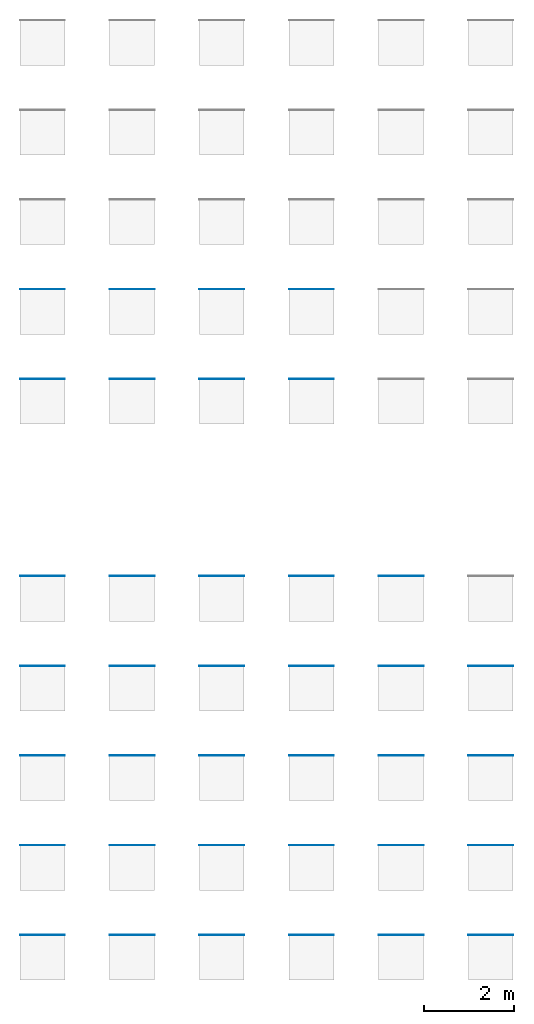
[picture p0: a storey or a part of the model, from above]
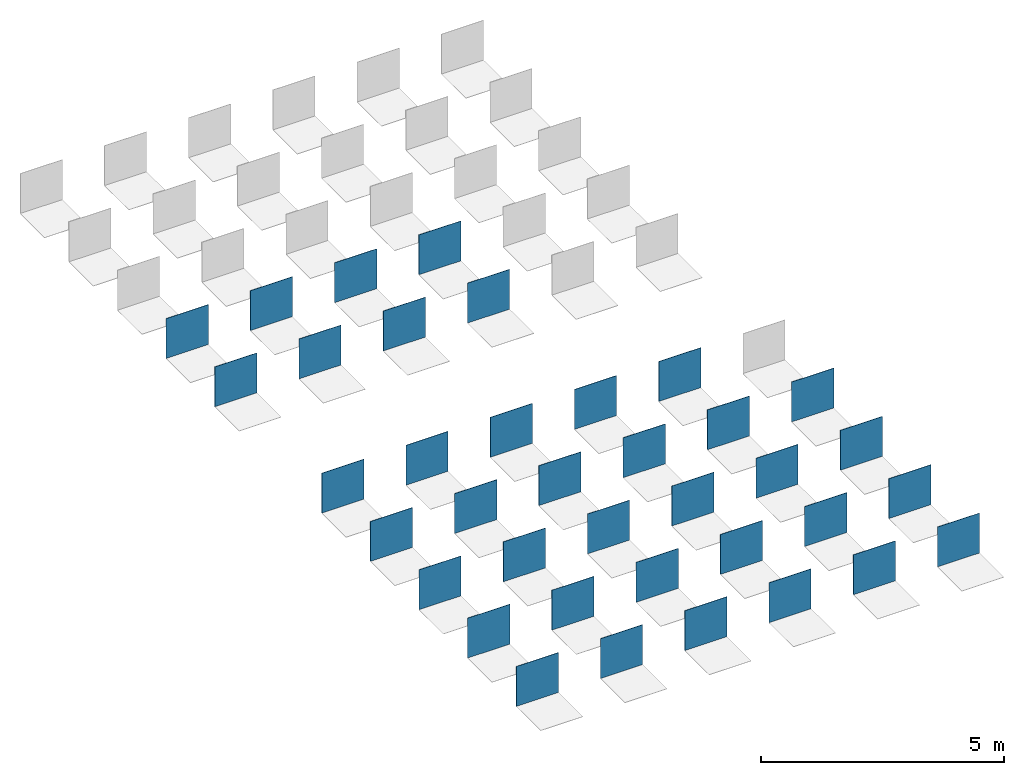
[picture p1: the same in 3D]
Properties of the parts of a building model (IFC2X3), part 1 of 8

# File
Description: ViewDefinition [CoordinationView_V2.0]
Time: 2025-06-20T14:48:53
Written by: The EXPRESS Data Manager Version 5.02.0100.07 : 28 Aug 2013
Made in: 21.1.90.15 - Exporter 21.1.90.15 - Alternate UI 21.1.90.15
Comment: STEP Physical File produced by: The EXPRESS Data Manager Version 5.02.0100.07 : 28 Aug 2013 * Module: EDMstepFileFactory/EDMstandAlone * Creation date: Fri Jun 20 14:48:53 2025 * Host: STB002 * Database: C:\Users\LARISS~1\AppData\Local\Temp\234e31d9-e186-458c-9206-d387dea7a233\94b8d80c-d76f-4e48-b2f8-2cca53b996f9\ifc * Database version: 5507 * Database creation date: Fri Jun 20 14:48:50 2025 * Schema: IFC2X3 * Model: DataRepository.ifc * Model creation date: Fri Jun 20 14:48:50 2025 * Header model: DataRepository.ifc_HeaderModel * Header model creation date: Fri Jun 20 14:48:50 2025 * EDMuser: sdai-user * EDMgroup: sdai-group * License ID and type: 5605 : Permanent license. Expiry date: * EDMstepFileFactory options: 020000

# IfcSite, Default
RefLatitude: 42, 24, 53, 508911; RefLongitude: -71, -15, -29, -58837; RefElevation: 0 mm
Pset_ProductRequirements - Category: Project Information

# IfcBuilding
Pset_BuildingCommon - NumberOfStoreys: 1
Pset_ProductRequirements - Category: Project Information

# IfcBuildingStorey: Level:Level 1, Level 1
LongName: Level 1; Elevation: 0 mm
Pset_AirSideSystemInformation - Name: Level 1
Pset_ProductRequirements - Name: Level 1; Category: Levels

# IfcCovering: Floor:REVIGRÉS-OMNISTONE-BASE-30X60-MATTRECT-BONE, Floor:REVIGRÉS-OMNISTONE-BASE-30X60-MATTRECT-BONE:146222
In: Level 1
Type - PredefinedType: CLADDING; Material: REVIGRÉS-OMNISTONE-BASE-30x60-MATTRECT-BONE 9.8 mm
Type - Pset_CoveringCommon - Reference: 312B2188U1; Material: Grés porcelânico
Type - Pset_ElementShading - Roughness: 304.8 mm
Type - Pset_ManufacturerTypeInformation - Manufacturer: REVIGRÉS
Type - Pset_ProductRequirements - Category: Floors
Type - Pset_QuantityTakeOff - Reference: 312B2188U1
Type - IFC.REVIGRÉS-Dados do fabricante-Floor Covering - FabricanteURL: https://www.revigres.pt/; ReferenciaModelo: Omnistone; NumeroGlobalDeItemComercial: 312B2188U1; Acabamento: MATT RECT; Material: Grés porcelânico; IdentificadorDoOperadorEconomico: 501840856; UrlFabricanteArtigo: https://www.revigres.pt/colecoes/omnistone; PaisOrigem: Portugal
Type - IFC.REVIGRÉS-Dados de desempenho-Floor Covering - Rectilinearidade: ± 0.2% máx.± 0.8 mm; Ortogonalidade: ± 0.2% máx.± 1.5 mm; PlanaridadeDaSuperficie: ± 0.3% máx. ± 1.8 mm; QualidadeDaSuperficie: Cumpre; AbsorcaoDeAgua: < 0.05%; ModuloDeRuptura: > 45 N/mm²; ResistenciaAFlexao: ≥ 3500 N; ResistenciaAAbrasaoProfunda: < 120 mm³; DilatacaoTermicaLinear: ≤ 8,0x10-6 °C-1; ResistenciaAoChoqueTermico: Resiste; DurabilidadeResistenciaAoGeloDegelo: Resiste; ResistenciaAoEscorregamentoDIN51130: R10; ResistenciaAoEscorregamentoDIN51097: B; ResistenciaAoEscorregamentoENV51097: B; ResistenciaAoEscorregamentoENV12633: Class 2; ResistenciaAoEscorregamentoBS7976: >36; ResistenciaAoEscorregamentoANSIA1371: ≥0,42; ResistenciaAoDeslizamentoENV12633: Class 2; ResistenciaAoDeslizamentoBS7976: >36; ResistenciaAsManchas: Class 5; ResistenciaABaixasConcentracoesDeAcidosEAlcalis: Classe LA; ResistenciaAAltasConcentracoesDeAcidosEAlcalis: Classe HA; LibertacaoDeCadmio: 0; LibertacaoDeChumbo: 0
Type - IFC.REVIGRÉS-Dados de especificação-Floor Covering - VariacaoTonalidade: 3; NivelDeTrafego: 5; EPavimento: Sim; ERevestimento: Sim; EExterno: Sim
Type - IFC.REVIGRÉS-Dados geométricos-Floor Covering - AlturaNominal: 9.8 mm; ComprimentoNominal: 29.5 mm; LarguraNominal: 59.2 mm
Type - IFC.REVIGRÉS-Dados de sustentabilidade-Floor Covering - ItemEParcialmenteReciclado: 0; EnergiaTermicaExportada: 0; ItemENovo: Sim; ItemEReciclado: Não; VidaÚtilEsperada: 50; SubstanciasPerigosas: Não; PotencialDeEsgotamentoAbioticoDosRecursosNaoFosseisMineraisEMetais: 0.000701; PotencialDeAquecimentoGlobalBiogenico: -0.48; CombustiveisFosseisComPotencialDeAquecimentoGlobal: 13.9; PotencialDeAquecimentoGlobalUsoDoSoloEMudancaDeUsoDoSolo: 0.0246; PotencialDeEutrofizacaoFraccaoDeNutrientesQueAtingemOCompartimentoFinalDeAguaDoce: 0.000189; PotencialDeEutrofizacaoFraccaoDeNutrientesQueAtingemOCompartimentoFinalMarinho: 0.0122; EnergiaRecuperada: 0.00739; ConsumoDeAguaDoce: 0.113; UtilizacaoLiquidaDeAguaDoce: 0.113; ResiduosPerigososEliminados: 0.00221; ResiduosNaoPerigososEliminados: 1.83; MassaTotalDeResiduosRadioactivosEliminados: 0.000394; EnergiaElectricaExportada: 1.55; MateriaisParaRecuperacaoDeEnergia: 0.00739; MateriaisParaReciclagem: 0.0253; UnidadeEPD: 1 m²
Type - IFC.REVIGRÉS-Dados gerais-Floor Covering - Nome: REVIGRÉS-OMNISTONE-BASE-30X60-MATT RECT-BONE; TipoProduto: Prensado a seco: grupo BIa UGL | Grés porcelânico técnico; NumeroDeRegistoDAP: EPD-REV-20240006-CCC1-EN; ReferenciaDAP: -; UrlDOP: -
Classification: C3020 (Uniformat)
Pset_CoveringCommon - TotalThickness: 9.8 mm
IFC.REVIGRÉS-Dados do fabricante-Floor Covering - Type: Floor: REVIGRÉS-OMNISTONE-BASE-30X60-MATTRECT-BONE
IFC.REVIGRÉS-Dados de desempenho-Floor Covering - Type: Floor: REVIGRÉS-OMNISTONE-BASE-30X60-MATTRECT-BONE
IFC.REVIGRÉS-Dados de especificação-Floor Covering - Type: Floor: REVIGRÉS-OMNISTONE-BASE-30X60-MATTRECT-BONE
IFC.REVIGRÉS-Dados geométricos-Floor Covering - Type: Floor: REVIGRÉS-OMNISTONE-BASE-30X60-MATTRECT-BONE
IFC.REVIGRÉS-Dados de sustentabilidade-Floor Covering - Type: Floor: REVIGRÉS-OMNISTONE-BASE-30X60-MATTRECT-BONE

# IfcCovering: Floor:REVIGRÉS-OMNISTONE-BASE-30X60-MATTRECT-ICE, Floor:REVIGRÉS-OMNISTONE-BASE-30X60-MATTRECT-ICE:148426
In: Level 1
Type - PredefinedType: CLADDING; Material: REVIGRÉS-OMNISTONE-BASE-30x60-MATTRECT-ICE 9.8 mm
Type - Pset_CoveringCommon - Reference: 312B2189U1; Material: Grés porcelânico
Type - Pset_ElementShading - Roughness: 304.8 mm
Type - Pset_ManufacturerTypeInformation - Manufacturer: REVIGRÉS
Type - Pset_ProductRequirements - Category: Floors
Type - Pset_QuantityTakeOff - Reference: 312B2189U1
Type - IFC.REVIGRÉS-Dados do fabricante-Floor Covering - FabricanteURL: https://www.revigres.pt/; ReferenciaModelo: Omnistone; NumeroGlobalDeItemComercial: 312B2189U1; Acabamento: MATT RECT; Material: Grés porcelânico; IdentificadorDoOperadorEconomico: 501840856; UrlFabricanteArtigo: https://www.revigres.pt/colecoes/omnistone; PaisOrigem: Portugal
Type - IFC.REVIGRÉS-Dados de desempenho-Floor Covering - Rectilinearidade: ± 0.2% máx.± 0.8 mm; Ortogonalidade: ± 0.2% máx.± 1.5 mm; PlanaridadeDaSuperficie: ± 0.3% máx. ± 1.8 mm; QualidadeDaSuperficie: Cumpre; AbsorcaoDeAgua: < 0.05%; ModuloDeRuptura: > 45 N/mm²; ResistenciaAFlexao: ≥ 3500 N; ResistenciaAAbrasaoProfunda: < 120 mm³; DilatacaoTermicaLinear: ≤ 8,0x10-6 °C-1; ResistenciaAoChoqueTermico: Resiste; DurabilidadeResistenciaAoGeloDegelo: Resiste; ResistenciaAoEscorregamentoDIN51130: R10; ResistenciaAoEscorregamentoDIN51097: B; ResistenciaAoEscorregamentoENV51097: B; ResistenciaAoEscorregamentoENV12633: Class 2; ResistenciaAoEscorregamentoBS7976: >36; ResistenciaAoEscorregamentoANSIA1371: ≥0,42; ResistenciaAoDeslizamentoENV12633: Class 2; ResistenciaAoDeslizamentoBS7976: >36; ResistenciaAsManchas: Class 5; ResistenciaABaixasConcentracoesDeAcidosEAlcalis: Classe LA; ResistenciaAAltasConcentracoesDeAcidosEAlcalis: Classe HA; LibertacaoDeCadmio: 0; LibertacaoDeChumbo: 0
Type - IFC.REVIGRÉS-Dados de especificação-Floor Covering - VariacaoTonalidade: 3; NivelDeTrafego: 5; EPavimento: Sim; ERevestimento: Sim; EExterno: Sim
Type - IFC.REVIGRÉS-Dados geométricos-Floor Covering - AlturaNominal: 9.8 mm; ComprimentoNominal: 29.5 mm; LarguraNominal: 59.2 mm
Type - IFC.REVIGRÉS-Dados de sustentabilidade-Floor Covering - ItemEParcialmenteReciclado: 0; EnergiaTermicaExportada: 0; ItemENovo: Sim; ItemEReciclado: Não; VidaÚtilEsperada: 50; SubstanciasPerigosas: Não; PotencialDeEsgotamentoAbioticoDosRecursosNaoFosseisMineraisEMetais: 0.000701; PotencialDeAquecimentoGlobalBiogenico: -0.48; CombustiveisFosseisComPotencialDeAquecimentoGlobal: 13.9; PotencialDeAquecimentoGlobalUsoDoSoloEMudancaDeUsoDoSolo: 0.0246; PotencialDeEutrofizacaoFraccaoDeNutrientesQueAtingemOCompartimentoFinalDeAguaDoce: 0.000189; PotencialDeEutrofizacaoFraccaoDeNutrientesQueAtingemOCompartimentoFinalMarinho: 0.0122; EnergiaRecuperada: 0.00739; ConsumoDeAguaDoce: 0.113; UtilizacaoLiquidaDeAguaDoce: 0.113; ResiduosPerigososEliminados: 0.00221; ResiduosNaoPerigososEliminados: 1.83; MassaTotalDeResiduosRadioactivosEliminados: 0.000394; EnergiaElectricaExportada: 1.55; MateriaisParaRecuperacaoDeEnergia: 0.00739; MateriaisParaReciclagem: 0.0253; UnidadeEPD: 1 m²
Type - IFC.REVIGRÉS-Dados gerais-Floor Covering - Nome: REVIGRÉS-OMNISTONE-BASE-30X60-MATT RECT-ICE; TipoProduto: Prensado a seco: grupo BIa UGL | Grés porcelânico técnico; NumeroDeRegistoDAP: EPD-REV-20240006-CCC1-EN; ReferenciaDAP: -; UrlDOP: -
Classification: C3020 (Uniformat)
Pset_CoveringCommon - TotalThickness: 9.8 mm
IFC.REVIGRÉS-Dados do fabricante-Floor Covering - Type: Floor: REVIGRÉS-OMNISTONE-BASE-30X60-MATTRECT-ICE
IFC.REVIGRÉS-Dados de desempenho-Floor Covering - Type: Floor: REVIGRÉS-OMNISTONE-BASE-30X60-MATTRECT-ICE
IFC.REVIGRÉS-Dados de especificação-Floor Covering - Type: Floor: REVIGRÉS-OMNISTONE-BASE-30X60-MATTRECT-ICE
IFC.REVIGRÉS-Dados geométricos-Floor Covering - Type: Floor: REVIGRÉS-OMNISTONE-BASE-30X60-MATTRECT-ICE
IFC.REVIGRÉS-Dados de sustentabilidade-Floor Covering - Type: Floor: REVIGRÉS-OMNISTONE-BASE-30X60-MATTRECT-ICE

# IfcCovering: Floor:REVIGRÉS-OMNISTONE-BASE-30X60-MATTRECT-IRON, Floor:REVIGRÉS-OMNISTONE-BASE-30X60-MATTRECT-IRON:149120
In: Level 1
Type - PredefinedType: CLADDING; Material: REVIGRÉS-OMNISTONE-BASE-30x60-MATTRECT-IRON 9.8 mm
Type - Pset_CoveringCommon - Reference: 312B2190U1; Material: Grés porcelânico
Type - Pset_ElementShading - Roughness: 304.8 mm
Type - Pset_ManufacturerTypeInformation - Manufacturer: REVIGRÉS
Type - Pset_ProductRequirements - Category: Floors
Type - Pset_QuantityTakeOff - Reference: 312B2190U1
Type - IFC.REVIGRÉS-Dados do fabricante-Floor Covering - FabricanteURL: https://www.revigres.pt/; ReferenciaModelo: Omnistone; NumeroGlobalDeItemComercial: 312B2190U1; Acabamento: MATT RECT; Material: Grés porcelânico; IdentificadorDoOperadorEconomico: 501840856; UrlFabricanteArtigo: https://www.revigres.pt/colecoes/omnistone; PaisOrigem: Portugal
Type - IFC.REVIGRÉS-Dados de desempenho-Floor Covering - Rectilinearidade: ± 0.2% máx.± 0.8 mm; Ortogonalidade: ± 0.2% máx.± 1.5 mm; PlanaridadeDaSuperficie: ± 0.3% máx. ± 1.8 mm; QualidadeDaSuperficie: Cumpre; AbsorcaoDeAgua: < 0.05%; ModuloDeRuptura: > 45 N/mm²; ResistenciaAFlexao: ≥ 3500 N; ResistenciaAAbrasaoProfunda: < 120 mm³; DilatacaoTermicaLinear: ≤ 8,0x10-6 °C-1; ResistenciaAoChoqueTermico: Resiste; DurabilidadeResistenciaAoGeloDegelo: Resiste; ResistenciaAoEscorregamentoDIN51130: R10; ResistenciaAoEscorregamentoDIN51097: B; ResistenciaAoEscorregamentoENV51097: B; ResistenciaAoEscorregamentoENV12633: Class 2; ResistenciaAoEscorregamentoBS7976: >36; ResistenciaAoEscorregamentoANSIA1371: ≥0,42; ResistenciaAoDeslizamentoENV12633: Class 2; ResistenciaAoDeslizamentoBS7976: >36; ResistenciaAsManchas: Class 5; ResistenciaABaixasConcentracoesDeAcidosEAlcalis: Classe LA; ResistenciaAAltasConcentracoesDeAcidosEAlcalis: Classe HA; LibertacaoDeCadmio: 0; LibertacaoDeChumbo: 0
Type - IFC.REVIGRÉS-Dados de especificação-Floor Covering - VariacaoTonalidade: 3; NivelDeTrafego: 5; EPavimento: Sim; ERevestimento: Sim; EExterno: Sim
Type - IFC.REVIGRÉS-Dados geométricos-Floor Covering - AlturaNominal: 9.8 mm; ComprimentoNominal: 29.5 mm; LarguraNominal: 59.2 mm
Type - IFC.REVIGRÉS-Dados de sustentabilidade-Floor Covering - EnergiaTermicaExportada: 0; ItemENovo: Sim; ItemEParcialmenteReciclado: 0.14; ItemEReciclado: Sim; VidaÚtilEsperada: 50; SubstanciasPerigosas: Não; PotencialDeEsgotamentoAbioticoDosRecursosNaoFosseisMineraisEMetais: 0.000701; PotencialDeAquecimentoGlobalBiogenico: -0.48; CombustiveisFosseisComPotencialDeAquecimentoGlobal: 13.9; PotencialDeAquecimentoGlobalUsoDoSoloEMudancaDeUsoDoSolo: 0.0246; PotencialDeEutrofizacaoFraccaoDeNutrientesQueAtingemOCompartimentoFinalDeAguaDoce: 0.000189; PotencialDeEutrofizacaoFraccaoDeNutrientesQueAtingemOCompartimentoFinalMarinho: 0.0122; EnergiaRecuperada: 0.00739; ConsumoDeAguaDoce: 0.113; UtilizacaoLiquidaDeAguaDoce: 0.113; ResiduosPerigososEliminados: 0.00221; ResiduosNaoPerigososEliminados: 1.83; MassaTotalDeResiduosRadioactivosEliminados: 0.000394; EnergiaElectricaExportada: 1.55; MateriaisParaRecuperacaoDeEnergia: 0.00739; MateriaisParaReciclagem: 0.0253; UnidadeEPD: 1 m²
Type - IFC.REVIGRÉS-Dados gerais-Floor Covering - Nome: REVIGRÉS-OMNISTONE-BASE-30X60-MATT RECT-IRON; TipoProduto: Prensado a seco: grupo BIa UGL | Grés porcelânico técnico; NumeroDeRegistoDAP: EPD-REV-20240006-CCC1-EN; ReferenciaDAP: -; UrlDOP: -
Classification: C3020 (Uniformat)
Pset_CoveringCommon - TotalThickness: 9.8 mm
IFC.REVIGRÉS-Dados do fabricante-Floor Covering - Type: Floor: REVIGRÉS-OMNISTONE-BASE-30X60-MATTRECT-IRON
IFC.REVIGRÉS-Dados de desempenho-Floor Covering - Type: Floor: REVIGRÉS-OMNISTONE-BASE-30X60-MATTRECT-IRON
IFC.REVIGRÉS-Dados de especificação-Floor Covering - Type: Floor: REVIGRÉS-OMNISTONE-BASE-30X60-MATTRECT-IRON
IFC.REVIGRÉS-Dados geométricos-Floor Covering - Type: Floor: REVIGRÉS-OMNISTONE-BASE-30X60-MATTRECT-IRON
IFC.REVIGRÉS-Dados de sustentabilidade-Floor Covering - Type: Floor: REVIGRÉS-OMNISTONE-BASE-30X60-MATTRECT-IRON

# IfcCovering: Floor:REVIGRÉS-OMNISTONE-BASE-30X60-MATTRECT-JET, Floor:REVIGRÉS-OMNISTONE-BASE-30X60-MATTRECT-JET:149862
In: Level 1
Type - PredefinedType: CLADDING; Material: REVIGRÉS-OMNISTONE-BASE-30x60-MATTRECT-JET 9.8 mm
Type - Pset_CoveringCommon - Reference: 312B2191U1; Material: Grés porcelânico
Type - Pset_ElementShading - Roughness: 304.8 mm
Type - Pset_ManufacturerTypeInformation - Manufacturer: REVIGRÉS
Type - Pset_ProductRequirements - Category: Floors
Type - Pset_QuantityTakeOff - Reference: 312B2191U1
Type - IFC.REVIGRÉS-Dados do fabricante-Floor Covering - FabricanteURL: https://www.revigres.pt/; ReferenciaModelo: Omnistone; NumeroGlobalDeItemComercial: 312B2191U1; Acabamento: MATT RECT; Material: Grés porcelânico; IdentificadorDoOperadorEconomico: 501840856; UrlFabricanteArtigo: https://www.revigres.pt/colecoes/omnistone; PaisOrigem: Portugal
Type - IFC.REVIGRÉS-Dados de desempenho-Floor Covering - Rectilinearidade: ± 0.2% máx.± 0.8 mm; Ortogonalidade: ± 0.2% máx.± 1.5 mm; PlanaridadeDaSuperficie: ± 0.3% máx. ± 1.8 mm; QualidadeDaSuperficie: Cumpre; AbsorcaoDeAgua: < 0.05%; ModuloDeRuptura: > 45 N/mm²; ResistenciaAFlexao: ≥ 3500 N; ResistenciaAAbrasaoProfunda: < 120 mm³; DilatacaoTermicaLinear: ≤ 8,0x10-6 °C-1; ResistenciaAoChoqueTermico: Resiste; DurabilidadeResistenciaAoGeloDegelo: Resiste; ResistenciaAoEscorregamentoDIN51130: R10; ResistenciaAoEscorregamentoDIN51097: B; ResistenciaAoEscorregamentoENV51097: B; ResistenciaAoEscorregamentoENV12633: Class 2; ResistenciaAoEscorregamentoBS7976: >36; ResistenciaAoEscorregamentoANSIA1371: ≥0,42; ResistenciaAoDeslizamentoENV12633: Class 2; ResistenciaAoDeslizamentoBS7976: >36; ResistenciaAsManchas: Class 5; ResistenciaABaixasConcentracoesDeAcidosEAlcalis: Classe LA; ResistenciaAAltasConcentracoesDeAcidosEAlcalis: Classe HA; LibertacaoDeCadmio: 0; LibertacaoDeChumbo: 0
Type - IFC.REVIGRÉS-Dados de especificação-Floor Covering - VariacaoTonalidade: 3; NivelDeTrafego: 5; EPavimento: Sim; ERevestimento: Sim; EExterno: Sim
Type - IFC.REVIGRÉS-Dados geométricos-Floor Covering - AlturaNominal: 9.8 mm; ComprimentoNominal: 29.5 mm; LarguraNominal: 59.2 mm
Type - IFC.REVIGRÉS-Dados de sustentabilidade-Floor Covering - ItemEParcialmenteReciclado: 0; EnergiaTermicaExportada: 0; ItemENovo: Sim; ItemEReciclado: Não; VidaÚtilEsperada: 50; SubstanciasPerigosas: Não; PotencialDeEsgotamentoAbioticoDosRecursosNaoFosseisMineraisEMetais: 0.000701; PotencialDeAquecimentoGlobalBiogenico: -0.48; CombustiveisFosseisComPotencialDeAquecimentoGlobal: 13.9; PotencialDeAquecimentoGlobalUsoDoSoloEMudancaDeUsoDoSolo: 0.0246; PotencialDeEutrofizacaoFraccaoDeNutrientesQueAtingemOCompartimentoFinalDeAguaDoce: 0.000189; PotencialDeEutrofizacaoFraccaoDeNutrientesQueAtingemOCompartimentoFinalMarinho: 0.0122; EnergiaRecuperada: 0.00739; ConsumoDeAguaDoce: 0.113; UtilizacaoLiquidaDeAguaDoce: 0.113; ResiduosPerigososEliminados: 0.00221; ResiduosNaoPerigososEliminados: 1.83; MassaTotalDeResiduosRadioactivosEliminados: 0.000394; EnergiaElectricaExportada: 1.55; MateriaisParaRecuperacaoDeEnergia: 0.00739; MateriaisParaReciclagem: 0.0253; UnidadeEPD: 1 m²
Type - IFC.REVIGRÉS-Dados gerais-Floor Covering - Nome: REVIGRÉS-OMNISTONE-BASE-30X60-MATT RECT-JET; TipoProduto: Prensado a seco: grupo BIa UGL | Grés porcelânico técnico; NumeroDeRegistoDAP: EPD-REV-20240006-CCC1-EN; ReferenciaDAP: -; UrlDOP: -
Classification: C3020 (Uniformat)
Pset_CoveringCommon - TotalThickness: 9.8 mm
IFC.REVIGRÉS-Dados do fabricante-Floor Covering - Type: Floor: REVIGRÉS-OMNISTONE-BASE-30X60-MATTRECT-JET
IFC.REVIGRÉS-Dados de desempenho-Floor Covering - Type: Floor: REVIGRÉS-OMNISTONE-BASE-30X60-MATTRECT-JET
IFC.REVIGRÉS-Dados de especificação-Floor Covering - Type: Floor: REVIGRÉS-OMNISTONE-BASE-30X60-MATTRECT-JET
IFC.REVIGRÉS-Dados geométricos-Floor Covering - Type: Floor: REVIGRÉS-OMNISTONE-BASE-30X60-MATTRECT-JET
IFC.REVIGRÉS-Dados de sustentabilidade-Floor Covering - Type: Floor: REVIGRÉS-OMNISTONE-BASE-30X60-MATTRECT-JET

# IfcCovering: Floor:REVIGRÉS-OMNISTONE-BASE-30X60-MATTRECT-PLATINA, Floor:REVIGRÉS-OMNISTONE-BASE-30X60-MATTRECT-PLATINA:150583
In: Level 1
Type - PredefinedType: CLADDING; Material: REVIGRÉS-OMNISTONE-BASE-30x60-MATTRECT-PLATINA 9.8 mm
Type - Pset_CoveringCommon - Reference: 312B2192U1; Material: Grés porcelânico
Type - Pset_ElementShading - Roughness: 304.8 mm
Type - Pset_ManufacturerTypeInformation - Manufacturer: REVIGRÉS
Type - Pset_ProductRequirements - Category: Floors
Type - Pset_QuantityTakeOff - Reference: 312B2192U1
Type - IFC.REVIGRÉS-Dados do fabricante-Floor Covering - FabricanteURL: https://www.revigres.pt/; ReferenciaModelo: Omnistone; NumeroGlobalDeItemComercial: 312B2192U1; Acabamento: MATT RECT; Material: Grés porcelânico; IdentificadorDoOperadorEconomico: 501840856; UrlFabricanteArtigo: https://www.revigres.pt/colecoes/omnistone; PaisOrigem: Portugal
Type - IFC.REVIGRÉS-Dados de desempenho-Floor Covering - Rectilinearidade: ± 0.2% máx.± 0.8 mm; Ortogonalidade: ± 0.2% máx.± 1.5 mm; PlanaridadeDaSuperficie: ± 0.3% máx. ± 1.8 mm; QualidadeDaSuperficie: Cumpre; AbsorcaoDeAgua: < 0.05%; ModuloDeRuptura: > 45 N/mm²; ResistenciaAFlexao: ≥ 3500 N; ResistenciaAAbrasaoProfunda: < 120 mm³; DilatacaoTermicaLinear: ≤ 8,0x10-6 °C-1; ResistenciaAoChoqueTermico: Resiste; DurabilidadeResistenciaAoGeloDegelo: Resiste; ResistenciaAoEscorregamentoDIN51130: R10; ResistenciaAoEscorregamentoDIN51097: B; ResistenciaAoEscorregamentoENV51097: B; ResistenciaAoEscorregamentoENV12633: Class 2; ResistenciaAoEscorregamentoBS7976: >36; ResistenciaAoEscorregamentoANSIA1371: ≥0,42; ResistenciaAoDeslizamentoENV12633: Class 2; ResistenciaAoDeslizamentoBS7976: >36; ResistenciaAsManchas: Class 5; ResistenciaABaixasConcentracoesDeAcidosEAlcalis: Classe LA; ResistenciaAAltasConcentracoesDeAcidosEAlcalis: Classe HA; LibertacaoDeCadmio: 0; LibertacaoDeChumbo: 0
Type - IFC.REVIGRÉS-Dados de especificação-Floor Covering - VariacaoTonalidade: 3; NivelDeTrafego: 5; EPavimento: Sim; ERevestimento: Sim; EExterno: Sim
Type - IFC.REVIGRÉS-Dados geométricos-Floor Covering - AlturaNominal: 9.8 mm; ComprimentoNominal: 29.5 mm; LarguraNominal: 59.2 mm
Type - IFC.REVIGRÉS-Dados de sustentabilidade-Floor Covering - ItemEParcialmenteReciclado: 0; EnergiaTermicaExportada: 0; ItemENovo: Sim; ItemEReciclado: Não; VidaÚtilEsperada: 50; SubstanciasPerigosas: Não; PotencialDeEsgotamentoAbioticoDosRecursosNaoFosseisMineraisEMetais: 0.000701; PotencialDeAquecimentoGlobalBiogenico: -0.48; CombustiveisFosseisComPotencialDeAquecimentoGlobal: 13.9; PotencialDeAquecimentoGlobalUsoDoSoloEMudancaDeUsoDoSolo: 0.0246; PotencialDeEutrofizacaoFraccaoDeNutrientesQueAtingemOCompartimentoFinalDeAguaDoce: 0.000189; PotencialDeEutrofizacaoFraccaoDeNutrientesQueAtingemOCompartimentoFinalMarinho: 0.0122; EnergiaRecuperada: 0.00739; ConsumoDeAguaDoce: 0.113; UtilizacaoLiquidaDeAguaDoce: 0.113; ResiduosPerigososEliminados: 0.00221; ResiduosNaoPerigososEliminados: 1.83; MassaTotalDeResiduosRadioactivosEliminados: 0.000394; EnergiaElectricaExportada: 1.55; MateriaisParaRecuperacaoDeEnergia: 0.00739; MateriaisParaReciclagem: 0.0253; UnidadeEPD: 1 m²
Type - IFC.REVIGRÉS-Dados gerais-Floor Covering - Nome: REVIGRÉS-OMNISTONE-BASE-30X60-MATT RECT-PLATINA; TipoProduto: Prensado a seco: grupo BIa UGL | Grés porcelânico técnico; NumeroDeRegistoDAP: EPD-REV-20240006-CCC1-EN; ReferenciaDAP: -; UrlDOP: -
Classification: C3020 (Uniformat)
Pset_CoveringCommon - TotalThickness: 9.8 mm
IFC.REVIGRÉS-Dados do fabricante-Floor Covering - Type: Floor: REVIGRÉS-OMNISTONE-BASE-30X60-MATTRECT-PLATINA
IFC.REVIGRÉS-Dados de desempenho-Floor Covering - Type: Floor: REVIGRÉS-OMNISTONE-BASE-30X60-MATTRECT-PLATINA
IFC.REVIGRÉS-Dados de especificação-Floor Covering - Type: Floor: REVIGRÉS-OMNISTONE-BASE-30X60-MATTRECT-PLATINA
IFC.REVIGRÉS-Dados geométricos-Floor Covering - Type: Floor: REVIGRÉS-OMNISTONE-BASE-30X60-MATTRECT-PLATINA
IFC.REVIGRÉS-Dados de sustentabilidade-Floor Covering - Type: Floor: REVIGRÉS-OMNISTONE-BASE-30X60-MATTRECT-PLATINA

# IfcCovering: Floor:REVIGRÉS-OMNISTONE-BASE-30X60-MATTRECT-ROPE, Floor:REVIGRÉS-OMNISTONE-BASE-30X60-MATTRECT-ROPE:151288
In: Level 1
Type - PredefinedType: CLADDING; Material: REVIGRÉS-OMNISTONE-BASE-30x60-MATTRECT-ROPE 9.8 mm
Type - Pset_CoveringCommon - Reference: 312B2193U1; Material: Grés porcelânico
Type - Pset_ElementShading - Roughness: 304.8 mm
Type - Pset_ManufacturerTypeInformation - Manufacturer: REVIGRÉS
Type - Pset_ProductRequirements - Category: Floors
Type - Pset_QuantityTakeOff - Reference: 312B2193U1
Type - IFC.REVIGRÉS-Dados do fabricante-Floor Covering - FabricanteURL: https://www.revigres.pt/; ReferenciaModelo: Omnistone; NumeroGlobalDeItemComercial: 312B2193U1; Acabamento: MATT RECT; Material: Grés porcelânico; IdentificadorDoOperadorEconomico: 501840856; UrlFabricanteArtigo: https://www.revigres.pt/colecoes/omnistone; PaisOrigem: Portugal
Type - IFC.REVIGRÉS-Dados de desempenho-Floor Covering - Rectilinearidade: ± 0.2% máx.± 0.8 mm; Ortogonalidade: ± 0.2% máx.± 1.5 mm; PlanaridadeDaSuperficie: ± 0.3% máx. ± 1.8 mm; QualidadeDaSuperficie: Cumpre; AbsorcaoDeAgua: < 0.05%; ModuloDeRuptura: > 45 N/mm²; ResistenciaAFlexao: ≥ 3500 N; ResistenciaAAbrasaoProfunda: < 120 mm³; DilatacaoTermicaLinear: ≤ 8,0x10-6 °C-1; ResistenciaAoChoqueTermico: Resiste; DurabilidadeResistenciaAoGeloDegelo: Resiste; ResistenciaAoEscorregamentoDIN51130: R10; ResistenciaAoEscorregamentoDIN51097: B; ResistenciaAoEscorregamentoENV51097: B; ResistenciaAoEscorregamentoENV12633: Class 2; ResistenciaAoEscorregamentoBS7976: >36; ResistenciaAoEscorregamentoANSIA1371: ≥0,42; ResistenciaAoDeslizamentoENV12633: Class 2; ResistenciaAoDeslizamentoBS7976: >36; ResistenciaAsManchas: Class 5; ResistenciaABaixasConcentracoesDeAcidosEAlcalis: Classe LA; ResistenciaAAltasConcentracoesDeAcidosEAlcalis: Classe HA; LibertacaoDeCadmio: 0; LibertacaoDeChumbo: 0
Type - IFC.REVIGRÉS-Dados de especificação-Floor Covering - VariacaoTonalidade: 3; NivelDeTrafego: 5; EPavimento: Sim; ERevestimento: Sim; EExterno: Sim
Type - IFC.REVIGRÉS-Dados geométricos-Floor Covering - AlturaNominal: 9.8 mm; ComprimentoNominal: 29.5 mm; LarguraNominal: 59.2 mm
Type - IFC.REVIGRÉS-Dados de sustentabilidade-Floor Covering - ItemEParcialmenteReciclado: 0; EnergiaTermicaExportada: 0; ItemENovo: Sim; ItemEReciclado: Não; VidaÚtilEsperada: 50; SubstanciasPerigosas: Não; PotencialDeEsgotamentoAbioticoDosRecursosNaoFosseisMineraisEMetais: 0.000701; PotencialDeAquecimentoGlobalBiogenico: -0.48; CombustiveisFosseisComPotencialDeAquecimentoGlobal: 13.9; PotencialDeAquecimentoGlobalUsoDoSoloEMudancaDeUsoDoSolo: 0.0246; PotencialDeEutrofizacaoFraccaoDeNutrientesQueAtingemOCompartimentoFinalDeAguaDoce: 0.000189; PotencialDeEutrofizacaoFraccaoDeNutrientesQueAtingemOCompartimentoFinalMarinho: 0.0122; EnergiaRecuperada: 0.00739; ConsumoDeAguaDoce: 0.113; UtilizacaoLiquidaDeAguaDoce: 0.113; ResiduosPerigososEliminados: 0.00221; ResiduosNaoPerigososEliminados: 1.83; MassaTotalDeResiduosRadioactivosEliminados: 0.000394; EnergiaElectricaExportada: 1.55; MateriaisParaRecuperacaoDeEnergia: 0.00739; MateriaisParaReciclagem: 0.0253; UnidadeEPD: 1 m²
Type - IFC.REVIGRÉS-Dados gerais-Floor Covering - Nome: REVIGRÉS-OMNISTONE-BASE-30X60-MATT RECT-ROPE; TipoProduto: Prensado a seco: grupo BIa UGL | Grés porcelânico técnico; NumeroDeRegistoDAP: EPD-REV-20240006-CCC1-EN; ReferenciaDAP: -; UrlDOP: -
Classification: C3020 (Uniformat)
Pset_CoveringCommon - TotalThickness: 9.8 mm
IFC.REVIGRÉS-Dados do fabricante-Floor Covering - Type: Floor: REVIGRÉS-OMNISTONE-BASE-30X60-MATTRECT-ROPE
IFC.REVIGRÉS-Dados de desempenho-Floor Covering - Type: Floor: REVIGRÉS-OMNISTONE-BASE-30X60-MATTRECT-ROPE
IFC.REVIGRÉS-Dados de especificação-Floor Covering - Type: Floor: REVIGRÉS-OMNISTONE-BASE-30X60-MATTRECT-ROPE
IFC.REVIGRÉS-Dados geométricos-Floor Covering - Type: Floor: REVIGRÉS-OMNISTONE-BASE-30X60-MATTRECT-ROPE
IFC.REVIGRÉS-Dados de sustentabilidade-Floor Covering - Type: Floor: REVIGRÉS-OMNISTONE-BASE-30X60-MATTRECT-ROPE

# IfcCovering: Floor:REVIGRÉS-OMNISTONE-BASE-30X60-SOFT-BONE, Floor:REVIGRÉS-OMNISTONE-BASE-30X60-SOFT-BONE:146506
In: Level 1
Type - PredefinedType: CLADDING; Material: REVIGRÉS-OMNISTONE-BASE-30x60-SOFT-BONE 9.8 mm
Type - Pset_CoveringCommon - Reference: 31262188U1; Material: Grés porcelânico
Type - Pset_ElementShading - Roughness: 304.8 mm
Type - Pset_ManufacturerTypeInformation - Manufacturer: REVIGRÉS
Type - Pset_ProductRequirements - Category: Floors
Type - Pset_QuantityTakeOff - Reference: 31262188U1
Type - IFC.REVIGRÉS-Dados do fabricante-Floor Covering - FabricanteURL: https://www.revigres.pt/; ReferenciaModelo: Omnistone; NumeroGlobalDeItemComercial: 31262188U1; Acabamento: SOFT; Material: Grés porcelânico; IdentificadorDoOperadorEconomico: 501840856; UrlFabricanteArtigo: https://www.revigres.pt/colecoes/omnistone; PaisOrigem: Portugal
Type - IFC.REVIGRÉS-Dados de desempenho-Floor Covering - Rectilinearidade: ± 0.2% máx.± 0.8 mm; Ortogonalidade: ± 0.2% máx.± 1.5 mm; PlanaridadeDaSuperficie: ± 0.3% máx. ± 1.8 mm; QualidadeDaSuperficie: Cumpre; AbsorcaoDeAgua: < 0.05%; ModuloDeRuptura: > 45 N/mm²; ResistenciaAFlexao: ≥ 3500 N; ResistenciaAAbrasaoProfunda: < 120 mm³; DilatacaoTermicaLinear: ≤ 8,0x10-6 °C-1; ResistenciaAoChoqueTermico: Resiste; DurabilidadeResistenciaAoGeloDegelo: Resiste; ResistenciaAsManchas: Class 5; ResistenciaABaixasConcentracoesDeAcidosEAlcalis: Classe LA; ResistenciaAAltasConcentracoesDeAcidosEAlcalis: Classe HA; LibertacaoDeCadmio: 0; LibertacaoDeChumbo: 0
Type - IFC.REVIGRÉS-Dados de especificação-Floor Covering - VariacaoTonalidade: 3; NivelDeTrafego: 5; EPavimento: Sim; ERevestimento: Sim; EExterno: Sim
Type - IFC.REVIGRÉS-Dados geométricos-Floor Covering - AlturaNominal: 9.8 mm; ComprimentoNominal: 29.5 mm; LarguraNominal: 59.2 mm
Type - IFC.REVIGRÉS-Dados de sustentabilidade-Floor Covering - ItemEParcialmenteReciclado: 0; EnergiaTermicaExportada: 0; ItemENovo: Sim; ItemEReciclado: Não; VidaÚtilEsperada: 50; SubstanciasPerigosas: Não; PotencialDeEsgotamentoAbioticoDosRecursosNaoFosseisMineraisEMetais: 0.000701; PotencialDeAquecimentoGlobalBiogenico: -0.48; CombustiveisFosseisComPotencialDeAquecimentoGlobal: 13.9; PotencialDeAquecimentoGlobalUsoDoSoloEMudancaDeUsoDoSolo: 0.0246; PotencialDeEutrofizacaoFraccaoDeNutrientesQueAtingemOCompartimentoFinalDeAguaDoce: 0.000189; PotencialDeEutrofizacaoFraccaoDeNutrientesQueAtingemOCompartimentoFinalMarinho: 0.0122; EnergiaRecuperada: 0.00739; ConsumoDeAguaDoce: 0.113; UtilizacaoLiquidaDeAguaDoce: 0.113; ResiduosPerigososEliminados: 0.00221; ResiduosNaoPerigososEliminados: 1.83; MassaTotalDeResiduosRadioactivosEliminados: 0.000394; EnergiaElectricaExportada: 1.55; MateriaisParaRecuperacaoDeEnergia: 0.00739; MateriaisParaReciclagem: 0.0253; UnidadeEPD: 1 m²
Type - IFC.REVIGRÉS-Dados gerais-Floor Covering - Nome: REVIGRÉS-OMNISTONE-BASE-30X60-SOFT-BONE; TipoProduto: Prensado a seco: grupo BIa UGL | Grés porcelânico técnico; NumeroDeRegistoDAP: EPD-REV-20240006-CCC1-EN; ReferenciaDAP: -; UrlDOP: -
Classification: C3020 (Uniformat)
Pset_CoveringCommon - TotalThickness: 9.8 mm
IFC.REVIGRÉS-Dados do fabricante-Floor Covering - Type: Floor: REVIGRÉS-OMNISTONE-BASE-30X60-SOFT-BONE
IFC.REVIGRÉS-Dados de desempenho-Floor Covering - Type: Floor: REVIGRÉS-OMNISTONE-BASE-30X60-SOFT-BONE
IFC.REVIGRÉS-Dados de especificação-Floor Covering - Type: Floor: REVIGRÉS-OMNISTONE-BASE-30X60-SOFT-BONE
IFC.REVIGRÉS-Dados geométricos-Floor Covering - Type: Floor: REVIGRÉS-OMNISTONE-BASE-30X60-SOFT-BONE
IFC.REVIGRÉS-Dados de sustentabilidade-Floor Covering - Type: Floor: REVIGRÉS-OMNISTONE-BASE-30X60-SOFT-BONE

# IfcCovering: Floor:REVIGRÉS-OMNISTONE-BASE-30X60-SOFT-ICE, Floor:REVIGRÉS-OMNISTONE-BASE-30X60-SOFT-ICE:148515
In: Level 1
Type - PredefinedType: CLADDING; Material: REVIGRÉS-OMNISTONE-BASE-30x60-SOFT-ICE 9.8 mm
Type - Pset_CoveringCommon - Reference: 31262189U1; Material: Grés porcelânico
Type - Pset_ElementShading - Roughness: 304.8 mm
Type - Pset_ManufacturerTypeInformation - Manufacturer: REVIGRÉS
Type - Pset_ProductRequirements - Category: Floors
Type - Pset_QuantityTakeOff - Reference: 31262189U1
Type - IFC.REVIGRÉS-Dados do fabricante-Floor Covering - FabricanteURL: https://www.revigres.pt/; ReferenciaModelo: Omnistone; NumeroGlobalDeItemComercial: 31262189U1; Acabamento: SOFT; Material: Grés porcelânico; IdentificadorDoOperadorEconomico: 501840856; UrlFabricanteArtigo: https://www.revigres.pt/colecoes/omnistone; PaisOrigem: Portugal
Type - IFC.REVIGRÉS-Dados de desempenho-Floor Covering - Rectilinearidade: ± 0.2% máx.± 0.8 mm; Ortogonalidade: ± 0.2% máx.± 1.5 mm; PlanaridadeDaSuperficie: ± 0.3% máx. ± 1.8 mm; QualidadeDaSuperficie: Cumpre; AbsorcaoDeAgua: < 0.05%; ModuloDeRuptura: > 45 N/mm²; ResistenciaAFlexao: ≥ 3500 N; ResistenciaAAbrasaoProfunda: < 120 mm³; DilatacaoTermicaLinear: ≤ 8,0x10-6 °C-1; ResistenciaAoChoqueTermico: Resiste; DurabilidadeResistenciaAoGeloDegelo: Resiste; ResistenciaAsManchas: Class 5; ResistenciaABaixasConcentracoesDeAcidosEAlcalis: Classe LA; ResistenciaAAltasConcentracoesDeAcidosEAlcalis: Classe HA; LibertacaoDeCadmio: 0; LibertacaoDeChumbo: 0
Type - IFC.REVIGRÉS-Dados de especificação-Floor Covering - VariacaoTonalidade: 3; NivelDeTrafego: 5; EPavimento: Sim; ERevestimento: Sim; EExterno: Sim
Type - IFC.REVIGRÉS-Dados geométricos-Floor Covering - AlturaNominal: 9.8 mm; ComprimentoNominal: 29.5 mm; LarguraNominal: 59.2 mm
Type - IFC.REVIGRÉS-Dados de sustentabilidade-Floor Covering - ItemEParcialmenteReciclado: 0; EnergiaTermicaExportada: 0; ItemENovo: Sim; ItemEReciclado: Não; VidaÚtilEsperada: 50; SubstanciasPerigosas: Não; PotencialDeEsgotamentoAbioticoDosRecursosNaoFosseisMineraisEMetais: 0.000701; PotencialDeAquecimentoGlobalBiogenico: -0.48; CombustiveisFosseisComPotencialDeAquecimentoGlobal: 13.9; PotencialDeAquecimentoGlobalUsoDoSoloEMudancaDeUsoDoSolo: 0.0246; PotencialDeEutrofizacaoFraccaoDeNutrientesQueAtingemOCompartimentoFinalDeAguaDoce: 0.000189; PotencialDeEutrofizacaoFraccaoDeNutrientesQueAtingemOCompartimentoFinalMarinho: 0.0122; EnergiaRecuperada: 0.00739; ConsumoDeAguaDoce: 0.113; UtilizacaoLiquidaDeAguaDoce: 0.113; ResiduosPerigososEliminados: 0.00221; ResiduosNaoPerigososEliminados: 1.83; MassaTotalDeResiduosRadioactivosEliminados: 0.000394; EnergiaElectricaExportada: 1.55; MateriaisParaRecuperacaoDeEnergia: 0.00739; MateriaisParaReciclagem: 0.0253; UnidadeEPD: 1 m²
Type - IFC.REVIGRÉS-Dados gerais-Floor Covering - Nome: REVIGRÉS-OMNISTONE-BASE-30X60-SOFT-ICE; TipoProduto: Prensado a seco: grupo BIa UGL | Grés porcelânico técnico; NumeroDeRegistoDAP: EPD-REV-20240006-CCC1-EN; ReferenciaDAP: -; UrlDOP: -
Classification: C3020 (Uniformat)
Pset_CoveringCommon - TotalThickness: 9.8 mm
IFC.REVIGRÉS-Dados do fabricante-Floor Covering - Type: Floor: REVIGRÉS-OMNISTONE-BASE-30X60-SOFT-ICE
IFC.REVIGRÉS-Dados de desempenho-Floor Covering - Type: Floor: REVIGRÉS-OMNISTONE-BASE-30X60-SOFT-ICE
IFC.REVIGRÉS-Dados de especificação-Floor Covering - Type: Floor: REVIGRÉS-OMNISTONE-BASE-30X60-SOFT-ICE
IFC.REVIGRÉS-Dados geométricos-Floor Covering - Type: Floor: REVIGRÉS-OMNISTONE-BASE-30X60-SOFT-ICE
IFC.REVIGRÉS-Dados de sustentabilidade-Floor Covering - Type: Floor: REVIGRÉS-OMNISTONE-BASE-30X60-SOFT-ICE

# IfcCovering: Floor:REVIGRÉS-OMNISTONE-BASE-30X60-SOFT-IRON, Floor:REVIGRÉS-OMNISTONE-BASE-30X60-SOFT-IRON:149200
In: Level 1
Type - PredefinedType: CLADDING; Material: REVIGRÉS-OMNISTONE-BASE-30x60-SOFT-IRON 9.8 mm
Type - Pset_CoveringCommon - Reference: 31262190U1; Material: Grés porcelânico
Type - Pset_ElementShading - Roughness: 304.8 mm
Type - Pset_ManufacturerTypeInformation - Manufacturer: REVIGRÉS
Type - Pset_ProductRequirements - Category: Floors
Type - Pset_QuantityTakeOff - Reference: 31262190U1
Type - IFC.REVIGRÉS-Dados do fabricante-Floor Covering - FabricanteURL: https://www.revigres.pt/; ReferenciaModelo: Omnistone; NumeroGlobalDeItemComercial: 31262190U1; Acabamento: SOFT; Material: Grés porcelânico; IdentificadorDoOperadorEconomico: 501840856; UrlFabricanteArtigo: https://www.revigres.pt/colecoes/omnistone; PaisOrigem: Portugal
Type - IFC.REVIGRÉS-Dados de desempenho-Floor Covering - Rectilinearidade: ± 0.2% máx.± 0.8 mm; Ortogonalidade: ± 0.2% máx.± 1.5 mm; PlanaridadeDaSuperficie: ± 0.3% máx. ± 1.8 mm; QualidadeDaSuperficie: Cumpre; AbsorcaoDeAgua: < 0.05%; ModuloDeRuptura: > 45 N/mm²; ResistenciaAFlexao: ≥ 3500 N; ResistenciaAAbrasaoProfunda: < 120 mm³; DilatacaoTermicaLinear: ≤ 8,0x10-6 °C-1; ResistenciaAoChoqueTermico: Resiste; DurabilidadeResistenciaAoGeloDegelo: Resiste; ResistenciaAsManchas: Class 5; ResistenciaABaixasConcentracoesDeAcidosEAlcalis: Classe LA; ResistenciaAAltasConcentracoesDeAcidosEAlcalis: Classe HA; LibertacaoDeCadmio: 0; LibertacaoDeChumbo: 0
Type - IFC.REVIGRÉS-Dados de especificação-Floor Covering - VariacaoTonalidade: 3; NivelDeTrafego: 5; EPavimento: Sim; ERevestimento: Sim; EExterno: Sim
Type - IFC.REVIGRÉS-Dados geométricos-Floor Covering - AlturaNominal: 9.8 mm; ComprimentoNominal: 29.5 mm; LarguraNominal: 59.2 mm
Type - IFC.REVIGRÉS-Dados de sustentabilidade-Floor Covering - EnergiaTermicaExportada: 0; ItemENovo: Sim; ItemEParcialmenteReciclado: 0.14; ItemEReciclado: Sim; VidaÚtilEsperada: 50; SubstanciasPerigosas: Não; PotencialDeEsgotamentoAbioticoDosRecursosNaoFosseisMineraisEMetais: 0.000701; PotencialDeAquecimentoGlobalBiogenico: -0.48; CombustiveisFosseisComPotencialDeAquecimentoGlobal: 13.9; PotencialDeAquecimentoGlobalUsoDoSoloEMudancaDeUsoDoSolo: 0.0246; PotencialDeEutrofizacaoFraccaoDeNutrientesQueAtingemOCompartimentoFinalDeAguaDoce: 0.000189; PotencialDeEutrofizacaoFraccaoDeNutrientesQueAtingemOCompartimentoFinalMarinho: 0.0122; EnergiaRecuperada: 0.00739; ConsumoDeAguaDoce: 0.113; UtilizacaoLiquidaDeAguaDoce: 0.113; ResiduosPerigososEliminados: 0.00221; ResiduosNaoPerigososEliminados: 1.83; MassaTotalDeResiduosRadioactivosEliminados: 0.000394; EnergiaElectricaExportada: 1.55; MateriaisParaRecuperacaoDeEnergia: 0.00739; MateriaisParaReciclagem: 0.0253; UnidadeEPD: 1 m²
Type - IFC.REVIGRÉS-Dados gerais-Floor Covering - Nome: REVIGRÉS-OMNISTONE-BASE-30X60-SOFT-IRON; TipoProduto: Prensado a seco: grupo BIa UGL | Grés porcelânico técnico; NumeroDeRegistoDAP: EPD-REV-20240006-CCC1-EN; ReferenciaDAP: -; UrlDOP: -
Classification: C3020 (Uniformat)
Pset_CoveringCommon - TotalThickness: 9.8 mm
IFC.REVIGRÉS-Dados do fabricante-Floor Covering - Type: Floor: REVIGRÉS-OMNISTONE-BASE-30X60-SOFT-IRON
IFC.REVIGRÉS-Dados de desempenho-Floor Covering - Type: Floor: REVIGRÉS-OMNISTONE-BASE-30X60-SOFT-IRON
IFC.REVIGRÉS-Dados de especificação-Floor Covering - Type: Floor: REVIGRÉS-OMNISTONE-BASE-30X60-SOFT-IRON
IFC.REVIGRÉS-Dados geométricos-Floor Covering - Type: Floor: REVIGRÉS-OMNISTONE-BASE-30X60-SOFT-IRON
IFC.REVIGRÉS-Dados de sustentabilidade-Floor Covering - Type: Floor: REVIGRÉS-OMNISTONE-BASE-30X60-SOFT-IRON

# IfcCovering: Floor:REVIGRÉS-OMNISTONE-BASE-30X60-SOFT-JET, Floor:REVIGRÉS-OMNISTONE-BASE-30X60-SOFT-JET:149942
In: Level 1
Type - PredefinedType: CLADDING; Material: REVIGRÉS-OMNISTONE-BASE-30x60-SOFT-JET 9.8 mm
Type - Pset_CoveringCommon - Reference: 31262191U1; Material: Grés porcelânico
Type - Pset_ElementShading - Roughness: 304.8 mm
Type - Pset_ManufacturerTypeInformation - Manufacturer: REVIGRÉS
Type - Pset_ProductRequirements - Category: Floors
Type - Pset_QuantityTakeOff - Reference: 31262191U1
Type - IFC.REVIGRÉS-Dados do fabricante-Floor Covering - FabricanteURL: https://www.revigres.pt/; ReferenciaModelo: Omnistone; NumeroGlobalDeItemComercial: 31262191U1; Acabamento: SOFT; Material: Grés porcelânico; IdentificadorDoOperadorEconomico: 501840856; UrlFabricanteArtigo: https://www.revigres.pt/colecoes/omnistone; PaisOrigem: Portugal
Type - IFC.REVIGRÉS-Dados de desempenho-Floor Covering - Rectilinearidade: ± 0.2% máx.± 0.8 mm; Ortogonalidade: ± 0.2% máx.± 1.5 mm; PlanaridadeDaSuperficie: ± 0.3% máx. ± 1.8 mm; QualidadeDaSuperficie: Cumpre; AbsorcaoDeAgua: < 0.05%; ModuloDeRuptura: > 45 N/mm²; ResistenciaAFlexao: ≥ 3500 N; ResistenciaAAbrasaoProfunda: < 120 mm³; DilatacaoTermicaLinear: ≤ 8,0x10-6 °C-1; ResistenciaAoChoqueTermico: Resiste; DurabilidadeResistenciaAoGeloDegelo: Resiste; ResistenciaAsManchas: Class 5; ResistenciaABaixasConcentracoesDeAcidosEAlcalis: Classe LA; ResistenciaAAltasConcentracoesDeAcidosEAlcalis: Classe HA; LibertacaoDeCadmio: 0; LibertacaoDeChumbo: 0
Type - IFC.REVIGRÉS-Dados de especificação-Floor Covering - VariacaoTonalidade: 3; NivelDeTrafego: 5; EPavimento: Sim; ERevestimento: Sim; EExterno: Sim
Type - IFC.REVIGRÉS-Dados geométricos-Floor Covering - AlturaNominal: 9.8 mm; ComprimentoNominal: 29.5 mm; LarguraNominal: 59.2 mm
Type - IFC.REVIGRÉS-Dados de sustentabilidade-Floor Covering - ItemEParcialmenteReciclado: 0; EnergiaTermicaExportada: 0; ItemENovo: Sim; ItemEReciclado: Não; VidaÚtilEsperada: 50; SubstanciasPerigosas: Não; PotencialDeEsgotamentoAbioticoDosRecursosNaoFosseisMineraisEMetais: 0.000701; PotencialDeAquecimentoGlobalBiogenico: -0.48; CombustiveisFosseisComPotencialDeAquecimentoGlobal: 13.9; PotencialDeAquecimentoGlobalUsoDoSoloEMudancaDeUsoDoSolo: 0.0246; PotencialDeEutrofizacaoFraccaoDeNutrientesQueAtingemOCompartimentoFinalDeAguaDoce: 0.000189; PotencialDeEutrofizacaoFraccaoDeNutrientesQueAtingemOCompartimentoFinalMarinho: 0.0122; EnergiaRecuperada: 0.00739; ConsumoDeAguaDoce: 0.113; UtilizacaoLiquidaDeAguaDoce: 0.113; ResiduosPerigososEliminados: 0.00221; ResiduosNaoPerigososEliminados: 1.83; MassaTotalDeResiduosRadioactivosEliminados: 0.000394; EnergiaElectricaExportada: 1.55; MateriaisParaRecuperacaoDeEnergia: 0.00739; MateriaisParaReciclagem: 0.0253; UnidadeEPD: 1 m²
Type - IFC.REVIGRÉS-Dados gerais-Floor Covering - Nome: REVIGRÉS-OMNISTONE-BASE-30X60-SOFT-JET; TipoProduto: Prensado a seco: grupo BIa UGL | Grés porcelânico técnico; NumeroDeRegistoDAP: EPD-REV-20240006-CCC1-EN; ReferenciaDAP: -; UrlDOP: -
Classification: C3020 (Uniformat)
Pset_CoveringCommon - TotalThickness: 9.8 mm
IFC.REVIGRÉS-Dados do fabricante-Floor Covering - Type: Floor: REVIGRÉS-OMNISTONE-BASE-30X60-SOFT-JET
IFC.REVIGRÉS-Dados de desempenho-Floor Covering - Type: Floor: REVIGRÉS-OMNISTONE-BASE-30X60-SOFT-JET
IFC.REVIGRÉS-Dados de especificação-Floor Covering - Type: Floor: REVIGRÉS-OMNISTONE-BASE-30X60-SOFT-JET
IFC.REVIGRÉS-Dados geométricos-Floor Covering - Type: Floor: REVIGRÉS-OMNISTONE-BASE-30X60-SOFT-JET
IFC.REVIGRÉS-Dados de sustentabilidade-Floor Covering - Type: Floor: REVIGRÉS-OMNISTONE-BASE-30X60-SOFT-JET

# IfcCovering: Floor:REVIGRÉS-OMNISTONE-BASE-30X60-SOFT-PLATINA, Floor:REVIGRÉS-OMNISTONE-BASE-30X60-SOFT-PLATINA:150663
In: Level 1
Type - PredefinedType: CLADDING; Material: REVIGRÉS-OMNISTONE-BASE-30x60-SOFT-PLATINA 9.8 mm
Type - Pset_CoveringCommon - Reference: 31262192U1; Material: Grés porcelânico
Type - Pset_ElementShading - Roughness: 304.8 mm
Type - Pset_ManufacturerTypeInformation - Manufacturer: REVIGRÉS
Type - Pset_ProductRequirements - Category: Floors
Type - Pset_QuantityTakeOff - Reference: 31262192U1
Type - IFC.REVIGRÉS-Dados do fabricante-Floor Covering - FabricanteURL: https://www.revigres.pt/; ReferenciaModelo: Omnistone; NumeroGlobalDeItemComercial: 31262192U1; Acabamento: SOFT; Material: Grés porcelânico; IdentificadorDoOperadorEconomico: 501840856; UrlFabricanteArtigo: https://www.revigres.pt/colecoes/omnistone; PaisOrigem: Portugal
Type - IFC.REVIGRÉS-Dados de desempenho-Floor Covering - Rectilinearidade: ± 0.2% máx.± 0.8 mm; Ortogonalidade: ± 0.2% máx.± 1.5 mm; PlanaridadeDaSuperficie: ± 0.3% máx. ± 1.8 mm; QualidadeDaSuperficie: Cumpre; AbsorcaoDeAgua: < 0.05%; ModuloDeRuptura: > 45 N/mm²; ResistenciaAFlexao: ≥ 3500 N; ResistenciaAAbrasaoProfunda: < 120 mm³; DilatacaoTermicaLinear: ≤ 8,0x10-6 °C-1; ResistenciaAoChoqueTermico: Resiste; DurabilidadeResistenciaAoGeloDegelo: Resiste; ResistenciaAsManchas: Class 5; ResistenciaABaixasConcentracoesDeAcidosEAlcalis: Classe LA; ResistenciaAAltasConcentracoesDeAcidosEAlcalis: Classe HA; LibertacaoDeCadmio: 0; LibertacaoDeChumbo: 0
Type - IFC.REVIGRÉS-Dados de especificação-Floor Covering - VariacaoTonalidade: 3; NivelDeTrafego: 5; EPavimento: Sim; ERevestimento: Sim; EExterno: Sim
Type - IFC.REVIGRÉS-Dados geométricos-Floor Covering - AlturaNominal: 9.8 mm; ComprimentoNominal: 29.5 mm; LarguraNominal: 59.2 mm
Type - IFC.REVIGRÉS-Dados de sustentabilidade-Floor Covering - ItemEParcialmenteReciclado: 0; EnergiaTermicaExportada: 0; ItemENovo: Sim; ItemEReciclado: Não; VidaÚtilEsperada: 50; SubstanciasPerigosas: Não; PotencialDeEsgotamentoAbioticoDosRecursosNaoFosseisMineraisEMetais: 0.000701; PotencialDeAquecimentoGlobalBiogenico: -0.48; CombustiveisFosseisComPotencialDeAquecimentoGlobal: 13.9; PotencialDeAquecimentoGlobalUsoDoSoloEMudancaDeUsoDoSolo: 0.0246; PotencialDeEutrofizacaoFraccaoDeNutrientesQueAtingemOCompartimentoFinalDeAguaDoce: 0.000189; PotencialDeEutrofizacaoFraccaoDeNutrientesQueAtingemOCompartimentoFinalMarinho: 0.0122; EnergiaRecuperada: 0.00739; ConsumoDeAguaDoce: 0.113; UtilizacaoLiquidaDeAguaDoce: 0.113; ResiduosPerigososEliminados: 0.00221; ResiduosNaoPerigososEliminados: 1.83; MassaTotalDeResiduosRadioactivosEliminados: 0.000394; EnergiaElectricaExportada: 1.55; MateriaisParaRecuperacaoDeEnergia: 0.00739; MateriaisParaReciclagem: 0.0253; UnidadeEPD: 1 m²
Type - IFC.REVIGRÉS-Dados gerais-Floor Covering - Nome: REVIGRÉS-OMNISTONE-BASE-30X60-SOFT-PLATINA; TipoProduto: Prensado a seco: grupo BIa UGL | Grés porcelânico técnico; NumeroDeRegistoDAP: EPD-REV-20240006-CCC1-EN; ReferenciaDAP: -; UrlDOP: -
Classification: C3020 (Uniformat)
Pset_CoveringCommon - TotalThickness: 9.8 mm
IFC.REVIGRÉS-Dados do fabricante-Floor Covering - Type: Floor: REVIGRÉS-OMNISTONE-BASE-30X60-SOFT-PLATINA
IFC.REVIGRÉS-Dados de desempenho-Floor Covering - Type: Floor: REVIGRÉS-OMNISTONE-BASE-30X60-SOFT-PLATINA
IFC.REVIGRÉS-Dados de especificação-Floor Covering - Type: Floor: REVIGRÉS-OMNISTONE-BASE-30X60-SOFT-PLATINA
IFC.REVIGRÉS-Dados geométricos-Floor Covering - Type: Floor: REVIGRÉS-OMNISTONE-BASE-30X60-SOFT-PLATINA
IFC.REVIGRÉS-Dados de sustentabilidade-Floor Covering - Type: Floor: REVIGRÉS-OMNISTONE-BASE-30X60-SOFT-PLATINA

# IfcCovering: Floor:REVIGRÉS-OMNISTONE-BASE-30X60-SOFT-ROPE, Floor:REVIGRÉS-OMNISTONE-BASE-30X60-SOFT-ROPE:151368
In: Level 1
Type - PredefinedType: CLADDING; Material: REVIGRÉS-OMNISTONE-BASE-30x60-SOFT-ROPE 9.8 mm
Type - Pset_CoveringCommon - Reference: 31262193U1; Material: Grés porcelânico
Type - Pset_ElementShading - Roughness: 304.8 mm
Type - Pset_ManufacturerTypeInformation - Manufacturer: REVIGRÉS
Type - Pset_ProductRequirements - Category: Floors
Type - Pset_QuantityTakeOff - Reference: 31262193U1
Type - IFC.REVIGRÉS-Dados do fabricante-Floor Covering - FabricanteURL: https://www.revigres.pt/; ReferenciaModelo: Omnistone; NumeroGlobalDeItemComercial: 31262193U1; Acabamento: SOFT; Material: Grés porcelânico; IdentificadorDoOperadorEconomico: 501840856; UrlFabricanteArtigo: https://www.revigres.pt/colecoes/omnistone; PaisOrigem: Portugal
Type - IFC.REVIGRÉS-Dados de desempenho-Floor Covering - Rectilinearidade: ± 0.2% máx.± 0.8 mm; Ortogonalidade: ± 0.2% máx.± 1.5 mm; PlanaridadeDaSuperficie: ± 0.3% máx. ± 1.8 mm; QualidadeDaSuperficie: Cumpre; AbsorcaoDeAgua: < 0.05%; ModuloDeRuptura: > 45 N/mm²; ResistenciaAFlexao: ≥ 3500 N; ResistenciaAAbrasaoProfunda: < 120 mm³; DilatacaoTermicaLinear: ≤ 8,0x10-6 °C-1; ResistenciaAoChoqueTermico: Resiste; DurabilidadeResistenciaAoGeloDegelo: Resiste; ResistenciaAsManchas: Class 5; ResistenciaABaixasConcentracoesDeAcidosEAlcalis: Classe LA; ResistenciaAAltasConcentracoesDeAcidosEAlcalis: Classe HA; LibertacaoDeCadmio: 0; LibertacaoDeChumbo: 0
Type - IFC.REVIGRÉS-Dados de especificação-Floor Covering - VariacaoTonalidade: 3; NivelDeTrafego: 5; EPavimento: Sim; ERevestimento: Sim; EExterno: Sim
Type - IFC.REVIGRÉS-Dados geométricos-Floor Covering - AlturaNominal: 9.8 mm; ComprimentoNominal: 29.5 mm; LarguraNominal: 59.2 mm
Type - IFC.REVIGRÉS-Dados de sustentabilidade-Floor Covering - ItemEParcialmenteReciclado: 0; EnergiaTermicaExportada: 0; ItemENovo: Sim; ItemEReciclado: Não; VidaÚtilEsperada: 50; SubstanciasPerigosas: Não; PotencialDeEsgotamentoAbioticoDosRecursosNaoFosseisMineraisEMetais: 0.000701; PotencialDeAquecimentoGlobalBiogenico: -0.48; CombustiveisFosseisComPotencialDeAquecimentoGlobal: 13.9; PotencialDeAquecimentoGlobalUsoDoSoloEMudancaDeUsoDoSolo: 0.0246; PotencialDeEutrofizacaoFraccaoDeNutrientesQueAtingemOCompartimentoFinalDeAguaDoce: 0.000189; PotencialDeEutrofizacaoFraccaoDeNutrientesQueAtingemOCompartimentoFinalMarinho: 0.0122; EnergiaRecuperada: 0.00739; ConsumoDeAguaDoce: 0.113; UtilizacaoLiquidaDeAguaDoce: 0.113; ResiduosPerigososEliminados: 0.00221; ResiduosNaoPerigososEliminados: 1.83; MassaTotalDeResiduosRadioactivosEliminados: 0.000394; EnergiaElectricaExportada: 1.55; MateriaisParaRecuperacaoDeEnergia: 0.00739; MateriaisParaReciclagem: 0.0253; UnidadeEPD: 1 m²
Type - IFC.REVIGRÉS-Dados gerais-Floor Covering - Nome: REVIGRÉS-OMNISTONE-BASE-30X60-SOFT-ROPE; TipoProduto: Prensado a seco: grupo BIa UGL | Grés porcelânico técnico; NumeroDeRegistoDAP: EPD-REV-20240006-CCC1-EN; ReferenciaDAP: -; UrlDOP: -
Classification: C3020 (Uniformat)
Pset_CoveringCommon - TotalThickness: 9.8 mm
IFC.REVIGRÉS-Dados do fabricante-Floor Covering - Type: Floor: REVIGRÉS-OMNISTONE-BASE-30X60-SOFT-ROPE
IFC.REVIGRÉS-Dados de desempenho-Floor Covering - Type: Floor: REVIGRÉS-OMNISTONE-BASE-30X60-SOFT-ROPE
IFC.REVIGRÉS-Dados de especificação-Floor Covering - Type: Floor: REVIGRÉS-OMNISTONE-BASE-30X60-SOFT-ROPE
IFC.REVIGRÉS-Dados geométricos-Floor Covering - Type: Floor: REVIGRÉS-OMNISTONE-BASE-30X60-SOFT-ROPE
IFC.REVIGRÉS-Dados de sustentabilidade-Floor Covering - Type: Floor: REVIGRÉS-OMNISTONE-BASE-30X60-SOFT-ROPE

# IfcCovering: Floor:REVIGRÉS-OMNISTONE-BASE-45X90-MATTRECT-BONE, Floor:REVIGRÉS-OMNISTONE-BASE-45X90-MATTRECT-BONE:146381
In: Level 1
Type - PredefinedType: CLADDING; Material: REVIGRÉS-OMNISTONE-BASE-45x90-MATTRECT-BONE 10.5 mm
Type - Pset_CoveringCommon - Reference: 312BH888U1; Material: Grés porcelânico
Type - Pset_ElementShading - Roughness: 304.8 mm
Type - Pset_ManufacturerTypeInformation - Manufacturer: REVIGRÉS
Type - Pset_ProductRequirements - Category: Floors
Type - Pset_QuantityTakeOff - Reference: 312BH888U1
Type - IFC.REVIGRÉS-Dados do fabricante-Floor Covering - FabricanteURL: https://www.revigres.pt/; ReferenciaModelo: Omnistone; NumeroGlobalDeItemComercial: 312BH888U1; Acabamento: MATT RECT; Material: Grés porcelânico; IdentificadorDoOperadorEconomico: 501840856; UrlFabricanteArtigo: https://www.revigres.pt/colecoes/omnistone; PaisOrigem: Portugal
Type - IFC.REVIGRÉS-Dados de desempenho-Floor Covering - Rectilinearidade: ± 0.2% máx.± 0.8 mm; Ortogonalidade: ± 0.2% máx.± 1.5 mm; PlanaridadeDaSuperficie: ± 0.3% máx. ± 1.8 mm; QualidadeDaSuperficie: Cumpre; AbsorcaoDeAgua: < 0.05%; ModuloDeRuptura: > 45 N/mm130; ResistenciaAFlexao: ≥ 3500 N; ResistenciaAAbrasaoProfunda: < 120 mm131; DilatacaoTermicaLinear: ≤ 8,0x10-6 °C-1; ResistenciaAoChoqueTermico: Resiste; DurabilidadeResistenciaAoGeloDegelo: Resiste; ResistenciaAoEscorregamentoDIN51130: R10; ResistenciaAoEscorregamentoDIN51097: B; ResistenciaAoEscorregamentoENV51097: B; ResistenciaAoEscorregamentoENV12633: Class 2; ResistenciaAoEscorregamentoBS7976: >36; ResistenciaAoEscorregamentoANSIA1371: ≥0,42; ResistenciaAoDeslizamentoENV12633: Class 2; ResistenciaAoDeslizamentoBS7976: >36; ResistenciaAsManchas: Class 5; ResistenciaABaixasConcentracoesDeAcidosEAlcalis: Classe LA; ResistenciaAAltasConcentracoesDeAcidosEAlcalis: Classe HA; LibertacaoDeCadmio: 0; LibertacaoDeChumbo: 0
Type - IFC.REVIGRÉS-Dados de especificação-Floor Covering - VariacaoTonalidade: 3; NivelDeTrafego: 5; EPavimento: Sim; ERevestimento: Sim; EExterno: Sim
Type - IFC.REVIGRÉS-Dados geométricos-Floor Covering - AlturaNominal: 10.5 mm; ComprimentoNominal: 44.35 mm; LarguraNominal: 88.9 mm
Type - IFC.REVIGRÉS-Dados de sustentabilidade-Floor Covering - ItemEParcialmenteReciclado: 0; EnergiaTermicaExportada: 0; ItemENovo: Sim; ItemEReciclado: Não; VidaÚtilEsperada: 50; SubstanciasPerigosas: Não; PotencialDeEsgotamentoAbioticoDosRecursosNaoFosseisMineraisEMetais: 0.000701; PotencialDeAquecimentoGlobalBiogenico: -0.48; CombustiveisFosseisComPotencialDeAquecimentoGlobal: 13.9; PotencialDeAquecimentoGlobalUsoDoSoloEMudancaDeUsoDoSolo: 0.0246; PotencialDeEutrofizacaoFraccaoDeNutrientesQueAtingemOCompartimentoFinalDeAguaDoce: 0.000189; PotencialDeEutrofizacaoFraccaoDeNutrientesQueAtingemOCompartimentoFinalMarinho: 0.0122; EnergiaRecuperada: 0.00739; ConsumoDeAguaDoce: 0.113; UtilizacaoLiquidaDeAguaDoce: 0.113; ResiduosPerigososEliminados: 0.00221; ResiduosNaoPerigososEliminados: 1.83; MassaTotalDeResiduosRadioactivosEliminados: 0.000394; EnergiaElectricaExportada: 1.55; MateriaisParaRecuperacaoDeEnergia: 0.00739; MateriaisParaReciclagem: 0.0253; UnidadeEPD: 1 m²
Type - IFC.REVIGRÉS-Dados gerais-Floor Covering - Nome: REVIGRÉS-OMNISTONE-BASE-45X90-MATT RECT-BONE; TipoProduto: Prensado a seco: grupo BIa UGL | Grés porcelânico técnico; NumeroDeRegistoDAP: EPD-REV-20240006-CCC1-EN; ReferenciaDAP: -; UrlDOP: -
Classification: C3020 (Uniformat)
Pset_CoveringCommon - TotalThickness: 10.5 mm
IFC.REVIGRÉS-Dados do fabricante-Floor Covering - Type: Floor: REVIGRÉS-OMNISTONE-BASE-45X90-MATTRECT-BONE
IFC.REVIGRÉS-Dados de desempenho-Floor Covering - Type: Floor: REVIGRÉS-OMNISTONE-BASE-45X90-MATTRECT-BONE
IFC.REVIGRÉS-Dados de especificação-Floor Covering - Type: Floor: REVIGRÉS-OMNISTONE-BASE-45X90-MATTRECT-BONE
IFC.REVIGRÉS-Dados geométricos-Floor Covering - Type: Floor: REVIGRÉS-OMNISTONE-BASE-45X90-MATTRECT-BONE
IFC.REVIGRÉS-Dados de sustentabilidade-Floor Covering - Type: Floor: REVIGRÉS-OMNISTONE-BASE-45X90-MATTRECT-BONE

# IfcCovering: Floor:REVIGRÉS-OMNISTONE-BASE-45X90-MATTRECT-ICE, Floor:REVIGRÉS-OMNISTONE-BASE-45X90-MATTRECT-ICE:148452
In: Level 1
Type - PredefinedType: CLADDING; Material: REVIGRÉS-OMNISTONE-BASE-45x90-MATTRECT-ICE 10.5 mm
Type - Pset_CoveringCommon - Reference: 312BH889U1; Material: Grés porcelânico
Type - Pset_ElementShading - Roughness: 304.8 mm
Type - Pset_ManufacturerTypeInformation - Manufacturer: REVIGRÉS
Type - Pset_ProductRequirements - Category: Floors
Type - Pset_QuantityTakeOff - Reference: 312BH889U1
Type - IFC.REVIGRÉS-Dados do fabricante-Floor Covering - FabricanteURL: https://www.revigres.pt/; ReferenciaModelo: Omnistone; NumeroGlobalDeItemComercial: 312BH889U1; Acabamento: MATT RECT; Material: Grés porcelânico; IdentificadorDoOperadorEconomico: 501840856; UrlFabricanteArtigo: https://www.revigres.pt/colecoes/omnistone; PaisOrigem: Portugal
Type - IFC.REVIGRÉS-Dados de desempenho-Floor Covering - Rectilinearidade: ± 0.2% máx.± 0.8 mm; Ortogonalidade: ± 0.2% máx.± 1.5 mm; PlanaridadeDaSuperficie: ± 0.3% máx. ± 1.8 mm; QualidadeDaSuperficie: Cumpre; AbsorcaoDeAgua: < 0.05%; ModuloDeRuptura: > 45 N/mm130; ResistenciaAFlexao: ≥ 3500 N; ResistenciaAAbrasaoProfunda: < 120 mm131; DilatacaoTermicaLinear: ≤ 8,0x10-6 °C-1; ResistenciaAoChoqueTermico: Resiste; DurabilidadeResistenciaAoGeloDegelo: Resiste; ResistenciaAoEscorregamentoDIN51130: R10; ResistenciaAoEscorregamentoDIN51097: B; ResistenciaAoEscorregamentoENV51097: B; ResistenciaAoEscorregamentoENV12633: Class 2; ResistenciaAoEscorregamentoBS7976: >36; ResistenciaAoEscorregamentoANSIA1371: ≥0,42; ResistenciaAoDeslizamentoENV12633: Class 2; ResistenciaAoDeslizamentoBS7976: >36; ResistenciaAsManchas: Class 5; ResistenciaABaixasConcentracoesDeAcidosEAlcalis: Classe LA; ResistenciaAAltasConcentracoesDeAcidosEAlcalis: Classe HA; LibertacaoDeCadmio: 0; LibertacaoDeChumbo: 0
Type - IFC.REVIGRÉS-Dados de especificação-Floor Covering - VariacaoTonalidade: 3; NivelDeTrafego: 5; EPavimento: Sim; ERevestimento: Sim; EExterno: Sim
Type - IFC.REVIGRÉS-Dados geométricos-Floor Covering - AlturaNominal: 10.5 mm; ComprimentoNominal: 44.35 mm; LarguraNominal: 88.9 mm
Type - IFC.REVIGRÉS-Dados de sustentabilidade-Floor Covering - ItemEParcialmenteReciclado: 0; EnergiaTermicaExportada: 0; ItemENovo: Sim; ItemEReciclado: Não; VidaÚtilEsperada: 50; SubstanciasPerigosas: Não; PotencialDeEsgotamentoAbioticoDosRecursosNaoFosseisMineraisEMetais: 0.000701; PotencialDeAquecimentoGlobalBiogenico: -0.48; CombustiveisFosseisComPotencialDeAquecimentoGlobal: 13.9; PotencialDeAquecimentoGlobalUsoDoSoloEMudancaDeUsoDoSolo: 0.0246; PotencialDeEutrofizacaoFraccaoDeNutrientesQueAtingemOCompartimentoFinalDeAguaDoce: 0.000189; PotencialDeEutrofizacaoFraccaoDeNutrientesQueAtingemOCompartimentoFinalMarinho: 0.0122; EnergiaRecuperada: 0.00739; ConsumoDeAguaDoce: 0.113; UtilizacaoLiquidaDeAguaDoce: 0.113; ResiduosPerigososEliminados: 0.00221; ResiduosNaoPerigososEliminados: 1.83; MassaTotalDeResiduosRadioactivosEliminados: 0.000394; EnergiaElectricaExportada: 1.55; MateriaisParaRecuperacaoDeEnergia: 0.00739; MateriaisParaReciclagem: 0.0253; UnidadeEPD: 1 m²
Type - IFC.REVIGRÉS-Dados gerais-Floor Covering - Nome: REVIGRÉS-OMNISTONE-BASE-45X90-MATT RECT-ICE; TipoProduto: Prensado a seco: grupo BIa UGL | Grés porcelânico técnico; NumeroDeRegistoDAP: EPD-REV-20240006-CCC1-EN; ReferenciaDAP: -; UrlDOP: -
Classification: C3020 (Uniformat)
Pset_CoveringCommon - TotalThickness: 10.5 mm
IFC.REVIGRÉS-Dados do fabricante-Floor Covering - Type: Floor: REVIGRÉS-OMNISTONE-BASE-45X90-MATTRECT-ICE
IFC.REVIGRÉS-Dados de desempenho-Floor Covering - Type: Floor: REVIGRÉS-OMNISTONE-BASE-45X90-MATTRECT-ICE
IFC.REVIGRÉS-Dados de especificação-Floor Covering - Type: Floor: REVIGRÉS-OMNISTONE-BASE-45X90-MATTRECT-ICE
IFC.REVIGRÉS-Dados geométricos-Floor Covering - Type: Floor: REVIGRÉS-OMNISTONE-BASE-45X90-MATTRECT-ICE
IFC.REVIGRÉS-Dados de sustentabilidade-Floor Covering - Type: Floor: REVIGRÉS-OMNISTONE-BASE-45X90-MATTRECT-ICE

# IfcCovering: Floor:REVIGRÉS-OMNISTONE-BASE-45X90-MATTRECT-IRON, Floor:REVIGRÉS-OMNISTONE-BASE-45X90-MATTRECT-IRON:149144
In: Level 1
Type - PredefinedType: CLADDING; Material: REVIGRÉS-OMNISTONE-BASE-45x90-MATTRECT-IRON 10.5 mm
Type - Pset_CoveringCommon - Reference: 312BH890U1; Material: Grés porcelânico
Type - Pset_ElementShading - Roughness: 304.8 mm
Type - Pset_ManufacturerTypeInformation - Manufacturer: REVIGRÉS
Type - Pset_ProductRequirements - Category: Floors
Type - Pset_QuantityTakeOff - Reference: 312BH890U1
Type - IFC.REVIGRÉS-Dados do fabricante-Floor Covering - FabricanteURL: https://www.revigres.pt/; ReferenciaModelo: Omnistone; NumeroGlobalDeItemComercial: 312BH890U1; Acabamento: MATT RECT; Material: Grés porcelânico; IdentificadorDoOperadorEconomico: 501840856; UrlFabricanteArtigo: https://www.revigres.pt/colecoes/omnistone; PaisOrigem: Portugal
Type - IFC.REVIGRÉS-Dados de desempenho-Floor Covering - Rectilinearidade: ± 0.2% máx.± 0.8 mm; Ortogonalidade: ± 0.2% máx.± 1.5 mm; PlanaridadeDaSuperficie: ± 0.3% máx. ± 1.8 mm; QualidadeDaSuperficie: Cumpre; AbsorcaoDeAgua: < 0.05%; ModuloDeRuptura: > 45 N/mm130; ResistenciaAFlexao: ≥ 3500 N; ResistenciaAAbrasaoProfunda: < 120 mm131; DilatacaoTermicaLinear: ≤ 8,0x10-6 °C-1; ResistenciaAoChoqueTermico: Resiste; DurabilidadeResistenciaAoGeloDegelo: Resiste; ResistenciaAoEscorregamentoDIN51130: R10; ResistenciaAoEscorregamentoDIN51097: B; ResistenciaAoEscorregamentoENV51097: B; ResistenciaAoEscorregamentoENV12633: Class 2; ResistenciaAoEscorregamentoBS7976: >36; ResistenciaAoEscorregamentoANSIA1371: ≥0,42; ResistenciaAoDeslizamentoENV12633: Class 2; ResistenciaAoDeslizamentoBS7976: >36; ResistenciaAsManchas: Class 5; ResistenciaABaixasConcentracoesDeAcidosEAlcalis: Classe LA; ResistenciaAAltasConcentracoesDeAcidosEAlcalis: Classe HA; LibertacaoDeCadmio: 0; LibertacaoDeChumbo: 0
Type - IFC.REVIGRÉS-Dados de especificação-Floor Covering - VariacaoTonalidade: 3; NivelDeTrafego: 5; EPavimento: Sim; ERevestimento: Sim; EExterno: Sim
Type - IFC.REVIGRÉS-Dados geométricos-Floor Covering - AlturaNominal: 10.5 mm; ComprimentoNominal: 44.35 mm; LarguraNominal: 88.9 mm
Type - IFC.REVIGRÉS-Dados de sustentabilidade-Floor Covering - EnergiaTermicaExportada: 0; ItemENovo: Sim; ItemEParcialmenteReciclado: 0.14; ItemEReciclado: Sim; VidaÚtilEsperada: 50; SubstanciasPerigosas: Não; PotencialDeEsgotamentoAbioticoDosRecursosNaoFosseisMineraisEMetais: 0.000701; PotencialDeAquecimentoGlobalBiogenico: -0.48; CombustiveisFosseisComPotencialDeAquecimentoGlobal: 13.9; PotencialDeAquecimentoGlobalUsoDoSoloEMudancaDeUsoDoSolo: 0.0246; PotencialDeEutrofizacaoFraccaoDeNutrientesQueAtingemOCompartimentoFinalDeAguaDoce: 0.000189; PotencialDeEutrofizacaoFraccaoDeNutrientesQueAtingemOCompartimentoFinalMarinho: 0.0122; EnergiaRecuperada: 0.00739; ConsumoDeAguaDoce: 0.113; UtilizacaoLiquidaDeAguaDoce: 0.113; ResiduosPerigososEliminados: 0.00221; ResiduosNaoPerigososEliminados: 1.83; MassaTotalDeResiduosRadioactivosEliminados: 0.000394; EnergiaElectricaExportada: 1.55; MateriaisParaRecuperacaoDeEnergia: 0.00739; MateriaisParaReciclagem: 0.0253; UnidadeEPD: 1 m²
Type - IFC.REVIGRÉS-Dados gerais-Floor Covering - Nome: REVIGRÉS-OMNISTONE-BASE-45X90-MATT RECT-IRON; TipoProduto: Prensado a seco: grupo BIa UGL | Grés porcelânico técnico; NumeroDeRegistoDAP: EPD-REV-20240006-CCC1-EN; ReferenciaDAP: -; UrlDOP: -
Classification: C3020 (Uniformat)
Pset_CoveringCommon - TotalThickness: 10.5 mm
IFC.REVIGRÉS-Dados do fabricante-Floor Covering - Type: Floor: REVIGRÉS-OMNISTONE-BASE-45X90-MATTRECT-IRON
IFC.REVIGRÉS-Dados de desempenho-Floor Covering - Type: Floor: REVIGRÉS-OMNISTONE-BASE-45X90-MATTRECT-IRON
IFC.REVIGRÉS-Dados de especificação-Floor Covering - Type: Floor: REVIGRÉS-OMNISTONE-BASE-45X90-MATTRECT-IRON
IFC.REVIGRÉS-Dados geométricos-Floor Covering - Type: Floor: REVIGRÉS-OMNISTONE-BASE-45X90-MATTRECT-IRON
IFC.REVIGRÉS-Dados de sustentabilidade-Floor Covering - Type: Floor: REVIGRÉS-OMNISTONE-BASE-45X90-MATTRECT-IRON

# IfcCovering: Floor:REVIGRÉS-OMNISTONE-BASE-45X90-MATTRECT-JET, Floor:REVIGRÉS-OMNISTONE-BASE-45X90-MATTRECT-JET:149886
In: Level 1
Type - PredefinedType: CLADDING; Material: REVIGRÉS-OMNISTONE-BASE-45x90-MATTRECT-JET 10.5 mm
Type - Pset_CoveringCommon - Reference: 312BH891U1; Material: Grés porcelânico
Type - Pset_ElementShading - Roughness: 304.8 mm
Type - Pset_ManufacturerTypeInformation - Manufacturer: REVIGRÉS
Type - Pset_ProductRequirements - Category: Floors
Type - Pset_QuantityTakeOff - Reference: 312BH891U1
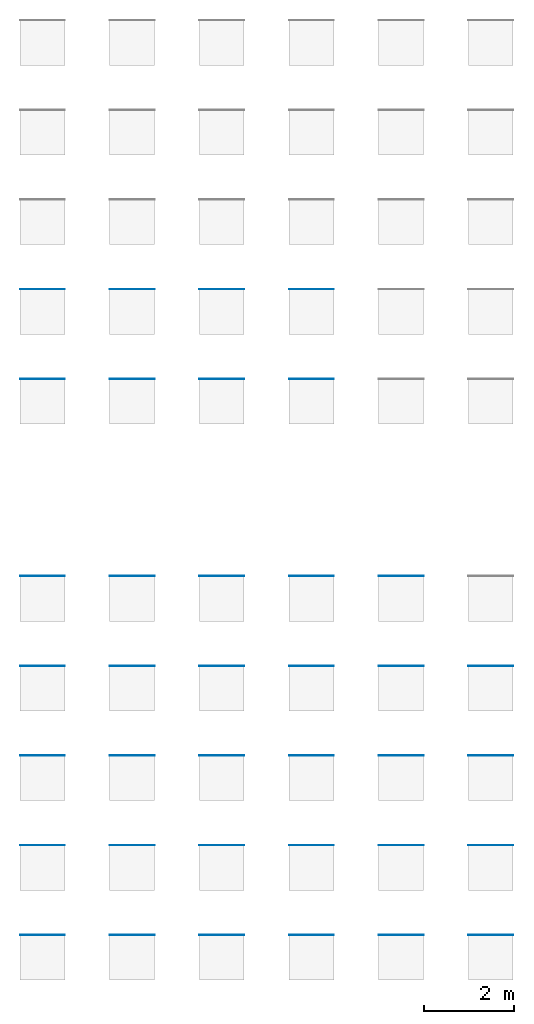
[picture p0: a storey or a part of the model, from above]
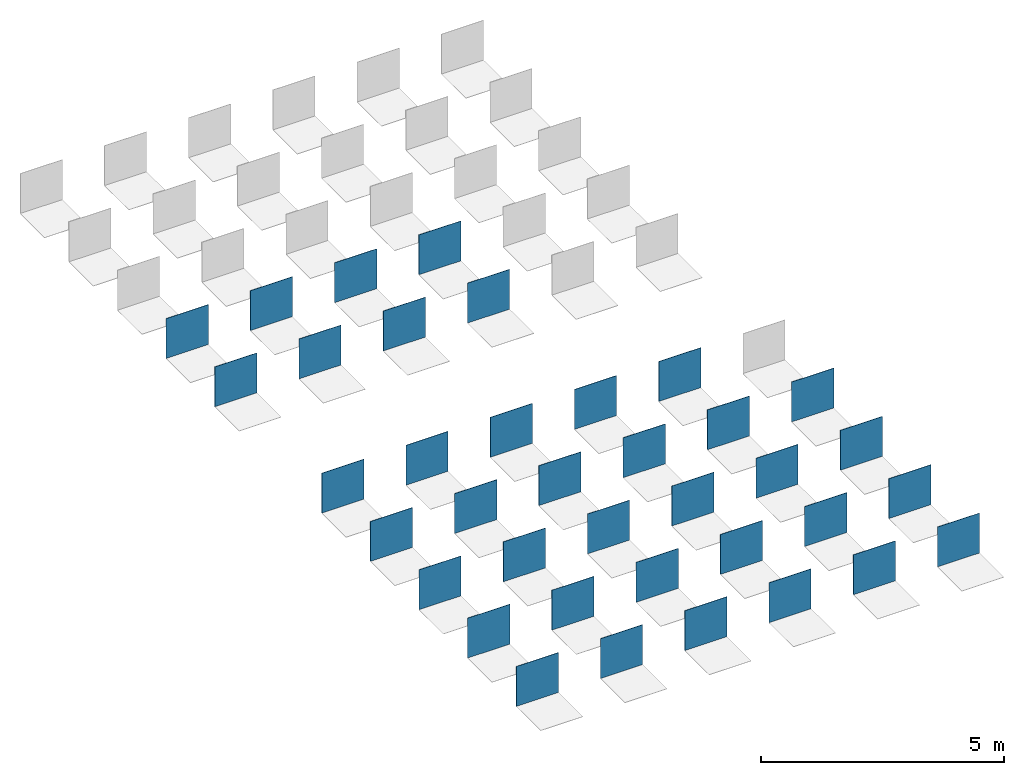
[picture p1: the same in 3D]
Properties of the parts of a building model (IFC2X3), part 2 of 8

# IfcCovering: Floor:REVIGRÉS-OMNISTONE-BASE-45X90-MATTRECT-JET, Floor:REVIGRÉS-OMNISTONE-BASE-45X90-MATTRECT-JET:149886
Type - IFC.REVIGRÉS-Dados do fabricante-Floor Covering - FabricanteURL: https://www.revigres.pt/; ReferenciaModelo: Omnistone; NumeroGlobalDeItemComercial: 312BH891U1; Acabamento: MATT RECT; Material: Grés porcelânico; IdentificadorDoOperadorEconomico: 501840856; UrlFabricanteArtigo: https://www.revigres.pt/colecoes/omnistone; PaisOrigem: Portugal
Type - IFC.REVIGRÉS-Dados de desempenho-Floor Covering - Rectilinearidade: ± 0.2% máx.± 0.8 mm; Ortogonalidade: ± 0.2% máx.± 1.5 mm; PlanaridadeDaSuperficie: ± 0.3% máx. ± 1.8 mm; QualidadeDaSuperficie: Cumpre; AbsorcaoDeAgua: < 0.05%; ModuloDeRuptura: > 45 N/mm130; ResistenciaAFlexao: ≥ 3500 N; ResistenciaAAbrasaoProfunda: < 120 mm131; DilatacaoTermicaLinear: ≤ 8,0x10-6 °C-1; ResistenciaAoChoqueTermico: Resiste; DurabilidadeResistenciaAoGeloDegelo: Resiste; ResistenciaAoEscorregamentoDIN51130: R10; ResistenciaAoEscorregamentoDIN51097: B; ResistenciaAoEscorregamentoENV51097: B; ResistenciaAoEscorregamentoENV12633: Class 2; ResistenciaAoEscorregamentoBS7976: >36; ResistenciaAoEscorregamentoANSIA1371: ≥0,42; ResistenciaAoDeslizamentoENV12633: Class 2; ResistenciaAoDeslizamentoBS7976: >36; ResistenciaAsManchas: Class 5; ResistenciaABaixasConcentracoesDeAcidosEAlcalis: Classe LA; ResistenciaAAltasConcentracoesDeAcidosEAlcalis: Classe HA; LibertacaoDeCadmio: 0; LibertacaoDeChumbo: 0
Type - IFC.REVIGRÉS-Dados de especificação-Floor Covering - VariacaoTonalidade: 3; NivelDeTrafego: 5; EPavimento: Sim; ERevestimento: Sim; EExterno: Sim
Type - IFC.REVIGRÉS-Dados geométricos-Floor Covering - AlturaNominal: 10.5 mm; ComprimentoNominal: 44.35 mm; LarguraNominal: 88.9 mm
Type - IFC.REVIGRÉS-Dados de sustentabilidade-Floor Covering - ItemEParcialmenteReciclado: 0; EnergiaTermicaExportada: 0; ItemENovo: Sim; ItemEReciclado: Não; VidaÚtilEsperada: 50; SubstanciasPerigosas: Não; PotencialDeEsgotamentoAbioticoDosRecursosNaoFosseisMineraisEMetais: 0.000701; PotencialDeAquecimentoGlobalBiogenico: -0.48; CombustiveisFosseisComPotencialDeAquecimentoGlobal: 13.9; PotencialDeAquecimentoGlobalUsoDoSoloEMudancaDeUsoDoSolo: 0.0246; PotencialDeEutrofizacaoFraccaoDeNutrientesQueAtingemOCompartimentoFinalDeAguaDoce: 0.000189; PotencialDeEutrofizacaoFraccaoDeNutrientesQueAtingemOCompartimentoFinalMarinho: 0.0122; EnergiaRecuperada: 0.00739; ConsumoDeAguaDoce: 0.113; UtilizacaoLiquidaDeAguaDoce: 0.113; ResiduosPerigososEliminados: 0.00221; ResiduosNaoPerigososEliminados: 1.83; MassaTotalDeResiduosRadioactivosEliminados: 0.000394; EnergiaElectricaExportada: 1.55; MateriaisParaRecuperacaoDeEnergia: 0.00739; MateriaisParaReciclagem: 0.0253; UnidadeEPD: 1 m²
Type - IFC.REVIGRÉS-Dados gerais-Floor Covering - Nome: REVIGRÉS-OMNISTONE-BASE-45X90-MATT RECT-JET; TipoProduto: Prensado a seco: grupo BIa UGL | Grés porcelânico técnico; NumeroDeRegistoDAP: EPD-REV-20240006-CCC1-EN; ReferenciaDAP: -; UrlDOP: -
Classification: C3020 (Uniformat)
Pset_CoveringCommon - TotalThickness: 10.5 mm
IFC.REVIGRÉS-Dados do fabricante-Floor Covering - Type: Floor: REVIGRÉS-OMNISTONE-BASE-45X90-MATTRECT-JET
IFC.REVIGRÉS-Dados de desempenho-Floor Covering - Type: Floor: REVIGRÉS-OMNISTONE-BASE-45X90-MATTRECT-JET
IFC.REVIGRÉS-Dados de especificação-Floor Covering - Type: Floor: REVIGRÉS-OMNISTONE-BASE-45X90-MATTRECT-JET
IFC.REVIGRÉS-Dados geométricos-Floor Covering - Type: Floor: REVIGRÉS-OMNISTONE-BASE-45X90-MATTRECT-JET
IFC.REVIGRÉS-Dados de sustentabilidade-Floor Covering - Type: Floor: REVIGRÉS-OMNISTONE-BASE-45X90-MATTRECT-JET

# IfcCovering: Floor:REVIGRÉS-OMNISTONE-BASE-45X90-MATTRECT-PLATINA, Floor:REVIGRÉS-OMNISTONE-BASE-45X90-MATTRECT-PLATINA:150607
In: Level 1
Type - PredefinedType: CLADDING; Material: REVIGRÉS-OMNISTONE-BASE-45x90-MATTRECT-PLATINA 10.5 mm
Type - Pset_CoveringCommon - Reference: 312BH892U1; Material: Grés porcelânico
Type - Pset_ElementShading - Roughness: 304.8 mm
Type - Pset_ManufacturerTypeInformation - Manufacturer: REVIGRÉS
Type - Pset_ProductRequirements - Category: Floors
Type - Pset_QuantityTakeOff - Reference: 312BH892U1
Type - IFC.REVIGRÉS-Dados do fabricante-Floor Covering - FabricanteURL: https://www.revigres.pt/; ReferenciaModelo: Omnistone; NumeroGlobalDeItemComercial: 312BH892U1; Acabamento: MATT RECT; Material: Grés porcelânico; IdentificadorDoOperadorEconomico: 501840856; UrlFabricanteArtigo: https://www.revigres.pt/colecoes/omnistone; PaisOrigem: Portugal
Type - IFC.REVIGRÉS-Dados de desempenho-Floor Covering - Rectilinearidade: ± 0.2% máx.± 0.8 mm; Ortogonalidade: ± 0.2% máx.± 1.5 mm; PlanaridadeDaSuperficie: ± 0.3% máx. ± 1.8 mm; QualidadeDaSuperficie: Cumpre; AbsorcaoDeAgua: < 0.05%; ModuloDeRuptura: > 45 N/mm130; ResistenciaAFlexao: ≥ 3500 N; ResistenciaAAbrasaoProfunda: < 120 mm131; DilatacaoTermicaLinear: ≤ 8,0x10-6 °C-1; ResistenciaAoChoqueTermico: Resiste; DurabilidadeResistenciaAoGeloDegelo: Resiste; ResistenciaAoEscorregamentoDIN51130: R10; ResistenciaAoEscorregamentoDIN51097: B; ResistenciaAoEscorregamentoENV51097: B; ResistenciaAoEscorregamentoENV12633: Class 2; ResistenciaAoEscorregamentoBS7976: >36; ResistenciaAoEscorregamentoANSIA1371: ≥0,42; ResistenciaAoDeslizamentoENV12633: Class 2; ResistenciaAoDeslizamentoBS7976: >36; ResistenciaAsManchas: Class 5; ResistenciaABaixasConcentracoesDeAcidosEAlcalis: Classe LA; ResistenciaAAltasConcentracoesDeAcidosEAlcalis: Classe HA; LibertacaoDeCadmio: 0; LibertacaoDeChumbo: 0
Type - IFC.REVIGRÉS-Dados de especificação-Floor Covering - VariacaoTonalidade: 3; NivelDeTrafego: 5; EPavimento: Sim; ERevestimento: Sim; EExterno: Sim
Type - IFC.REVIGRÉS-Dados geométricos-Floor Covering - AlturaNominal: 10.5 mm; ComprimentoNominal: 44.35 mm; LarguraNominal: 88.9 mm
Type - IFC.REVIGRÉS-Dados de sustentabilidade-Floor Covering - ItemEParcialmenteReciclado: 0; EnergiaTermicaExportada: 0; ItemENovo: Sim; ItemEReciclado: Não; VidaÚtilEsperada: 50; SubstanciasPerigosas: Não; PotencialDeEsgotamentoAbioticoDosRecursosNaoFosseisMineraisEMetais: 0.000701; PotencialDeAquecimentoGlobalBiogenico: -0.48; CombustiveisFosseisComPotencialDeAquecimentoGlobal: 13.9; PotencialDeAquecimentoGlobalUsoDoSoloEMudancaDeUsoDoSolo: 0.0246; PotencialDeEutrofizacaoFraccaoDeNutrientesQueAtingemOCompartimentoFinalDeAguaDoce: 0.000189; PotencialDeEutrofizacaoFraccaoDeNutrientesQueAtingemOCompartimentoFinalMarinho: 0.0122; EnergiaRecuperada: 0.00739; ConsumoDeAguaDoce: 0.113; UtilizacaoLiquidaDeAguaDoce: 0.113; ResiduosPerigososEliminados: 0.00221; ResiduosNaoPerigososEliminados: 1.83; MassaTotalDeResiduosRadioactivosEliminados: 0.000394; EnergiaElectricaExportada: 1.55; MateriaisParaRecuperacaoDeEnergia: 0.00739; MateriaisParaReciclagem: 0.0253; UnidadeEPD: 1 m²
Type - IFC.REVIGRÉS-Dados gerais-Floor Covering - Nome: REVIGRÉS-OMNISTONE-BASE-45X90-MATT RECT-PLATINA; TipoProduto: Prensado a seco: grupo BIa UGL | Grés porcelânico técnico; NumeroDeRegistoDAP: EPD-REV-20240006-CCC1-EN; ReferenciaDAP: -; UrlDOP: -
Classification: C3020 (Uniformat)
Pset_CoveringCommon - TotalThickness: 10.5 mm
IFC.REVIGRÉS-Dados do fabricante-Floor Covering - Type: Floor: REVIGRÉS-OMNISTONE-BASE-45X90-MATTRECT-PLATINA
IFC.REVIGRÉS-Dados de desempenho-Floor Covering - Type: Floor: REVIGRÉS-OMNISTONE-BASE-45X90-MATTRECT-PLATINA
IFC.REVIGRÉS-Dados de especificação-Floor Covering - Type: Floor: REVIGRÉS-OMNISTONE-BASE-45X90-MATTRECT-PLATINA
IFC.REVIGRÉS-Dados geométricos-Floor Covering - Type: Floor: REVIGRÉS-OMNISTONE-BASE-45X90-MATTRECT-PLATINA
IFC.REVIGRÉS-Dados de sustentabilidade-Floor Covering - Type: Floor: REVIGRÉS-OMNISTONE-BASE-45X90-MATTRECT-PLATINA

# IfcCovering: Floor:REVIGRÉS-OMNISTONE-BASE-45X90-MATTRECT-ROPE, Floor:REVIGRÉS-OMNISTONE-BASE-45X90-MATTRECT-ROPE:151312
In: Level 1
Type - PredefinedType: CLADDING; Material: REVIGRÉS-OMNISTONE-BASE-45x90-MATTRECT-ROPE 10.5 mm
Type - Pset_CoveringCommon - Reference: 312BH893U1; Material: Grés porcelânico
Type - Pset_ElementShading - Roughness: 304.8 mm
Type - Pset_ManufacturerTypeInformation - Manufacturer: REVIGRÉS
Type - Pset_ProductRequirements - Category: Floors
Type - Pset_QuantityTakeOff - Reference: 312BH893U1
Type - IFC.REVIGRÉS-Dados do fabricante-Floor Covering - FabricanteURL: https://www.revigres.pt/; ReferenciaModelo: Omnistone; NumeroGlobalDeItemComercial: 312BH893U1; Acabamento: MATT RECT; Material: Grés porcelânico; IdentificadorDoOperadorEconomico: 501840856; UrlFabricanteArtigo: https://www.revigres.pt/colecoes/omnistone; PaisOrigem: Portugal
Type - IFC.REVIGRÉS-Dados de desempenho-Floor Covering - Rectilinearidade: ± 0.2% máx.± 0.8 mm; Ortogonalidade: ± 0.2% máx.± 1.5 mm; PlanaridadeDaSuperficie: ± 0.3% máx. ± 1.8 mm; QualidadeDaSuperficie: Cumpre; AbsorcaoDeAgua: < 0.05%; ModuloDeRuptura: > 45 N/mm130; ResistenciaAFlexao: ≥ 3500 N; ResistenciaAAbrasaoProfunda: < 120 mm131; DilatacaoTermicaLinear: ≤ 8,0x10-6 °C-1; ResistenciaAoChoqueTermico: Resiste; DurabilidadeResistenciaAoGeloDegelo: Resiste; ResistenciaAoEscorregamentoDIN51130: R10; ResistenciaAoEscorregamentoDIN51097: B; ResistenciaAoEscorregamentoENV51097: B; ResistenciaAoEscorregamentoENV12633: Class 2; ResistenciaAoEscorregamentoBS7976: >36; ResistenciaAoEscorregamentoANSIA1371: ≥0,42; ResistenciaAoDeslizamentoENV12633: Class 2; ResistenciaAoDeslizamentoBS7976: >36; ResistenciaAsManchas: Class 5; ResistenciaABaixasConcentracoesDeAcidosEAlcalis: Classe LA; ResistenciaAAltasConcentracoesDeAcidosEAlcalis: Classe HA; LibertacaoDeCadmio: 0; LibertacaoDeChumbo: 0
Type - IFC.REVIGRÉS-Dados de especificação-Floor Covering - VariacaoTonalidade: 3; NivelDeTrafego: 5; EPavimento: Sim; ERevestimento: Sim; EExterno: Sim
Type - IFC.REVIGRÉS-Dados geométricos-Floor Covering - AlturaNominal: 10.5 mm; ComprimentoNominal: 44.35 mm; LarguraNominal: 88.9 mm
Type - IFC.REVIGRÉS-Dados de sustentabilidade-Floor Covering - ItemEParcialmenteReciclado: 0; EnergiaTermicaExportada: 0; ItemENovo: Sim; ItemEReciclado: Não; VidaÚtilEsperada: 50; SubstanciasPerigosas: Não; PotencialDeEsgotamentoAbioticoDosRecursosNaoFosseisMineraisEMetais: 0.000701; PotencialDeAquecimentoGlobalBiogenico: -0.48; CombustiveisFosseisComPotencialDeAquecimentoGlobal: 13.9; PotencialDeAquecimentoGlobalUsoDoSoloEMudancaDeUsoDoSolo: 0.0246; PotencialDeEutrofizacaoFraccaoDeNutrientesQueAtingemOCompartimentoFinalDeAguaDoce: 0.000189; PotencialDeEutrofizacaoFraccaoDeNutrientesQueAtingemOCompartimentoFinalMarinho: 0.0122; EnergiaRecuperada: 0.00739; ConsumoDeAguaDoce: 0.113; UtilizacaoLiquidaDeAguaDoce: 0.113; ResiduosPerigososEliminados: 0.00221; ResiduosNaoPerigososEliminados: 1.83; MassaTotalDeResiduosRadioactivosEliminados: 0.000394; EnergiaElectricaExportada: 1.55; MateriaisParaRecuperacaoDeEnergia: 0.00739; MateriaisParaReciclagem: 0.0253; UnidadeEPD: 1 m²
Type - IFC.REVIGRÉS-Dados gerais-Floor Covering - Nome: REVIGRÉS-OMNISTONE-BASE-45X90-MATT RECT-ROPE; TipoProduto: Prensado a seco: grupo BIa UGL | Grés porcelânico técnico; NumeroDeRegistoDAP: EPD-REV-20240006-CCC1-EN; ReferenciaDAP: -; UrlDOP: -
Classification: C3020 (Uniformat)
Pset_CoveringCommon - TotalThickness: 10.5 mm
IFC.REVIGRÉS-Dados do fabricante-Floor Covering - Type: Floor: REVIGRÉS-OMNISTONE-BASE-45X90-MATTRECT-ROPE
IFC.REVIGRÉS-Dados de desempenho-Floor Covering - Type: Floor: REVIGRÉS-OMNISTONE-BASE-45X90-MATTRECT-ROPE
IFC.REVIGRÉS-Dados de especificação-Floor Covering - Type: Floor: REVIGRÉS-OMNISTONE-BASE-45X90-MATTRECT-ROPE
IFC.REVIGRÉS-Dados geométricos-Floor Covering - Type: Floor: REVIGRÉS-OMNISTONE-BASE-45X90-MATTRECT-ROPE
IFC.REVIGRÉS-Dados de sustentabilidade-Floor Covering - Type: Floor: REVIGRÉS-OMNISTONE-BASE-45X90-MATTRECT-ROPE

# IfcCovering: Floor:REVIGRÉS-OMNISTONE-BASE-45X90-SOFT-BONE, Floor:REVIGRÉS-OMNISTONE-BASE-45X90-SOFT-BONE:146530
In: Level 1
Type - PredefinedType: CLADDING; Material: REVIGRÉS-OMNISTONE-BASE-45x90-SOFT-BONE 10.5 mm
Type - Pset_CoveringCommon - Reference: 3126H888U1; Material: Grés porcelânico
Type - Pset_ElementShading - Roughness: 304.8 mm
Type - Pset_ManufacturerTypeInformation - Manufacturer: REVIGRÉS
Type - Pset_ProductRequirements - Category: Floors
Type - Pset_QuantityTakeOff - Reference: 3126H888U1
Type - IFC.REVIGRÉS-Dados do fabricante-Floor Covering - FabricanteURL: https://www.revigres.pt/; ReferenciaModelo: Omnistone; NumeroGlobalDeItemComercial: 3126H888U1; Acabamento: SOFT; Material: Grés porcelânico; IdentificadorDoOperadorEconomico: 501840856; UrlFabricanteArtigo: https://www.revigres.pt/colecoes/omnistone; PaisOrigem: Portugal
Type - IFC.REVIGRÉS-Dados de desempenho-Floor Covering - Rectilinearidade: ± 0.2% máx.± 0.8 mm; Ortogonalidade: ± 0.2% máx.± 1.5 mm; PlanaridadeDaSuperficie: ± 0.3% máx. ± 1.8 mm; QualidadeDaSuperficie: Cumpre; AbsorcaoDeAgua: < 0.05%; ModuloDeRuptura: > 45 N/mm130; ResistenciaAFlexao: ≥ 3500 N; ResistenciaAAbrasaoProfunda: < 120 mm131; DilatacaoTermicaLinear: ≤ 8,0x10-6 °C-1; ResistenciaAoChoqueTermico: Resiste; DurabilidadeResistenciaAoGeloDegelo: Resiste; ResistenciaAsManchas: Class 5; ResistenciaABaixasConcentracoesDeAcidosEAlcalis: Classe LA; ResistenciaAAltasConcentracoesDeAcidosEAlcalis: Classe HA; LibertacaoDeCadmio: 0; LibertacaoDeChumbo: 0
Type - IFC.REVIGRÉS-Dados de especificação-Floor Covering - VariacaoTonalidade: 3; NivelDeTrafego: 5; EPavimento: Sim; ERevestimento: Sim; EExterno: Sim
Type - IFC.REVIGRÉS-Dados geométricos-Floor Covering - AlturaNominal: 10.5 mm; ComprimentoNominal: 44.35 mm; LarguraNominal: 88.9 mm
Type - IFC.REVIGRÉS-Dados de sustentabilidade-Floor Covering - ItemEParcialmenteReciclado: 0; EnergiaTermicaExportada: 0; ItemENovo: Sim; ItemEReciclado: Não; VidaÚtilEsperada: 50; SubstanciasPerigosas: Não; PotencialDeEsgotamentoAbioticoDosRecursosNaoFosseisMineraisEMetais: 0.000701; PotencialDeAquecimentoGlobalBiogenico: -0.48; CombustiveisFosseisComPotencialDeAquecimentoGlobal: 13.9; PotencialDeAquecimentoGlobalUsoDoSoloEMudancaDeUsoDoSolo: 0.0246; PotencialDeEutrofizacaoFraccaoDeNutrientesQueAtingemOCompartimentoFinalDeAguaDoce: 0.000189; PotencialDeEutrofizacaoFraccaoDeNutrientesQueAtingemOCompartimentoFinalMarinho: 0.0122; EnergiaRecuperada: 0.00739; ConsumoDeAguaDoce: 0.113; UtilizacaoLiquidaDeAguaDoce: 0.113; ResiduosPerigososEliminados: 0.00221; ResiduosNaoPerigososEliminados: 1.83; MassaTotalDeResiduosRadioactivosEliminados: 0.000394; EnergiaElectricaExportada: 1.55; MateriaisParaRecuperacaoDeEnergia: 0.00739; MateriaisParaReciclagem: 0.0253; UnidadeEPD: 1 m²
Type - IFC.REVIGRÉS-Dados gerais-Floor Covering - Nome: REVIGRÉS-OMNISTONE-BASE-45X90-SOFT-BONE; TipoProduto: Prensado a seco: grupo BIa UGL | Grés porcelânico técnico; NumeroDeRegistoDAP: EPD-REV-20240006-CCC1-EN; ReferenciaDAP: -; UrlDOP: -
Classification: C3020 (Uniformat)
Pset_CoveringCommon - TotalThickness: 10.5 mm
IFC.REVIGRÉS-Dados do fabricante-Floor Covering - Type: Floor: REVIGRÉS-OMNISTONE-BASE-45X90-SOFT-BONE
IFC.REVIGRÉS-Dados de desempenho-Floor Covering - Type: Floor: REVIGRÉS-OMNISTONE-BASE-45X90-SOFT-BONE
IFC.REVIGRÉS-Dados de especificação-Floor Covering - Type: Floor: REVIGRÉS-OMNISTONE-BASE-45X90-SOFT-BONE
IFC.REVIGRÉS-Dados geométricos-Floor Covering - Type: Floor: REVIGRÉS-OMNISTONE-BASE-45X90-SOFT-BONE
IFC.REVIGRÉS-Dados de sustentabilidade-Floor Covering - Type: Floor: REVIGRÉS-OMNISTONE-BASE-45X90-SOFT-BONE

# IfcCovering: Floor:REVIGRÉS-OMNISTONE-BASE-45X90-SOFT-ICE, Floor:REVIGRÉS-OMNISTONE-BASE-45X90-SOFT-ICE:148539
In: Level 1
Type - PredefinedType: CLADDING; Material: REVIGRÉS-OMNISTONE-BASE-45x90-SOFT-ICE 10.5 mm
Type - Pset_CoveringCommon - Reference: 3126H889U1; Material: Grés porcelânico
Type - Pset_ElementShading - Roughness: 304.8 mm
Type - Pset_ManufacturerTypeInformation - Manufacturer: REVIGRÉS
Type - Pset_ProductRequirements - Category: Floors
Type - Pset_QuantityTakeOff - Reference: 3126H889U1
Type - IFC.REVIGRÉS-Dados do fabricante-Floor Covering - FabricanteURL: https://www.revigres.pt/; ReferenciaModelo: Omnistone; NumeroGlobalDeItemComercial: 3126H889U1; Acabamento: SOFT; Material: Grés porcelânico; IdentificadorDoOperadorEconomico: 501840856; UrlFabricanteArtigo: https://www.revigres.pt/colecoes/omnistone; PaisOrigem: Portugal
Type - IFC.REVIGRÉS-Dados de desempenho-Floor Covering - Rectilinearidade: ± 0.2% máx.± 0.8 mm; Ortogonalidade: ± 0.2% máx.± 1.5 mm; PlanaridadeDaSuperficie: ± 0.3% máx. ± 1.8 mm; QualidadeDaSuperficie: Cumpre; AbsorcaoDeAgua: < 0.05%; ModuloDeRuptura: > 45 N/mm130; ResistenciaAFlexao: ≥ 3500 N; ResistenciaAAbrasaoProfunda: < 120 mm131; DilatacaoTermicaLinear: ≤ 8,0x10-6 °C-1; ResistenciaAoChoqueTermico: Resiste; DurabilidadeResistenciaAoGeloDegelo: Resiste; ResistenciaAsManchas: Class 5; ResistenciaABaixasConcentracoesDeAcidosEAlcalis: Classe LA; ResistenciaAAltasConcentracoesDeAcidosEAlcalis: Classe HA; LibertacaoDeCadmio: 0; LibertacaoDeChumbo: 0
Type - IFC.REVIGRÉS-Dados de especificação-Floor Covering - VariacaoTonalidade: 3; NivelDeTrafego: 5; EPavimento: Sim; ERevestimento: Sim; EExterno: Sim
Type - IFC.REVIGRÉS-Dados geométricos-Floor Covering - AlturaNominal: 10.5 mm; ComprimentoNominal: 44.35 mm; LarguraNominal: 88.9 mm
Type - IFC.REVIGRÉS-Dados de sustentabilidade-Floor Covering - ItemEParcialmenteReciclado: 0; EnergiaTermicaExportada: 0; ItemENovo: Sim; ItemEReciclado: Não; VidaÚtilEsperada: 50; SubstanciasPerigosas: Não; PotencialDeEsgotamentoAbioticoDosRecursosNaoFosseisMineraisEMetais: 0.000701; PotencialDeAquecimentoGlobalBiogenico: -0.48; CombustiveisFosseisComPotencialDeAquecimentoGlobal: 13.9; PotencialDeAquecimentoGlobalUsoDoSoloEMudancaDeUsoDoSolo: 0.0246; PotencialDeEutrofizacaoFraccaoDeNutrientesQueAtingemOCompartimentoFinalDeAguaDoce: 0.000189; PotencialDeEutrofizacaoFraccaoDeNutrientesQueAtingemOCompartimentoFinalMarinho: 0.0122; EnergiaRecuperada: 0.00739; ConsumoDeAguaDoce: 0.113; UtilizacaoLiquidaDeAguaDoce: 0.113; ResiduosPerigososEliminados: 0.00221; ResiduosNaoPerigososEliminados: 1.83; MassaTotalDeResiduosRadioactivosEliminados: 0.000394; EnergiaElectricaExportada: 1.55; MateriaisParaRecuperacaoDeEnergia: 0.00739; MateriaisParaReciclagem: 0.0253; UnidadeEPD: 1 m²
Type - IFC.REVIGRÉS-Dados gerais-Floor Covering - Nome: REVIGRÉS-OMNISTONE-BASE-45X90-SOFT-ICE; TipoProduto: Prensado a seco: grupo BIa UGL | Grés porcelânico técnico; NumeroDeRegistoDAP: EPD-REV-20240006-CCC1-EN; ReferenciaDAP: -; UrlDOP: -
Classification: C3020 (Uniformat)
Pset_CoveringCommon - TotalThickness: 10.5 mm
IFC.REVIGRÉS-Dados do fabricante-Floor Covering - Type: Floor: REVIGRÉS-OMNISTONE-BASE-45X90-SOFT-ICE
IFC.REVIGRÉS-Dados de desempenho-Floor Covering - Type: Floor: REVIGRÉS-OMNISTONE-BASE-45X90-SOFT-ICE
IFC.REVIGRÉS-Dados de especificação-Floor Covering - Type: Floor: REVIGRÉS-OMNISTONE-BASE-45X90-SOFT-ICE
IFC.REVIGRÉS-Dados geométricos-Floor Covering - Type: Floor: REVIGRÉS-OMNISTONE-BASE-45X90-SOFT-ICE
IFC.REVIGRÉS-Dados de sustentabilidade-Floor Covering - Type: Floor: REVIGRÉS-OMNISTONE-BASE-45X90-SOFT-ICE

# IfcCovering: Floor:REVIGRÉS-OMNISTONE-BASE-45X90-SOFT-IRON, Floor:REVIGRÉS-OMNISTONE-BASE-45X90-SOFT-IRON:149224
In: Level 1
Type - PredefinedType: CLADDING; Material: REVIGRÉS-OMNISTONE-BASE-45x90-SOFT-IRON 10.5 mm
Type - Pset_CoveringCommon - Reference: 3126H890U1; Material: Grés porcelânico
Type - Pset_ElementShading - Roughness: 304.8 mm
Type - Pset_ManufacturerTypeInformation - Manufacturer: REVIGRÉS
Type - Pset_ProductRequirements - Category: Floors
Type - Pset_QuantityTakeOff - Reference: 3126H890U1
Type - IFC.REVIGRÉS-Dados do fabricante-Floor Covering - FabricanteURL: https://www.revigres.pt/; ReferenciaModelo: Omnistone; NumeroGlobalDeItemComercial: 3126H890U1; Acabamento: SOFT; Material: Grés porcelânico; IdentificadorDoOperadorEconomico: 501840856; UrlFabricanteArtigo: https://www.revigres.pt/colecoes/omnistone; PaisOrigem: Portugal
Type - IFC.REVIGRÉS-Dados de desempenho-Floor Covering - Rectilinearidade: ± 0.2% máx.± 0.8 mm; Ortogonalidade: ± 0.2% máx.± 1.5 mm; PlanaridadeDaSuperficie: ± 0.3% máx. ± 1.8 mm; QualidadeDaSuperficie: Cumpre; AbsorcaoDeAgua: < 0.05%; ModuloDeRuptura: > 45 N/mm130; ResistenciaAFlexao: ≥ 3500 N; ResistenciaAAbrasaoProfunda: < 120 mm131; DilatacaoTermicaLinear: ≤ 8,0x10-6 °C-1; ResistenciaAoChoqueTermico: Resiste; DurabilidadeResistenciaAoGeloDegelo: Resiste; ResistenciaAsManchas: Class 5; ResistenciaABaixasConcentracoesDeAcidosEAlcalis: Classe LA; ResistenciaAAltasConcentracoesDeAcidosEAlcalis: Classe HA; LibertacaoDeCadmio: 0; LibertacaoDeChumbo: 0
Type - IFC.REVIGRÉS-Dados de especificação-Floor Covering - VariacaoTonalidade: 3; NivelDeTrafego: 5; EPavimento: Sim; ERevestimento: Sim; EExterno: Sim
Type - IFC.REVIGRÉS-Dados geométricos-Floor Covering - AlturaNominal: 10.5 mm; ComprimentoNominal: 44.35 mm; LarguraNominal: 88.9 mm
Type - IFC.REVIGRÉS-Dados de sustentabilidade-Floor Covering - EnergiaTermicaExportada: 0; ItemENovo: Sim; ItemEParcialmenteReciclado: 0.14; ItemEReciclado: Sim; VidaÚtilEsperada: 50; SubstanciasPerigosas: Não; PotencialDeEsgotamentoAbioticoDosRecursosNaoFosseisMineraisEMetais: 0.000701; PotencialDeAquecimentoGlobalBiogenico: -0.48; CombustiveisFosseisComPotencialDeAquecimentoGlobal: 13.9; PotencialDeAquecimentoGlobalUsoDoSoloEMudancaDeUsoDoSolo: 0.0246; PotencialDeEutrofizacaoFraccaoDeNutrientesQueAtingemOCompartimentoFinalDeAguaDoce: 0.000189; PotencialDeEutrofizacaoFraccaoDeNutrientesQueAtingemOCompartimentoFinalMarinho: 0.0122; EnergiaRecuperada: 0.00739; ConsumoDeAguaDoce: 0.113; UtilizacaoLiquidaDeAguaDoce: 0.113; ResiduosPerigososEliminados: 0.00221; ResiduosNaoPerigososEliminados: 1.83; MassaTotalDeResiduosRadioactivosEliminados: 0.000394; EnergiaElectricaExportada: 1.55; MateriaisParaRecuperacaoDeEnergia: 0.00739; MateriaisParaReciclagem: 0.0253; UnidadeEPD: 1 m²
Type - IFC.REVIGRÉS-Dados gerais-Floor Covering - Nome: REVIGRÉS-OMNISTONE-BASE-45X90-SOFT-IRON; TipoProduto: Prensado a seco: grupo BIa UGL | Grés porcelânico técnico; NumeroDeRegistoDAP: EPD-REV-20240006-CCC1-EN; ReferenciaDAP: -; UrlDOP: -
Classification: C3020 (Uniformat)
Pset_CoveringCommon - TotalThickness: 10.5 mm
IFC.REVIGRÉS-Dados do fabricante-Floor Covering - Type: Floor: REVIGRÉS-OMNISTONE-BASE-45X90-SOFT-IRON
IFC.REVIGRÉS-Dados de desempenho-Floor Covering - Type: Floor: REVIGRÉS-OMNISTONE-BASE-45X90-SOFT-IRON
IFC.REVIGRÉS-Dados de especificação-Floor Covering - Type: Floor: REVIGRÉS-OMNISTONE-BASE-45X90-SOFT-IRON
IFC.REVIGRÉS-Dados geométricos-Floor Covering - Type: Floor: REVIGRÉS-OMNISTONE-BASE-45X90-SOFT-IRON
IFC.REVIGRÉS-Dados de sustentabilidade-Floor Covering - Type: Floor: REVIGRÉS-OMNISTONE-BASE-45X90-SOFT-IRON

# IfcCovering: Floor:REVIGRÉS-OMNISTONE-BASE-45X90-SOFT-JET, Floor:REVIGRÉS-OMNISTONE-BASE-45X90-SOFT-JET:149966
In: Level 1
Type - PredefinedType: CLADDING; Material: REVIGRÉS-OMNISTONE-BASE-45x90-SOFT-JET 10.5 mm
Type - Pset_CoveringCommon - Reference: 3126H891U1; Material: Grés porcelânico
Type - Pset_ElementShading - Roughness: 304.8 mm
Type - Pset_ManufacturerTypeInformation - Manufacturer: REVIGRÉS
Type - Pset_ProductRequirements - Category: Floors
Type - Pset_QuantityTakeOff - Reference: 3126H891U1
Type - IFC.REVIGRÉS-Dados do fabricante-Floor Covering - FabricanteURL: https://www.revigres.pt/; ReferenciaModelo: Omnistone; NumeroGlobalDeItemComercial: 3126H891U1; Acabamento: SOFT; Material: Grés porcelânico; IdentificadorDoOperadorEconomico: 501840856; UrlFabricanteArtigo: https://www.revigres.pt/colecoes/omnistone; PaisOrigem: Portugal
Type - IFC.REVIGRÉS-Dados de desempenho-Floor Covering - Rectilinearidade: ± 0.2% máx.± 0.8 mm; Ortogonalidade: ± 0.2% máx.± 1.5 mm; PlanaridadeDaSuperficie: ± 0.3% máx. ± 1.8 mm; QualidadeDaSuperficie: Cumpre; AbsorcaoDeAgua: < 0.05%; ModuloDeRuptura: > 45 N/mm130; ResistenciaAFlexao: ≥ 3500 N; ResistenciaAAbrasaoProfunda: < 120 mm131; DilatacaoTermicaLinear: ≤ 8,0x10-6 °C-1; ResistenciaAoChoqueTermico: Resiste; DurabilidadeResistenciaAoGeloDegelo: Resiste; ResistenciaAsManchas: Class 5; ResistenciaABaixasConcentracoesDeAcidosEAlcalis: Classe LA; ResistenciaAAltasConcentracoesDeAcidosEAlcalis: Classe HA; LibertacaoDeCadmio: 0; LibertacaoDeChumbo: 0
Type - IFC.REVIGRÉS-Dados de especificação-Floor Covering - VariacaoTonalidade: 3; NivelDeTrafego: 5; EPavimento: Sim; ERevestimento: Sim; EExterno: Sim
Type - IFC.REVIGRÉS-Dados geométricos-Floor Covering - AlturaNominal: 10.5 mm; ComprimentoNominal: 44.35 mm; LarguraNominal: 88.9 mm
Type - IFC.REVIGRÉS-Dados de sustentabilidade-Floor Covering - ItemEParcialmenteReciclado: 0; EnergiaTermicaExportada: 0; ItemENovo: Sim; ItemEReciclado: Não; VidaÚtilEsperada: 50; SubstanciasPerigosas: Não; PotencialDeEsgotamentoAbioticoDosRecursosNaoFosseisMineraisEMetais: 0.000701; PotencialDeAquecimentoGlobalBiogenico: -0.48; CombustiveisFosseisComPotencialDeAquecimentoGlobal: 13.9; PotencialDeAquecimentoGlobalUsoDoSoloEMudancaDeUsoDoSolo: 0.0246; PotencialDeEutrofizacaoFraccaoDeNutrientesQueAtingemOCompartimentoFinalDeAguaDoce: 0.000189; PotencialDeEutrofizacaoFraccaoDeNutrientesQueAtingemOCompartimentoFinalMarinho: 0.0122; EnergiaRecuperada: 0.00739; ConsumoDeAguaDoce: 0.113; UtilizacaoLiquidaDeAguaDoce: 0.113; ResiduosPerigososEliminados: 0.00221; ResiduosNaoPerigososEliminados: 1.83; MassaTotalDeResiduosRadioactivosEliminados: 0.000394; EnergiaElectricaExportada: 1.55; MateriaisParaRecuperacaoDeEnergia: 0.00739; MateriaisParaReciclagem: 0.0253; UnidadeEPD: 1 m²
Type - IFC.REVIGRÉS-Dados gerais-Floor Covering - Nome: REVIGRÉS-OMNISTONE-BASE-45X90-SOFT-JET; TipoProduto: Prensado a seco: grupo BIa UGL | Grés porcelânico técnico; NumeroDeRegistoDAP: EPD-REV-20240006-CCC1-EN; ReferenciaDAP: -; UrlDOP: -
Classification: C3020 (Uniformat)
Pset_CoveringCommon - TotalThickness: 10.5 mm
IFC.REVIGRÉS-Dados do fabricante-Floor Covering - Type: Floor: REVIGRÉS-OMNISTONE-BASE-45X90-SOFT-JET
IFC.REVIGRÉS-Dados de desempenho-Floor Covering - Type: Floor: REVIGRÉS-OMNISTONE-BASE-45X90-SOFT-JET
IFC.REVIGRÉS-Dados de especificação-Floor Covering - Type: Floor: REVIGRÉS-OMNISTONE-BASE-45X90-SOFT-JET
IFC.REVIGRÉS-Dados geométricos-Floor Covering - Type: Floor: REVIGRÉS-OMNISTONE-BASE-45X90-SOFT-JET
IFC.REVIGRÉS-Dados de sustentabilidade-Floor Covering - Type: Floor: REVIGRÉS-OMNISTONE-BASE-45X90-SOFT-JET

# IfcCovering: Floor:REVIGRÉS-OMNISTONE-BASE-45X90-SOFT-PLATINA, Floor:REVIGRÉS-OMNISTONE-BASE-45X90-SOFT-PLATINA:150687
In: Level 1
Type - PredefinedType: CLADDING; Material: REVIGRÉS-OMNISTONE-BASE-45x90-SOFT-PLATINA 10.5 mm
Type - Pset_CoveringCommon - Reference: 3126H892U1; Material: Grés porcelânico
Type - Pset_ElementShading - Roughness: 304.8 mm
Type - Pset_ManufacturerTypeInformation - Manufacturer: REVIGRÉS
Type - Pset_ProductRequirements - Category: Floors
Type - Pset_QuantityTakeOff - Reference: 3126H892U1
Type - IFC.REVIGRÉS-Dados do fabricante-Floor Covering - FabricanteURL: https://www.revigres.pt/; ReferenciaModelo: Omnistone; NumeroGlobalDeItemComercial: 3126H892U1; Acabamento: SOFT; Material: Grés porcelânico; IdentificadorDoOperadorEconomico: 501840856; UrlFabricanteArtigo: https://www.revigres.pt/colecoes/omnistone; PaisOrigem: Portugal
Type - IFC.REVIGRÉS-Dados de desempenho-Floor Covering - Rectilinearidade: ± 0.2% máx.± 0.8 mm; Ortogonalidade: ± 0.2% máx.± 1.5 mm; PlanaridadeDaSuperficie: ± 0.3% máx. ± 1.8 mm; QualidadeDaSuperficie: Cumpre; AbsorcaoDeAgua: < 0.05%; ModuloDeRuptura: > 45 N/mm130; ResistenciaAFlexao: ≥ 3500 N; ResistenciaAAbrasaoProfunda: < 120 mm131; DilatacaoTermicaLinear: ≤ 8,0x10-6 °C-1; ResistenciaAoChoqueTermico: Resiste; DurabilidadeResistenciaAoGeloDegelo: Resiste; ResistenciaAsManchas: Class 5; ResistenciaABaixasConcentracoesDeAcidosEAlcalis: Classe LA; ResistenciaAAltasConcentracoesDeAcidosEAlcalis: Classe HA; LibertacaoDeCadmio: 0; LibertacaoDeChumbo: 0
Type - IFC.REVIGRÉS-Dados de especificação-Floor Covering - VariacaoTonalidade: 3; NivelDeTrafego: 5; EPavimento: Sim; ERevestimento: Sim; EExterno: Sim
Type - IFC.REVIGRÉS-Dados geométricos-Floor Covering - AlturaNominal: 10.5 mm; ComprimentoNominal: 44.35 mm; LarguraNominal: 88.9 mm
Type - IFC.REVIGRÉS-Dados de sustentabilidade-Floor Covering - ItemEParcialmenteReciclado: 0; EnergiaTermicaExportada: 0; ItemENovo: Sim; ItemEReciclado: Não; VidaÚtilEsperada: 50; SubstanciasPerigosas: Não; PotencialDeEsgotamentoAbioticoDosRecursosNaoFosseisMineraisEMetais: 0.000701; PotencialDeAquecimentoGlobalBiogenico: -0.48; CombustiveisFosseisComPotencialDeAquecimentoGlobal: 13.9; PotencialDeAquecimentoGlobalUsoDoSoloEMudancaDeUsoDoSolo: 0.0246; PotencialDeEutrofizacaoFraccaoDeNutrientesQueAtingemOCompartimentoFinalDeAguaDoce: 0.000189; PotencialDeEutrofizacaoFraccaoDeNutrientesQueAtingemOCompartimentoFinalMarinho: 0.0122; EnergiaRecuperada: 0.00739; ConsumoDeAguaDoce: 0.113; UtilizacaoLiquidaDeAguaDoce: 0.113; ResiduosPerigososEliminados: 0.00221; ResiduosNaoPerigososEliminados: 1.83; MassaTotalDeResiduosRadioactivosEliminados: 0.000394; EnergiaElectricaExportada: 1.55; MateriaisParaRecuperacaoDeEnergia: 0.00739; MateriaisParaReciclagem: 0.0253; UnidadeEPD: 1 m²
Type - IFC.REVIGRÉS-Dados gerais-Floor Covering - Nome: REVIGRÉS-OMNISTONE-BASE-45X90-SOFT-PLATINA; TipoProduto: Prensado a seco: grupo BIa UGL | Grés porcelânico técnico; NumeroDeRegistoDAP: EPD-REV-20240006-CCC1-EN; ReferenciaDAP: -; UrlDOP: -
Classification: C3020 (Uniformat)
Pset_CoveringCommon - TotalThickness: 10.5 mm
IFC.REVIGRÉS-Dados do fabricante-Floor Covering - Type: Floor: REVIGRÉS-OMNISTONE-BASE-45X90-SOFT-PLATINA
IFC.REVIGRÉS-Dados de desempenho-Floor Covering - Type: Floor: REVIGRÉS-OMNISTONE-BASE-45X90-SOFT-PLATINA
IFC.REVIGRÉS-Dados de especificação-Floor Covering - Type: Floor: REVIGRÉS-OMNISTONE-BASE-45X90-SOFT-PLATINA
IFC.REVIGRÉS-Dados geométricos-Floor Covering - Type: Floor: REVIGRÉS-OMNISTONE-BASE-45X90-SOFT-PLATINA
IFC.REVIGRÉS-Dados de sustentabilidade-Floor Covering - Type: Floor: REVIGRÉS-OMNISTONE-BASE-45X90-SOFT-PLATINA

# IfcCovering: Floor:REVIGRÉS-OMNISTONE-BASE-45X90-SOFT-ROPE, Floor:REVIGRÉS-OMNISTONE-BASE-45X90-SOFT-ROPE:151392
In: Level 1
Type - PredefinedType: CLADDING; Material: REVIGRÉS-OMNISTONE-BASE-45x90-SOFT-ROPE 10.5 mm
Type - Pset_CoveringCommon - Reference: 3126H893U1; Material: Grés porcelânico
Type - Pset_ElementShading - Roughness: 304.8 mm
Type - Pset_ManufacturerTypeInformation - Manufacturer: REVIGRÉS
Type - Pset_ProductRequirements - Category: Floors
Type - Pset_QuantityTakeOff - Reference: 3126H893U1
Type - IFC.REVIGRÉS-Dados do fabricante-Floor Covering - FabricanteURL: https://www.revigres.pt/; ReferenciaModelo: Omnistone; NumeroGlobalDeItemComercial: 3126H893U1; Acabamento: SOFT; Material: Grés porcelânico; IdentificadorDoOperadorEconomico: 501840856; UrlFabricanteArtigo: https://www.revigres.pt/colecoes/omnistone; PaisOrigem: Portugal
Type - IFC.REVIGRÉS-Dados de desempenho-Floor Covering - Rectilinearidade: ± 0.2% máx.± 0.8 mm; Ortogonalidade: ± 0.2% máx.± 1.5 mm; PlanaridadeDaSuperficie: ± 0.3% máx. ± 1.8 mm; QualidadeDaSuperficie: Cumpre; AbsorcaoDeAgua: < 0.05%; ModuloDeRuptura: > 45 N/mm130; ResistenciaAFlexao: ≥ 3500 N; ResistenciaAAbrasaoProfunda: < 120 mm131; DilatacaoTermicaLinear: ≤ 8,0x10-6 °C-1; ResistenciaAoChoqueTermico: Resiste; DurabilidadeResistenciaAoGeloDegelo: Resiste; ResistenciaAsManchas: Class 5; ResistenciaABaixasConcentracoesDeAcidosEAlcalis: Classe LA; ResistenciaAAltasConcentracoesDeAcidosEAlcalis: Classe HA; LibertacaoDeCadmio: 0; LibertacaoDeChumbo: 0
Type - IFC.REVIGRÉS-Dados de especificação-Floor Covering - VariacaoTonalidade: 3; NivelDeTrafego: 5; EPavimento: Sim; ERevestimento: Sim; EExterno: Sim
Type - IFC.REVIGRÉS-Dados geométricos-Floor Covering - AlturaNominal: 10.5 mm; ComprimentoNominal: 44.35 mm; LarguraNominal: 88.9 mm
Type - IFC.REVIGRÉS-Dados de sustentabilidade-Floor Covering - ItemEParcialmenteReciclado: 0; EnergiaTermicaExportada: 0; ItemENovo: Sim; ItemEReciclado: Não; VidaÚtilEsperada: 50; SubstanciasPerigosas: Não; PotencialDeEsgotamentoAbioticoDosRecursosNaoFosseisMineraisEMetais: 0.000701; PotencialDeAquecimentoGlobalBiogenico: -0.48; CombustiveisFosseisComPotencialDeAquecimentoGlobal: 13.9; PotencialDeAquecimentoGlobalUsoDoSoloEMudancaDeUsoDoSolo: 0.0246; PotencialDeEutrofizacaoFraccaoDeNutrientesQueAtingemOCompartimentoFinalDeAguaDoce: 0.000189; PotencialDeEutrofizacaoFraccaoDeNutrientesQueAtingemOCompartimentoFinalMarinho: 0.0122; EnergiaRecuperada: 0.00739; ConsumoDeAguaDoce: 0.113; UtilizacaoLiquidaDeAguaDoce: 0.113; ResiduosPerigososEliminados: 0.00221; ResiduosNaoPerigososEliminados: 1.83; MassaTotalDeResiduosRadioactivosEliminados: 0.000394; EnergiaElectricaExportada: 1.55; MateriaisParaRecuperacaoDeEnergia: 0.00739; MateriaisParaReciclagem: 0.0253; UnidadeEPD: 1 m²
Type - IFC.REVIGRÉS-Dados gerais-Floor Covering - Nome: REVIGRÉS-OMNISTONE-BASE-45X90-SOFT-ROPE; TipoProduto: Prensado a seco: grupo BIa UGL | Grés porcelânico técnico; NumeroDeRegistoDAP: EPD-REV-20240006-CCC1-EN; ReferenciaDAP: -; UrlDOP: -
Classification: C3020 (Uniformat)
Pset_CoveringCommon - TotalThickness: 10.5 mm
IFC.REVIGRÉS-Dados do fabricante-Floor Covering - Type: Floor: REVIGRÉS-OMNISTONE-BASE-45X90-SOFT-ROPE
IFC.REVIGRÉS-Dados de desempenho-Floor Covering - Type: Floor: REVIGRÉS-OMNISTONE-BASE-45X90-SOFT-ROPE
IFC.REVIGRÉS-Dados de especificação-Floor Covering - Type: Floor: REVIGRÉS-OMNISTONE-BASE-45X90-SOFT-ROPE
IFC.REVIGRÉS-Dados geométricos-Floor Covering - Type: Floor: REVIGRÉS-OMNISTONE-BASE-45X90-SOFT-ROPE
IFC.REVIGRÉS-Dados de sustentabilidade-Floor Covering - Type: Floor: REVIGRÉS-OMNISTONE-BASE-45X90-SOFT-ROPE

# IfcCovering: Floor:REVIGRÉS-OMNISTONE-BASE-60X120-MATTRECT-BONE, Floor:REVIGRÉS-OMNISTONE-BASE-60X120-MATTRECT-BONE:146364
In: Level 1
Type - PredefinedType: CLADDING; Material: REVIGRÉS-OMNISTONE-BASE-60x120-MATTRECT-BONE 9.8 mm
Type - Pset_CoveringCommon - Reference: 312B1388U1; Material: Grés porcelânico
Type - Pset_ElementShading - Roughness: 304.8 mm
Type - Pset_ManufacturerTypeInformation - Manufacturer: REVIGRÉS
Type - Pset_ProductRequirements - Category: Floors
Type - Pset_QuantityTakeOff - Reference: 312B1388U1
Type - IFC.REVIGRÉS-Dados do fabricante-Floor Covering - FabricanteURL: https://www.revigres.pt/; ReferenciaModelo: Omnistone; NumeroGlobalDeItemComercial: 312BD388U1; Acabamento: MATT RECT; Material: Grés porcelânico; IdentificadorDoOperadorEconomico: 501840856; UrlFabricanteArtigo: https://www.revigres.pt/colecoes/omnistone; PaisOrigem: Portugal
Type - IFC.REVIGRÉS-Dados de desempenho-Floor Covering - Rectilinearidade: ± 0.2% máx.± 0.8 mm; Ortogonalidade: ± 0.2% máx.± 1.5 mm; PlanaridadeDaSuperficie: ± 0.3% máx. ± 1.8 mm; QualidadeDaSuperficie: Cumpre; AbsorcaoDeAgua: < 0.05%; ModuloDeRuptura: > 45 N/mm130; ResistenciaAFlexao: ≥ 3500 N; ResistenciaAAbrasaoProfunda: < 120 mm131; DilatacaoTermicaLinear: ≤ 8,0x10-6 °C-1; ResistenciaAoChoqueTermico: Resiste; DurabilidadeResistenciaAoGeloDegelo: Resiste; ResistenciaAoEscorregamentoDIN51130: R10; ResistenciaAoEscorregamentoDIN51097: B; ResistenciaAoEscorregamentoENV51097: B; ResistenciaAoEscorregamentoENV12633: Class 2; ResistenciaAoEscorregamentoBS7976: >36; ResistenciaAoEscorregamentoANSIA1371: ≥0,42; ResistenciaAoDeslizamentoENV12633: Class 2; ResistenciaAoDeslizamentoBS7976: >36; ResistenciaAsManchas: Class 5; ResistenciaABaixasConcentracoesDeAcidosEAlcalis: Classe LA; ResistenciaAAltasConcentracoesDeAcidosEAlcalis: Classe HA; LibertacaoDeCadmio: 0; LibertacaoDeChumbo: 0
Type - IFC.REVIGRÉS-Dados de especificação-Floor Covering - VariacaoTonalidade: 3; NivelDeTrafego: 5; EPavimento: Sim; ERevestimento: Sim; EExterno: Sim
Type - IFC.REVIGRÉS-Dados geométricos-Floor Covering - AlturaNominal: 9.8 mm; ComprimentoNominal: 59.2 mm; LarguraNominal: 118.6 mm
Type - IFC.REVIGRÉS-Dados de sustentabilidade-Floor Covering - ItemEParcialmenteReciclado: 0; EnergiaTermicaExportada: 0; ItemENovo: Sim; ItemEReciclado: Não; VidaÚtilEsperada: 50; SubstanciasPerigosas: Não; PotencialDeEsgotamentoAbioticoDosRecursosNaoFosseisMineraisEMetais: 0.000701; PotencialDeAquecimentoGlobalBiogenico: -0.48; CombustiveisFosseisComPotencialDeAquecimentoGlobal: 13.9; PotencialDeAquecimentoGlobalUsoDoSoloEMudancaDeUsoDoSolo: 0.0246; PotencialDeEutrofizacaoFraccaoDeNutrientesQueAtingemOCompartimentoFinalDeAguaDoce: 0.000189; PotencialDeEutrofizacaoFraccaoDeNutrientesQueAtingemOCompartimentoFinalMarinho: 0.0122; EnergiaRecuperada: 0.00739; ConsumoDeAguaDoce: 0.113; UtilizacaoLiquidaDeAguaDoce: 0.113; ResiduosPerigososEliminados: 0.00221; ResiduosNaoPerigososEliminados: 1.83; MassaTotalDeResiduosRadioactivosEliminados: 0.000394; EnergiaElectricaExportada: 1.55; MateriaisParaRecuperacaoDeEnergia: 0.00739; MateriaisParaReciclagem: 0.0253; UnidadeEPD: 1 m²
Type - IFC.REVIGRÉS-Dados gerais-Floor Covering - Nome: REVIGRÉS-OMNISTONE-BASE-60X120-MATT RECT-BONE; TipoProduto: Prensado a seco: grupo BIa UGL | Grés porcelânico técnico; NumeroDeRegistoDAP: EPD-REV-20240006-CCC1-EN; ReferenciaDAP: -; UrlDOP: -
Classification: C3020 (Uniformat)
Pset_CoveringCommon - TotalThickness: 9.8 mm
IFC.REVIGRÉS-Dados do fabricante-Floor Covering - Type: Floor: REVIGRÉS-OMNISTONE-BASE-60X120-MATTRECT-BONE
IFC.REVIGRÉS-Dados de desempenho-Floor Covering - Type: Floor: REVIGRÉS-OMNISTONE-BASE-60X120-MATTRECT-BONE
IFC.REVIGRÉS-Dados de especificação-Floor Covering - Type: Floor: REVIGRÉS-OMNISTONE-BASE-60X120-MATTRECT-BONE
IFC.REVIGRÉS-Dados geométricos-Floor Covering - Type: Floor: REVIGRÉS-OMNISTONE-BASE-60X120-MATTRECT-BONE
IFC.REVIGRÉS-Dados de sustentabilidade-Floor Covering - Type: Floor: REVIGRÉS-OMNISTONE-BASE-60X120-MATTRECT-BONE

# IfcCovering: Floor:REVIGRÉS-OMNISTONE-BASE-60X120-MATTRECT-ICE, Floor:REVIGRÉS-OMNISTONE-BASE-60X120-MATTRECT-ICE:148443
In: Level 1
Type - PredefinedType: CLADDING; Material: REVIGRÉS-OMNISTONE-BASE-60x120-MATTRECT-ICE 9.8 mm
Type - Pset_CoveringCommon - Reference: 312B1389U1; Material: Grés porcelânico
Type - Pset_ElementShading - Roughness: 304.8 mm
Type - Pset_ManufacturerTypeInformation - Manufacturer: REVIGRÉS
Type - Pset_ProductRequirements - Category: Floors
Type - Pset_QuantityTakeOff - Reference: 312B1389U1
Type - IFC.REVIGRÉS-Dados do fabricante-Floor Covering - FabricanteURL: https://www.revigres.pt/; ReferenciaModelo: Omnistone; NumeroGlobalDeItemComercial: 312BD389U1; Acabamento: MATT RECT; Material: Grés porcelânico; IdentificadorDoOperadorEconomico: 501840856; UrlFabricanteArtigo: https://www.revigres.pt/colecoes/omnistone; PaisOrigem: Portugal
Type - IFC.REVIGRÉS-Dados de desempenho-Floor Covering - Rectilinearidade: ± 0.2% máx.± 0.8 mm; Ortogonalidade: ± 0.2% máx.± 1.5 mm; PlanaridadeDaSuperficie: ± 0.3% máx. ± 1.8 mm; QualidadeDaSuperficie: Cumpre; AbsorcaoDeAgua: < 0.05%; ModuloDeRuptura: > 45 N/mm130; ResistenciaAFlexao: ≥ 3500 N; ResistenciaAAbrasaoProfunda: < 120 mm131; DilatacaoTermicaLinear: ≤ 8,0x10-6 °C-1; ResistenciaAoChoqueTermico: Resiste; DurabilidadeResistenciaAoGeloDegelo: Resiste; ResistenciaAoEscorregamentoDIN51130: R10; ResistenciaAoEscorregamentoDIN51097: B; ResistenciaAoEscorregamentoENV51097: B; ResistenciaAoEscorregamentoENV12633: Class 2; ResistenciaAoEscorregamentoBS7976: >36; ResistenciaAoEscorregamentoANSIA1371: ≥0,42; ResistenciaAoDeslizamentoENV12633: Class 2; ResistenciaAoDeslizamentoBS7976: >36; ResistenciaAsManchas: Class 5; ResistenciaABaixasConcentracoesDeAcidosEAlcalis: Classe LA; ResistenciaAAltasConcentracoesDeAcidosEAlcalis: Classe HA; LibertacaoDeCadmio: 0; LibertacaoDeChumbo: 0
Type - IFC.REVIGRÉS-Dados de especificação-Floor Covering - VariacaoTonalidade: 3; NivelDeTrafego: 5; EPavimento: Sim; ERevestimento: Sim; EExterno: Sim
Type - IFC.REVIGRÉS-Dados geométricos-Floor Covering - AlturaNominal: 9.8 mm; ComprimentoNominal: 59.2 mm; LarguraNominal: 118.6 mm
Type - IFC.REVIGRÉS-Dados de sustentabilidade-Floor Covering - ItemEParcialmenteReciclado: 0; EnergiaTermicaExportada: 0; ItemENovo: Sim; ItemEReciclado: Não; VidaÚtilEsperada: 50; SubstanciasPerigosas: Não; PotencialDeEsgotamentoAbioticoDosRecursosNaoFosseisMineraisEMetais: 0.000701; PotencialDeAquecimentoGlobalBiogenico: -0.48; CombustiveisFosseisComPotencialDeAquecimentoGlobal: 13.9; PotencialDeAquecimentoGlobalUsoDoSoloEMudancaDeUsoDoSolo: 0.0246; PotencialDeEutrofizacaoFraccaoDeNutrientesQueAtingemOCompartimentoFinalDeAguaDoce: 0.000189; PotencialDeEutrofizacaoFraccaoDeNutrientesQueAtingemOCompartimentoFinalMarinho: 0.0122; EnergiaRecuperada: 0.00739; ConsumoDeAguaDoce: 0.113; UtilizacaoLiquidaDeAguaDoce: 0.113; ResiduosPerigososEliminados: 0.00221; ResiduosNaoPerigososEliminados: 1.83; MassaTotalDeResiduosRadioactivosEliminados: 0.000394; EnergiaElectricaExportada: 1.55; MateriaisParaRecuperacaoDeEnergia: 0.00739; MateriaisParaReciclagem: 0.0253; UnidadeEPD: 1 m²
Type - IFC.REVIGRÉS-Dados gerais-Floor Covering - Nome: REVIGRÉS-OMNISTONE-BASE-60X120-MATT RECT-ICE; TipoProduto: Prensado a seco: grupo BIa UGL | Grés porcelânico técnico; NumeroDeRegistoDAP: EPD-REV-20240006-CCC1-EN; ReferenciaDAP: -; UrlDOP: -
Classification: C3020 (Uniformat)
Pset_CoveringCommon - TotalThickness: 9.8 mm
IFC.REVIGRÉS-Dados do fabricante-Floor Covering - Type: Floor: REVIGRÉS-OMNISTONE-BASE-60X120-MATTRECT-ICE
IFC.REVIGRÉS-Dados de desempenho-Floor Covering - Type: Floor: REVIGRÉS-OMNISTONE-BASE-60X120-MATTRECT-ICE
IFC.REVIGRÉS-Dados de especificação-Floor Covering - Type: Floor: REVIGRÉS-OMNISTONE-BASE-60X120-MATTRECT-ICE
IFC.REVIGRÉS-Dados geométricos-Floor Covering - Type: Floor: REVIGRÉS-OMNISTONE-BASE-60X120-MATTRECT-ICE
IFC.REVIGRÉS-Dados de sustentabilidade-Floor Covering - Type: Floor: REVIGRÉS-OMNISTONE-BASE-60X120-MATTRECT-ICE

# IfcCovering: Floor:REVIGRÉS-OMNISTONE-BASE-60X120-MATTRECT-IRON, Floor:REVIGRÉS-OMNISTONE-BASE-60X120-MATTRECT-IRON:149136
In: Level 1
Type - PredefinedType: CLADDING; Material: REVIGRÉS-OMNISTONE-BASE-60x120-MATTRECT-IRON 9.8 mm
Type - Pset_CoveringCommon - Reference: 312B1390U1; Material: Grés porcelânico
Type - Pset_ElementShading - Roughness: 304.8 mm
Type - Pset_ManufacturerTypeInformation - Manufacturer: REVIGRÉS
Type - Pset_ProductRequirements - Category: Floors
Type - Pset_QuantityTakeOff - Reference: 312B1390U1
Type - IFC.REVIGRÉS-Dados do fabricante-Floor Covering - FabricanteURL: https://www.revigres.pt/; ReferenciaModelo: Omnistone; NumeroGlobalDeItemComercial: 312BD390U1; Acabamento: MATT RECT; Material: Grés porcelânico; IdentificadorDoOperadorEconomico: 501840856; UrlFabricanteArtigo: https://www.revigres.pt/colecoes/omnistone; PaisOrigem: Portugal
Type - IFC.REVIGRÉS-Dados de desempenho-Floor Covering - Rectilinearidade: ± 0.2% máx.± 0.8 mm; Ortogonalidade: ± 0.2% máx.± 1.5 mm; PlanaridadeDaSuperficie: ± 0.3% máx. ± 1.8 mm; QualidadeDaSuperficie: Cumpre; AbsorcaoDeAgua: < 0.05%; ModuloDeRuptura: > 45 N/mm130; ResistenciaAFlexao: ≥ 3500 N; ResistenciaAAbrasaoProfunda: < 120 mm131; DilatacaoTermicaLinear: ≤ 8,0x10-6 °C-1; ResistenciaAoChoqueTermico: Resiste; DurabilidadeResistenciaAoGeloDegelo: Resiste; ResistenciaAoEscorregamentoDIN51130: R10; ResistenciaAoEscorregamentoDIN51097: B; ResistenciaAoEscorregamentoENV51097: B; ResistenciaAoEscorregamentoENV12633: Class 2; ResistenciaAoEscorregamentoBS7976: >36; ResistenciaAoEscorregamentoANSIA1371: ≥0,42; ResistenciaAoDeslizamentoENV12633: Class 2; ResistenciaAoDeslizamentoBS7976: >36; ResistenciaAsManchas: Class 5; ResistenciaABaixasConcentracoesDeAcidosEAlcalis: Classe LA; ResistenciaAAltasConcentracoesDeAcidosEAlcalis: Classe HA; LibertacaoDeCadmio: 0; LibertacaoDeChumbo: 0
Type - IFC.REVIGRÉS-Dados de especificação-Floor Covering - VariacaoTonalidade: 3; NivelDeTrafego: 5; EPavimento: Sim; ERevestimento: Sim; EExterno: Sim
Type - IFC.REVIGRÉS-Dados geométricos-Floor Covering - AlturaNominal: 9.8 mm; ComprimentoNominal: 59.2 mm; LarguraNominal: 118.6 mm
Type - IFC.REVIGRÉS-Dados de sustentabilidade-Floor Covering - EnergiaTermicaExportada: 0; ItemENovo: Sim; ItemEParcialmenteReciclado: 0.14; ItemEReciclado: Sim; VidaÚtilEsperada: 50; SubstanciasPerigosas: Não; PotencialDeEsgotamentoAbioticoDosRecursosNaoFosseisMineraisEMetais: 0.000701; PotencialDeAquecimentoGlobalBiogenico: -0.48; CombustiveisFosseisComPotencialDeAquecimentoGlobal: 13.9; PotencialDeAquecimentoGlobalUsoDoSoloEMudancaDeUsoDoSolo: 0.0246; PotencialDeEutrofizacaoFraccaoDeNutrientesQueAtingemOCompartimentoFinalDeAguaDoce: 0.000189; PotencialDeEutrofizacaoFraccaoDeNutrientesQueAtingemOCompartimentoFinalMarinho: 0.0122; EnergiaRecuperada: 0.00739; ConsumoDeAguaDoce: 0.113; UtilizacaoLiquidaDeAguaDoce: 0.113; ResiduosPerigososEliminados: 0.00221; ResiduosNaoPerigososEliminados: 1.83; MassaTotalDeResiduosRadioactivosEliminados: 0.000394; EnergiaElectricaExportada: 1.55; MateriaisParaRecuperacaoDeEnergia: 0.00739; MateriaisParaReciclagem: 0.0253; UnidadeEPD: 1 m²
Type - IFC.REVIGRÉS-Dados gerais-Floor Covering - Nome: REVIGRÉS-OMNISTONE-BASE-60X120-MATT RECT-IRON; TipoProduto: Prensado a seco: grupo BIa UGL | Grés porcelânico técnico; NumeroDeRegistoDAP: EPD-REV-20240006-CCC1-EN; ReferenciaDAP: -; UrlDOP: -
Classification: C3020 (Uniformat)
Pset_CoveringCommon - TotalThickness: 9.8 mm
IFC.REVIGRÉS-Dados do fabricante-Floor Covering - Type: Floor: REVIGRÉS-OMNISTONE-BASE-60X120-MATTRECT-IRON
IFC.REVIGRÉS-Dados de desempenho-Floor Covering - Type: Floor: REVIGRÉS-OMNISTONE-BASE-60X120-MATTRECT-IRON
IFC.REVIGRÉS-Dados de especificação-Floor Covering - Type: Floor: REVIGRÉS-OMNISTONE-BASE-60X120-MATTRECT-IRON
IFC.REVIGRÉS-Dados geométricos-Floor Covering - Type: Floor: REVIGRÉS-OMNISTONE-BASE-60X120-MATTRECT-IRON
IFC.REVIGRÉS-Dados de sustentabilidade-Floor Covering - Type: Floor: REVIGRÉS-OMNISTONE-BASE-60X120-MATTRECT-IRON

# IfcCovering: Floor:REVIGRÉS-OMNISTONE-BASE-60X120-MATTRECT-JET, Floor:REVIGRÉS-OMNISTONE-BASE-60X120-MATTRECT-JET:149878
In: Level 1
Type - PredefinedType: CLADDING; Material: REVIGRÉS-OMNISTONE-BASE-60x120-MATTRECT-JET 9.8 mm
Type - Pset_CoveringCommon - Reference: 312B1391U1; Material: Grés porcelânico
Type - Pset_ElementShading - Roughness: 304.8 mm
Type - Pset_ManufacturerTypeInformation - Manufacturer: REVIGRÉS
Type - Pset_ProductRequirements - Category: Floors
Type - Pset_QuantityTakeOff - Reference: 312B1391U1
Type - IFC.REVIGRÉS-Dados do fabricante-Floor Covering - FabricanteURL: https://www.revigres.pt/; ReferenciaModelo: Omnistone; NumeroGlobalDeItemComercial: 312BD391U1; Acabamento: MATT RECT; Material: Grés porcelânico; IdentificadorDoOperadorEconomico: 501840856; UrlFabricanteArtigo: https://www.revigres.pt/colecoes/omnistone; PaisOrigem: Portugal
Type - IFC.REVIGRÉS-Dados de desempenho-Floor Covering - Rectilinearidade: ± 0.2% máx.± 0.8 mm; Ortogonalidade: ± 0.2% máx.± 1.5 mm; PlanaridadeDaSuperficie: ± 0.3% máx. ± 1.8 mm; QualidadeDaSuperficie: Cumpre; AbsorcaoDeAgua: < 0.05%; ModuloDeRuptura: > 45 N/mm130; ResistenciaAFlexao: ≥ 3500 N; ResistenciaAAbrasaoProfunda: < 120 mm131; DilatacaoTermicaLinear: ≤ 8,0x10-6 °C-1; ResistenciaAoChoqueTermico: Resiste; DurabilidadeResistenciaAoGeloDegelo: Resiste; ResistenciaAoEscorregamentoDIN51130: R10; ResistenciaAoEscorregamentoDIN51097: B; ResistenciaAoEscorregamentoENV51097: B; ResistenciaAoEscorregamentoENV12633: Class 2; ResistenciaAoEscorregamentoBS7976: >36; ResistenciaAoEscorregamentoANSIA1371: ≥0,42; ResistenciaAoDeslizamentoENV12633: Class 2; ResistenciaAoDeslizamentoBS7976: >36; ResistenciaAsManchas: Class 5; ResistenciaABaixasConcentracoesDeAcidosEAlcalis: Classe LA; ResistenciaAAltasConcentracoesDeAcidosEAlcalis: Classe HA; LibertacaoDeCadmio: 0; LibertacaoDeChumbo: 0
Type - IFC.REVIGRÉS-Dados de especificação-Floor Covering - VariacaoTonalidade: 3; NivelDeTrafego: 5; EPavimento: Sim; ERevestimento: Sim; EExterno: Sim
Type - IFC.REVIGRÉS-Dados geométricos-Floor Covering - AlturaNominal: 9.8 mm; ComprimentoNominal: 59.2 mm; LarguraNominal: 118.6 mm
Type - IFC.REVIGRÉS-Dados de sustentabilidade-Floor Covering - ItemEParcialmenteReciclado: 0; EnergiaTermicaExportada: 0; ItemENovo: Sim; ItemEReciclado: Não; VidaÚtilEsperada: 50; SubstanciasPerigosas: Não; PotencialDeEsgotamentoAbioticoDosRecursosNaoFosseisMineraisEMetais: 0.000701; PotencialDeAquecimentoGlobalBiogenico: -0.48; CombustiveisFosseisComPotencialDeAquecimentoGlobal: 13.9; PotencialDeAquecimentoGlobalUsoDoSoloEMudancaDeUsoDoSolo: 0.0246; PotencialDeEutrofizacaoFraccaoDeNutrientesQueAtingemOCompartimentoFinalDeAguaDoce: 0.000189; PotencialDeEutrofizacaoFraccaoDeNutrientesQueAtingemOCompartimentoFinalMarinho: 0.0122; EnergiaRecuperada: 0.00739; ConsumoDeAguaDoce: 0.113; UtilizacaoLiquidaDeAguaDoce: 0.113; ResiduosPerigososEliminados: 0.00221; ResiduosNaoPerigososEliminados: 1.83; MassaTotalDeResiduosRadioactivosEliminados: 0.000394; EnergiaElectricaExportada: 1.55; MateriaisParaRecuperacaoDeEnergia: 0.00739; MateriaisParaReciclagem: 0.0253; UnidadeEPD: 1 m²
Type - IFC.REVIGRÉS-Dados gerais-Floor Covering - Nome: REVIGRÉS-OMNISTONE-BASE-60X120-MATT RECT-JET; TipoProduto: Prensado a seco: grupo BIa UGL | Grés porcelânico técnico; NumeroDeRegistoDAP: EPD-REV-20240006-CCC1-EN; ReferenciaDAP: -; UrlDOP: -
Classification: C3020 (Uniformat)
Pset_CoveringCommon - TotalThickness: 9.8 mm
IFC.REVIGRÉS-Dados do fabricante-Floor Covering - Type: Floor: REVIGRÉS-OMNISTONE-BASE-60X120-MATTRECT-JET
IFC.REVIGRÉS-Dados de desempenho-Floor Covering - Type: Floor: REVIGRÉS-OMNISTONE-BASE-60X120-MATTRECT-JET
IFC.REVIGRÉS-Dados de especificação-Floor Covering - Type: Floor: REVIGRÉS-OMNISTONE-BASE-60X120-MATTRECT-JET
IFC.REVIGRÉS-Dados geométricos-Floor Covering - Type: Floor: REVIGRÉS-OMNISTONE-BASE-60X120-MATTRECT-JET
IFC.REVIGRÉS-Dados de sustentabilidade-Floor Covering - Type: Floor: REVIGRÉS-OMNISTONE-BASE-60X120-MATTRECT-JET

# IfcCovering: Floor:REVIGRÉS-OMNISTONE-BASE-60X120-MATTRECT-PLATINA, Floor:REVIGRÉS-OMNISTONE-BASE-60X120-MATTRECT-PLATINA:150599
In: Level 1
Type - PredefinedType: CLADDING; Material: REVIGRÉS-OMNISTONE-BASE-60x120-MATTRECT-PLATINA 9.8 mm
Type - Pset_CoveringCommon - Reference: 312B1392U1; Material: Grés porcelânico
Type - Pset_ElementShading - Roughness: 304.8 mm
Type - Pset_ManufacturerTypeInformation - Manufacturer: REVIGRÉS
Type - Pset_ProductRequirements - Category: Floors
Type - Pset_QuantityTakeOff - Reference: 312B1392U1
Type - IFC.REVIGRÉS-Dados do fabricante-Floor Covering - FabricanteURL: https://www.revigres.pt/; ReferenciaModelo: Omnistone; NumeroGlobalDeItemComercial: 312BD392U1; Acabamento: MATT RECT; Material: Grés porcelânico; IdentificadorDoOperadorEconomico: 501840856; UrlFabricanteArtigo: https://www.revigres.pt/colecoes/omnistone; PaisOrigem: Portugal
Type - IFC.REVIGRÉS-Dados de desempenho-Floor Covering - Rectilinearidade: ± 0.2% máx.± 0.8 mm; Ortogonalidade: ± 0.2% máx.± 1.5 mm; PlanaridadeDaSuperficie: ± 0.3% máx. ± 1.8 mm; QualidadeDaSuperficie: Cumpre; AbsorcaoDeAgua: < 0.05%; ModuloDeRuptura: > 45 N/mm130; ResistenciaAFlexao: ≥ 3500 N; ResistenciaAAbrasaoProfunda: < 120 mm131; DilatacaoTermicaLinear: ≤ 8,0x10-6 °C-1; ResistenciaAoChoqueTermico: Resiste; DurabilidadeResistenciaAoGeloDegelo: Resiste; ResistenciaAoEscorregamentoDIN51130: R10; ResistenciaAoEscorregamentoDIN51097: B; ResistenciaAoEscorregamentoENV51097: B; ResistenciaAoEscorregamentoENV12633: Class 2; ResistenciaAoEscorregamentoBS7976: >36; ResistenciaAoEscorregamentoANSIA1371: ≥0,42; ResistenciaAoDeslizamentoENV12633: Class 2; ResistenciaAoDeslizamentoBS7976: >36; ResistenciaAsManchas: Class 5; ResistenciaABaixasConcentracoesDeAcidosEAlcalis: Classe LA; ResistenciaAAltasConcentracoesDeAcidosEAlcalis: Classe HA; LibertacaoDeCadmio: 0; LibertacaoDeChumbo: 0
Type - IFC.REVIGRÉS-Dados de especificação-Floor Covering - VariacaoTonalidade: 3; NivelDeTrafego: 5; EPavimento: Sim; ERevestimento: Sim; EExterno: Sim
Type - IFC.REVIGRÉS-Dados geométricos-Floor Covering - AlturaNominal: 9.8 mm; ComprimentoNominal: 59.2 mm; LarguraNominal: 118.6 mm
Type - IFC.REVIGRÉS-Dados de sustentabilidade-Floor Covering - ItemEParcialmenteReciclado: 0; EnergiaTermicaExportada: 0; ItemENovo: Sim; ItemEReciclado: Não; VidaÚtilEsperada: 50; SubstanciasPerigosas: Não; PotencialDeEsgotamentoAbioticoDosRecursosNaoFosseisMineraisEMetais: 0.000701; PotencialDeAquecimentoGlobalBiogenico: -0.48; CombustiveisFosseisComPotencialDeAquecimentoGlobal: 13.9; PotencialDeAquecimentoGlobalUsoDoSoloEMudancaDeUsoDoSolo: 0.0246; PotencialDeEutrofizacaoFraccaoDeNutrientesQueAtingemOCompartimentoFinalDeAguaDoce: 0.000189; PotencialDeEutrofizacaoFraccaoDeNutrientesQueAtingemOCompartimentoFinalMarinho: 0.0122; EnergiaRecuperada: 0.00739; ConsumoDeAguaDoce: 0.113; UtilizacaoLiquidaDeAguaDoce: 0.113; ResiduosPerigososEliminados: 0.00221; ResiduosNaoPerigososEliminados: 1.83; MassaTotalDeResiduosRadioactivosEliminados: 0.000394; EnergiaElectricaExportada: 1.55; MateriaisParaRecuperacaoDeEnergia: 0.00739; MateriaisParaReciclagem: 0.0253; UnidadeEPD: 1 m²
Type - IFC.REVIGRÉS-Dados gerais-Floor Covering - Nome: REVIGRÉS-OMNISTONE-BASE-60X120-MATT RECT-PLATINA; TipoProduto: Prensado a seco: grupo BIa UGL | Grés porcelânico técnico; NumeroDeRegistoDAP: EPD-REV-20240006-CCC1-EN; ReferenciaDAP: -; UrlDOP: -
Classification: C3020 (Uniformat)
Pset_CoveringCommon - TotalThickness: 9.8 mm
IFC.REVIGRÉS-Dados do fabricante-Floor Covering - Type: Floor: REVIGRÉS-OMNISTONE-BASE-60X120-MATTRECT-PLATINA
IFC.REVIGRÉS-Dados de desempenho-Floor Covering - Type: Floor: REVIGRÉS-OMNISTONE-BASE-60X120-MATTRECT-PLATINA
IFC.REVIGRÉS-Dados de especificação-Floor Covering - Type: Floor: REVIGRÉS-OMNISTONE-BASE-60X120-MATTRECT-PLATINA
IFC.REVIGRÉS-Dados geométricos-Floor Covering - Type: Floor: REVIGRÉS-OMNISTONE-BASE-60X120-MATTRECT-PLATINA
IFC.REVIGRÉS-Dados de sustentabilidade-Floor Covering - Type: Floor: REVIGRÉS-OMNISTONE-BASE-60X120-MATTRECT-PLATINA

# IfcCovering: Floor:REVIGRÉS-OMNISTONE-BASE-60X120-MATTRECT-ROPE, Floor:REVIGRÉS-OMNISTONE-BASE-60X120-MATTRECT-ROPE:151304
In: Level 1
Type - PredefinedType: CLADDING; Material: REVIGRÉS-OMNISTONE-BASE-60x120-MATTRECT-ROPE 9.8 mm
Type - Pset_CoveringCommon - Reference: 312B1393U1; Material: Grés porcelânico
Type - Pset_ElementShading - Roughness: 304.8 mm
Type - Pset_ManufacturerTypeInformation - Manufacturer: REVIGRÉS
Type - Pset_ProductRequirements - Category: Floors
Type - Pset_QuantityTakeOff - Reference: 312B1393U1
Type - IFC.REVIGRÉS-Dados do fabricante-Floor Covering - FabricanteURL: https://www.revigres.pt/; ReferenciaModelo: Omnistone; NumeroGlobalDeItemComercial: 312BD393U1; Acabamento: MATT RECT; Material: Grés porcelânico; IdentificadorDoOperadorEconomico: 501840856; UrlFabricanteArtigo: https://www.revigres.pt/colecoes/omnistone; PaisOrigem: Portugal
Type - IFC.REVIGRÉS-Dados de desempenho-Floor Covering - Rectilinearidade: ± 0.2% máx.± 0.8 mm; Ortogonalidade: ± 0.2% máx.± 1.5 mm; PlanaridadeDaSuperficie: ± 0.3% máx. ± 1.8 mm; QualidadeDaSuperficie: Cumpre; AbsorcaoDeAgua: < 0.05%; ModuloDeRuptura: > 45 N/mm130; ResistenciaAFlexao: ≥ 3500 N; ResistenciaAAbrasaoProfunda: < 120 mm131; DilatacaoTermicaLinear: ≤ 8,0x10-6 °C-1; ResistenciaAoChoqueTermico: Resiste; DurabilidadeResistenciaAoGeloDegelo: Resiste; ResistenciaAoEscorregamentoDIN51130: R10; ResistenciaAoEscorregamentoDIN51097: B; ResistenciaAoEscorregamentoENV51097: B; ResistenciaAoEscorregamentoENV12633: Class 2; ResistenciaAoEscorregamentoBS7976: >36; ResistenciaAoEscorregamentoANSIA1371: ≥0,42; ResistenciaAoDeslizamentoENV12633: Class 2; ResistenciaAoDeslizamentoBS7976: >36; ResistenciaAsManchas: Class 5; ResistenciaABaixasConcentracoesDeAcidosEAlcalis: Classe LA; ResistenciaAAltasConcentracoesDeAcidosEAlcalis: Classe HA; LibertacaoDeCadmio: 0; LibertacaoDeChumbo: 0
Type - IFC.REVIGRÉS-Dados de especificação-Floor Covering - VariacaoTonalidade: 3; NivelDeTrafego: 5; EPavimento: Sim; ERevestimento: Sim; EExterno: Sim
Type - IFC.REVIGRÉS-Dados geométricos-Floor Covering - AlturaNominal: 9.8 mm; ComprimentoNominal: 59.2 mm; LarguraNominal: 118.6 mm
Type - IFC.REVIGRÉS-Dados de sustentabilidade-Floor Covering - ItemEParcialmenteReciclado: 0; EnergiaTermicaExportada: 0; ItemENovo: Sim; ItemEReciclado: Não; VidaÚtilEsperada: 50; SubstanciasPerigosas: Não; PotencialDeEsgotamentoAbioticoDosRecursosNaoFosseisMineraisEMetais: 0.000701; PotencialDeAquecimentoGlobalBiogenico: -0.48; CombustiveisFosseisComPotencialDeAquecimentoGlobal: 13.9; PotencialDeAquecimentoGlobalUsoDoSoloEMudancaDeUsoDoSolo: 0.0246; PotencialDeEutrofizacaoFraccaoDeNutrientesQueAtingemOCompartimentoFinalDeAguaDoce: 0.000189; PotencialDeEutrofizacaoFraccaoDeNutrientesQueAtingemOCompartimentoFinalMarinho: 0.0122; EnergiaRecuperada: 0.00739; ConsumoDeAguaDoce: 0.113; UtilizacaoLiquidaDeAguaDoce: 0.113; ResiduosPerigososEliminados: 0.00221; ResiduosNaoPerigososEliminados: 1.83; MassaTotalDeResiduosRadioactivosEliminados: 0.000394; EnergiaElectricaExportada: 1.55; MateriaisParaRecuperacaoDeEnergia: 0.00739; MateriaisParaReciclagem: 0.0253; UnidadeEPD: 1 m²
Type - IFC.REVIGRÉS-Dados gerais-Floor Covering - Nome: REVIGRÉS-OMNISTONE-BASE-60X120-MATT RECT-ROPE; TipoProduto: Prensado a seco: grupo BIa UGL | Grés porcelânico técnico; NumeroDeRegistoDAP: EPD-REV-20240006-CCC1-EN; ReferenciaDAP: -; UrlDOP: -
Classification: C3020 (Uniformat)
Pset_CoveringCommon - TotalThickness: 9.8 mm
IFC.REVIGRÉS-Dados do fabricante-Floor Covering - Type: Floor: REVIGRÉS-OMNISTONE-BASE-60X120-MATTRECT-ROPE
IFC.REVIGRÉS-Dados de desempenho-Floor Covering - Type: Floor: REVIGRÉS-OMNISTONE-BASE-60X120-MATTRECT-ROPE
IFC.REVIGRÉS-Dados de especificação-Floor Covering - Type: Floor: REVIGRÉS-OMNISTONE-BASE-60X120-MATTRECT-ROPE
IFC.REVIGRÉS-Dados geométricos-Floor Covering - Type: Floor: REVIGRÉS-OMNISTONE-BASE-60X120-MATTRECT-ROPE
IFC.REVIGRÉS-Dados de sustentabilidade-Floor Covering - Type: Floor: REVIGRÉS-OMNISTONE-BASE-60X120-MATTRECT-ROPE

# IfcCovering: Floor:REVIGRÉS-OMNISTONE-BASE-60X120-SOFT-BONE, Floor:REVIGRÉS-OMNISTONE-BASE-60X120-SOFT-BONE:146522
In: Level 1
Type - PredefinedType: CLADDING; Material: REVIGRÉS-OMNISTONE-BASE-60x120-SOFT-BONE 9.8 mm
Type - Pset_CoveringCommon - Reference: 31261388U1; Material: Grés porcelânico
Type - Pset_ElementShading - Roughness: 304.8 mm
Type - Pset_ManufacturerTypeInformation - Manufacturer: REVIGRÉS
Type - Pset_ProductRequirements - Category: Floors
Type - Pset_QuantityTakeOff - Reference: 31261388U1
Type - IFC.REVIGRÉS-Dados do fabricante-Floor Covering - FabricanteURL: https://www.revigres.pt/; ReferenciaModelo: Omnistone; NumeroGlobalDeItemComercial: 3126D388U1; Acabamento: SOFT; Material: Grés porcelânico; IdentificadorDoOperadorEconomico: 501840856; UrlFabricanteArtigo: https://www.revigres.pt/colecoes/omnistone; PaisOrigem: Portugal
Type - IFC.REVIGRÉS-Dados de desempenho-Floor Covering - Rectilinearidade: ± 0.2% máx.± 0.8 mm; Ortogonalidade: ± 0.2% máx.± 1.5 mm; PlanaridadeDaSuperficie: ± 0.3% máx. ± 1.8 mm; QualidadeDaSuperficie: Cumpre; AbsorcaoDeAgua: < 0.05%; ModuloDeRuptura: > 45 N/mm130; ResistenciaAFlexao: ≥ 3500 N; ResistenciaAAbrasaoProfunda: < 120 mm131; DilatacaoTermicaLinear: ≤ 8,0x10-6 °C-1; ResistenciaAoChoqueTermico: Resiste; DurabilidadeResistenciaAoGeloDegelo: Resiste; ResistenciaAsManchas: Class 5; ResistenciaABaixasConcentracoesDeAcidosEAlcalis: Classe LA; ResistenciaAAltasConcentracoesDeAcidosEAlcalis: Classe HA; LibertacaoDeCadmio: 0; LibertacaoDeChumbo: 0
Type - IFC.REVIGRÉS-Dados de especificação-Floor Covering - VariacaoTonalidade: 3; NivelDeTrafego: 5; EPavimento: Sim; ERevestimento: Sim; EExterno: Sim
Type - IFC.REVIGRÉS-Dados geométricos-Floor Covering - AlturaNominal: 9.8 mm; ComprimentoNominal: 59.2 mm; LarguraNominal: 118.6 mm
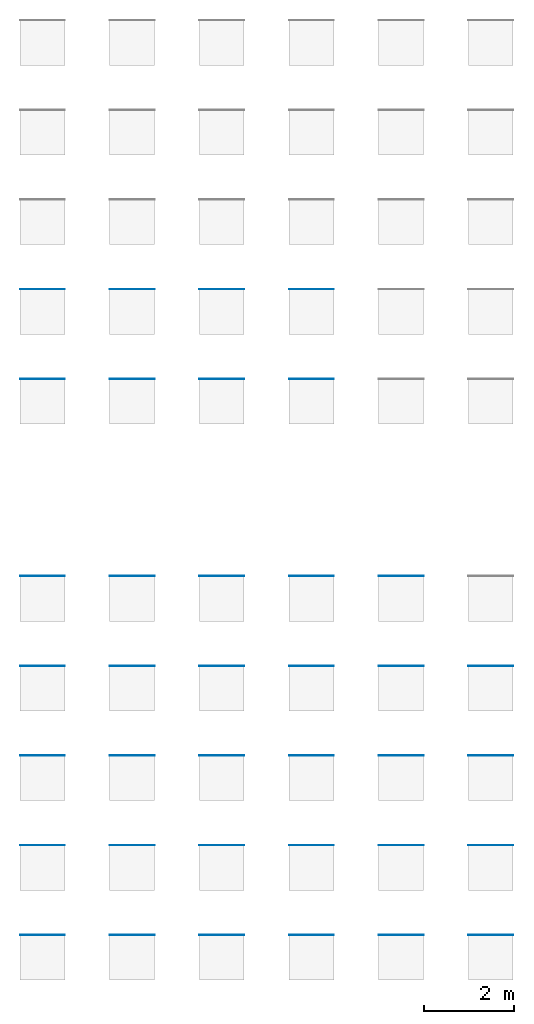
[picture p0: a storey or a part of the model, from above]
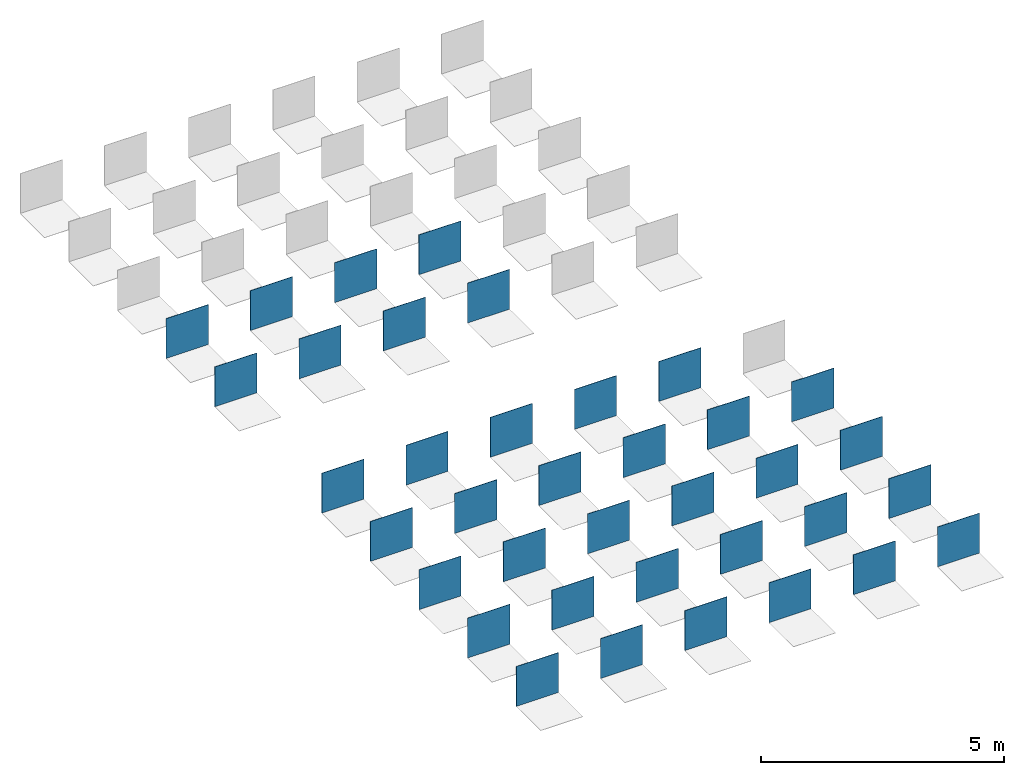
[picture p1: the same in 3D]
Properties of the parts of a building model (IFC2X3), part 3 of 8

# IfcCovering: Floor:REVIGRÉS-OMNISTONE-BASE-60X120-SOFT-BONE, Floor:REVIGRÉS-OMNISTONE-BASE-60X120-SOFT-BONE:146522
Type - IFC.REVIGRÉS-Dados de sustentabilidade-Floor Covering - ItemEParcialmenteReciclado: 0; EnergiaTermicaExportada: 0; ItemENovo: Sim; ItemEReciclado: Não; VidaÚtilEsperada: 50; SubstanciasPerigosas: Não; PotencialDeEsgotamentoAbioticoDosRecursosNaoFosseisMineraisEMetais: 0.000701; PotencialDeAquecimentoGlobalBiogenico: -0.48; CombustiveisFosseisComPotencialDeAquecimentoGlobal: 13.9; PotencialDeAquecimentoGlobalUsoDoSoloEMudancaDeUsoDoSolo: 0.0246; PotencialDeEutrofizacaoFraccaoDeNutrientesQueAtingemOCompartimentoFinalDeAguaDoce: 0.000189; PotencialDeEutrofizacaoFraccaoDeNutrientesQueAtingemOCompartimentoFinalMarinho: 0.0122; EnergiaRecuperada: 0.00739; ConsumoDeAguaDoce: 0.113; UtilizacaoLiquidaDeAguaDoce: 0.113; ResiduosPerigososEliminados: 0.00221; ResiduosNaoPerigososEliminados: 1.83; MassaTotalDeResiduosRadioactivosEliminados: 0.000394; EnergiaElectricaExportada: 1.55; MateriaisParaRecuperacaoDeEnergia: 0.00739; MateriaisParaReciclagem: 0.0253; UnidadeEPD: 1 m²
Type - IFC.REVIGRÉS-Dados gerais-Floor Covering - Nome: REVIGRÉS-OMNISTONE-BASE-60X120-SOFT-BONE; TipoProduto: Prensado a seco: grupo BIa UGL | Grés porcelânico técnico; NumeroDeRegistoDAP: EPD-REV-20240006-CCC1-EN; ReferenciaDAP: -; UrlDOP: -
Classification: C3020 (Uniformat)
Pset_CoveringCommon - TotalThickness: 9.8 mm
IFC.REVIGRÉS-Dados do fabricante-Floor Covering - Type: Floor: REVIGRÉS-OMNISTONE-BASE-60X120-SOFT-BONE
IFC.REVIGRÉS-Dados de desempenho-Floor Covering - Type: Floor: REVIGRÉS-OMNISTONE-BASE-60X120-SOFT-BONE
IFC.REVIGRÉS-Dados de especificação-Floor Covering - Type: Floor: REVIGRÉS-OMNISTONE-BASE-60X120-SOFT-BONE
IFC.REVIGRÉS-Dados geométricos-Floor Covering - Type: Floor: REVIGRÉS-OMNISTONE-BASE-60X120-SOFT-BONE
IFC.REVIGRÉS-Dados de sustentabilidade-Floor Covering - Type: Floor: REVIGRÉS-OMNISTONE-BASE-60X120-SOFT-BONE

# IfcCovering: Floor:REVIGRÉS-OMNISTONE-BASE-60X120-SOFT-ICE, Floor:REVIGRÉS-OMNISTONE-BASE-60X120-SOFT-ICE:148531
In: Level 1
Type - PredefinedType: CLADDING; Material: REVIGRÉS-OMNISTONE-BASE-60x120-SOFT-ICE 9.8 mm
Type - Pset_CoveringCommon - Reference: 31261389U1; Material: Grés porcelânico
Type - Pset_ElementShading - Roughness: 304.8 mm
Type - Pset_ManufacturerTypeInformation - Manufacturer: REVIGRÉS
Type - Pset_ProductRequirements - Category: Floors
Type - Pset_QuantityTakeOff - Reference: 31261389U1
Type - IFC.REVIGRÉS-Dados do fabricante-Floor Covering - FabricanteURL: https://www.revigres.pt/; ReferenciaModelo: Omnistone; NumeroGlobalDeItemComercial: 3126D389U1; Acabamento: SOFT; Material: Grés porcelânico; IdentificadorDoOperadorEconomico: 501840856; UrlFabricanteArtigo: https://www.revigres.pt/colecoes/omnistone; PaisOrigem: Portugal
Type - IFC.REVIGRÉS-Dados de desempenho-Floor Covering - Rectilinearidade: ± 0.2% máx.± 0.8 mm; Ortogonalidade: ± 0.2% máx.± 1.5 mm; PlanaridadeDaSuperficie: ± 0.3% máx. ± 1.8 mm; QualidadeDaSuperficie: Cumpre; AbsorcaoDeAgua: < 0.05%; ModuloDeRuptura: > 45 N/mm130; ResistenciaAFlexao: ≥ 3500 N; ResistenciaAAbrasaoProfunda: < 120 mm131; DilatacaoTermicaLinear: ≤ 8,0x10-6 °C-1; ResistenciaAoChoqueTermico: Resiste; DurabilidadeResistenciaAoGeloDegelo: Resiste; ResistenciaAsManchas: Class 5; ResistenciaABaixasConcentracoesDeAcidosEAlcalis: Classe LA; ResistenciaAAltasConcentracoesDeAcidosEAlcalis: Classe HA; LibertacaoDeCadmio: 0; LibertacaoDeChumbo: 0
Type - IFC.REVIGRÉS-Dados de especificação-Floor Covering - VariacaoTonalidade: 3; NivelDeTrafego: 5; EPavimento: Sim; ERevestimento: Sim; EExterno: Sim
Type - IFC.REVIGRÉS-Dados geométricos-Floor Covering - AlturaNominal: 9.8 mm; ComprimentoNominal: 59.2 mm; LarguraNominal: 118.6 mm
Type - IFC.REVIGRÉS-Dados de sustentabilidade-Floor Covering - ItemEParcialmenteReciclado: 0; EnergiaTermicaExportada: 0; ItemENovo: Sim; ItemEReciclado: Não; VidaÚtilEsperada: 50; SubstanciasPerigosas: Não; PotencialDeEsgotamentoAbioticoDosRecursosNaoFosseisMineraisEMetais: 0.000701; PotencialDeAquecimentoGlobalBiogenico: -0.48; CombustiveisFosseisComPotencialDeAquecimentoGlobal: 13.9; PotencialDeAquecimentoGlobalUsoDoSoloEMudancaDeUsoDoSolo: 0.0246; PotencialDeEutrofizacaoFraccaoDeNutrientesQueAtingemOCompartimentoFinalDeAguaDoce: 0.000189; PotencialDeEutrofizacaoFraccaoDeNutrientesQueAtingemOCompartimentoFinalMarinho: 0.0122; EnergiaRecuperada: 0.00739; ConsumoDeAguaDoce: 0.113; UtilizacaoLiquidaDeAguaDoce: 0.113; ResiduosPerigososEliminados: 0.00221; ResiduosNaoPerigososEliminados: 1.83; MassaTotalDeResiduosRadioactivosEliminados: 0.000394; EnergiaElectricaExportada: 1.55; MateriaisParaRecuperacaoDeEnergia: 0.00739; MateriaisParaReciclagem: 0.0253; UnidadeEPD: 1 m²
Type - IFC.REVIGRÉS-Dados gerais-Floor Covering - Nome: REVIGRÉS-OMNISTONE-BASE-60X120-SOFT-ICE; TipoProduto: Prensado a seco: grupo BIa UGL | Grés porcelânico técnico; NumeroDeRegistoDAP: EPD-REV-20240006-CCC1-EN; ReferenciaDAP: -; UrlDOP: -
Classification: C3020 (Uniformat)
Pset_CoveringCommon - TotalThickness: 9.8 mm
IFC.REVIGRÉS-Dados do fabricante-Floor Covering - Type: Floor: REVIGRÉS-OMNISTONE-BASE-60X120-SOFT-ICE
IFC.REVIGRÉS-Dados de desempenho-Floor Covering - Type: Floor: REVIGRÉS-OMNISTONE-BASE-60X120-SOFT-ICE
IFC.REVIGRÉS-Dados de especificação-Floor Covering - Type: Floor: REVIGRÉS-OMNISTONE-BASE-60X120-SOFT-ICE
IFC.REVIGRÉS-Dados geométricos-Floor Covering - Type: Floor: REVIGRÉS-OMNISTONE-BASE-60X120-SOFT-ICE
IFC.REVIGRÉS-Dados de sustentabilidade-Floor Covering - Type: Floor: REVIGRÉS-OMNISTONE-BASE-60X120-SOFT-ICE

# IfcCovering: Floor:REVIGRÉS-OMNISTONE-BASE-60X120-SOFT-IRON, Floor:REVIGRÉS-OMNISTONE-BASE-60X120-SOFT-IRON:149216
In: Level 1
Type - PredefinedType: CLADDING; Material: REVIGRÉS-OMNISTONE-BASE-60x120-SOFT-IRON 9.8 mm
Type - Pset_CoveringCommon - Reference: 31261390U1; Material: Grés porcelânico
Type - Pset_ElementShading - Roughness: 304.8 mm
Type - Pset_ManufacturerTypeInformation - Manufacturer: REVIGRÉS
Type - Pset_ProductRequirements - Category: Floors
Type - Pset_QuantityTakeOff - Reference: 31261390U1
Type - IFC.REVIGRÉS-Dados do fabricante-Floor Covering - FabricanteURL: https://www.revigres.pt/; ReferenciaModelo: Omnistone; NumeroGlobalDeItemComercial: 3126D390U1; Acabamento: SOFT; Material: Grés porcelânico; IdentificadorDoOperadorEconomico: 501840856; UrlFabricanteArtigo: https://www.revigres.pt/colecoes/omnistone; PaisOrigem: Portugal
Type - IFC.REVIGRÉS-Dados de desempenho-Floor Covering - Rectilinearidade: ± 0.2% máx.± 0.8 mm; Ortogonalidade: ± 0.2% máx.± 1.5 mm; PlanaridadeDaSuperficie: ± 0.3% máx. ± 1.8 mm; QualidadeDaSuperficie: Cumpre; AbsorcaoDeAgua: < 0.05%; ModuloDeRuptura: > 45 N/mm130; ResistenciaAFlexao: ≥ 3500 N; ResistenciaAAbrasaoProfunda: < 120 mm131; DilatacaoTermicaLinear: ≤ 8,0x10-6 °C-1; ResistenciaAoChoqueTermico: Resiste; DurabilidadeResistenciaAoGeloDegelo: Resiste; ResistenciaAsManchas: Class 5; ResistenciaABaixasConcentracoesDeAcidosEAlcalis: Classe LA; ResistenciaAAltasConcentracoesDeAcidosEAlcalis: Classe HA; LibertacaoDeCadmio: 0; LibertacaoDeChumbo: 0
Type - IFC.REVIGRÉS-Dados de especificação-Floor Covering - VariacaoTonalidade: 3; NivelDeTrafego: 5; EPavimento: Sim; ERevestimento: Sim; EExterno: Sim
Type - IFC.REVIGRÉS-Dados geométricos-Floor Covering - AlturaNominal: 9.8 mm; ComprimentoNominal: 59.2 mm; LarguraNominal: 118.6 mm
Type - IFC.REVIGRÉS-Dados de sustentabilidade-Floor Covering - EnergiaTermicaExportada: 0; ItemENovo: Sim; ItemEParcialmenteReciclado: 0.14; ItemEReciclado: Sim; VidaÚtilEsperada: 50; SubstanciasPerigosas: Não; PotencialDeEsgotamentoAbioticoDosRecursosNaoFosseisMineraisEMetais: 0.000701; PotencialDeAquecimentoGlobalBiogenico: -0.48; CombustiveisFosseisComPotencialDeAquecimentoGlobal: 13.9; PotencialDeAquecimentoGlobalUsoDoSoloEMudancaDeUsoDoSolo: 0.0246; PotencialDeEutrofizacaoFraccaoDeNutrientesQueAtingemOCompartimentoFinalDeAguaDoce: 0.000189; PotencialDeEutrofizacaoFraccaoDeNutrientesQueAtingemOCompartimentoFinalMarinho: 0.0122; EnergiaRecuperada: 0.00739; ConsumoDeAguaDoce: 0.113; UtilizacaoLiquidaDeAguaDoce: 0.113; ResiduosPerigososEliminados: 0.00221; ResiduosNaoPerigososEliminados: 1.83; MassaTotalDeResiduosRadioactivosEliminados: 0.000394; EnergiaElectricaExportada: 1.55; MateriaisParaRecuperacaoDeEnergia: 0.00739; MateriaisParaReciclagem: 0.0253; UnidadeEPD: 1 m²
Type - IFC.REVIGRÉS-Dados gerais-Floor Covering - Nome: REVIGRÉS-OMNISTONE-BASE-60X120-SOFT-IRON; TipoProduto: Prensado a seco: grupo BIa UGL | Grés porcelânico técnico; NumeroDeRegistoDAP: EPD-REV-20240006-CCC1-EN; ReferenciaDAP: -; UrlDOP: -
Classification: C3020 (Uniformat)
Pset_CoveringCommon - TotalThickness: 9.8 mm
IFC.REVIGRÉS-Dados do fabricante-Floor Covering - Type: Floor: REVIGRÉS-OMNISTONE-BASE-60X120-SOFT-IRON
IFC.REVIGRÉS-Dados de desempenho-Floor Covering - Type: Floor: REVIGRÉS-OMNISTONE-BASE-60X120-SOFT-IRON
IFC.REVIGRÉS-Dados de especificação-Floor Covering - Type: Floor: REVIGRÉS-OMNISTONE-BASE-60X120-SOFT-IRON
IFC.REVIGRÉS-Dados geométricos-Floor Covering - Type: Floor: REVIGRÉS-OMNISTONE-BASE-60X120-SOFT-IRON
IFC.REVIGRÉS-Dados de sustentabilidade-Floor Covering - Type: Floor: REVIGRÉS-OMNISTONE-BASE-60X120-SOFT-IRON

# IfcCovering: Floor:REVIGRÉS-OMNISTONE-BASE-60X120-SOFT-JET, Floor:REVIGRÉS-OMNISTONE-BASE-60X120-SOFT-JET:149958
In: Level 1
Type - PredefinedType: CLADDING; Material: REVIGRÉS-OMNISTONE-BASE-60x120-SOFT-JET 9.8 mm
Type - Pset_CoveringCommon - Reference: 31261391U1; Material: Grés porcelânico
Type - Pset_ElementShading - Roughness: 304.8 mm
Type - Pset_ManufacturerTypeInformation - Manufacturer: REVIGRÉS
Type - Pset_ProductRequirements - Category: Floors
Type - Pset_QuantityTakeOff - Reference: 31261391U1
Type - IFC.REVIGRÉS-Dados do fabricante-Floor Covering - FabricanteURL: https://www.revigres.pt/; ReferenciaModelo: Omnistone; NumeroGlobalDeItemComercial: 3126D391U1; Acabamento: SOFT; Material: Grés porcelânico; IdentificadorDoOperadorEconomico: 501840856; UrlFabricanteArtigo: https://www.revigres.pt/colecoes/omnistone; PaisOrigem: Portugal
Type - IFC.REVIGRÉS-Dados de desempenho-Floor Covering - Rectilinearidade: ± 0.2% máx.± 0.8 mm; Ortogonalidade: ± 0.2% máx.± 1.5 mm; PlanaridadeDaSuperficie: ± 0.3% máx. ± 1.8 mm; QualidadeDaSuperficie: Cumpre; AbsorcaoDeAgua: < 0.05%; ModuloDeRuptura: > 45 N/mm130; ResistenciaAFlexao: ≥ 3500 N; ResistenciaAAbrasaoProfunda: < 120 mm131; DilatacaoTermicaLinear: ≤ 8,0x10-6 °C-1; ResistenciaAoChoqueTermico: Resiste; DurabilidadeResistenciaAoGeloDegelo: Resiste; ResistenciaAsManchas: Class 5; ResistenciaABaixasConcentracoesDeAcidosEAlcalis: Classe LA; ResistenciaAAltasConcentracoesDeAcidosEAlcalis: Classe HA; LibertacaoDeCadmio: 0; LibertacaoDeChumbo: 0
Type - IFC.REVIGRÉS-Dados de especificação-Floor Covering - VariacaoTonalidade: 3; NivelDeTrafego: 5; EPavimento: Sim; ERevestimento: Sim; EExterno: Sim
Type - IFC.REVIGRÉS-Dados geométricos-Floor Covering - AlturaNominal: 9.8 mm; ComprimentoNominal: 59.2 mm; LarguraNominal: 118.6 mm
Type - IFC.REVIGRÉS-Dados de sustentabilidade-Floor Covering - ItemEParcialmenteReciclado: 0; EnergiaTermicaExportada: 0; ItemENovo: Sim; ItemEReciclado: Não; VidaÚtilEsperada: 50; SubstanciasPerigosas: Não; PotencialDeEsgotamentoAbioticoDosRecursosNaoFosseisMineraisEMetais: 0.000701; PotencialDeAquecimentoGlobalBiogenico: -0.48; CombustiveisFosseisComPotencialDeAquecimentoGlobal: 13.9; PotencialDeAquecimentoGlobalUsoDoSoloEMudancaDeUsoDoSolo: 0.0246; PotencialDeEutrofizacaoFraccaoDeNutrientesQueAtingemOCompartimentoFinalDeAguaDoce: 0.000189; PotencialDeEutrofizacaoFraccaoDeNutrientesQueAtingemOCompartimentoFinalMarinho: 0.0122; EnergiaRecuperada: 0.00739; ConsumoDeAguaDoce: 0.113; UtilizacaoLiquidaDeAguaDoce: 0.113; ResiduosPerigososEliminados: 0.00221; ResiduosNaoPerigososEliminados: 1.83; MassaTotalDeResiduosRadioactivosEliminados: 0.000394; EnergiaElectricaExportada: 1.55; MateriaisParaRecuperacaoDeEnergia: 0.00739; MateriaisParaReciclagem: 0.0253; UnidadeEPD: 1 m²
Type - IFC.REVIGRÉS-Dados gerais-Floor Covering - Nome: REVIGRÉS-OMNISTONE-BASE-60X120-SOFT-JET; TipoProduto: Prensado a seco: grupo BIa UGL | Grés porcelânico técnico; NumeroDeRegistoDAP: EPD-REV-20240006-CCC1-EN; ReferenciaDAP: -; UrlDOP: -
Classification: C3020 (Uniformat)
Pset_CoveringCommon - TotalThickness: 9.8 mm
IFC.REVIGRÉS-Dados do fabricante-Floor Covering - Type: Floor: REVIGRÉS-OMNISTONE-BASE-60X120-SOFT-JET
IFC.REVIGRÉS-Dados de desempenho-Floor Covering - Type: Floor: REVIGRÉS-OMNISTONE-BASE-60X120-SOFT-JET
IFC.REVIGRÉS-Dados de especificação-Floor Covering - Type: Floor: REVIGRÉS-OMNISTONE-BASE-60X120-SOFT-JET
IFC.REVIGRÉS-Dados geométricos-Floor Covering - Type: Floor: REVIGRÉS-OMNISTONE-BASE-60X120-SOFT-JET
IFC.REVIGRÉS-Dados de sustentabilidade-Floor Covering - Type: Floor: REVIGRÉS-OMNISTONE-BASE-60X120-SOFT-JET

# IfcCovering: Floor:REVIGRÉS-OMNISTONE-BASE-60X120-SOFT-PLATINA, Floor:REVIGRÉS-OMNISTONE-BASE-60X120-SOFT-PLATINA:150679
In: Level 1
Type - PredefinedType: CLADDING; Material: REVIGRÉS-OMNISTONE-BASE-60x120-SOFT-PLATINA 9.8 mm
Type - Pset_CoveringCommon - Reference: 31261392U1; Material: Grés porcelânico
Type - Pset_ElementShading - Roughness: 304.8 mm
Type - Pset_ManufacturerTypeInformation - Manufacturer: REVIGRÉS
Type - Pset_ProductRequirements - Category: Floors
Type - Pset_QuantityTakeOff - Reference: 31261392U1
Type - IFC.REVIGRÉS-Dados do fabricante-Floor Covering - FabricanteURL: https://www.revigres.pt/; ReferenciaModelo: Omnistone; NumeroGlobalDeItemComercial: 3126D392U1; Acabamento: SOFT; Material: Grés porcelânico; IdentificadorDoOperadorEconomico: 501840856; UrlFabricanteArtigo: https://www.revigres.pt/colecoes/omnistone; PaisOrigem: Portugal
Type - IFC.REVIGRÉS-Dados de desempenho-Floor Covering - Rectilinearidade: ± 0.2% máx.± 0.8 mm; Ortogonalidade: ± 0.2% máx.± 1.5 mm; PlanaridadeDaSuperficie: ± 0.3% máx. ± 1.8 mm; QualidadeDaSuperficie: Cumpre; AbsorcaoDeAgua: < 0.05%; ModuloDeRuptura: > 45 N/mm130; ResistenciaAFlexao: ≥ 3500 N; ResistenciaAAbrasaoProfunda: < 120 mm131; DilatacaoTermicaLinear: ≤ 8,0x10-6 °C-1; ResistenciaAoChoqueTermico: Resiste; DurabilidadeResistenciaAoGeloDegelo: Resiste; ResistenciaAsManchas: Class 5; ResistenciaABaixasConcentracoesDeAcidosEAlcalis: Classe LA; ResistenciaAAltasConcentracoesDeAcidosEAlcalis: Classe HA; LibertacaoDeCadmio: 0; LibertacaoDeChumbo: 0
Type - IFC.REVIGRÉS-Dados de especificação-Floor Covering - VariacaoTonalidade: 3; NivelDeTrafego: 5; EPavimento: Sim; ERevestimento: Sim; EExterno: Sim
Type - IFC.REVIGRÉS-Dados geométricos-Floor Covering - AlturaNominal: 9.8 mm; ComprimentoNominal: 59.2 mm; LarguraNominal: 118.6 mm
Type - IFC.REVIGRÉS-Dados de sustentabilidade-Floor Covering - ItemEParcialmenteReciclado: 0; EnergiaTermicaExportada: 0; ItemENovo: Sim; ItemEReciclado: Não; VidaÚtilEsperada: 50; SubstanciasPerigosas: Não; PotencialDeEsgotamentoAbioticoDosRecursosNaoFosseisMineraisEMetais: 0.000701; PotencialDeAquecimentoGlobalBiogenico: -0.48; CombustiveisFosseisComPotencialDeAquecimentoGlobal: 13.9; PotencialDeAquecimentoGlobalUsoDoSoloEMudancaDeUsoDoSolo: 0.0246; PotencialDeEutrofizacaoFraccaoDeNutrientesQueAtingemOCompartimentoFinalDeAguaDoce: 0.000189; PotencialDeEutrofizacaoFraccaoDeNutrientesQueAtingemOCompartimentoFinalMarinho: 0.0122; EnergiaRecuperada: 0.00739; ConsumoDeAguaDoce: 0.113; UtilizacaoLiquidaDeAguaDoce: 0.113; ResiduosPerigososEliminados: 0.00221; ResiduosNaoPerigososEliminados: 1.83; MassaTotalDeResiduosRadioactivosEliminados: 0.000394; EnergiaElectricaExportada: 1.55; MateriaisParaRecuperacaoDeEnergia: 0.00739; MateriaisParaReciclagem: 0.0253; UnidadeEPD: 1 m²
Type - IFC.REVIGRÉS-Dados gerais-Floor Covering - Nome: REVIGRÉS-OMNISTONE-BASE-60X120-SOFT-PLATINA; TipoProduto: Prensado a seco: grupo BIa UGL | Grés porcelânico técnico; NumeroDeRegistoDAP: EPD-REV-20240006-CCC1-EN; ReferenciaDAP: -; UrlDOP: -
Classification: C3020 (Uniformat)
Pset_CoveringCommon - TotalThickness: 9.8 mm
IFC.REVIGRÉS-Dados do fabricante-Floor Covering - Type: Floor: REVIGRÉS-OMNISTONE-BASE-60X120-SOFT-PLATINA
IFC.REVIGRÉS-Dados de desempenho-Floor Covering - Type: Floor: REVIGRÉS-OMNISTONE-BASE-60X120-SOFT-PLATINA
IFC.REVIGRÉS-Dados de especificação-Floor Covering - Type: Floor: REVIGRÉS-OMNISTONE-BASE-60X120-SOFT-PLATINA
IFC.REVIGRÉS-Dados geométricos-Floor Covering - Type: Floor: REVIGRÉS-OMNISTONE-BASE-60X120-SOFT-PLATINA
IFC.REVIGRÉS-Dados de sustentabilidade-Floor Covering - Type: Floor: REVIGRÉS-OMNISTONE-BASE-60X120-SOFT-PLATINA

# IfcCovering: Floor:REVIGRÉS-OMNISTONE-BASE-60X120-SOFT-ROPE, Floor:REVIGRÉS-OMNISTONE-BASE-60X120-SOFT-ROPE:151384
In: Level 1
Type - PredefinedType: CLADDING; Material: REVIGRÉS-OMNISTONE-BASE-60x120-SOFT-ROPE 9.8 mm
Type - Pset_CoveringCommon - Reference: 31261393U1; Material: Grés porcelânico
Type - Pset_ElementShading - Roughness: 304.8 mm
Type - Pset_ManufacturerTypeInformation - Manufacturer: REVIGRÉS
Type - Pset_ProductRequirements - Category: Floors
Type - Pset_QuantityTakeOff - Reference: 31261393U1
Type - IFC.REVIGRÉS-Dados do fabricante-Floor Covering - FabricanteURL: https://www.revigres.pt/; ReferenciaModelo: Omnistone; NumeroGlobalDeItemComercial: 3126D393U1; Acabamento: SOFT; Material: Grés porcelânico; IdentificadorDoOperadorEconomico: 501840856; UrlFabricanteArtigo: https://www.revigres.pt/colecoes/omnistone; PaisOrigem: Portugal
Type - IFC.REVIGRÉS-Dados de desempenho-Floor Covering - Rectilinearidade: ± 0.2% máx.± 0.8 mm; Ortogonalidade: ± 0.2% máx.± 1.5 mm; PlanaridadeDaSuperficie: ± 0.3% máx. ± 1.8 mm; QualidadeDaSuperficie: Cumpre; AbsorcaoDeAgua: < 0.05%; ModuloDeRuptura: > 45 N/mm130; ResistenciaAFlexao: ≥ 3500 N; ResistenciaAAbrasaoProfunda: < 120 mm131; DilatacaoTermicaLinear: ≤ 8,0x10-6 °C-1; ResistenciaAoChoqueTermico: Resiste; DurabilidadeResistenciaAoGeloDegelo: Resiste; ResistenciaAsManchas: Class 5; ResistenciaABaixasConcentracoesDeAcidosEAlcalis: Classe LA; ResistenciaAAltasConcentracoesDeAcidosEAlcalis: Classe HA; LibertacaoDeCadmio: 0; LibertacaoDeChumbo: 0
Type - IFC.REVIGRÉS-Dados de especificação-Floor Covering - VariacaoTonalidade: 3; NivelDeTrafego: 5; EPavimento: Sim; ERevestimento: Sim; EExterno: Sim
Type - IFC.REVIGRÉS-Dados geométricos-Floor Covering - AlturaNominal: 9.8 mm; ComprimentoNominal: 59.2 mm; LarguraNominal: 118.6 mm
Type - IFC.REVIGRÉS-Dados de sustentabilidade-Floor Covering - ItemEParcialmenteReciclado: 0; EnergiaTermicaExportada: 0; ItemENovo: Sim; ItemEReciclado: Não; VidaÚtilEsperada: 50; SubstanciasPerigosas: Não; PotencialDeEsgotamentoAbioticoDosRecursosNaoFosseisMineraisEMetais: 0.000701; PotencialDeAquecimentoGlobalBiogenico: -0.48; CombustiveisFosseisComPotencialDeAquecimentoGlobal: 13.9; PotencialDeAquecimentoGlobalUsoDoSoloEMudancaDeUsoDoSolo: 0.0246; PotencialDeEutrofizacaoFraccaoDeNutrientesQueAtingemOCompartimentoFinalDeAguaDoce: 0.000189; PotencialDeEutrofizacaoFraccaoDeNutrientesQueAtingemOCompartimentoFinalMarinho: 0.0122; EnergiaRecuperada: 0.00739; ConsumoDeAguaDoce: 0.113; UtilizacaoLiquidaDeAguaDoce: 0.113; ResiduosPerigososEliminados: 0.00221; ResiduosNaoPerigososEliminados: 1.83; MassaTotalDeResiduosRadioactivosEliminados: 0.000394; EnergiaElectricaExportada: 1.55; MateriaisParaRecuperacaoDeEnergia: 0.00739; MateriaisParaReciclagem: 0.0253; UnidadeEPD: 1 m²
Type - IFC.REVIGRÉS-Dados gerais-Floor Covering - Nome: REVIGRÉS-OMNISTONE-BASE-60X120-SOFT-ROPE; TipoProduto: Prensado a seco: grupo BIa UGL | Grés porcelânico técnico; NumeroDeRegistoDAP: EPD-REV-20240006-CCC1-EN; ReferenciaDAP: -; UrlDOP: -
Classification: C3020 (Uniformat)
Pset_CoveringCommon - TotalThickness: 9.8 mm
IFC.REVIGRÉS-Dados do fabricante-Floor Covering - Type: Floor: REVIGRÉS-OMNISTONE-BASE-60X120-SOFT-ROPE
IFC.REVIGRÉS-Dados de desempenho-Floor Covering - Type: Floor: REVIGRÉS-OMNISTONE-BASE-60X120-SOFT-ROPE
IFC.REVIGRÉS-Dados de especificação-Floor Covering - Type: Floor: REVIGRÉS-OMNISTONE-BASE-60X120-SOFT-ROPE
IFC.REVIGRÉS-Dados geométricos-Floor Covering - Type: Floor: REVIGRÉS-OMNISTONE-BASE-60X120-SOFT-ROPE
IFC.REVIGRÉS-Dados de sustentabilidade-Floor Covering - Type: Floor: REVIGRÉS-OMNISTONE-BASE-60X120-SOFT-ROPE

# IfcCovering: Floor:REVIGRÉS-OMNISTONE-BASE-60X60-MATTRECT-BONE, Floor:REVIGRÉS-OMNISTONE-BASE-60X60-MATTRECT-BONE:146348
In: Level 1
Type - PredefinedType: CLADDING; Material: REVIGRÉS-OMNISTONE-BASE-60x60-MATTRECT-BONE 9.8 mm
Type - Pset_CoveringCommon - Reference: 312BD388U1; Material: Grés porcelânico
Type - Pset_ElementShading - Roughness: 304.8 mm
Type - Pset_ManufacturerTypeInformation - Manufacturer: REVIGRÉS
Type - Pset_ProductRequirements - Category: Floors
Type - Pset_QuantityTakeOff - Reference: 312BD388U1
Type - IFC.REVIGRÉS-Dados do fabricante-Floor Covering - FabricanteURL: https://www.revigres.pt/; ReferenciaModelo: Omnistone; NumeroGlobalDeItemComercial: 312B1388U1; Acabamento: MATT RECT; Material: Grés porcelânico; IdentificadorDoOperadorEconomico: 501840856; UrlFabricanteArtigo: https://www.revigres.pt/colecoes/omnistone; PaisOrigem: Portugal
Type - IFC.REVIGRÉS-Dados de desempenho-Floor Covering - Rectilinearidade: ± 0.2% máx.± 0.8 mm; Ortogonalidade: ± 0.2% máx.± 1.5 mm; PlanaridadeDaSuperficie: ± 0.3% máx. ± 1.8 mm; QualidadeDaSuperficie: Cumpre; AbsorcaoDeAgua: < 0.05%; ModuloDeRuptura: > 45 N/mm130; ResistenciaAFlexao: ≥ 3500 N; ResistenciaAAbrasaoProfunda: < 120 mm131; DilatacaoTermicaLinear: ≤ 8,0x10-6 °C-1; ResistenciaAoChoqueTermico: Resiste; DurabilidadeResistenciaAoGeloDegelo: Resiste; ResistenciaAoEscorregamentoDIN51130: R10; ResistenciaAoEscorregamentoDIN51097: B; ResistenciaAoEscorregamentoENV51097: B; ResistenciaAoEscorregamentoENV12633: Class 2; ResistenciaAoEscorregamentoBS7976: >36; ResistenciaAoEscorregamentoANSIA1371: ≥0,42; ResistenciaAoDeslizamentoENV12633: Class 2; ResistenciaAoDeslizamentoBS7976: >36; ResistenciaAsManchas: Class 5; ResistenciaABaixasConcentracoesDeAcidosEAlcalis: Classe LA; ResistenciaAAltasConcentracoesDeAcidosEAlcalis: Classe HA; LibertacaoDeCadmio: 0; LibertacaoDeChumbo: 0
Type - IFC.REVIGRÉS-Dados de especificação-Floor Covering - VariacaoTonalidade: 3; NivelDeTrafego: 5; EPavimento: Sim; ERevestimento: Sim; EExterno: Sim
Type - IFC.REVIGRÉS-Dados geométricos-Floor Covering - AlturaNominal: 9.8 mm; ComprimentoNominal: 59.2 mm; LarguraNominal: 59.2 mm
Type - IFC.REVIGRÉS-Dados de sustentabilidade-Floor Covering - ItemEParcialmenteReciclado: 0; EnergiaTermicaExportada: 0; ItemENovo: Sim; ItemEReciclado: Não; VidaÚtilEsperada: 50; SubstanciasPerigosas: Não; PotencialDeEsgotamentoAbioticoDosRecursosNaoFosseisMineraisEMetais: 0.000701; PotencialDeAquecimentoGlobalBiogenico: -0.48; CombustiveisFosseisComPotencialDeAquecimentoGlobal: 13.9; PotencialDeAquecimentoGlobalUsoDoSoloEMudancaDeUsoDoSolo: 0.0246; PotencialDeEutrofizacaoFraccaoDeNutrientesQueAtingemOCompartimentoFinalDeAguaDoce: 0.000189; PotencialDeEutrofizacaoFraccaoDeNutrientesQueAtingemOCompartimentoFinalMarinho: 0.0122; EnergiaRecuperada: 0.00739; ConsumoDeAguaDoce: 0.113; UtilizacaoLiquidaDeAguaDoce: 0.113; ResiduosPerigososEliminados: 0.00221; ResiduosNaoPerigososEliminados: 1.83; MassaTotalDeResiduosRadioactivosEliminados: 0.000394; EnergiaElectricaExportada: 1.55; MateriaisParaRecuperacaoDeEnergia: 0.00739; MateriaisParaReciclagem: 0.0253; UnidadeEPD: 1 m²
Type - IFC.REVIGRÉS-Dados gerais-Floor Covering - Nome: REVIGRÉS-OMNISTONE-BASE-60X60-MATT RECT-BONE; TipoProduto: Prensado a seco: grupo BIa UGL | Grés porcelânico técnico; NumeroDeRegistoDAP: EPD-REV-20240006-CCC1-EN; ReferenciaDAP: -; UrlDOP: -
Classification: C3020 (Uniformat)
Pset_CoveringCommon - TotalThickness: 9.8 mm
IFC.REVIGRÉS-Dados do fabricante-Floor Covering - Type: Floor: REVIGRÉS-OMNISTONE-BASE-60X60-MATTRECT-BONE
IFC.REVIGRÉS-Dados de desempenho-Floor Covering - Type: Floor: REVIGRÉS-OMNISTONE-BASE-60X60-MATTRECT-BONE
IFC.REVIGRÉS-Dados de especificação-Floor Covering - Type: Floor: REVIGRÉS-OMNISTONE-BASE-60X60-MATTRECT-BONE
IFC.REVIGRÉS-Dados geométricos-Floor Covering - Type: Floor: REVIGRÉS-OMNISTONE-BASE-60X60-MATTRECT-BONE
IFC.REVIGRÉS-Dados de sustentabilidade-Floor Covering - Type: Floor: REVIGRÉS-OMNISTONE-BASE-60X60-MATTRECT-BONE

# IfcCovering: Floor:REVIGRÉS-OMNISTONE-BASE-60X60-MATTRECT-ICE, Floor:REVIGRÉS-OMNISTONE-BASE-60X60-MATTRECT-ICE:148434
In: Level 1
Type - PredefinedType: CLADDING; Material: REVIGRÉS-OMNISTONE-BASE-60x60-MATTRECT-ICE 9.8 mm
Type - Pset_CoveringCommon - Reference: 312BD389U1; Material: Grés porcelânico
Type - Pset_ElementShading - Roughness: 304.8 mm
Type - Pset_ManufacturerTypeInformation - Manufacturer: REVIGRÉS
Type - Pset_ProductRequirements - Category: Floors
Type - Pset_QuantityTakeOff - Reference: 312BD389U1
Type - IFC.REVIGRÉS-Dados do fabricante-Floor Covering - FabricanteURL: https://www.revigres.pt/; ReferenciaModelo: Omnistone; NumeroGlobalDeItemComercial: 312B1389U1; Acabamento: MATT RECT; Material: Grés porcelânico; IdentificadorDoOperadorEconomico: 501840856; UrlFabricanteArtigo: https://www.revigres.pt/colecoes/omnistone; PaisOrigem: Portugal
Type - IFC.REVIGRÉS-Dados de desempenho-Floor Covering - Rectilinearidade: ± 0.2% máx.± 0.8 mm; Ortogonalidade: ± 0.2% máx.± 1.5 mm; PlanaridadeDaSuperficie: ± 0.3% máx. ± 1.8 mm; QualidadeDaSuperficie: Cumpre; AbsorcaoDeAgua: < 0.05%; ModuloDeRuptura: > 45 N/mm130; ResistenciaAFlexao: ≥ 3500 N; ResistenciaAAbrasaoProfunda: < 120 mm131; DilatacaoTermicaLinear: ≤ 8,0x10-6 °C-1; ResistenciaAoChoqueTermico: Resiste; DurabilidadeResistenciaAoGeloDegelo: Resiste; ResistenciaAoEscorregamentoDIN51130: R10; ResistenciaAoEscorregamentoDIN51097: B; ResistenciaAoEscorregamentoENV51097: B; ResistenciaAoEscorregamentoENV12633: Class 2; ResistenciaAoEscorregamentoBS7976: >36; ResistenciaAoEscorregamentoANSIA1371: ≥0,42; ResistenciaAoDeslizamentoENV12633: Class 2; ResistenciaAoDeslizamentoBS7976: >36; ResistenciaAsManchas: Class 5; ResistenciaABaixasConcentracoesDeAcidosEAlcalis: Classe LA; ResistenciaAAltasConcentracoesDeAcidosEAlcalis: Classe HA; LibertacaoDeCadmio: 0; LibertacaoDeChumbo: 0
Type - IFC.REVIGRÉS-Dados de especificação-Floor Covering - VariacaoTonalidade: 3; NivelDeTrafego: 5; EPavimento: Sim; ERevestimento: Sim; EExterno: Sim
Type - IFC.REVIGRÉS-Dados geométricos-Floor Covering - AlturaNominal: 9.8 mm; ComprimentoNominal: 59.2 mm; LarguraNominal: 59.2 mm
Type - IFC.REVIGRÉS-Dados de sustentabilidade-Floor Covering - ItemEParcialmenteReciclado: 0; EnergiaTermicaExportada: 0; ItemENovo: Sim; ItemEReciclado: Não; VidaÚtilEsperada: 50; SubstanciasPerigosas: Não; PotencialDeEsgotamentoAbioticoDosRecursosNaoFosseisMineraisEMetais: 0.000701; PotencialDeAquecimentoGlobalBiogenico: -0.48; CombustiveisFosseisComPotencialDeAquecimentoGlobal: 13.9; PotencialDeAquecimentoGlobalUsoDoSoloEMudancaDeUsoDoSolo: 0.0246; PotencialDeEutrofizacaoFraccaoDeNutrientesQueAtingemOCompartimentoFinalDeAguaDoce: 0.000189; PotencialDeEutrofizacaoFraccaoDeNutrientesQueAtingemOCompartimentoFinalMarinho: 0.0122; EnergiaRecuperada: 0.00739; ConsumoDeAguaDoce: 0.113; UtilizacaoLiquidaDeAguaDoce: 0.113; ResiduosPerigososEliminados: 0.00221; ResiduosNaoPerigososEliminados: 1.83; MassaTotalDeResiduosRadioactivosEliminados: 0.000394; EnergiaElectricaExportada: 1.55; MateriaisParaRecuperacaoDeEnergia: 0.00739; MateriaisParaReciclagem: 0.0253; UnidadeEPD: 1 m²
Type - IFC.REVIGRÉS-Dados gerais-Floor Covering - Nome: REVIGRÉS-OMNISTONE-BASE-60X60-MATT RECT-ICE; TipoProduto: Prensado a seco: grupo BIa UGL | Grés porcelânico técnico; NumeroDeRegistoDAP: EPD-REV-20240006-CCC1-EN; ReferenciaDAP: -; UrlDOP: -
Classification: C3020 (Uniformat)
Pset_CoveringCommon - TotalThickness: 9.8 mm
IFC.REVIGRÉS-Dados do fabricante-Floor Covering - Type: Floor: REVIGRÉS-OMNISTONE-BASE-60X60-MATTRECT-ICE
IFC.REVIGRÉS-Dados de desempenho-Floor Covering - Type: Floor: REVIGRÉS-OMNISTONE-BASE-60X60-MATTRECT-ICE
IFC.REVIGRÉS-Dados de especificação-Floor Covering - Type: Floor: REVIGRÉS-OMNISTONE-BASE-60X60-MATTRECT-ICE
IFC.REVIGRÉS-Dados geométricos-Floor Covering - Type: Floor: REVIGRÉS-OMNISTONE-BASE-60X60-MATTRECT-ICE
IFC.REVIGRÉS-Dados de sustentabilidade-Floor Covering - Type: Floor: REVIGRÉS-OMNISTONE-BASE-60X60-MATTRECT-ICE

# IfcCovering: Floor:REVIGRÉS-OMNISTONE-BASE-60X60-MATTRECT-IRON, Floor:REVIGRÉS-OMNISTONE-BASE-60X60-MATTRECT-IRON:149128
In: Level 1
Type - PredefinedType: CLADDING; Material: REVIGRÉS-OMNISTONE-BASE-60x60-MATTRECT-IRON 9.8 mm
Type - Pset_CoveringCommon - Reference: 312BD390U1; Material: Grés porcelânico
Type - Pset_ElementShading - Roughness: 304.8 mm
Type - Pset_ManufacturerTypeInformation - Manufacturer: REVIGRÉS
Type - Pset_ProductRequirements - Category: Floors
Type - Pset_QuantityTakeOff - Reference: 312BD390U1
Type - IFC.REVIGRÉS-Dados do fabricante-Floor Covering - FabricanteURL: https://www.revigres.pt/; ReferenciaModelo: Omnistone; NumeroGlobalDeItemComercial: 312B1390U1; Acabamento: MATT RECT; Material: Grés porcelânico; IdentificadorDoOperadorEconomico: 501840856; UrlFabricanteArtigo: https://www.revigres.pt/colecoes/omnistone; PaisOrigem: Portugal
Type - IFC.REVIGRÉS-Dados de desempenho-Floor Covering - Rectilinearidade: ± 0.2% máx.± 0.8 mm; Ortogonalidade: ± 0.2% máx.± 1.5 mm; PlanaridadeDaSuperficie: ± 0.3% máx. ± 1.8 mm; QualidadeDaSuperficie: Cumpre; AbsorcaoDeAgua: < 0.05%; ModuloDeRuptura: > 45 N/mm130; ResistenciaAFlexao: ≥ 3500 N; ResistenciaAAbrasaoProfunda: < 120 mm131; DilatacaoTermicaLinear: ≤ 8,0x10-6 °C-1; ResistenciaAoChoqueTermico: Resiste; DurabilidadeResistenciaAoGeloDegelo: Resiste; ResistenciaAoEscorregamentoDIN51130: R10; ResistenciaAoEscorregamentoDIN51097: B; ResistenciaAoEscorregamentoENV51097: B; ResistenciaAoEscorregamentoENV12633: Class 2; ResistenciaAoEscorregamentoBS7976: >36; ResistenciaAoEscorregamentoANSIA1371: ≥0,42; ResistenciaAoDeslizamentoENV12633: Class 2; ResistenciaAoDeslizamentoBS7976: >36; ResistenciaAsManchas: Class 5; ResistenciaABaixasConcentracoesDeAcidosEAlcalis: Classe LA; ResistenciaAAltasConcentracoesDeAcidosEAlcalis: Classe HA; LibertacaoDeCadmio: 0; LibertacaoDeChumbo: 0
Type - IFC.REVIGRÉS-Dados de especificação-Floor Covering - VariacaoTonalidade: 3; NivelDeTrafego: 5; EPavimento: Sim; ERevestimento: Sim; EExterno: Sim
Type - IFC.REVIGRÉS-Dados geométricos-Floor Covering - AlturaNominal: 9.8 mm; ComprimentoNominal: 59.2 mm; LarguraNominal: 59.2 mm
Type - IFC.REVIGRÉS-Dados de sustentabilidade-Floor Covering - EnergiaTermicaExportada: 0; ItemENovo: Sim; ItemEParcialmenteReciclado: 0.14; ItemEReciclado: Sim; VidaÚtilEsperada: 50; SubstanciasPerigosas: Não; PotencialDeEsgotamentoAbioticoDosRecursosNaoFosseisMineraisEMetais: 0.000701; PotencialDeAquecimentoGlobalBiogenico: -0.48; CombustiveisFosseisComPotencialDeAquecimentoGlobal: 13.9; PotencialDeAquecimentoGlobalUsoDoSoloEMudancaDeUsoDoSolo: 0.0246; PotencialDeEutrofizacaoFraccaoDeNutrientesQueAtingemOCompartimentoFinalDeAguaDoce: 0.000189; PotencialDeEutrofizacaoFraccaoDeNutrientesQueAtingemOCompartimentoFinalMarinho: 0.0122; EnergiaRecuperada: 0.00739; ConsumoDeAguaDoce: 0.113; UtilizacaoLiquidaDeAguaDoce: 0.113; ResiduosPerigososEliminados: 0.00221; ResiduosNaoPerigososEliminados: 1.83; MassaTotalDeResiduosRadioactivosEliminados: 0.000394; EnergiaElectricaExportada: 1.55; MateriaisParaRecuperacaoDeEnergia: 0.00739; MateriaisParaReciclagem: 0.0253; UnidadeEPD: 1 m²
Type - IFC.REVIGRÉS-Dados gerais-Floor Covering - Nome: REVIGRÉS-OMNISTONE-BASE-60X60-MATT RECT-IRON; TipoProduto: Prensado a seco: grupo BIa UGL | Grés porcelânico técnico; NumeroDeRegistoDAP: EPD-REV-20240006-CCC1-EN; ReferenciaDAP: -; UrlDOP: -
Classification: C3020 (Uniformat)
Pset_CoveringCommon - TotalThickness: 9.8 mm
IFC.REVIGRÉS-Dados do fabricante-Floor Covering - Type: Floor: REVIGRÉS-OMNISTONE-BASE-60X60-MATTRECT-IRON
IFC.REVIGRÉS-Dados de desempenho-Floor Covering - Type: Floor: REVIGRÉS-OMNISTONE-BASE-60X60-MATTRECT-IRON
IFC.REVIGRÉS-Dados de especificação-Floor Covering - Type: Floor: REVIGRÉS-OMNISTONE-BASE-60X60-MATTRECT-IRON
IFC.REVIGRÉS-Dados geométricos-Floor Covering - Type: Floor: REVIGRÉS-OMNISTONE-BASE-60X60-MATTRECT-IRON
IFC.REVIGRÉS-Dados de sustentabilidade-Floor Covering - Type: Floor: REVIGRÉS-OMNISTONE-BASE-60X60-MATTRECT-IRON

# IfcCovering: Floor:REVIGRÉS-OMNISTONE-BASE-60X60-MATTRECT-JET, Floor:REVIGRÉS-OMNISTONE-BASE-60X60-MATTRECT-JET:149870
In: Level 1
Type - PredefinedType: CLADDING; Material: REVIGRÉS-OMNISTONE-BASE-60x60-MATTRECT-JET 9.8 mm
Type - Pset_CoveringCommon - Reference: 312BD391U1; Material: Grés porcelânico
Type - Pset_ElementShading - Roughness: 304.8 mm
Type - Pset_ManufacturerTypeInformation - Manufacturer: REVIGRÉS
Type - Pset_ProductRequirements - Category: Floors
Type - Pset_QuantityTakeOff - Reference: 312BD391U1
Type - IFC.REVIGRÉS-Dados do fabricante-Floor Covering - FabricanteURL: https://www.revigres.pt/; ReferenciaModelo: Omnistone; NumeroGlobalDeItemComercial: 312B1391U1; Acabamento: MATT RECT; Material: Grés porcelânico; IdentificadorDoOperadorEconomico: 501840856; UrlFabricanteArtigo: https://www.revigres.pt/colecoes/omnistone; PaisOrigem: Portugal
Type - IFC.REVIGRÉS-Dados de desempenho-Floor Covering - Rectilinearidade: ± 0.2% máx.± 0.8 mm; Ortogonalidade: ± 0.2% máx.± 1.5 mm; PlanaridadeDaSuperficie: ± 0.3% máx. ± 1.8 mm; QualidadeDaSuperficie: Cumpre; AbsorcaoDeAgua: < 0.05%; ModuloDeRuptura: > 45 N/mm130; ResistenciaAFlexao: ≥ 3500 N; ResistenciaAAbrasaoProfunda: < 120 mm131; DilatacaoTermicaLinear: ≤ 8,0x10-6 °C-1; ResistenciaAoChoqueTermico: Resiste; DurabilidadeResistenciaAoGeloDegelo: Resiste; ResistenciaAoEscorregamentoDIN51130: R10; ResistenciaAoEscorregamentoDIN51097: B; ResistenciaAoEscorregamentoENV51097: B; ResistenciaAoEscorregamentoENV12633: Class 2; ResistenciaAoEscorregamentoBS7976: >36; ResistenciaAoEscorregamentoANSIA1371: ≥0,42; ResistenciaAoDeslizamentoENV12633: Class 2; ResistenciaAoDeslizamentoBS7976: >36; ResistenciaAsManchas: Class 5; ResistenciaABaixasConcentracoesDeAcidosEAlcalis: Classe LA; ResistenciaAAltasConcentracoesDeAcidosEAlcalis: Classe HA; LibertacaoDeCadmio: 0; LibertacaoDeChumbo: 0
Type - IFC.REVIGRÉS-Dados de especificação-Floor Covering - VariacaoTonalidade: 3; NivelDeTrafego: 5; EPavimento: Sim; ERevestimento: Sim; EExterno: Sim
Type - IFC.REVIGRÉS-Dados geométricos-Floor Covering - AlturaNominal: 9.8 mm; ComprimentoNominal: 59.2 mm; LarguraNominal: 59.2 mm
Type - IFC.REVIGRÉS-Dados de sustentabilidade-Floor Covering - ItemEParcialmenteReciclado: 0; EnergiaTermicaExportada: 0; ItemENovo: Sim; ItemEReciclado: Não; VidaÚtilEsperada: 50; SubstanciasPerigosas: Não; PotencialDeEsgotamentoAbioticoDosRecursosNaoFosseisMineraisEMetais: 0.000701; PotencialDeAquecimentoGlobalBiogenico: -0.48; CombustiveisFosseisComPotencialDeAquecimentoGlobal: 13.9; PotencialDeAquecimentoGlobalUsoDoSoloEMudancaDeUsoDoSolo: 0.0246; PotencialDeEutrofizacaoFraccaoDeNutrientesQueAtingemOCompartimentoFinalDeAguaDoce: 0.000189; PotencialDeEutrofizacaoFraccaoDeNutrientesQueAtingemOCompartimentoFinalMarinho: 0.0122; EnergiaRecuperada: 0.00739; ConsumoDeAguaDoce: 0.113; UtilizacaoLiquidaDeAguaDoce: 0.113; ResiduosPerigososEliminados: 0.00221; ResiduosNaoPerigososEliminados: 1.83; MassaTotalDeResiduosRadioactivosEliminados: 0.000394; EnergiaElectricaExportada: 1.55; MateriaisParaRecuperacaoDeEnergia: 0.00739; MateriaisParaReciclagem: 0.0253; UnidadeEPD: 1 m²
Type - IFC.REVIGRÉS-Dados gerais-Floor Covering - Nome: REVIGRÉS-OMNISTONE-BASE-60X60-MATT RECT-JET; TipoProduto: Prensado a seco: grupo BIa UGL | Grés porcelânico técnico; NumeroDeRegistoDAP: EPD-REV-20240006-CCC1-EN; ReferenciaDAP: -; UrlDOP: -
Classification: C3020 (Uniformat)
Pset_CoveringCommon - TotalThickness: 9.8 mm
IFC.REVIGRÉS-Dados do fabricante-Floor Covering - Type: Floor: REVIGRÉS-OMNISTONE-BASE-60X60-MATTRECT-JET
IFC.REVIGRÉS-Dados de desempenho-Floor Covering - Type: Floor: REVIGRÉS-OMNISTONE-BASE-60X60-MATTRECT-JET
IFC.REVIGRÉS-Dados de especificação-Floor Covering - Type: Floor: REVIGRÉS-OMNISTONE-BASE-60X60-MATTRECT-JET
IFC.REVIGRÉS-Dados geométricos-Floor Covering - Type: Floor: REVIGRÉS-OMNISTONE-BASE-60X60-MATTRECT-JET
IFC.REVIGRÉS-Dados de sustentabilidade-Floor Covering - Type: Floor: REVIGRÉS-OMNISTONE-BASE-60X60-MATTRECT-JET

# IfcCovering: Floor:REVIGRÉS-OMNISTONE-BASE-60X60-MATTRECT-PLATINA, Floor:REVIGRÉS-OMNISTONE-BASE-60X60-MATTRECT-PLATINA:150591
In: Level 1
Type - PredefinedType: CLADDING; Material: REVIGRÉS-OMNISTONE-BASE-60x60-MATTRECT-PLATINA 9.8 mm
Type - Pset_CoveringCommon - Reference: 312BD392U1; Material: Grés porcelânico
Type - Pset_ElementShading - Roughness: 304.8 mm
Type - Pset_ManufacturerTypeInformation - Manufacturer: REVIGRÉS
Type - Pset_ProductRequirements - Category: Floors
Type - Pset_QuantityTakeOff - Reference: 312BD392U1
Type - IFC.REVIGRÉS-Dados do fabricante-Floor Covering - FabricanteURL: https://www.revigres.pt/; ReferenciaModelo: Omnistone; NumeroGlobalDeItemComercial: 312B1392U1; Acabamento: MATT RECT; Material: Grés porcelânico; IdentificadorDoOperadorEconomico: 501840856; UrlFabricanteArtigo: https://www.revigres.pt/colecoes/omnistone; PaisOrigem: Portugal
Type - IFC.REVIGRÉS-Dados de desempenho-Floor Covering - Rectilinearidade: ± 0.2% máx.± 0.8 mm; Ortogonalidade: ± 0.2% máx.± 1.5 mm; PlanaridadeDaSuperficie: ± 0.3% máx. ± 1.8 mm; QualidadeDaSuperficie: Cumpre; AbsorcaoDeAgua: < 0.05%; ModuloDeRuptura: > 45 N/mm130; ResistenciaAFlexao: ≥ 3500 N; ResistenciaAAbrasaoProfunda: < 120 mm131; DilatacaoTermicaLinear: ≤ 8,0x10-6 °C-1; ResistenciaAoChoqueTermico: Resiste; DurabilidadeResistenciaAoGeloDegelo: Resiste; ResistenciaAoEscorregamentoDIN51130: R10; ResistenciaAoEscorregamentoDIN51097: B; ResistenciaAoEscorregamentoENV51097: B; ResistenciaAoEscorregamentoENV12633: Class 2; ResistenciaAoEscorregamentoBS7976: >36; ResistenciaAoEscorregamentoANSIA1371: ≥0,42; ResistenciaAoDeslizamentoENV12633: Class 2; ResistenciaAoDeslizamentoBS7976: >36; ResistenciaAsManchas: Class 5; ResistenciaABaixasConcentracoesDeAcidosEAlcalis: Classe LA; ResistenciaAAltasConcentracoesDeAcidosEAlcalis: Classe HA; LibertacaoDeCadmio: 0; LibertacaoDeChumbo: 0
Type - IFC.REVIGRÉS-Dados de especificação-Floor Covering - VariacaoTonalidade: 3; NivelDeTrafego: 5; EPavimento: Sim; ERevestimento: Sim; EExterno: Sim
Type - IFC.REVIGRÉS-Dados geométricos-Floor Covering - AlturaNominal: 9.8 mm; ComprimentoNominal: 59.2 mm; LarguraNominal: 59.2 mm
Type - IFC.REVIGRÉS-Dados de sustentabilidade-Floor Covering - ItemEParcialmenteReciclado: 0; EnergiaTermicaExportada: 0; ItemENovo: Sim; ItemEReciclado: Não; VidaÚtilEsperada: 50; SubstanciasPerigosas: Não; PotencialDeEsgotamentoAbioticoDosRecursosNaoFosseisMineraisEMetais: 0.000701; PotencialDeAquecimentoGlobalBiogenico: -0.48; CombustiveisFosseisComPotencialDeAquecimentoGlobal: 13.9; PotencialDeAquecimentoGlobalUsoDoSoloEMudancaDeUsoDoSolo: 0.0246; PotencialDeEutrofizacaoFraccaoDeNutrientesQueAtingemOCompartimentoFinalDeAguaDoce: 0.000189; PotencialDeEutrofizacaoFraccaoDeNutrientesQueAtingemOCompartimentoFinalMarinho: 0.0122; EnergiaRecuperada: 0.00739; ConsumoDeAguaDoce: 0.113; UtilizacaoLiquidaDeAguaDoce: 0.113; ResiduosPerigososEliminados: 0.00221; ResiduosNaoPerigososEliminados: 1.83; MassaTotalDeResiduosRadioactivosEliminados: 0.000394; EnergiaElectricaExportada: 1.55; MateriaisParaRecuperacaoDeEnergia: 0.00739; MateriaisParaReciclagem: 0.0253; UnidadeEPD: 1 m²
Type - IFC.REVIGRÉS-Dados gerais-Floor Covering - Nome: REVIGRÉS-OMNISTONE-BASE-60X60-MATT RECT-PLATINA; TipoProduto: Prensado a seco: grupo BIa UGL | Grés porcelânico técnico; NumeroDeRegistoDAP: EPD-REV-20240006-CCC1-EN; ReferenciaDAP: -; UrlDOP: -
Classification: C3020 (Uniformat)
Pset_CoveringCommon - TotalThickness: 9.8 mm
IFC.REVIGRÉS-Dados do fabricante-Floor Covering - Type: Floor: REVIGRÉS-OMNISTONE-BASE-60X60-MATTRECT-PLATINA
IFC.REVIGRÉS-Dados de desempenho-Floor Covering - Type: Floor: REVIGRÉS-OMNISTONE-BASE-60X60-MATTRECT-PLATINA
IFC.REVIGRÉS-Dados de especificação-Floor Covering - Type: Floor: REVIGRÉS-OMNISTONE-BASE-60X60-MATTRECT-PLATINA
IFC.REVIGRÉS-Dados geométricos-Floor Covering - Type: Floor: REVIGRÉS-OMNISTONE-BASE-60X60-MATTRECT-PLATINA
IFC.REVIGRÉS-Dados de sustentabilidade-Floor Covering - Type: Floor: REVIGRÉS-OMNISTONE-BASE-60X60-MATTRECT-PLATINA

# IfcCovering: Floor:REVIGRÉS-OMNISTONE-BASE-60X60-MATTRECT-ROPE, Floor:REVIGRÉS-OMNISTONE-BASE-60X60-MATTRECT-ROPE:151296
In: Level 1
Type - PredefinedType: CLADDING; Material: REVIGRÉS-OMNISTONE-BASE-60x60-MATTRECT-ROPE 9.8 mm
Type - Pset_CoveringCommon - Reference: 312BD393U1; Material: Grés porcelânico
Type - Pset_ElementShading - Roughness: 304.8 mm
Type - Pset_ManufacturerTypeInformation - Manufacturer: REVIGRÉS
Type - Pset_ProductRequirements - Category: Floors
Type - Pset_QuantityTakeOff - Reference: 312BD393U1
Type - IFC.REVIGRÉS-Dados do fabricante-Floor Covering - FabricanteURL: https://www.revigres.pt/; ReferenciaModelo: Omnistone; NumeroGlobalDeItemComercial: 312B1393U1; Acabamento: MATT RECT; Material: Grés porcelânico; IdentificadorDoOperadorEconomico: 501840856; UrlFabricanteArtigo: https://www.revigres.pt/colecoes/omnistone; PaisOrigem: Portugal
Type - IFC.REVIGRÉS-Dados de desempenho-Floor Covering - Rectilinearidade: ± 0.2% máx.± 0.8 mm; Ortogonalidade: ± 0.2% máx.± 1.5 mm; PlanaridadeDaSuperficie: ± 0.3% máx. ± 1.8 mm; QualidadeDaSuperficie: Cumpre; AbsorcaoDeAgua: < 0.05%; ModuloDeRuptura: > 45 N/mm130; ResistenciaAFlexao: ≥ 3500 N; ResistenciaAAbrasaoProfunda: < 120 mm131; DilatacaoTermicaLinear: ≤ 8,0x10-6 °C-1; ResistenciaAoChoqueTermico: Resiste; DurabilidadeResistenciaAoGeloDegelo: Resiste; ResistenciaAoEscorregamentoDIN51130: R10; ResistenciaAoEscorregamentoDIN51097: B; ResistenciaAoEscorregamentoENV51097: B; ResistenciaAoEscorregamentoENV12633: Class 2; ResistenciaAoEscorregamentoBS7976: >36; ResistenciaAoEscorregamentoANSIA1371: ≥0,42; ResistenciaAoDeslizamentoENV12633: Class 2; ResistenciaAoDeslizamentoBS7976: >36; ResistenciaAsManchas: Class 5; ResistenciaABaixasConcentracoesDeAcidosEAlcalis: Classe LA; ResistenciaAAltasConcentracoesDeAcidosEAlcalis: Classe HA; LibertacaoDeCadmio: 0; LibertacaoDeChumbo: 0
Type - IFC.REVIGRÉS-Dados de especificação-Floor Covering - VariacaoTonalidade: 3; NivelDeTrafego: 5; EPavimento: Sim; ERevestimento: Sim; EExterno: Sim
Type - IFC.REVIGRÉS-Dados geométricos-Floor Covering - AlturaNominal: 9.8 mm; ComprimentoNominal: 59.2 mm; LarguraNominal: 59.2 mm
Type - IFC.REVIGRÉS-Dados de sustentabilidade-Floor Covering - ItemEParcialmenteReciclado: 0; EnergiaTermicaExportada: 0; ItemENovo: Sim; ItemEReciclado: Não; VidaÚtilEsperada: 50; SubstanciasPerigosas: Não; PotencialDeEsgotamentoAbioticoDosRecursosNaoFosseisMineraisEMetais: 0.000701; PotencialDeAquecimentoGlobalBiogenico: -0.48; CombustiveisFosseisComPotencialDeAquecimentoGlobal: 13.9; PotencialDeAquecimentoGlobalUsoDoSoloEMudancaDeUsoDoSolo: 0.0246; PotencialDeEutrofizacaoFraccaoDeNutrientesQueAtingemOCompartimentoFinalDeAguaDoce: 0.000189; PotencialDeEutrofizacaoFraccaoDeNutrientesQueAtingemOCompartimentoFinalMarinho: 0.0122; EnergiaRecuperada: 0.00739; ConsumoDeAguaDoce: 0.113; UtilizacaoLiquidaDeAguaDoce: 0.113; ResiduosPerigososEliminados: 0.00221; ResiduosNaoPerigososEliminados: 1.83; MassaTotalDeResiduosRadioactivosEliminados: 0.000394; EnergiaElectricaExportada: 1.55; MateriaisParaRecuperacaoDeEnergia: 0.00739; MateriaisParaReciclagem: 0.0253; UnidadeEPD: 1 m²
Type - IFC.REVIGRÉS-Dados gerais-Floor Covering - Nome: REVIGRÉS-OMNISTONE-BASE-60X60-MATT RECT-ROPE; TipoProduto: Prensado a seco: grupo BIa UGL | Grés porcelânico técnico; NumeroDeRegistoDAP: EPD-REV-20240006-CCC1-EN; ReferenciaDAP: -; UrlDOP: -
Classification: C3020 (Uniformat)
Pset_CoveringCommon - TotalThickness: 9.8 mm
IFC.REVIGRÉS-Dados do fabricante-Floor Covering - Type: Floor: REVIGRÉS-OMNISTONE-BASE-60X60-MATTRECT-ROPE
IFC.REVIGRÉS-Dados de desempenho-Floor Covering - Type: Floor: REVIGRÉS-OMNISTONE-BASE-60X60-MATTRECT-ROPE
IFC.REVIGRÉS-Dados de especificação-Floor Covering - Type: Floor: REVIGRÉS-OMNISTONE-BASE-60X60-MATTRECT-ROPE
IFC.REVIGRÉS-Dados geométricos-Floor Covering - Type: Floor: REVIGRÉS-OMNISTONE-BASE-60X60-MATTRECT-ROPE
IFC.REVIGRÉS-Dados de sustentabilidade-Floor Covering - Type: Floor: REVIGRÉS-OMNISTONE-BASE-60X60-MATTRECT-ROPE

# IfcCovering: Floor:REVIGRÉS-OMNISTONE-BASE-60X60-SOFT-BONE, Floor:REVIGRÉS-OMNISTONE-BASE-60X60-SOFT-BONE:146514
In: Level 1
Type - PredefinedType: CLADDING; Material: REVIGRÉS-OMNISTONE-BASE-60x60-SOFT-BONE 9.8 mm
Type - Pset_CoveringCommon - Reference: 3126D388U1; Material: Grés porcelânico
Type - Pset_ElementShading - Roughness: 304.8 mm
Type - Pset_ManufacturerTypeInformation - Manufacturer: REVIGRÉS
Type - Pset_ProductRequirements - Category: Floors
Type - Pset_QuantityTakeOff - Reference: 3126D388U1
Type - IFC.REVIGRÉS-Dados do fabricante-Floor Covering - FabricanteURL: https://www.revigres.pt/; ReferenciaModelo: Omnistone; NumeroGlobalDeItemComercial: 31261388U1; Acabamento: SOFT; Material: Grés porcelânico; IdentificadorDoOperadorEconomico: 501840856; UrlFabricanteArtigo: https://www.revigres.pt/colecoes/omnistone; PaisOrigem: Portugal
Type - IFC.REVIGRÉS-Dados de desempenho-Floor Covering - Rectilinearidade: ± 0.2% máx.± 0.8 mm; Ortogonalidade: ± 0.2% máx.± 1.5 mm; PlanaridadeDaSuperficie: ± 0.3% máx. ± 1.8 mm; QualidadeDaSuperficie: Cumpre; AbsorcaoDeAgua: < 0.05%; ModuloDeRuptura: > 45 N/mm130; ResistenciaAFlexao: ≥ 3500 N; ResistenciaAAbrasaoProfunda: < 120 mm131; DilatacaoTermicaLinear: ≤ 8,0x10-6 °C-1; ResistenciaAoChoqueTermico: Resiste; DurabilidadeResistenciaAoGeloDegelo: Resiste; ResistenciaAsManchas: Class 5; ResistenciaABaixasConcentracoesDeAcidosEAlcalis: Classe LA; ResistenciaAAltasConcentracoesDeAcidosEAlcalis: Classe HA; LibertacaoDeCadmio: 0; LibertacaoDeChumbo: 0
Type - IFC.REVIGRÉS-Dados de especificação-Floor Covering - VariacaoTonalidade: 3; NivelDeTrafego: 5; EPavimento: Sim; ERevestimento: Sim; EExterno: Sim
Type - IFC.REVIGRÉS-Dados geométricos-Floor Covering - AlturaNominal: 9.8 mm; ComprimentoNominal: 59.2 mm; LarguraNominal: 59.2 mm
Type - IFC.REVIGRÉS-Dados de sustentabilidade-Floor Covering - ItemEParcialmenteReciclado: 0; EnergiaTermicaExportada: 0; ItemENovo: Sim; ItemEReciclado: Não; VidaÚtilEsperada: 50; SubstanciasPerigosas: Não; PotencialDeEsgotamentoAbioticoDosRecursosNaoFosseisMineraisEMetais: 0.000701; PotencialDeAquecimentoGlobalBiogenico: -0.48; CombustiveisFosseisComPotencialDeAquecimentoGlobal: 13.9; PotencialDeAquecimentoGlobalUsoDoSoloEMudancaDeUsoDoSolo: 0.0246; PotencialDeEutrofizacaoFraccaoDeNutrientesQueAtingemOCompartimentoFinalDeAguaDoce: 0.000189; PotencialDeEutrofizacaoFraccaoDeNutrientesQueAtingemOCompartimentoFinalMarinho: 0.0122; EnergiaRecuperada: 0.00739; ConsumoDeAguaDoce: 0.113; UtilizacaoLiquidaDeAguaDoce: 0.113; ResiduosPerigososEliminados: 0.00221; ResiduosNaoPerigososEliminados: 1.83; MassaTotalDeResiduosRadioactivosEliminados: 0.000394; EnergiaElectricaExportada: 1.55; MateriaisParaRecuperacaoDeEnergia: 0.00739; MateriaisParaReciclagem: 0.0253; UnidadeEPD: 1 m²
Type - IFC.REVIGRÉS-Dados gerais-Floor Covering - Nome: REVIGRÉS-OMNISTONE-BASE-60X60-SOFT-BONE; TipoProduto: Prensado a seco: grupo BIa UGL | Grés porcelânico técnico; NumeroDeRegistoDAP: EPD-REV-20240006-CCC1-EN; ReferenciaDAP: -; UrlDOP: -
Classification: C3020 (Uniformat)
Pset_CoveringCommon - TotalThickness: 9.8 mm
IFC.REVIGRÉS-Dados do fabricante-Floor Covering - Type: Floor: REVIGRÉS-OMNISTONE-BASE-60X60-SOFT-BONE
IFC.REVIGRÉS-Dados de desempenho-Floor Covering - Type: Floor: REVIGRÉS-OMNISTONE-BASE-60X60-SOFT-BONE
IFC.REVIGRÉS-Dados de especificação-Floor Covering - Type: Floor: REVIGRÉS-OMNISTONE-BASE-60X60-SOFT-BONE
IFC.REVIGRÉS-Dados geométricos-Floor Covering - Type: Floor: REVIGRÉS-OMNISTONE-BASE-60X60-SOFT-BONE
IFC.REVIGRÉS-Dados de sustentabilidade-Floor Covering - Type: Floor: REVIGRÉS-OMNISTONE-BASE-60X60-SOFT-BONE

# IfcCovering: Floor:REVIGRÉS-OMNISTONE-BASE-60X60-SOFT-ICE, Floor:REVIGRÉS-OMNISTONE-BASE-60X60-SOFT-ICE:148523
In: Level 1
Type - PredefinedType: CLADDING; Material: REVIGRÉS-OMNISTONE-BASE-60x60-SOFT-ICE 9.8 mm
Type - Pset_CoveringCommon - Reference: 3126D389U1; Material: Grés porcelânico
Type - Pset_ElementShading - Roughness: 304.8 mm
Type - Pset_ManufacturerTypeInformation - Manufacturer: REVIGRÉS
Type - Pset_ProductRequirements - Category: Floors
Type - Pset_QuantityTakeOff - Reference: 3126D389U1
Type - IFC.REVIGRÉS-Dados do fabricante-Floor Covering - FabricanteURL: https://www.revigres.pt/; ReferenciaModelo: Omnistone; NumeroGlobalDeItemComercial: 31261389U1; Acabamento: SOFT; Material: Grés porcelânico; IdentificadorDoOperadorEconomico: 501840856; UrlFabricanteArtigo: https://www.revigres.pt/colecoes/omnistone; PaisOrigem: Portugal
Type - IFC.REVIGRÉS-Dados de desempenho-Floor Covering - Rectilinearidade: ± 0.2% máx.± 0.8 mm; Ortogonalidade: ± 0.2% máx.± 1.5 mm; PlanaridadeDaSuperficie: ± 0.3% máx. ± 1.8 mm; QualidadeDaSuperficie: Cumpre; AbsorcaoDeAgua: < 0.05%; ModuloDeRuptura: > 45 N/mm130; ResistenciaAFlexao: ≥ 3500 N; ResistenciaAAbrasaoProfunda: < 120 mm131; DilatacaoTermicaLinear: ≤ 8,0x10-6 °C-1; ResistenciaAoChoqueTermico: Resiste; DurabilidadeResistenciaAoGeloDegelo: Resiste; ResistenciaAsManchas: Class 5; ResistenciaABaixasConcentracoesDeAcidosEAlcalis: Classe LA; ResistenciaAAltasConcentracoesDeAcidosEAlcalis: Classe HA; LibertacaoDeCadmio: 0; LibertacaoDeChumbo: 0
Type - IFC.REVIGRÉS-Dados de especificação-Floor Covering - VariacaoTonalidade: 3; NivelDeTrafego: 5; EPavimento: Sim; ERevestimento: Sim; EExterno: Sim
Type - IFC.REVIGRÉS-Dados geométricos-Floor Covering - AlturaNominal: 9.8 mm; ComprimentoNominal: 59.2 mm; LarguraNominal: 59.2 mm
Type - IFC.REVIGRÉS-Dados de sustentabilidade-Floor Covering - ItemEParcialmenteReciclado: 0; EnergiaTermicaExportada: 0; ItemENovo: Sim; ItemEReciclado: Não; VidaÚtilEsperada: 50; SubstanciasPerigosas: Não; PotencialDeEsgotamentoAbioticoDosRecursosNaoFosseisMineraisEMetais: 0.000701; PotencialDeAquecimentoGlobalBiogenico: -0.48; CombustiveisFosseisComPotencialDeAquecimentoGlobal: 13.9; PotencialDeAquecimentoGlobalUsoDoSoloEMudancaDeUsoDoSolo: 0.0246; PotencialDeEutrofizacaoFraccaoDeNutrientesQueAtingemOCompartimentoFinalDeAguaDoce: 0.000189; PotencialDeEutrofizacaoFraccaoDeNutrientesQueAtingemOCompartimentoFinalMarinho: 0.0122; EnergiaRecuperada: 0.00739; ConsumoDeAguaDoce: 0.113; UtilizacaoLiquidaDeAguaDoce: 0.113; ResiduosPerigososEliminados: 0.00221; ResiduosNaoPerigososEliminados: 1.83; MassaTotalDeResiduosRadioactivosEliminados: 0.000394; EnergiaElectricaExportada: 1.55; MateriaisParaRecuperacaoDeEnergia: 0.00739; MateriaisParaReciclagem: 0.0253; UnidadeEPD: 1 m²
Type - IFC.REVIGRÉS-Dados gerais-Floor Covering - Nome: REVIGRÉS-OMNISTONE-BASE-60X60-SOFT-ICE; TipoProduto: Prensado a seco: grupo BIa UGL | Grés porcelânico técnico; NumeroDeRegistoDAP: EPD-REV-20240006-CCC1-EN; ReferenciaDAP: -; UrlDOP: -
Classification: C3020 (Uniformat)
Pset_CoveringCommon - TotalThickness: 9.8 mm
IFC.REVIGRÉS-Dados do fabricante-Floor Covering - Type: Floor: REVIGRÉS-OMNISTONE-BASE-60X60-SOFT-ICE
IFC.REVIGRÉS-Dados de desempenho-Floor Covering - Type: Floor: REVIGRÉS-OMNISTONE-BASE-60X60-SOFT-ICE
IFC.REVIGRÉS-Dados de especificação-Floor Covering - Type: Floor: REVIGRÉS-OMNISTONE-BASE-60X60-SOFT-ICE
IFC.REVIGRÉS-Dados geométricos-Floor Covering - Type: Floor: REVIGRÉS-OMNISTONE-BASE-60X60-SOFT-ICE
IFC.REVIGRÉS-Dados de sustentabilidade-Floor Covering - Type: Floor: REVIGRÉS-OMNISTONE-BASE-60X60-SOFT-ICE

# IfcCovering: Floor:REVIGRÉS-OMNISTONE-BASE-60X60-SOFT-IRON, Floor:REVIGRÉS-OMNISTONE-BASE-60X60-SOFT-IRON:149208
In: Level 1
Type - PredefinedType: CLADDING; Material: REVIGRÉS-OMNISTONE-BASE-60x60-SOFT-IRON 9.8 mm
Type - Pset_CoveringCommon - Reference: 3126D390U1; Material: Grés porcelânico
Type - Pset_ElementShading - Roughness: 304.8 mm
Type - Pset_ManufacturerTypeInformation - Manufacturer: REVIGRÉS
Type - Pset_ProductRequirements - Category: Floors
Type - Pset_QuantityTakeOff - Reference: 3126D390U1
Type - IFC.REVIGRÉS-Dados do fabricante-Floor Covering - FabricanteURL: https://www.revigres.pt/; ReferenciaModelo: Omnistone; NumeroGlobalDeItemComercial: 31261390U1; Acabamento: SOFT; Material: Grés porcelânico; IdentificadorDoOperadorEconomico: 501840856; UrlFabricanteArtigo: https://www.revigres.pt/colecoes/omnistone; PaisOrigem: Portugal
Type - IFC.REVIGRÉS-Dados de desempenho-Floor Covering - Rectilinearidade: ± 0.2% máx.± 0.8 mm; Ortogonalidade: ± 0.2% máx.± 1.5 mm; PlanaridadeDaSuperficie: ± 0.3% máx. ± 1.8 mm; QualidadeDaSuperficie: Cumpre; AbsorcaoDeAgua: < 0.05%; ModuloDeRuptura: > 45 N/mm130; ResistenciaAFlexao: ≥ 3500 N; ResistenciaAAbrasaoProfunda: < 120 mm131; DilatacaoTermicaLinear: ≤ 8,0x10-6 °C-1; ResistenciaAoChoqueTermico: Resiste; DurabilidadeResistenciaAoGeloDegelo: Resiste; ResistenciaAsManchas: Class 5; ResistenciaABaixasConcentracoesDeAcidosEAlcalis: Classe LA; ResistenciaAAltasConcentracoesDeAcidosEAlcalis: Classe HA; LibertacaoDeCadmio: 0; LibertacaoDeChumbo: 0
Type - IFC.REVIGRÉS-Dados de especificação-Floor Covering - VariacaoTonalidade: 3; NivelDeTrafego: 5; EPavimento: Sim; ERevestimento: Sim; EExterno: Sim
Type - IFC.REVIGRÉS-Dados geométricos-Floor Covering - AlturaNominal: 9.8 mm; ComprimentoNominal: 59.2 mm; LarguraNominal: 59.2 mm
Type - IFC.REVIGRÉS-Dados de sustentabilidade-Floor Covering - EnergiaTermicaExportada: 0; ItemENovo: Sim; ItemEParcialmenteReciclado: 0.14; ItemEReciclado: Sim; VidaÚtilEsperada: 50; SubstanciasPerigosas: Não; PotencialDeEsgotamentoAbioticoDosRecursosNaoFosseisMineraisEMetais: 0.000701; PotencialDeAquecimentoGlobalBiogenico: -0.48; CombustiveisFosseisComPotencialDeAquecimentoGlobal: 13.9; PotencialDeAquecimentoGlobalUsoDoSoloEMudancaDeUsoDoSolo: 0.0246; PotencialDeEutrofizacaoFraccaoDeNutrientesQueAtingemOCompartimentoFinalDeAguaDoce: 0.000189; PotencialDeEutrofizacaoFraccaoDeNutrientesQueAtingemOCompartimentoFinalMarinho: 0.0122; EnergiaRecuperada: 0.00739; ConsumoDeAguaDoce: 0.113; UtilizacaoLiquidaDeAguaDoce: 0.113; ResiduosPerigososEliminados: 0.00221; ResiduosNaoPerigososEliminados: 1.83; MassaTotalDeResiduosRadioactivosEliminados: 0.000394; EnergiaElectricaExportada: 1.55; MateriaisParaRecuperacaoDeEnergia: 0.00739; MateriaisParaReciclagem: 0.0253; UnidadeEPD: 1 m²
Type - IFC.REVIGRÉS-Dados gerais-Floor Covering - Nome: REVIGRÉS-OMNISTONE-BASE-60X60-SOFT-IRON; TipoProduto: Prensado a seco: grupo BIa UGL | Grés porcelânico técnico; NumeroDeRegistoDAP: EPD-REV-20240006-CCC1-EN; ReferenciaDAP: -; UrlDOP: -
Classification: C3020 (Uniformat)
Pset_CoveringCommon - TotalThickness: 9.8 mm
IFC.REVIGRÉS-Dados do fabricante-Floor Covering - Type: Floor: REVIGRÉS-OMNISTONE-BASE-60X60-SOFT-IRON
IFC.REVIGRÉS-Dados de desempenho-Floor Covering - Type: Floor: REVIGRÉS-OMNISTONE-BASE-60X60-SOFT-IRON
IFC.REVIGRÉS-Dados de especificação-Floor Covering - Type: Floor: REVIGRÉS-OMNISTONE-BASE-60X60-SOFT-IRON
IFC.REVIGRÉS-Dados geométricos-Floor Covering - Type: Floor: REVIGRÉS-OMNISTONE-BASE-60X60-SOFT-IRON
IFC.REVIGRÉS-Dados de sustentabilidade-Floor Covering - Type: Floor: REVIGRÉS-OMNISTONE-BASE-60X60-SOFT-IRON

# IfcCovering: Floor:REVIGRÉS-OMNISTONE-BASE-60X60-SOFT-JET, Floor:REVIGRÉS-OMNISTONE-BASE-60X60-SOFT-JET:149950
In: Level 1
Type - PredefinedType: CLADDING; Material: REVIGRÉS-OMNISTONE-BASE-60x60-SOFT-JET 9.8 mm
Type - Pset_CoveringCommon - Reference: 3126D391U1; Material: Grés porcelânico
Type - Pset_ElementShading - Roughness: 304.8 mm
Type - Pset_ManufacturerTypeInformation - Manufacturer: REVIGRÉS
Type - Pset_ProductRequirements - Category: Floors
Type - Pset_QuantityTakeOff - Reference: 3126D391U1
Type - IFC.REVIGRÉS-Dados do fabricante-Floor Covering - FabricanteURL: https://www.revigres.pt/; ReferenciaModelo: Omnistone; NumeroGlobalDeItemComercial: 31261391U1; Acabamento: SOFT; Material: Grés porcelânico; IdentificadorDoOperadorEconomico: 501840856; UrlFabricanteArtigo: https://www.revigres.pt/colecoes/omnistone; PaisOrigem: Portugal
Type - IFC.REVIGRÉS-Dados de desempenho-Floor Covering - Rectilinearidade: ± 0.2% máx.± 0.8 mm; Ortogonalidade: ± 0.2% máx.± 1.5 mm; PlanaridadeDaSuperficie: ± 0.3% máx. ± 1.8 mm; QualidadeDaSuperficie: Cumpre; AbsorcaoDeAgua: < 0.05%; ModuloDeRuptura: > 45 N/mm130; ResistenciaAFlexao: ≥ 3500 N; ResistenciaAAbrasaoProfunda: < 120 mm131; DilatacaoTermicaLinear: ≤ 8,0x10-6 °C-1; ResistenciaAoChoqueTermico: Resiste; DurabilidadeResistenciaAoGeloDegelo: Resiste; ResistenciaAsManchas: Class 5; ResistenciaABaixasConcentracoesDeAcidosEAlcalis: Classe LA; ResistenciaAAltasConcentracoesDeAcidosEAlcalis: Classe HA; LibertacaoDeCadmio: 0; LibertacaoDeChumbo: 0
Type - IFC.REVIGRÉS-Dados de especificação-Floor Covering - VariacaoTonalidade: 3; NivelDeTrafego: 5; EPavimento: Sim; ERevestimento: Sim; EExterno: Sim
Type - IFC.REVIGRÉS-Dados geométricos-Floor Covering - AlturaNominal: 9.8 mm; ComprimentoNominal: 59.2 mm; LarguraNominal: 59.2 mm
Type - IFC.REVIGRÉS-Dados de sustentabilidade-Floor Covering - ItemEParcialmenteReciclado: 0; EnergiaTermicaExportada: 0; ItemENovo: Sim; ItemEReciclado: Não; VidaÚtilEsperada: 50; SubstanciasPerigosas: Não; PotencialDeEsgotamentoAbioticoDosRecursosNaoFosseisMineraisEMetais: 0.000701; PotencialDeAquecimentoGlobalBiogenico: -0.48; CombustiveisFosseisComPotencialDeAquecimentoGlobal: 13.9; PotencialDeAquecimentoGlobalUsoDoSoloEMudancaDeUsoDoSolo: 0.0246; PotencialDeEutrofizacaoFraccaoDeNutrientesQueAtingemOCompartimentoFinalDeAguaDoce: 0.000189; PotencialDeEutrofizacaoFraccaoDeNutrientesQueAtingemOCompartimentoFinalMarinho: 0.0122; EnergiaRecuperada: 0.00739; ConsumoDeAguaDoce: 0.113; UtilizacaoLiquidaDeAguaDoce: 0.113; ResiduosPerigososEliminados: 0.00221; ResiduosNaoPerigososEliminados: 1.83; MassaTotalDeResiduosRadioactivosEliminados: 0.000394; EnergiaElectricaExportada: 1.55; MateriaisParaRecuperacaoDeEnergia: 0.00739; MateriaisParaReciclagem: 0.0253; UnidadeEPD: 1 m²
Type - IFC.REVIGRÉS-Dados gerais-Floor Covering - Nome: REVIGRÉS-OMNISTONE-BASE-60X60-SOFT-JET; TipoProduto: Prensado a seco: grupo BIa UGL | Grés porcelânico técnico; NumeroDeRegistoDAP: EPD-REV-20240006-CCC1-EN; ReferenciaDAP: -; UrlDOP: -
Classification: C3020 (Uniformat)
Pset_CoveringCommon - TotalThickness: 9.8 mm
IFC.REVIGRÉS-Dados do fabricante-Floor Covering - Type: Floor: REVIGRÉS-OMNISTONE-BASE-60X60-SOFT-JET
IFC.REVIGRÉS-Dados de desempenho-Floor Covering - Type: Floor: REVIGRÉS-OMNISTONE-BASE-60X60-SOFT-JET
IFC.REVIGRÉS-Dados de especificação-Floor Covering - Type: Floor: REVIGRÉS-OMNISTONE-BASE-60X60-SOFT-JET
IFC.REVIGRÉS-Dados geométricos-Floor Covering - Type: Floor: REVIGRÉS-OMNISTONE-BASE-60X60-SOFT-JET
IFC.REVIGRÉS-Dados de sustentabilidade-Floor Covering - Type: Floor: REVIGRÉS-OMNISTONE-BASE-60X60-SOFT-JET

# IfcCovering: Floor:REVIGRÉS-OMNISTONE-BASE-60X60-SOFT-PLATINA, Floor:REVIGRÉS-OMNISTONE-BASE-60X60-SOFT-PLATINA:150671
In: Level 1
Type - PredefinedType: CLADDING; Material: REVIGRÉS-OMNISTONE-BASE-60x60-SOFT-PLATINA 9.8 mm
Type - Pset_CoveringCommon - Reference: 3126D392U1; Material: Grés porcelânico
Type - Pset_ElementShading - Roughness: 304.8 mm
Type - Pset_ManufacturerTypeInformation - Manufacturer: REVIGRÉS
Type - Pset_ProductRequirements - Category: Floors
Type - Pset_QuantityTakeOff - Reference: 3126D392U1
Type - IFC.REVIGRÉS-Dados do fabricante-Floor Covering - FabricanteURL: https://www.revigres.pt/; ReferenciaModelo: Omnistone; NumeroGlobalDeItemComercial: 31261392U1; Acabamento: SOFT; Material: Grés porcelânico; IdentificadorDoOperadorEconomico: 501840856; UrlFabricanteArtigo: https://www.revigres.pt/colecoes/omnistone; PaisOrigem: Portugal
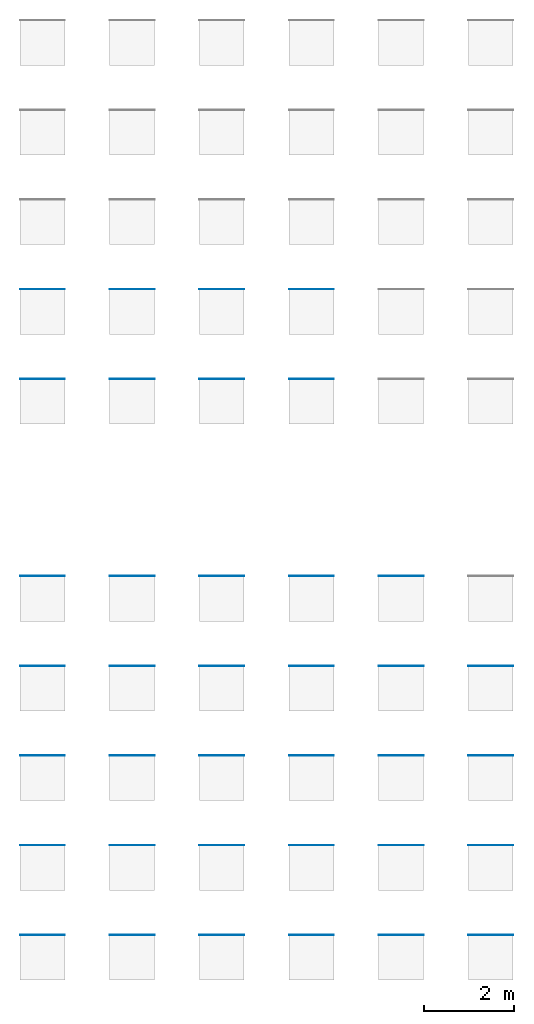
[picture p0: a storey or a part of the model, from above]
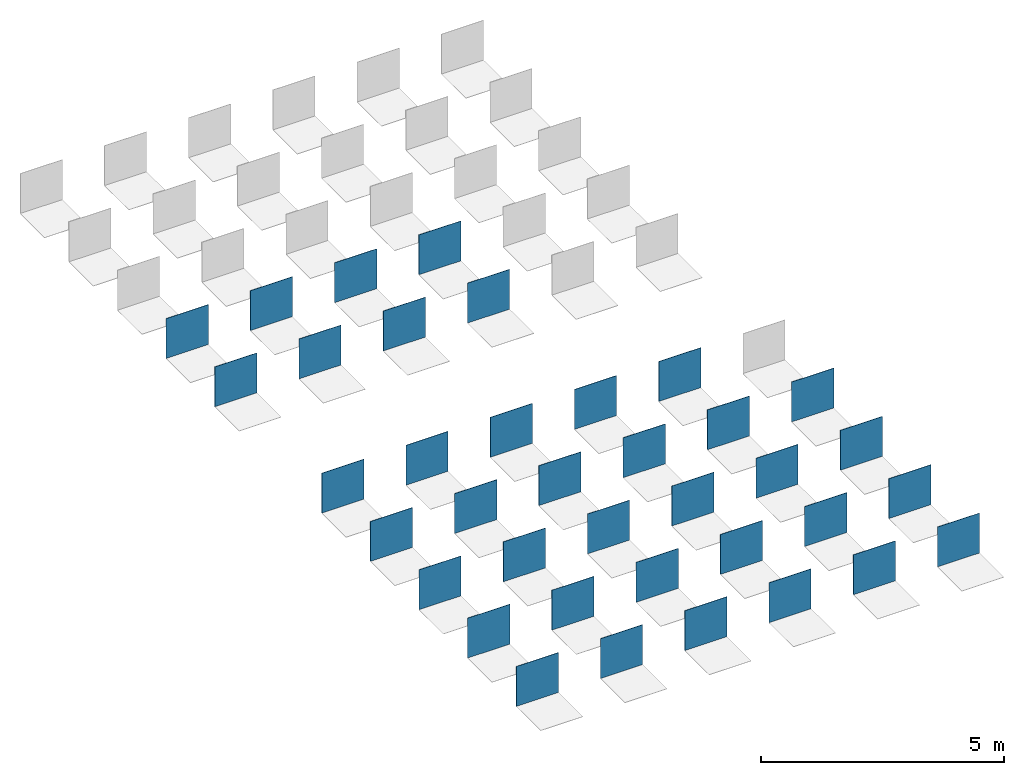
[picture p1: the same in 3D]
Properties of the parts of a building model (IFC2X3), part 4 of 8

# IfcCovering: Floor:REVIGRÉS-OMNISTONE-BASE-60X60-SOFT-PLATINA, Floor:REVIGRÉS-OMNISTONE-BASE-60X60-SOFT-PLATINA:150671
Type - IFC.REVIGRÉS-Dados de desempenho-Floor Covering - Rectilinearidade: ± 0.2% máx.± 0.8 mm; Ortogonalidade: ± 0.2% máx.± 1.5 mm; PlanaridadeDaSuperficie: ± 0.3% máx. ± 1.8 mm; QualidadeDaSuperficie: Cumpre; AbsorcaoDeAgua: < 0.05%; ModuloDeRuptura: > 45 N/mm130; ResistenciaAFlexao: ≥ 3500 N; ResistenciaAAbrasaoProfunda: < 120 mm131; DilatacaoTermicaLinear: ≤ 8,0x10-6 °C-1; ResistenciaAoChoqueTermico: Resiste; DurabilidadeResistenciaAoGeloDegelo: Resiste; ResistenciaAsManchas: Class 5; ResistenciaABaixasConcentracoesDeAcidosEAlcalis: Classe LA; ResistenciaAAltasConcentracoesDeAcidosEAlcalis: Classe HA; LibertacaoDeCadmio: 0; LibertacaoDeChumbo: 0
Type - IFC.REVIGRÉS-Dados de especificação-Floor Covering - VariacaoTonalidade: 3; NivelDeTrafego: 5; EPavimento: Sim; ERevestimento: Sim; EExterno: Sim
Type - IFC.REVIGRÉS-Dados geométricos-Floor Covering - AlturaNominal: 9.8 mm; ComprimentoNominal: 59.2 mm; LarguraNominal: 59.2 mm
Type - IFC.REVIGRÉS-Dados de sustentabilidade-Floor Covering - ItemEParcialmenteReciclado: 0; EnergiaTermicaExportada: 0; ItemENovo: Sim; ItemEReciclado: Não; VidaÚtilEsperada: 50; SubstanciasPerigosas: Não; PotencialDeEsgotamentoAbioticoDosRecursosNaoFosseisMineraisEMetais: 0.000701; PotencialDeAquecimentoGlobalBiogenico: -0.48; CombustiveisFosseisComPotencialDeAquecimentoGlobal: 13.9; PotencialDeAquecimentoGlobalUsoDoSoloEMudancaDeUsoDoSolo: 0.0246; PotencialDeEutrofizacaoFraccaoDeNutrientesQueAtingemOCompartimentoFinalDeAguaDoce: 0.000189; PotencialDeEutrofizacaoFraccaoDeNutrientesQueAtingemOCompartimentoFinalMarinho: 0.0122; EnergiaRecuperada: 0.00739; ConsumoDeAguaDoce: 0.113; UtilizacaoLiquidaDeAguaDoce: 0.113; ResiduosPerigososEliminados: 0.00221; ResiduosNaoPerigososEliminados: 1.83; MassaTotalDeResiduosRadioactivosEliminados: 0.000394; EnergiaElectricaExportada: 1.55; MateriaisParaRecuperacaoDeEnergia: 0.00739; MateriaisParaReciclagem: 0.0253; UnidadeEPD: 1 m²
Type - IFC.REVIGRÉS-Dados gerais-Floor Covering - Nome: REVIGRÉS-OMNISTONE-BASE-60X60-SOFT-PLATINA; TipoProduto: Prensado a seco: grupo BIa UGL | Grés porcelânico técnico; NumeroDeRegistoDAP: EPD-REV-20240006-CCC1-EN; ReferenciaDAP: -; UrlDOP: -
Classification: C3020 (Uniformat)
Pset_CoveringCommon - TotalThickness: 9.8 mm
IFC.REVIGRÉS-Dados do fabricante-Floor Covering - Type: Floor: REVIGRÉS-OMNISTONE-BASE-60X60-SOFT-PLATINA
IFC.REVIGRÉS-Dados de desempenho-Floor Covering - Type: Floor: REVIGRÉS-OMNISTONE-BASE-60X60-SOFT-PLATINA
IFC.REVIGRÉS-Dados de especificação-Floor Covering - Type: Floor: REVIGRÉS-OMNISTONE-BASE-60X60-SOFT-PLATINA
IFC.REVIGRÉS-Dados geométricos-Floor Covering - Type: Floor: REVIGRÉS-OMNISTONE-BASE-60X60-SOFT-PLATINA
IFC.REVIGRÉS-Dados de sustentabilidade-Floor Covering - Type: Floor: REVIGRÉS-OMNISTONE-BASE-60X60-SOFT-PLATINA

# IfcCovering: Floor:REVIGRÉS-OMNISTONE-BASE-60X60-SOFT-ROPE, Floor:REVIGRÉS-OMNISTONE-BASE-60X60-SOFT-ROPE:151376
In: Level 1
Type - PredefinedType: CLADDING; Material: REVIGRÉS-OMNISTONE-BASE-60x60-SOFT-ROPE 9.8 mm
Type - Pset_CoveringCommon - Reference: 3126D393U1; Material: Grés porcelânico
Type - Pset_ElementShading - Roughness: 304.8 mm
Type - Pset_ManufacturerTypeInformation - Manufacturer: REVIGRÉS
Type - Pset_ProductRequirements - Category: Floors
Type - Pset_QuantityTakeOff - Reference: 3126D393U1
Type - IFC.REVIGRÉS-Dados do fabricante-Floor Covering - FabricanteURL: https://www.revigres.pt/; ReferenciaModelo: Omnistone; NumeroGlobalDeItemComercial: 31261393U1; Acabamento: SOFT; Material: Grés porcelânico; IdentificadorDoOperadorEconomico: 501840856; UrlFabricanteArtigo: https://www.revigres.pt/colecoes/omnistone; PaisOrigem: Portugal
Type - IFC.REVIGRÉS-Dados de desempenho-Floor Covering - Rectilinearidade: ± 0.2% máx.± 0.8 mm; Ortogonalidade: ± 0.2% máx.± 1.5 mm; PlanaridadeDaSuperficie: ± 0.3% máx. ± 1.8 mm; QualidadeDaSuperficie: Cumpre; AbsorcaoDeAgua: < 0.05%; ModuloDeRuptura: > 45 N/mm130; ResistenciaAFlexao: ≥ 3500 N; ResistenciaAAbrasaoProfunda: < 120 mm131; DilatacaoTermicaLinear: ≤ 8,0x10-6 °C-1; ResistenciaAoChoqueTermico: Resiste; DurabilidadeResistenciaAoGeloDegelo: Resiste; ResistenciaAsManchas: Class 5; ResistenciaABaixasConcentracoesDeAcidosEAlcalis: Classe LA; ResistenciaAAltasConcentracoesDeAcidosEAlcalis: Classe HA; LibertacaoDeCadmio: 0; LibertacaoDeChumbo: 0
Type - IFC.REVIGRÉS-Dados de especificação-Floor Covering - VariacaoTonalidade: 3; NivelDeTrafego: 5; EPavimento: Sim; ERevestimento: Sim; EExterno: Sim
Type - IFC.REVIGRÉS-Dados geométricos-Floor Covering - AlturaNominal: 9.8 mm; ComprimentoNominal: 59.2 mm; LarguraNominal: 59.2 mm
Type - IFC.REVIGRÉS-Dados de sustentabilidade-Floor Covering - ItemEParcialmenteReciclado: 0; EnergiaTermicaExportada: 0; ItemENovo: Sim; ItemEReciclado: Não; VidaÚtilEsperada: 50; SubstanciasPerigosas: Não; PotencialDeEsgotamentoAbioticoDosRecursosNaoFosseisMineraisEMetais: 0.000701; PotencialDeAquecimentoGlobalBiogenico: -0.48; CombustiveisFosseisComPotencialDeAquecimentoGlobal: 13.9; PotencialDeAquecimentoGlobalUsoDoSoloEMudancaDeUsoDoSolo: 0.0246; PotencialDeEutrofizacaoFraccaoDeNutrientesQueAtingemOCompartimentoFinalDeAguaDoce: 0.000189; PotencialDeEutrofizacaoFraccaoDeNutrientesQueAtingemOCompartimentoFinalMarinho: 0.0122; EnergiaRecuperada: 0.00739; ConsumoDeAguaDoce: 0.113; UtilizacaoLiquidaDeAguaDoce: 0.113; ResiduosPerigososEliminados: 0.00221; ResiduosNaoPerigososEliminados: 1.83; MassaTotalDeResiduosRadioactivosEliminados: 0.000394; EnergiaElectricaExportada: 1.55; MateriaisParaRecuperacaoDeEnergia: 0.00739; MateriaisParaReciclagem: 0.0253; UnidadeEPD: 1 m²
Type - IFC.REVIGRÉS-Dados gerais-Floor Covering - Nome: REVIGRÉS-OMNISTONE-BASE-60X60-SOFT-ROPE; TipoProduto: Prensado a seco: grupo BIa UGL | Grés porcelânico técnico; NumeroDeRegistoDAP: EPD-REV-20240006-CCC1-EN; ReferenciaDAP: -; UrlDOP: -
Classification: C3020 (Uniformat)
Pset_CoveringCommon - TotalThickness: 9.8 mm
IFC.REVIGRÉS-Dados do fabricante-Floor Covering - Type: Floor: REVIGRÉS-OMNISTONE-BASE-60X60-SOFT-ROPE
IFC.REVIGRÉS-Dados de desempenho-Floor Covering - Type: Floor: REVIGRÉS-OMNISTONE-BASE-60X60-SOFT-ROPE
IFC.REVIGRÉS-Dados de especificação-Floor Covering - Type: Floor: REVIGRÉS-OMNISTONE-BASE-60X60-SOFT-ROPE
IFC.REVIGRÉS-Dados geométricos-Floor Covering - Type: Floor: REVIGRÉS-OMNISTONE-BASE-60X60-SOFT-ROPE
IFC.REVIGRÉS-Dados de sustentabilidade-Floor Covering - Type: Floor: REVIGRÉS-OMNISTONE-BASE-60X60-SOFT-ROPE

# IfcCovering: Floor:REVIGRÉS-OMNISTONE-BASE-90X90-MATTRECT-BONE, Floor:REVIGRÉS-OMNISTONE-BASE-90X90-MATTRECT-BONE:146398
In: Level 1
Type - PredefinedType: CLADDING; Material: REVIGRÉS-OMNISTONE-BASE-90x90-MATTRECT-BONE 10.5 mm
Type - Pset_CoveringCommon - Reference: 312BK788U1; Material: Grés porcelânico
Type - Pset_ElementShading - Roughness: 304.8 mm
Type - Pset_ManufacturerTypeInformation - Manufacturer: REVIGRÉS
Type - Pset_ProductRequirements - Category: Floors
Type - Pset_QuantityTakeOff - Reference: 312BK788U1
Type - IFC.REVIGRÉS-Dados do fabricante-Floor Covering - FabricanteURL: https://www.revigres.pt/; ReferenciaModelo: Omnistone; NumeroGlobalDeItemComercial: 312BK788U1; Acabamento: MATT RECT; Material: Grés porcelânico; IdentificadorDoOperadorEconomico: 501840856; UrlFabricanteArtigo: https://www.revigres.pt/colecoes/omnistone; PaisOrigem: Portugal
Type - IFC.REVIGRÉS-Dados de desempenho-Floor Covering - Rectilinearidade: ± 0.2% máx.± 0.8 mm; Ortogonalidade: ± 0.2% máx.± 1.5 mm; PlanaridadeDaSuperficie: ± 0.3% máx. ± 1.8 mm; QualidadeDaSuperficie: Cumpre; AbsorcaoDeAgua: < 0.05%; ModuloDeRuptura: > 45 N/mm130; ResistenciaAFlexao: ≥ 3500 N; ResistenciaAAbrasaoProfunda: < 120 mm131; DilatacaoTermicaLinear: ≤ 8,0x10-6 °C-1; ResistenciaAoChoqueTermico: Resiste; DurabilidadeResistenciaAoGeloDegelo: Resiste; ResistenciaAoEscorregamentoDIN51130: R10; ResistenciaAoEscorregamentoDIN51097: B; ResistenciaAoEscorregamentoENV51097: B; ResistenciaAoEscorregamentoENV12633: Class 2; ResistenciaAoEscorregamentoBS7976: >36; ResistenciaAoEscorregamentoANSIA1371: ≥0,42; ResistenciaAoDeslizamentoENV12633: Class 2; ResistenciaAoDeslizamentoBS7976: >36; ResistenciaAsManchas: Class 5; ResistenciaABaixasConcentracoesDeAcidosEAlcalis: Classe LA; ResistenciaAAltasConcentracoesDeAcidosEAlcalis: Classe HA; LibertacaoDeCadmio: 0; LibertacaoDeChumbo: 0
Type - IFC.REVIGRÉS-Dados de especificação-Floor Covering - VariacaoTonalidade: 3; NivelDeTrafego: 5; EPavimento: Sim; ERevestimento: Sim; EExterno: Sim
Type - IFC.REVIGRÉS-Dados geométricos-Floor Covering - AlturaNominal: 10.5 mm; ComprimentoNominal: 88.9 mm; LarguraNominal: 88.9 mm
Type - IFC.REVIGRÉS-Dados de sustentabilidade-Floor Covering - ItemEParcialmenteReciclado: 0; EnergiaTermicaExportada: 0; ItemENovo: Sim; ItemEReciclado: Não; VidaÚtilEsperada: 50; SubstanciasPerigosas: Não; PotencialDeEsgotamentoAbioticoDosRecursosNaoFosseisMineraisEMetais: 0.000701; PotencialDeAquecimentoGlobalBiogenico: -0.48; CombustiveisFosseisComPotencialDeAquecimentoGlobal: 13.9; PotencialDeAquecimentoGlobalUsoDoSoloEMudancaDeUsoDoSolo: 0.0246; PotencialDeEutrofizacaoFraccaoDeNutrientesQueAtingemOCompartimentoFinalDeAguaDoce: 0.000189; PotencialDeEutrofizacaoFraccaoDeNutrientesQueAtingemOCompartimentoFinalMarinho: 0.0122; EnergiaRecuperada: 0.00739; ConsumoDeAguaDoce: 0.113; UtilizacaoLiquidaDeAguaDoce: 0.113; ResiduosPerigososEliminados: 0.00221; ResiduosNaoPerigososEliminados: 1.83; MassaTotalDeResiduosRadioactivosEliminados: 0.000394; EnergiaElectricaExportada: 1.55; MateriaisParaRecuperacaoDeEnergia: 0.00739; MateriaisParaReciclagem: 0.0253; UnidadeEPD: 1 m²
Type - IFC.REVIGRÉS-Dados gerais-Floor Covering - Nome: REVIGRÉS-OMNISTONE-BASE-90X90-MATT RECT-BONE; TipoProduto: Prensado a seco: grupo BIa UGL | Grés porcelânico técnico; NumeroDeRegistoDAP: EPD-REV-20240006-CCC1-EN; ReferenciaDAP: -; UrlDOP: -
Classification: C3020 (Uniformat)
Pset_CoveringCommon - TotalThickness: 10.5 mm
IFC.REVIGRÉS-Dados do fabricante-Floor Covering - Type: Floor: REVIGRÉS-OMNISTONE-BASE-90X90-MATTRECT-BONE
IFC.REVIGRÉS-Dados de desempenho-Floor Covering - Type: Floor: REVIGRÉS-OMNISTONE-BASE-90X90-MATTRECT-BONE
IFC.REVIGRÉS-Dados de especificação-Floor Covering - Type: Floor: REVIGRÉS-OMNISTONE-BASE-90X90-MATTRECT-BONE
IFC.REVIGRÉS-Dados geométricos-Floor Covering - Type: Floor: REVIGRÉS-OMNISTONE-BASE-90X90-MATTRECT-BONE
IFC.REVIGRÉS-Dados de sustentabilidade-Floor Covering - Type: Floor: REVIGRÉS-OMNISTONE-BASE-90X90-MATTRECT-BONE

# IfcCovering: Floor:REVIGRÉS-OMNISTONE-BASE-90X90-MATTRECT-ICE, Floor:REVIGRÉS-OMNISTONE-BASE-90X90-MATTRECT-ICE:148461
In: Level 1
Type - PredefinedType: CLADDING; Material: REVIGRÉS-OMNISTONE-BASE-90x90-MATTRECT-ICE 10.5 mm
Type - Pset_CoveringCommon - Reference: 312BK789U1; Material: Grés porcelânico
Type - Pset_ElementShading - Roughness: 304.8 mm
Type - Pset_ManufacturerTypeInformation - Manufacturer: REVIGRÉS
Type - Pset_ProductRequirements - Category: Floors
Type - Pset_QuantityTakeOff - Reference: 312BK789U1
Type - IFC.REVIGRÉS-Dados do fabricante-Floor Covering - FabricanteURL: https://www.revigres.pt/; ReferenciaModelo: Omnistone; NumeroGlobalDeItemComercial: 312BK789U1; Acabamento: MATT RECT; Material: Grés porcelânico; IdentificadorDoOperadorEconomico: 501840856; UrlFabricanteArtigo: https://www.revigres.pt/colecoes/omnistone; PaisOrigem: Portugal
Type - IFC.REVIGRÉS-Dados de desempenho-Floor Covering - Rectilinearidade: ± 0.2% máx.± 0.8 mm; Ortogonalidade: ± 0.2% máx.± 1.5 mm; PlanaridadeDaSuperficie: ± 0.3% máx. ± 1.8 mm; QualidadeDaSuperficie: Cumpre; AbsorcaoDeAgua: < 0.05%; ModuloDeRuptura: > 45 N/mm130; ResistenciaAFlexao: ≥ 3500 N; ResistenciaAAbrasaoProfunda: < 120 mm131; DilatacaoTermicaLinear: ≤ 8,0x10-6 °C-1; ResistenciaAoChoqueTermico: Resiste; DurabilidadeResistenciaAoGeloDegelo: Resiste; ResistenciaAoEscorregamentoDIN51130: R10; ResistenciaAoEscorregamentoDIN51097: B; ResistenciaAoEscorregamentoENV51097: B; ResistenciaAoEscorregamentoENV12633: Class 2; ResistenciaAoEscorregamentoBS7976: >36; ResistenciaAoEscorregamentoANSIA1371: ≥0,42; ResistenciaAoDeslizamentoENV12633: Class 2; ResistenciaAoDeslizamentoBS7976: >36; ResistenciaAsManchas: Class 5; ResistenciaABaixasConcentracoesDeAcidosEAlcalis: Classe LA; ResistenciaAAltasConcentracoesDeAcidosEAlcalis: Classe HA; LibertacaoDeCadmio: 0; LibertacaoDeChumbo: 0
Type - IFC.REVIGRÉS-Dados de especificação-Floor Covering - VariacaoTonalidade: 3; NivelDeTrafego: 5; EPavimento: Sim; ERevestimento: Sim; EExterno: Sim
Type - IFC.REVIGRÉS-Dados geométricos-Floor Covering - AlturaNominal: 10.5 mm; ComprimentoNominal: 88.9 mm; LarguraNominal: 88.9 mm
Type - IFC.REVIGRÉS-Dados de sustentabilidade-Floor Covering - ItemEParcialmenteReciclado: 0; EnergiaTermicaExportada: 0; ItemENovo: Sim; ItemEReciclado: Não; VidaÚtilEsperada: 50; SubstanciasPerigosas: Não; PotencialDeEsgotamentoAbioticoDosRecursosNaoFosseisMineraisEMetais: 0.000701; PotencialDeAquecimentoGlobalBiogenico: -0.48; CombustiveisFosseisComPotencialDeAquecimentoGlobal: 13.9; PotencialDeAquecimentoGlobalUsoDoSoloEMudancaDeUsoDoSolo: 0.0246; PotencialDeEutrofizacaoFraccaoDeNutrientesQueAtingemOCompartimentoFinalDeAguaDoce: 0.000189; PotencialDeEutrofizacaoFraccaoDeNutrientesQueAtingemOCompartimentoFinalMarinho: 0.0122; EnergiaRecuperada: 0.00739; ConsumoDeAguaDoce: 0.113; UtilizacaoLiquidaDeAguaDoce: 0.113; ResiduosPerigososEliminados: 0.00221; ResiduosNaoPerigososEliminados: 1.83; MassaTotalDeResiduosRadioactivosEliminados: 0.000394; EnergiaElectricaExportada: 1.55; MateriaisParaRecuperacaoDeEnergia: 0.00739; MateriaisParaReciclagem: 0.0253; UnidadeEPD: 1 m²
Type - IFC.REVIGRÉS-Dados gerais-Floor Covering - Nome: REVIGRÉS-OMNISTONE-BASE-90X90-MATT RECT-ICE; TipoProduto: Prensado a seco: grupo BIa UGL | Grés porcelânico técnico; NumeroDeRegistoDAP: EPD-REV-20240006-CCC1-EN; ReferenciaDAP: -; UrlDOP: -
Classification: C3020 (Uniformat)
Pset_CoveringCommon - TotalThickness: 10.5 mm
IFC.REVIGRÉS-Dados do fabricante-Floor Covering - Type: Floor: REVIGRÉS-OMNISTONE-BASE-90X90-MATTRECT-ICE
IFC.REVIGRÉS-Dados de desempenho-Floor Covering - Type: Floor: REVIGRÉS-OMNISTONE-BASE-90X90-MATTRECT-ICE
IFC.REVIGRÉS-Dados de especificação-Floor Covering - Type: Floor: REVIGRÉS-OMNISTONE-BASE-90X90-MATTRECT-ICE
IFC.REVIGRÉS-Dados geométricos-Floor Covering - Type: Floor: REVIGRÉS-OMNISTONE-BASE-90X90-MATTRECT-ICE
IFC.REVIGRÉS-Dados de sustentabilidade-Floor Covering - Type: Floor: REVIGRÉS-OMNISTONE-BASE-90X90-MATTRECT-ICE

# IfcCovering: Floor:REVIGRÉS-OMNISTONE-BASE-90X90-MATTRECT-IRON, Floor:REVIGRÉS-OMNISTONE-BASE-90X90-MATTRECT-IRON:149152
In: Level 1
Type - PredefinedType: CLADDING; Material: REVIGRÉS-OMNISTONE-BASE-90x90-MATTRECT-IRON 10.5 mm
Type - Pset_CoveringCommon - Reference: 312BK790U1; Material: Grés porcelânico
Type - Pset_ElementShading - Roughness: 304.8 mm
Type - Pset_ManufacturerTypeInformation - Manufacturer: REVIGRÉS
Type - Pset_ProductRequirements - Category: Floors
Type - Pset_QuantityTakeOff - Reference: 312BK790U1
Type - IFC.REVIGRÉS-Dados do fabricante-Floor Covering - FabricanteURL: https://www.revigres.pt/; ReferenciaModelo: Omnistone; NumeroGlobalDeItemComercial: 312BK790U1; Acabamento: MATT RECT; Material: Grés porcelânico; IdentificadorDoOperadorEconomico: 501840856; UrlFabricanteArtigo: https://www.revigres.pt/colecoes/omnistone; PaisOrigem: Portugal
Type - IFC.REVIGRÉS-Dados de desempenho-Floor Covering - Rectilinearidade: ± 0.2% máx.± 0.8 mm; Ortogonalidade: ± 0.2% máx.± 1.5 mm; PlanaridadeDaSuperficie: ± 0.3% máx. ± 1.8 mm; QualidadeDaSuperficie: Cumpre; AbsorcaoDeAgua: < 0.05%; ModuloDeRuptura: > 45 N/mm130; ResistenciaAFlexao: ≥ 3500 N; ResistenciaAAbrasaoProfunda: < 120 mm131; DilatacaoTermicaLinear: ≤ 8,0x10-6 °C-1; ResistenciaAoChoqueTermico: Resiste; DurabilidadeResistenciaAoGeloDegelo: Resiste; ResistenciaAoEscorregamentoDIN51130: R10; ResistenciaAoEscorregamentoDIN51097: B; ResistenciaAoEscorregamentoENV51097: B; ResistenciaAoEscorregamentoENV12633: Class 2; ResistenciaAoEscorregamentoBS7976: >36; ResistenciaAoEscorregamentoANSIA1371: ≥0,42; ResistenciaAoDeslizamentoENV12633: Class 2; ResistenciaAoDeslizamentoBS7976: >36; ResistenciaAsManchas: Class 5; ResistenciaABaixasConcentracoesDeAcidosEAlcalis: Classe LA; ResistenciaAAltasConcentracoesDeAcidosEAlcalis: Classe HA; LibertacaoDeCadmio: 0; LibertacaoDeChumbo: 0
Type - IFC.REVIGRÉS-Dados de especificação-Floor Covering - VariacaoTonalidade: 3; NivelDeTrafego: 5; EPavimento: Sim; ERevestimento: Sim; EExterno: Sim
Type - IFC.REVIGRÉS-Dados geométricos-Floor Covering - AlturaNominal: 10.5 mm; ComprimentoNominal: 88.9 mm; LarguraNominal: 88.9 mm
Type - IFC.REVIGRÉS-Dados de sustentabilidade-Floor Covering - EnergiaTermicaExportada: 0; ItemENovo: Sim; ItemEParcialmenteReciclado: 0.14; ItemEReciclado: Sim; VidaÚtilEsperada: 50; SubstanciasPerigosas: Não; PotencialDeEsgotamentoAbioticoDosRecursosNaoFosseisMineraisEMetais: 0.000701; PotencialDeAquecimentoGlobalBiogenico: -0.48; CombustiveisFosseisComPotencialDeAquecimentoGlobal: 13.9; PotencialDeAquecimentoGlobalUsoDoSoloEMudancaDeUsoDoSolo: 0.0246; PotencialDeEutrofizacaoFraccaoDeNutrientesQueAtingemOCompartimentoFinalDeAguaDoce: 0.000189; PotencialDeEutrofizacaoFraccaoDeNutrientesQueAtingemOCompartimentoFinalMarinho: 0.0122; EnergiaRecuperada: 0.00739; ConsumoDeAguaDoce: 0.113; UtilizacaoLiquidaDeAguaDoce: 0.113; ResiduosPerigososEliminados: 0.00221; ResiduosNaoPerigososEliminados: 1.83; MassaTotalDeResiduosRadioactivosEliminados: 0.000394; EnergiaElectricaExportada: 1.55; MateriaisParaRecuperacaoDeEnergia: 0.00739; MateriaisParaReciclagem: 0.0253; UnidadeEPD: 1 m²
Type - IFC.REVIGRÉS-Dados gerais-Floor Covering - Nome: REVIGRÉS-OMNISTONE-BASE-90X90-MATT RECT-IRON; TipoProduto: Prensado a seco: grupo BIa UGL | Grés porcelânico técnico; NumeroDeRegistoDAP: EPD-REV-20240006-CCC1-EN; ReferenciaDAP: -; UrlDOP: -
Classification: C3020 (Uniformat)
Pset_CoveringCommon - TotalThickness: 10.5 mm
IFC.REVIGRÉS-Dados do fabricante-Floor Covering - Type: Floor: REVIGRÉS-OMNISTONE-BASE-90X90-MATTRECT-IRON
IFC.REVIGRÉS-Dados de desempenho-Floor Covering - Type: Floor: REVIGRÉS-OMNISTONE-BASE-90X90-MATTRECT-IRON
IFC.REVIGRÉS-Dados de especificação-Floor Covering - Type: Floor: REVIGRÉS-OMNISTONE-BASE-90X90-MATTRECT-IRON
IFC.REVIGRÉS-Dados geométricos-Floor Covering - Type: Floor: REVIGRÉS-OMNISTONE-BASE-90X90-MATTRECT-IRON
IFC.REVIGRÉS-Dados de sustentabilidade-Floor Covering - Type: Floor: REVIGRÉS-OMNISTONE-BASE-90X90-MATTRECT-IRON

# IfcCovering: Floor:REVIGRÉS-OMNISTONE-BASE-90X90-MATTRECT-JET, Floor:REVIGRÉS-OMNISTONE-BASE-90X90-MATTRECT-JET:149894
In: Level 1
Type - PredefinedType: CLADDING; Material: REVIGRÉS-OMNISTONE-BASE-90x90-MATTRECT-JET 10.5 mm
Type - Pset_CoveringCommon - Reference: 312BK791U1; Material: Grés porcelânico
Type - Pset_ElementShading - Roughness: 304.8 mm
Type - Pset_ManufacturerTypeInformation - Manufacturer: REVIGRÉS
Type - Pset_ProductRequirements - Category: Floors
Type - Pset_QuantityTakeOff - Reference: 312BK791U1
Type - IFC.REVIGRÉS-Dados do fabricante-Floor Covering - FabricanteURL: https://www.revigres.pt/; ReferenciaModelo: Omnistone; NumeroGlobalDeItemComercial: 312BK791U1; Acabamento: MATT RECT; Material: Grés porcelânico; IdentificadorDoOperadorEconomico: 501840856; UrlFabricanteArtigo: https://www.revigres.pt/colecoes/omnistone; PaisOrigem: Portugal
Type - IFC.REVIGRÉS-Dados de desempenho-Floor Covering - Rectilinearidade: ± 0.2% máx.± 0.8 mm; Ortogonalidade: ± 0.2% máx.± 1.5 mm; PlanaridadeDaSuperficie: ± 0.3% máx. ± 1.8 mm; QualidadeDaSuperficie: Cumpre; AbsorcaoDeAgua: < 0.05%; ModuloDeRuptura: > 45 N/mm130; ResistenciaAFlexao: ≥ 3500 N; ResistenciaAAbrasaoProfunda: < 120 mm131; DilatacaoTermicaLinear: ≤ 8,0x10-6 °C-1; ResistenciaAoChoqueTermico: Resiste; DurabilidadeResistenciaAoGeloDegelo: Resiste; ResistenciaAoEscorregamentoDIN51130: R10; ResistenciaAoEscorregamentoDIN51097: B; ResistenciaAoEscorregamentoENV51097: B; ResistenciaAoEscorregamentoENV12633: Class 2; ResistenciaAoEscorregamentoBS7976: >36; ResistenciaAoEscorregamentoANSIA1371: ≥0,42; ResistenciaAoDeslizamentoENV12633: Class 2; ResistenciaAoDeslizamentoBS7976: >36; ResistenciaAsManchas: Class 5; ResistenciaABaixasConcentracoesDeAcidosEAlcalis: Classe LA; ResistenciaAAltasConcentracoesDeAcidosEAlcalis: Classe HA; LibertacaoDeCadmio: 0; LibertacaoDeChumbo: 0
Type - IFC.REVIGRÉS-Dados de especificação-Floor Covering - VariacaoTonalidade: 3; NivelDeTrafego: 5; EPavimento: Sim; ERevestimento: Sim; EExterno: Sim
Type - IFC.REVIGRÉS-Dados geométricos-Floor Covering - AlturaNominal: 10.5 mm; ComprimentoNominal: 88.9 mm; LarguraNominal: 88.9 mm
Type - IFC.REVIGRÉS-Dados de sustentabilidade-Floor Covering - ItemEParcialmenteReciclado: 0; EnergiaTermicaExportada: 0; ItemENovo: Sim; ItemEReciclado: Não; VidaÚtilEsperada: 50; SubstanciasPerigosas: Não; PotencialDeEsgotamentoAbioticoDosRecursosNaoFosseisMineraisEMetais: 0.000701; PotencialDeAquecimentoGlobalBiogenico: -0.48; CombustiveisFosseisComPotencialDeAquecimentoGlobal: 13.9; PotencialDeAquecimentoGlobalUsoDoSoloEMudancaDeUsoDoSolo: 0.0246; PotencialDeEutrofizacaoFraccaoDeNutrientesQueAtingemOCompartimentoFinalDeAguaDoce: 0.000189; PotencialDeEutrofizacaoFraccaoDeNutrientesQueAtingemOCompartimentoFinalMarinho: 0.0122; EnergiaRecuperada: 0.00739; ConsumoDeAguaDoce: 0.113; UtilizacaoLiquidaDeAguaDoce: 0.113; ResiduosPerigososEliminados: 0.00221; ResiduosNaoPerigososEliminados: 1.83; MassaTotalDeResiduosRadioactivosEliminados: 0.000394; EnergiaElectricaExportada: 1.55; MateriaisParaRecuperacaoDeEnergia: 0.00739; MateriaisParaReciclagem: 0.0253; UnidadeEPD: 1 m²
Type - IFC.REVIGRÉS-Dados gerais-Floor Covering - Nome: REVIGRÉS-OMNISTONE-BASE-90X90-MATT RECT-JET; TipoProduto: Prensado a seco: grupo BIa UGL | Grés porcelânico técnico; NumeroDeRegistoDAP: EPD-REV-20240006-CCC1-EN; ReferenciaDAP: -; UrlDOP: -
Classification: C3020 (Uniformat)
Pset_CoveringCommon - TotalThickness: 10.5 mm
IFC.REVIGRÉS-Dados do fabricante-Floor Covering - Type: Floor: REVIGRÉS-OMNISTONE-BASE-90X90-MATTRECT-JET
IFC.REVIGRÉS-Dados de desempenho-Floor Covering - Type: Floor: REVIGRÉS-OMNISTONE-BASE-90X90-MATTRECT-JET
IFC.REVIGRÉS-Dados de especificação-Floor Covering - Type: Floor: REVIGRÉS-OMNISTONE-BASE-90X90-MATTRECT-JET
IFC.REVIGRÉS-Dados geométricos-Floor Covering - Type: Floor: REVIGRÉS-OMNISTONE-BASE-90X90-MATTRECT-JET
IFC.REVIGRÉS-Dados de sustentabilidade-Floor Covering - Type: Floor: REVIGRÉS-OMNISTONE-BASE-90X90-MATTRECT-JET

# IfcCovering: Floor:REVIGRÉS-OMNISTONE-BASE-90X90-MATTRECT-PLATINA, Floor:REVIGRÉS-OMNISTONE-BASE-90X90-MATTRECT-PLATINA:150615
In: Level 1
Type - PredefinedType: CLADDING; Material: REVIGRÉS-OMNISTONE-BASE-90x90-MATTRECT-PLATINA 10.5 mm
Type - Pset_CoveringCommon - Reference: 312BK792U1; Material: Grés porcelânico
Type - Pset_ElementShading - Roughness: 304.8 mm
Type - Pset_ManufacturerTypeInformation - Manufacturer: REVIGRÉS
Type - Pset_ProductRequirements - Category: Floors
Type - Pset_QuantityTakeOff - Reference: 312BK792U1
Type - IFC.REVIGRÉS-Dados do fabricante-Floor Covering - FabricanteURL: https://www.revigres.pt/; ReferenciaModelo: Omnistone; NumeroGlobalDeItemComercial: 312BK792U1; Acabamento: MATT RECT; Material: Grés porcelânico; IdentificadorDoOperadorEconomico: 501840856; UrlFabricanteArtigo: https://www.revigres.pt/colecoes/omnistone; PaisOrigem: Portugal
Type - IFC.REVIGRÉS-Dados de desempenho-Floor Covering - Rectilinearidade: ± 0.2% máx.± 0.8 mm; Ortogonalidade: ± 0.2% máx.± 1.5 mm; PlanaridadeDaSuperficie: ± 0.3% máx. ± 1.8 mm; QualidadeDaSuperficie: Cumpre; AbsorcaoDeAgua: < 0.05%; ModuloDeRuptura: > 45 N/mm130; ResistenciaAFlexao: ≥ 3500 N; ResistenciaAAbrasaoProfunda: < 120 mm131; DilatacaoTermicaLinear: ≤ 8,0x10-6 °C-1; ResistenciaAoChoqueTermico: Resiste; DurabilidadeResistenciaAoGeloDegelo: Resiste; ResistenciaAoEscorregamentoDIN51130: R10; ResistenciaAoEscorregamentoDIN51097: B; ResistenciaAoEscorregamentoENV51097: B; ResistenciaAoEscorregamentoENV12633: Class 2; ResistenciaAoEscorregamentoBS7976: >36; ResistenciaAoEscorregamentoANSIA1371: ≥0,42; ResistenciaAoDeslizamentoENV12633: Class 2; ResistenciaAoDeslizamentoBS7976: >36; ResistenciaAsManchas: Class 5; ResistenciaABaixasConcentracoesDeAcidosEAlcalis: Classe LA; ResistenciaAAltasConcentracoesDeAcidosEAlcalis: Classe HA; LibertacaoDeCadmio: 0; LibertacaoDeChumbo: 0
Type - IFC.REVIGRÉS-Dados de especificação-Floor Covering - VariacaoTonalidade: 3; NivelDeTrafego: 5; EPavimento: Sim; ERevestimento: Sim; EExterno: Sim
Type - IFC.REVIGRÉS-Dados geométricos-Floor Covering - AlturaNominal: 10.5 mm; ComprimentoNominal: 88.9 mm; LarguraNominal: 88.9 mm
Type - IFC.REVIGRÉS-Dados de sustentabilidade-Floor Covering - ItemEParcialmenteReciclado: 0; EnergiaTermicaExportada: 0; ItemENovo: Sim; ItemEReciclado: Não; VidaÚtilEsperada: 50; SubstanciasPerigosas: Não; PotencialDeEsgotamentoAbioticoDosRecursosNaoFosseisMineraisEMetais: 0.000701; PotencialDeAquecimentoGlobalBiogenico: -0.48; CombustiveisFosseisComPotencialDeAquecimentoGlobal: 13.9; PotencialDeAquecimentoGlobalUsoDoSoloEMudancaDeUsoDoSolo: 0.0246; PotencialDeEutrofizacaoFraccaoDeNutrientesQueAtingemOCompartimentoFinalDeAguaDoce: 0.000189; PotencialDeEutrofizacaoFraccaoDeNutrientesQueAtingemOCompartimentoFinalMarinho: 0.0122; EnergiaRecuperada: 0.00739; ConsumoDeAguaDoce: 0.113; UtilizacaoLiquidaDeAguaDoce: 0.113; ResiduosPerigososEliminados: 0.00221; ResiduosNaoPerigososEliminados: 1.83; MassaTotalDeResiduosRadioactivosEliminados: 0.000394; EnergiaElectricaExportada: 1.55; MateriaisParaRecuperacaoDeEnergia: 0.00739; MateriaisParaReciclagem: 0.0253; UnidadeEPD: 1 m²
Type - IFC.REVIGRÉS-Dados gerais-Floor Covering - Nome: REVIGRÉS-OMNISTONE-BASE-90X90-MATT RECT-PLATINA; TipoProduto: Prensado a seco: grupo BIa UGL | Grés porcelânico técnico; NumeroDeRegistoDAP: EPD-REV-20240006-CCC1-EN; ReferenciaDAP: -; UrlDOP: -
Classification: C3020 (Uniformat)
Pset_CoveringCommon - TotalThickness: 10.5 mm
IFC.REVIGRÉS-Dados do fabricante-Floor Covering - Type: Floor: REVIGRÉS-OMNISTONE-BASE-90X90-MATTRECT-PLATINA
IFC.REVIGRÉS-Dados de desempenho-Floor Covering - Type: Floor: REVIGRÉS-OMNISTONE-BASE-90X90-MATTRECT-PLATINA
IFC.REVIGRÉS-Dados de especificação-Floor Covering - Type: Floor: REVIGRÉS-OMNISTONE-BASE-90X90-MATTRECT-PLATINA
IFC.REVIGRÉS-Dados geométricos-Floor Covering - Type: Floor: REVIGRÉS-OMNISTONE-BASE-90X90-MATTRECT-PLATINA
IFC.REVIGRÉS-Dados de sustentabilidade-Floor Covering - Type: Floor: REVIGRÉS-OMNISTONE-BASE-90X90-MATTRECT-PLATINA

# IfcCovering: Floor:REVIGRÉS-OMNISTONE-BASE-90X90-MATTRECT-ROPE, Floor:REVIGRÉS-OMNISTONE-BASE-90X90-MATTRECT-ROPE:151320
In: Level 1
Type - PredefinedType: CLADDING; Material: REVIGRÉS-OMNISTONE-BASE-90x90-MATTRECT-ROPE 10.5 mm
Type - Pset_CoveringCommon - Reference: 312BK793U1; Material: Grés porcelânico
Type - Pset_ElementShading - Roughness: 304.8 mm
Type - Pset_ManufacturerTypeInformation - Manufacturer: REVIGRÉS
Type - Pset_ProductRequirements - Category: Floors
Type - Pset_QuantityTakeOff - Reference: 312BK793U1
Type - IFC.REVIGRÉS-Dados do fabricante-Floor Covering - FabricanteURL: https://www.revigres.pt/; ReferenciaModelo: Omnistone; NumeroGlobalDeItemComercial: 312BK793U1; Acabamento: MATT RECT; Material: Grés porcelânico; IdentificadorDoOperadorEconomico: 501840856; UrlFabricanteArtigo: https://www.revigres.pt/colecoes/omnistone; PaisOrigem: Portugal
Type - IFC.REVIGRÉS-Dados de desempenho-Floor Covering - Rectilinearidade: ± 0.2% máx.± 0.8 mm; Ortogonalidade: ± 0.2% máx.± 1.5 mm; PlanaridadeDaSuperficie: ± 0.3% máx. ± 1.8 mm; QualidadeDaSuperficie: Cumpre; AbsorcaoDeAgua: < 0.05%; ModuloDeRuptura: > 45 N/mm130; ResistenciaAFlexao: ≥ 3500 N; ResistenciaAAbrasaoProfunda: < 120 mm131; DilatacaoTermicaLinear: ≤ 8,0x10-6 °C-1; ResistenciaAoChoqueTermico: Resiste; DurabilidadeResistenciaAoGeloDegelo: Resiste; ResistenciaAoEscorregamentoDIN51130: R10; ResistenciaAoEscorregamentoDIN51097: B; ResistenciaAoEscorregamentoENV51097: B; ResistenciaAoEscorregamentoENV12633: Class 2; ResistenciaAoEscorregamentoBS7976: >36; ResistenciaAoEscorregamentoANSIA1371: ≥0,42; ResistenciaAoDeslizamentoENV12633: Class 2; ResistenciaAoDeslizamentoBS7976: >36; ResistenciaAsManchas: Class 5; ResistenciaABaixasConcentracoesDeAcidosEAlcalis: Classe LA; ResistenciaAAltasConcentracoesDeAcidosEAlcalis: Classe HA; LibertacaoDeCadmio: 0; LibertacaoDeChumbo: 0
Type - IFC.REVIGRÉS-Dados de especificação-Floor Covering - VariacaoTonalidade: 3; NivelDeTrafego: 5; EPavimento: Sim; ERevestimento: Sim; EExterno: Sim
Type - IFC.REVIGRÉS-Dados geométricos-Floor Covering - AlturaNominal: 10.5 mm; ComprimentoNominal: 88.9 mm; LarguraNominal: 88.9 mm
Type - IFC.REVIGRÉS-Dados de sustentabilidade-Floor Covering - ItemEParcialmenteReciclado: 0; EnergiaTermicaExportada: 0; ItemENovo: Sim; ItemEReciclado: Não; VidaÚtilEsperada: 50; SubstanciasPerigosas: Não; PotencialDeEsgotamentoAbioticoDosRecursosNaoFosseisMineraisEMetais: 0.000701; PotencialDeAquecimentoGlobalBiogenico: -0.48; CombustiveisFosseisComPotencialDeAquecimentoGlobal: 13.9; PotencialDeAquecimentoGlobalUsoDoSoloEMudancaDeUsoDoSolo: 0.0246; PotencialDeEutrofizacaoFraccaoDeNutrientesQueAtingemOCompartimentoFinalDeAguaDoce: 0.000189; PotencialDeEutrofizacaoFraccaoDeNutrientesQueAtingemOCompartimentoFinalMarinho: 0.0122; EnergiaRecuperada: 0.00739; ConsumoDeAguaDoce: 0.113; UtilizacaoLiquidaDeAguaDoce: 0.113; ResiduosPerigososEliminados: 0.00221; ResiduosNaoPerigososEliminados: 1.83; MassaTotalDeResiduosRadioactivosEliminados: 0.000394; EnergiaElectricaExportada: 1.55; MateriaisParaRecuperacaoDeEnergia: 0.00739; MateriaisParaReciclagem: 0.0253; UnidadeEPD: 1 m²
Type - IFC.REVIGRÉS-Dados gerais-Floor Covering - Nome: REVIGRÉS-OMNISTONE-BASE-90X90-MATT RECT-ROPE; TipoProduto: Prensado a seco: grupo BIa UGL | Grés porcelânico técnico; NumeroDeRegistoDAP: EPD-REV-20240006-CCC1-EN; ReferenciaDAP: -; UrlDOP: -
Classification: C3020 (Uniformat)
Pset_CoveringCommon - TotalThickness: 10.5 mm
IFC.REVIGRÉS-Dados do fabricante-Floor Covering - Type: Floor: REVIGRÉS-OMNISTONE-BASE-90X90-MATTRECT-ROPE
IFC.REVIGRÉS-Dados de desempenho-Floor Covering - Type: Floor: REVIGRÉS-OMNISTONE-BASE-90X90-MATTRECT-ROPE
IFC.REVIGRÉS-Dados de especificação-Floor Covering - Type: Floor: REVIGRÉS-OMNISTONE-BASE-90X90-MATTRECT-ROPE
IFC.REVIGRÉS-Dados geométricos-Floor Covering - Type: Floor: REVIGRÉS-OMNISTONE-BASE-90X90-MATTRECT-ROPE
IFC.REVIGRÉS-Dados de sustentabilidade-Floor Covering - Type: Floor: REVIGRÉS-OMNISTONE-BASE-90X90-MATTRECT-ROPE

# IfcCovering: Floor:REVIGRÉS-OMNISTONE-BASE-90X90-SOFT-BONE, Floor:REVIGRÉS-OMNISTONE-BASE-90X90-SOFT-BONE:146538
In: Level 1
Type - PredefinedType: CLADDING; Material: REVIGRÉS-OMNISTONE-BASE-90x90-SOFT-BONE 10.5 mm
Type - Pset_CoveringCommon - Reference: 3126K788U1; Material: Grés porcelânico
Type - Pset_ElementShading - Roughness: 304.8 mm
Type - Pset_ManufacturerTypeInformation - Manufacturer: REVIGRÉS
Type - Pset_ProductRequirements - Category: Floors
Type - Pset_QuantityTakeOff - Reference: 3126K788U1
Type - IFC.REVIGRÉS-Dados do fabricante-Floor Covering - FabricanteURL: https://www.revigres.pt/; ReferenciaModelo: Omnistone; NumeroGlobalDeItemComercial: 3126K788U1; Acabamento: SOFT; Material: Grés porcelânico; IdentificadorDoOperadorEconomico: 501840856; UrlFabricanteArtigo: https://www.revigres.pt/colecoes/omnistone; PaisOrigem: Portugal
Type - IFC.REVIGRÉS-Dados de desempenho-Floor Covering - Rectilinearidade: ± 0.2% máx.± 0.8 mm; Ortogonalidade: ± 0.2% máx.± 1.5 mm; PlanaridadeDaSuperficie: ± 0.3% máx. ± 1.8 mm; QualidadeDaSuperficie: Cumpre; AbsorcaoDeAgua: < 0.05%; ModuloDeRuptura: > 45 N/mm130; ResistenciaAFlexao: ≥ 3500 N; ResistenciaAAbrasaoProfunda: < 120 mm131; DilatacaoTermicaLinear: ≤ 8,0x10-6 °C-1; ResistenciaAoChoqueTermico: Resiste; DurabilidadeResistenciaAoGeloDegelo: Resiste; ResistenciaAsManchas: Class 5; ResistenciaABaixasConcentracoesDeAcidosEAlcalis: Classe LA; ResistenciaAAltasConcentracoesDeAcidosEAlcalis: Classe HA; LibertacaoDeCadmio: 0; LibertacaoDeChumbo: 0
Type - IFC.REVIGRÉS-Dados de especificação-Floor Covering - VariacaoTonalidade: 3; NivelDeTrafego: 5; EPavimento: Sim; ERevestimento: Sim; EExterno: Sim
Type - IFC.REVIGRÉS-Dados geométricos-Floor Covering - AlturaNominal: 10.5 mm; ComprimentoNominal: 88.9 mm; LarguraNominal: 88.9 mm
Type - IFC.REVIGRÉS-Dados de sustentabilidade-Floor Covering - ItemEParcialmenteReciclado: 0; EnergiaTermicaExportada: 0; ItemENovo: Sim; ItemEReciclado: Não; VidaÚtilEsperada: 50; SubstanciasPerigosas: Não; PotencialDeEsgotamentoAbioticoDosRecursosNaoFosseisMineraisEMetais: 0.000701; PotencialDeAquecimentoGlobalBiogenico: -0.48; CombustiveisFosseisComPotencialDeAquecimentoGlobal: 13.9; PotencialDeAquecimentoGlobalUsoDoSoloEMudancaDeUsoDoSolo: 0.0246; PotencialDeEutrofizacaoFraccaoDeNutrientesQueAtingemOCompartimentoFinalDeAguaDoce: 0.000189; PotencialDeEutrofizacaoFraccaoDeNutrientesQueAtingemOCompartimentoFinalMarinho: 0.0122; EnergiaRecuperada: 0.00739; ConsumoDeAguaDoce: 0.113; UtilizacaoLiquidaDeAguaDoce: 0.113; ResiduosPerigososEliminados: 0.00221; ResiduosNaoPerigososEliminados: 1.83; MassaTotalDeResiduosRadioactivosEliminados: 0.000394; EnergiaElectricaExportada: 1.55; MateriaisParaRecuperacaoDeEnergia: 0.00739; MateriaisParaReciclagem: 0.0253; UnidadeEPD: 1 m²
Type - IFC.REVIGRÉS-Dados gerais-Floor Covering - Nome: REVIGRÉS-OMNISTONE-BASE-90X90-SOFT-BONE; TipoProduto: Prensado a seco: grupo BIa UGL | Grés porcelânico técnico; NumeroDeRegistoDAP: EPD-REV-20240006-CCC1-EN; ReferenciaDAP: -; UrlDOP: -
Classification: C3020 (Uniformat)
Pset_CoveringCommon - TotalThickness: 10.5 mm
IFC.REVIGRÉS-Dados do fabricante-Floor Covering - Type: Floor: REVIGRÉS-OMNISTONE-BASE-90X90-SOFT-BONE
IFC.REVIGRÉS-Dados de desempenho-Floor Covering - Type: Floor: REVIGRÉS-OMNISTONE-BASE-90X90-SOFT-BONE
IFC.REVIGRÉS-Dados de especificação-Floor Covering - Type: Floor: REVIGRÉS-OMNISTONE-BASE-90X90-SOFT-BONE
IFC.REVIGRÉS-Dados geométricos-Floor Covering - Type: Floor: REVIGRÉS-OMNISTONE-BASE-90X90-SOFT-BONE
IFC.REVIGRÉS-Dados de sustentabilidade-Floor Covering - Type: Floor: REVIGRÉS-OMNISTONE-BASE-90X90-SOFT-BONE

# IfcCovering: Floor:REVIGRÉS-OMNISTONE-BASE-90X90-SOFT-ICE, Floor:REVIGRÉS-OMNISTONE-BASE-90X90-SOFT-ICE:148547
In: Level 1
Type - PredefinedType: CLADDING; Material: REVIGRÉS-OMNISTONE-BASE-90x90-SOFT-ICE 10.5 mm
Type - Pset_CoveringCommon - Reference: 3126K789U1; Material: Grés porcelânico
Type - Pset_ElementShading - Roughness: 304.8 mm
Type - Pset_ManufacturerTypeInformation - Manufacturer: REVIGRÉS
Type - Pset_ProductRequirements - Category: Floors
Type - Pset_QuantityTakeOff - Reference: 3126K789U1
Type - IFC.REVIGRÉS-Dados do fabricante-Floor Covering - FabricanteURL: https://www.revigres.pt/; ReferenciaModelo: Omnistone; NumeroGlobalDeItemComercial: 3126K789U1; Acabamento: SOFT; Material: Grés porcelânico; IdentificadorDoOperadorEconomico: 501840856; UrlFabricanteArtigo: https://www.revigres.pt/colecoes/omnistone; PaisOrigem: Portugal
Type - IFC.REVIGRÉS-Dados de desempenho-Floor Covering - Rectilinearidade: ± 0.2% máx.± 0.8 mm; Ortogonalidade: ± 0.2% máx.± 1.5 mm; PlanaridadeDaSuperficie: ± 0.3% máx. ± 1.8 mm; QualidadeDaSuperficie: Cumpre; AbsorcaoDeAgua: < 0.05%; ModuloDeRuptura: > 45 N/mm130; ResistenciaAFlexao: ≥ 3500 N; ResistenciaAAbrasaoProfunda: < 120 mm131; DilatacaoTermicaLinear: ≤ 8,0x10-6 °C-1; ResistenciaAoChoqueTermico: Resiste; DurabilidadeResistenciaAoGeloDegelo: Resiste; ResistenciaAsManchas: Class 5; ResistenciaABaixasConcentracoesDeAcidosEAlcalis: Classe LA; ResistenciaAAltasConcentracoesDeAcidosEAlcalis: Classe HA; LibertacaoDeCadmio: 0; LibertacaoDeChumbo: 0
Type - IFC.REVIGRÉS-Dados de especificação-Floor Covering - VariacaoTonalidade: 3; NivelDeTrafego: 5; EPavimento: Sim; ERevestimento: Sim; EExterno: Sim
Type - IFC.REVIGRÉS-Dados geométricos-Floor Covering - AlturaNominal: 10.5 mm; ComprimentoNominal: 88.9 mm; LarguraNominal: 88.9 mm
Type - IFC.REVIGRÉS-Dados de sustentabilidade-Floor Covering - ItemEParcialmenteReciclado: 0; EnergiaTermicaExportada: 0; ItemENovo: Sim; ItemEReciclado: Não; VidaÚtilEsperada: 50; SubstanciasPerigosas: Não; PotencialDeEsgotamentoAbioticoDosRecursosNaoFosseisMineraisEMetais: 0.000701; PotencialDeAquecimentoGlobalBiogenico: -0.48; CombustiveisFosseisComPotencialDeAquecimentoGlobal: 13.9; PotencialDeAquecimentoGlobalUsoDoSoloEMudancaDeUsoDoSolo: 0.0246; PotencialDeEutrofizacaoFraccaoDeNutrientesQueAtingemOCompartimentoFinalDeAguaDoce: 0.000189; PotencialDeEutrofizacaoFraccaoDeNutrientesQueAtingemOCompartimentoFinalMarinho: 0.0122; EnergiaRecuperada: 0.00739; ConsumoDeAguaDoce: 0.113; UtilizacaoLiquidaDeAguaDoce: 0.113; ResiduosPerigososEliminados: 0.00221; ResiduosNaoPerigososEliminados: 1.83; MassaTotalDeResiduosRadioactivosEliminados: 0.000394; EnergiaElectricaExportada: 1.55; MateriaisParaRecuperacaoDeEnergia: 0.00739; MateriaisParaReciclagem: 0.0253; UnidadeEPD: 1 m²
Type - IFC.REVIGRÉS-Dados gerais-Floor Covering - Nome: REVIGRÉS-OMNISTONE-BASE-90X90-SOFT-ICE; TipoProduto: Prensado a seco: grupo BIa UGL | Grés porcelânico técnico; NumeroDeRegistoDAP: EPD-REV-20240006-CCC1-EN; ReferenciaDAP: -; UrlDOP: -
Classification: C3020 (Uniformat)
Pset_CoveringCommon - TotalThickness: 10.5 mm
IFC.REVIGRÉS-Dados do fabricante-Floor Covering - Type: Floor: REVIGRÉS-OMNISTONE-BASE-90X90-SOFT-ICE
IFC.REVIGRÉS-Dados de desempenho-Floor Covering - Type: Floor: REVIGRÉS-OMNISTONE-BASE-90X90-SOFT-ICE
IFC.REVIGRÉS-Dados de especificação-Floor Covering - Type: Floor: REVIGRÉS-OMNISTONE-BASE-90X90-SOFT-ICE
IFC.REVIGRÉS-Dados geométricos-Floor Covering - Type: Floor: REVIGRÉS-OMNISTONE-BASE-90X90-SOFT-ICE
IFC.REVIGRÉS-Dados de sustentabilidade-Floor Covering - Type: Floor: REVIGRÉS-OMNISTONE-BASE-90X90-SOFT-ICE

# IfcCovering: Floor:REVIGRÉS-OMNISTONE-BASE-90X90-SOFT-IRON, Floor:REVIGRÉS-OMNISTONE-BASE-90X90-SOFT-IRON:149232
In: Level 1
Type - PredefinedType: CLADDING; Material: REVIGRÉS-OMNISTONE-BASE-90x90-SOFT-IRON 10.5 mm
Type - Pset_CoveringCommon - Reference: 3126K790U1; Material: Grés porcelânico
Type - Pset_ElementShading - Roughness: 304.8 mm
Type - Pset_ManufacturerTypeInformation - Manufacturer: REVIGRÉS
Type - Pset_ProductRequirements - Category: Floors
Type - Pset_QuantityTakeOff - Reference: 3126K790U1
Type - IFC.REVIGRÉS-Dados do fabricante-Floor Covering - FabricanteURL: https://www.revigres.pt/; ReferenciaModelo: Omnistone; NumeroGlobalDeItemComercial: 3126K790U1; Acabamento: SOFT; Material: Grés porcelânico; IdentificadorDoOperadorEconomico: 501840856; UrlFabricanteArtigo: https://www.revigres.pt/colecoes/omnistone; PaisOrigem: Portugal
Type - IFC.REVIGRÉS-Dados de desempenho-Floor Covering - Rectilinearidade: ± 0.2% máx.± 0.8 mm; Ortogonalidade: ± 0.2% máx.± 1.5 mm; PlanaridadeDaSuperficie: ± 0.3% máx. ± 1.8 mm; QualidadeDaSuperficie: Cumpre; AbsorcaoDeAgua: < 0.05%; ModuloDeRuptura: > 45 N/mm130; ResistenciaAFlexao: ≥ 3500 N; ResistenciaAAbrasaoProfunda: < 120 mm131; DilatacaoTermicaLinear: ≤ 8,0x10-6 °C-1; ResistenciaAoChoqueTermico: Resiste; DurabilidadeResistenciaAoGeloDegelo: Resiste; ResistenciaAsManchas: Class 5; ResistenciaABaixasConcentracoesDeAcidosEAlcalis: Classe LA; ResistenciaAAltasConcentracoesDeAcidosEAlcalis: Classe HA; LibertacaoDeCadmio: 0; LibertacaoDeChumbo: 0
Type - IFC.REVIGRÉS-Dados de especificação-Floor Covering - VariacaoTonalidade: 3; NivelDeTrafego: 5; EPavimento: Sim; ERevestimento: Sim; EExterno: Sim
Type - IFC.REVIGRÉS-Dados geométricos-Floor Covering - AlturaNominal: 10.5 mm; ComprimentoNominal: 88.9 mm; LarguraNominal: 88.9 mm
Type - IFC.REVIGRÉS-Dados de sustentabilidade-Floor Covering - EnergiaTermicaExportada: 0; ItemENovo: Sim; ItemEParcialmenteReciclado: 0.14; ItemEReciclado: Sim; VidaÚtilEsperada: 50; SubstanciasPerigosas: Não; PotencialDeEsgotamentoAbioticoDosRecursosNaoFosseisMineraisEMetais: 0.000701; PotencialDeAquecimentoGlobalBiogenico: -0.48; CombustiveisFosseisComPotencialDeAquecimentoGlobal: 13.9; PotencialDeAquecimentoGlobalUsoDoSoloEMudancaDeUsoDoSolo: 0.0246; PotencialDeEutrofizacaoFraccaoDeNutrientesQueAtingemOCompartimentoFinalDeAguaDoce: 0.000189; PotencialDeEutrofizacaoFraccaoDeNutrientesQueAtingemOCompartimentoFinalMarinho: 0.0122; EnergiaRecuperada: 0.00739; ConsumoDeAguaDoce: 0.113; UtilizacaoLiquidaDeAguaDoce: 0.113; ResiduosPerigososEliminados: 0.00221; ResiduosNaoPerigososEliminados: 1.83; MassaTotalDeResiduosRadioactivosEliminados: 0.000394; EnergiaElectricaExportada: 1.55; MateriaisParaRecuperacaoDeEnergia: 0.00739; MateriaisParaReciclagem: 0.0253; UnidadeEPD: 1 m²
Type - IFC.REVIGRÉS-Dados gerais-Floor Covering - Nome: REVIGRÉS-OMNISTONE-BASE-90X90-SOFT-IRON; TipoProduto: Prensado a seco: grupo BIa UGL | Grés porcelânico técnico; NumeroDeRegistoDAP: EPD-REV-20240006-CCC1-EN; ReferenciaDAP: -; UrlDOP: -
Classification: C3020 (Uniformat)
Pset_CoveringCommon - TotalThickness: 10.5 mm
IFC.REVIGRÉS-Dados do fabricante-Floor Covering - Type: Floor: REVIGRÉS-OMNISTONE-BASE-90X90-SOFT-IRON
IFC.REVIGRÉS-Dados de desempenho-Floor Covering - Type: Floor: REVIGRÉS-OMNISTONE-BASE-90X90-SOFT-IRON
IFC.REVIGRÉS-Dados de especificação-Floor Covering - Type: Floor: REVIGRÉS-OMNISTONE-BASE-90X90-SOFT-IRON
IFC.REVIGRÉS-Dados geométricos-Floor Covering - Type: Floor: REVIGRÉS-OMNISTONE-BASE-90X90-SOFT-IRON
IFC.REVIGRÉS-Dados de sustentabilidade-Floor Covering - Type: Floor: REVIGRÉS-OMNISTONE-BASE-90X90-SOFT-IRON

# IfcCovering: Floor:REVIGRÉS-OMNISTONE-BASE-90X90-SOFT-JET, Floor:REVIGRÉS-OMNISTONE-BASE-90X90-SOFT-JET:149974
In: Level 1
Type - PredefinedType: CLADDING; Material: REVIGRÉS-OMNISTONE-BASE-90x90-SOFT-JET 10.5 mm
Type - Pset_CoveringCommon - Reference: 3126K791U1; Material: Grés porcelânico
Type - Pset_ElementShading - Roughness: 304.8 mm
Type - Pset_ManufacturerTypeInformation - Manufacturer: REVIGRÉS
Type - Pset_ProductRequirements - Category: Floors
Type - Pset_QuantityTakeOff - Reference: 3126K791U1
Type - IFC.REVIGRÉS-Dados do fabricante-Floor Covering - FabricanteURL: https://www.revigres.pt/; ReferenciaModelo: Omnistone; NumeroGlobalDeItemComercial: 3126K791U1; Acabamento: SOFT; Material: Grés porcelânico; IdentificadorDoOperadorEconomico: 501840856; UrlFabricanteArtigo: https://www.revigres.pt/colecoes/omnistone; PaisOrigem: Portugal
Type - IFC.REVIGRÉS-Dados de desempenho-Floor Covering - Rectilinearidade: ± 0.2% máx.± 0.8 mm; Ortogonalidade: ± 0.2% máx.± 1.5 mm; PlanaridadeDaSuperficie: ± 0.3% máx. ± 1.8 mm; QualidadeDaSuperficie: Cumpre; AbsorcaoDeAgua: < 0.05%; ModuloDeRuptura: > 45 N/mm130; ResistenciaAFlexao: ≥ 3500 N; ResistenciaAAbrasaoProfunda: < 120 mm131; DilatacaoTermicaLinear: ≤ 8,0x10-6 °C-1; ResistenciaAoChoqueTermico: Resiste; DurabilidadeResistenciaAoGeloDegelo: Resiste; ResistenciaAsManchas: Class 5; ResistenciaABaixasConcentracoesDeAcidosEAlcalis: Classe LA; ResistenciaAAltasConcentracoesDeAcidosEAlcalis: Classe HA; LibertacaoDeCadmio: 0; LibertacaoDeChumbo: 0
Type - IFC.REVIGRÉS-Dados de especificação-Floor Covering - VariacaoTonalidade: 3; NivelDeTrafego: 5; EPavimento: Sim; ERevestimento: Sim; EExterno: Sim
Type - IFC.REVIGRÉS-Dados geométricos-Floor Covering - AlturaNominal: 10.5 mm; ComprimentoNominal: 88.9 mm; LarguraNominal: 88.9 mm
Type - IFC.REVIGRÉS-Dados de sustentabilidade-Floor Covering - ItemEParcialmenteReciclado: 0; EnergiaTermicaExportada: 0; ItemENovo: Sim; ItemEReciclado: Não; VidaÚtilEsperada: 50; SubstanciasPerigosas: Não; PotencialDeEsgotamentoAbioticoDosRecursosNaoFosseisMineraisEMetais: 0.000701; PotencialDeAquecimentoGlobalBiogenico: -0.48; CombustiveisFosseisComPotencialDeAquecimentoGlobal: 13.9; PotencialDeAquecimentoGlobalUsoDoSoloEMudancaDeUsoDoSolo: 0.0246; PotencialDeEutrofizacaoFraccaoDeNutrientesQueAtingemOCompartimentoFinalDeAguaDoce: 0.000189; PotencialDeEutrofizacaoFraccaoDeNutrientesQueAtingemOCompartimentoFinalMarinho: 0.0122; EnergiaRecuperada: 0.00739; ConsumoDeAguaDoce: 0.113; UtilizacaoLiquidaDeAguaDoce: 0.113; ResiduosPerigososEliminados: 0.00221; ResiduosNaoPerigososEliminados: 1.83; MassaTotalDeResiduosRadioactivosEliminados: 0.000394; EnergiaElectricaExportada: 1.55; MateriaisParaRecuperacaoDeEnergia: 0.00739; MateriaisParaReciclagem: 0.0253; UnidadeEPD: 1 m²
Type - IFC.REVIGRÉS-Dados gerais-Floor Covering - Nome: REVIGRÉS-OMNISTONE-BASE-90X90-SOFT-JET; TipoProduto: Prensado a seco: grupo BIa UGL | Grés porcelânico técnico; NumeroDeRegistoDAP: EPD-REV-20240006-CCC1-EN; ReferenciaDAP: -; UrlDOP: -
Classification: C3020 (Uniformat)
Pset_CoveringCommon - TotalThickness: 10.5 mm
IFC.REVIGRÉS-Dados do fabricante-Floor Covering - Type: Floor: REVIGRÉS-OMNISTONE-BASE-90X90-SOFT-JET
IFC.REVIGRÉS-Dados de desempenho-Floor Covering - Type: Floor: REVIGRÉS-OMNISTONE-BASE-90X90-SOFT-JET
IFC.REVIGRÉS-Dados de especificação-Floor Covering - Type: Floor: REVIGRÉS-OMNISTONE-BASE-90X90-SOFT-JET
IFC.REVIGRÉS-Dados geométricos-Floor Covering - Type: Floor: REVIGRÉS-OMNISTONE-BASE-90X90-SOFT-JET
IFC.REVIGRÉS-Dados de sustentabilidade-Floor Covering - Type: Floor: REVIGRÉS-OMNISTONE-BASE-90X90-SOFT-JET

# IfcCovering: Floor:REVIGRÉS-OMNISTONE-BASE-90X90-SOFT-PLATINA, Floor:REVIGRÉS-OMNISTONE-BASE-90X90-SOFT-PLATINA:150695
In: Level 1
Type - PredefinedType: CLADDING; Material: REVIGRÉS-OMNISTONE-BASE-90x90-SOFT-PLATINA 10.5 mm
Type - Pset_CoveringCommon - Reference: 3126K792U1; Material: Grés porcelânico
Type - Pset_ElementShading - Roughness: 304.8 mm
Type - Pset_ManufacturerTypeInformation - Manufacturer: REVIGRÉS
Type - Pset_ProductRequirements - Category: Floors
Type - Pset_QuantityTakeOff - Reference: 3126K792U1
Type - IFC.REVIGRÉS-Dados do fabricante-Floor Covering - FabricanteURL: https://www.revigres.pt/; ReferenciaModelo: Omnistone; NumeroGlobalDeItemComercial: 3126K792U1; Acabamento: SOFT; Material: Grés porcelânico; IdentificadorDoOperadorEconomico: 501840856; UrlFabricanteArtigo: https://www.revigres.pt/colecoes/omnistone; PaisOrigem: Portugal
Type - IFC.REVIGRÉS-Dados de desempenho-Floor Covering - Rectilinearidade: ± 0.2% máx.± 0.8 mm; Ortogonalidade: ± 0.2% máx.± 1.5 mm; PlanaridadeDaSuperficie: ± 0.3% máx. ± 1.8 mm; QualidadeDaSuperficie: Cumpre; AbsorcaoDeAgua: < 0.05%; ModuloDeRuptura: > 45 N/mm130; ResistenciaAFlexao: ≥ 3500 N; ResistenciaAAbrasaoProfunda: < 120 mm131; DilatacaoTermicaLinear: ≤ 8,0x10-6 °C-1; ResistenciaAoChoqueTermico: Resiste; DurabilidadeResistenciaAoGeloDegelo: Resiste; ResistenciaAsManchas: Class 5; ResistenciaABaixasConcentracoesDeAcidosEAlcalis: Classe LA; ResistenciaAAltasConcentracoesDeAcidosEAlcalis: Classe HA; LibertacaoDeCadmio: 0; LibertacaoDeChumbo: 0
Type - IFC.REVIGRÉS-Dados de especificação-Floor Covering - VariacaoTonalidade: 3; NivelDeTrafego: 5; EPavimento: Sim; ERevestimento: Sim; EExterno: Sim
Type - IFC.REVIGRÉS-Dados geométricos-Floor Covering - AlturaNominal: 10.5 mm; ComprimentoNominal: 88.9 mm; LarguraNominal: 88.9 mm
Type - IFC.REVIGRÉS-Dados de sustentabilidade-Floor Covering - ItemEParcialmenteReciclado: 0; EnergiaTermicaExportada: 0; ItemENovo: Sim; ItemEReciclado: Não; VidaÚtilEsperada: 50; SubstanciasPerigosas: Não; PotencialDeEsgotamentoAbioticoDosRecursosNaoFosseisMineraisEMetais: 0.000701; PotencialDeAquecimentoGlobalBiogenico: -0.48; CombustiveisFosseisComPotencialDeAquecimentoGlobal: 13.9; PotencialDeAquecimentoGlobalUsoDoSoloEMudancaDeUsoDoSolo: 0.0246; PotencialDeEutrofizacaoFraccaoDeNutrientesQueAtingemOCompartimentoFinalDeAguaDoce: 0.000189; PotencialDeEutrofizacaoFraccaoDeNutrientesQueAtingemOCompartimentoFinalMarinho: 0.0122; EnergiaRecuperada: 0.00739; ConsumoDeAguaDoce: 0.113; UtilizacaoLiquidaDeAguaDoce: 0.113; ResiduosPerigososEliminados: 0.00221; ResiduosNaoPerigososEliminados: 1.83; MassaTotalDeResiduosRadioactivosEliminados: 0.000394; EnergiaElectricaExportada: 1.55; MateriaisParaRecuperacaoDeEnergia: 0.00739; MateriaisParaReciclagem: 0.0253; UnidadeEPD: 1 m²
Type - IFC.REVIGRÉS-Dados gerais-Floor Covering - Nome: REVIGRÉS-OMNISTONE-BASE-90X90-SOFT-PLATINA; TipoProduto: Prensado a seco: grupo BIa UGL | Grés porcelânico técnico; NumeroDeRegistoDAP: EPD-REV-20240006-CCC1-EN; ReferenciaDAP: -; UrlDOP: -
Classification: C3020 (Uniformat)
Pset_CoveringCommon - TotalThickness: 10.5 mm
IFC.REVIGRÉS-Dados do fabricante-Floor Covering - Type: Floor: REVIGRÉS-OMNISTONE-BASE-90X90-SOFT-PLATINA
IFC.REVIGRÉS-Dados de desempenho-Floor Covering - Type: Floor: REVIGRÉS-OMNISTONE-BASE-90X90-SOFT-PLATINA
IFC.REVIGRÉS-Dados de especificação-Floor Covering - Type: Floor: REVIGRÉS-OMNISTONE-BASE-90X90-SOFT-PLATINA
IFC.REVIGRÉS-Dados geométricos-Floor Covering - Type: Floor: REVIGRÉS-OMNISTONE-BASE-90X90-SOFT-PLATINA
IFC.REVIGRÉS-Dados de sustentabilidade-Floor Covering - Type: Floor: REVIGRÉS-OMNISTONE-BASE-90X90-SOFT-PLATINA

# IfcCovering: Floor:REVIGRÉS-OMNISTONE-BASE-90X90-SOFT-ROPE, Floor:REVIGRÉS-OMNISTONE-BASE-90X90-SOFT-ROPE:151400
In: Level 1
Type - PredefinedType: CLADDING; Material: REVIGRÉS-OMNISTONE-BASE-90x90-SOFT-ROPE 10.5 mm
Type - Pset_CoveringCommon - Reference: 3126K793U1; Material: Grés porcelânico
Type - Pset_ElementShading - Roughness: 304.8 mm
Type - Pset_ManufacturerTypeInformation - Manufacturer: REVIGRÉS
Type - Pset_ProductRequirements - Category: Floors
Type - Pset_QuantityTakeOff - Reference: 3126K793U1
Type - IFC.REVIGRÉS-Dados do fabricante-Floor Covering - FabricanteURL: https://www.revigres.pt/; ReferenciaModelo: Omnistone; NumeroGlobalDeItemComercial: 3126K793U1; Acabamento: SOFT; Material: Grés porcelânico; IdentificadorDoOperadorEconomico: 501840856; UrlFabricanteArtigo: https://www.revigres.pt/colecoes/omnistone; PaisOrigem: Portugal
Type - IFC.REVIGRÉS-Dados de desempenho-Floor Covering - Rectilinearidade: ± 0.2% máx.± 0.8 mm; Ortogonalidade: ± 0.2% máx.± 1.5 mm; PlanaridadeDaSuperficie: ± 0.3% máx. ± 1.8 mm; QualidadeDaSuperficie: Cumpre; AbsorcaoDeAgua: < 0.05%; ModuloDeRuptura: > 45 N/mm130; ResistenciaAFlexao: ≥ 3500 N; ResistenciaAAbrasaoProfunda: < 120 mm131; DilatacaoTermicaLinear: ≤ 8,0x10-6 °C-1; ResistenciaAoChoqueTermico: Resiste; DurabilidadeResistenciaAoGeloDegelo: Resiste; ResistenciaAsManchas: Class 5; ResistenciaABaixasConcentracoesDeAcidosEAlcalis: Classe LA; ResistenciaAAltasConcentracoesDeAcidosEAlcalis: Classe HA; LibertacaoDeCadmio: 0; LibertacaoDeChumbo: 0
Type - IFC.REVIGRÉS-Dados de especificação-Floor Covering - VariacaoTonalidade: 3; NivelDeTrafego: 5; EPavimento: Sim; ERevestimento: Sim; EExterno: Sim
Type - IFC.REVIGRÉS-Dados geométricos-Floor Covering - AlturaNominal: 10.5 mm; ComprimentoNominal: 88.9 mm; LarguraNominal: 88.9 mm
Type - IFC.REVIGRÉS-Dados de sustentabilidade-Floor Covering - ItemEParcialmenteReciclado: 0; EnergiaTermicaExportada: 0; ItemENovo: Sim; ItemEReciclado: Não; VidaÚtilEsperada: 50; SubstanciasPerigosas: Não; PotencialDeEsgotamentoAbioticoDosRecursosNaoFosseisMineraisEMetais: 0.000701; PotencialDeAquecimentoGlobalBiogenico: -0.48; CombustiveisFosseisComPotencialDeAquecimentoGlobal: 13.9; PotencialDeAquecimentoGlobalUsoDoSoloEMudancaDeUsoDoSolo: 0.0246; PotencialDeEutrofizacaoFraccaoDeNutrientesQueAtingemOCompartimentoFinalDeAguaDoce: 0.000189; PotencialDeEutrofizacaoFraccaoDeNutrientesQueAtingemOCompartimentoFinalMarinho: 0.0122; EnergiaRecuperada: 0.00739; ConsumoDeAguaDoce: 0.113; UtilizacaoLiquidaDeAguaDoce: 0.113; ResiduosPerigososEliminados: 0.00221; ResiduosNaoPerigososEliminados: 1.83; MassaTotalDeResiduosRadioactivosEliminados: 0.000394; EnergiaElectricaExportada: 1.55; MateriaisParaRecuperacaoDeEnergia: 0.00739; MateriaisParaReciclagem: 0.0253; UnidadeEPD: 1 m²
Type - IFC.REVIGRÉS-Dados gerais-Floor Covering - Nome: REVIGRÉS-OMNISTONE-BASE-90X90-SOFT-ROPE; TipoProduto: Prensado a seco: grupo BIa UGL | Grés porcelânico técnico; NumeroDeRegistoDAP: EPD-REV-20240006-CCC1-EN; ReferenciaDAP: -; UrlDOP: -
Classification: C3020 (Uniformat)
Pset_CoveringCommon - TotalThickness: 10.5 mm
IFC.REVIGRÉS-Dados do fabricante-Floor Covering - Type: Floor: REVIGRÉS-OMNISTONE-BASE-90X90-SOFT-ROPE
IFC.REVIGRÉS-Dados de desempenho-Floor Covering - Type: Floor: REVIGRÉS-OMNISTONE-BASE-90X90-SOFT-ROPE
IFC.REVIGRÉS-Dados de especificação-Floor Covering - Type: Floor: REVIGRÉS-OMNISTONE-BASE-90X90-SOFT-ROPE
IFC.REVIGRÉS-Dados geométricos-Floor Covering - Type: Floor: REVIGRÉS-OMNISTONE-BASE-90X90-SOFT-ROPE
IFC.REVIGRÉS-Dados de sustentabilidade-Floor Covering - Type: Floor: REVIGRÉS-OMNISTONE-BASE-90X90-SOFT-ROPE

# IfcWallStandardCase: Basic Wall:REVIGRÉS-OMNISTONE-BASE-30X60-MATTRECT-BONE, Basic Wall:REVIGRÉS-OMNISTONE-BASE-30X60-MATTRECT-BONE:2654
In: Level 1
Type - PredefinedType: STANDARD; Material: REVIGRÉS-OMNISTONE-BASE-30x60-MATTRECT-BONE 9.8 mm
Type - Pset_ElementShading - Roughness: 304.8 mm
Type - Pset_ManufacturerTypeInformation - Manufacturer: REVIGRÉS
Type - Pset_ProductRequirements - Category: Walls
Type - Pset_QuantityTakeOff - Reference: 312B2188U1
Type - Pset_ReinforcementBarPitchOfWall - Description: Stone effect in wall and floor porcelain tile; Reference: 312B2188U1
Type - Pset_WallCommon - Reference: 312B2188U1; IsExternal: no
Type - IFC.REVIGRÉS-Dados do fabricante-Wall Covering - FabricanteURL: https://www.revigres.pt/; ReferenciaModelo: Omnistone; NumeroGlobalDeItemComercial: 312B2188U1; Acabamento: MATT RECT; Material: Grés porcelânico; IdentificadorDoOperadorEconomico: 501840856; UrlFabricanteArtigo: https://www.revigres.pt/colecoes/omnistone; PaisOrigem: Portugal
Type - IFC.REVIGRÉS-Dados de desempenho-Wall Covering - Rectilinearidade: ± 0.2% máx.± 0.8 mm; Ortogonalidade: ± 0.2% máx.± 1.5 mm; PlanaridadeDaSuperficie: ± 0.3% máx. ± 1.8 mm; QualidadeDaSuperficie: Cumpre; AbsorcaoDeAgua: < 0.05%; ModuloDeRuptura: > 45 N/mm²; ResistenciaAFlexao: ≥ 3500 N; ResistenciaAAbrasaoProfunda: < 120 mm³; DilatacaoTermicaLinear: ≤ 8,0x10-6 °C-1; ResistenciaAoChoqueTermico: Resiste; DurabilidadeResistenciaAoGeloDegelo: Resiste; ResistenciaAoEscorregamentoDIN51130: R10; ResistenciaAoEscorregamentoDIN51097: B; ResistenciaAoEscorregamentoENV51097: B; ResistenciaAoEscorregamentoENV12633: Class 2; ResistenciaAoEscorregamentoBS7976: >36; ResistenciaAoEscorregamentoANSIA1371: ≥0,42; ResistenciaAoDeslizamentoENV12633: Class 2; ResistenciaAoDeslizamentoBS7976: >36; ResistenciaAsManchas: Class 5; ResistenciaABaixasConcentracoesDeAcidosEAlcalis: Classe LA; ResistenciaAAltasConcentracoesDeAcidosEAlcalis: Classe HA; LibertacaoDeCadmio: 0; LibertacaoDeChumbo: 0
Type - IFC.REVIGRÉS-Dados de especificação-Wall Covering - VariacaoTonalidade: 3; NivelDeTrafego: 5; EPavimento: Sim; ERevestimento: Sim; EExterno: Sim
Type - IFC.REVIGRÉS-Dados geométricos-Wall Covering - AlturaNominal: 9.8 mm; ComprimentoNominal: 29.5 mm; LarguraNominal: 59.2 mm
Type - IFC.REVIGRÉS-Dados de sustentabilidade-Wall Covering - ItemENovo: Sim; ItemEParcialmenteReciclado: 0; ItemEReciclado: Não; VidaÚtilEsperada: 50; SubstanciasPerigosas: Não; PotencialDeEsgotamentoAbioticoDosRecursosNaoFosseisMineraisEMetais: 0.000701; PotencialDeAquecimentoGlobalBiogenico: -0.48; CombustiveisFosseisComPotencialDeAquecimentoGlobal: 13.9; PotencialDeAquecimentoGlobalUsoDoSoloEMudancaDeUsoDoSolo: 0.0246; PotencialDeEutrofizacaoFraccaoDeNutrientesQueAtingemOCompartimentoFinalDeAguaDoce: 0.000189; PotencialDeEutrofizacaoFraccaoDeNutrientesQueAtingemOCompartimentoFinalMarinho: 0.0122; PotencialPrivacaoDeAguaConsumoDeAguaPonderado: 4.5; EnergiaRecuperada: 0.00739; ConsumoDeAguaDoce: 0.113; UtilizacaoLiquidaDeAguaDoce: 0.113; ResiduosPerigososEliminados: 0.00221; ResiduosNaoPerigososEliminados: 1.83; MassaTotalDeResiduosRadioactivosEliminados: 0.000394; EnergiaElectricaExportada: 1.55; EnergiaTermicaExportada: 0; MateriaisParaRecuperacaoDeEnergia: 0.00739; MateriaisParaReciclagem: 0.0253; UnidadeEPD: 1 m²
Type - IFC.REVIGRÉS-Dados gerais-Wall Covering - Nome: REVIGRÉS-OMNISTONE-BASE-30X60-MATT RECT-BONE; TipoProduto: Prensado a seco: grupo BIa UGL | Grés porcelânico técnico; NumeroDeRegistoDAP: EPD-REV-20240006-CCC1-EN; ReferenciaDAP: -; UrlDOP: -
Classification: C3010 (Uniformat)
Pset_WallCommon - ExtendToStructure: no; LoadBearing: no
IFC.REVIGRÉS-Dados do fabricante-Wall Covering - Type: Basic Wall: REVIGRÉS-OMNISTONE-BASE-30X60-MATTRECT-BONE
IFC.REVIGRÉS-Dados de desempenho-Wall Covering - Type: Basic Wall: REVIGRÉS-OMNISTONE-BASE-30X60-MATTRECT-BONE
IFC.REVIGRÉS-Dados de especificação-Wall Covering - Type: Basic Wall: REVIGRÉS-OMNISTONE-BASE-30X60-MATTRECT-BONE
IFC.REVIGRÉS-Dados geométricos-Wall Covering - Type: Basic Wall: REVIGRÉS-OMNISTONE-BASE-30X60-MATTRECT-BONE
IFC.REVIGRÉS-Dados de sustentabilidade-Wall Covering - Type: Basic Wall: REVIGRÉS-OMNISTONE-BASE-30X60-MATTRECT-BONE

# IfcWallStandardCase: Basic Wall:REVIGRÉS-OMNISTONE-BASE-30X60-MATTRECT-ICE, Basic Wall:REVIGRÉS-OMNISTONE-BASE-30X60-MATTRECT-ICE:148423
In: Level 1
Type - PredefinedType: STANDARD; Material: REVIGRÉS-OMNISTONE-BASE-30x60-MATTRECT-ICE 9.8 mm
Type - Pset_ElementShading - Roughness: 304.8 mm
Type - Pset_ManufacturerTypeInformation - Manufacturer: REVIGRÉS
Type - Pset_ProductRequirements - Category: Walls
Type - Pset_QuantityTakeOff - Reference: 312B2189U1
Type - Pset_ReinforcementBarPitchOfWall - Description: Stone effect in wall and floor porcelain tile; Reference: 312B2189U1
Type - Pset_WallCommon - IsExternal: no; Reference: 312B2189U1
Type - IFC.REVIGRÉS-Dados do fabricante-Wall Covering - FabricanteURL: https://www.revigres.pt/; ReferenciaModelo: Omnistone; NumeroGlobalDeItemComercial: 312B2189U1; Acabamento: MATT RECT; Material: Grés porcelânico; IdentificadorDoOperadorEconomico: 501840856; UrlFabricanteArtigo: https://www.revigres.pt/colecoes/omnistone; PaisOrigem: Portugal
Type - IFC.REVIGRÉS-Dados de desempenho-Wall Covering - Rectilinearidade: ± 0.2% máx.± 0.8 mm; Ortogonalidade: ± 0.2% máx.± 1.5 mm; PlanaridadeDaSuperficie: ± 0.3% máx. ± 1.8 mm; QualidadeDaSuperficie: Cumpre; AbsorcaoDeAgua: < 0.05%; ModuloDeRuptura: > 45 N/mm²; ResistenciaAFlexao: ≥ 3500 N; ResistenciaAAbrasaoProfunda: < 120 mm³; DilatacaoTermicaLinear: ≤ 8,0x10-6 °C-1; ResistenciaAoChoqueTermico: Resiste; DurabilidadeResistenciaAoGeloDegelo: Resiste; ResistenciaAoEscorregamentoDIN51130: R10; ResistenciaAoEscorregamentoDIN51097: B; ResistenciaAoEscorregamentoENV51097: B; ResistenciaAoEscorregamentoENV12633: Class 2; ResistenciaAoEscorregamentoBS7976: >36; ResistenciaAoEscorregamentoANSIA1371: ≥0,42; ResistenciaAoDeslizamentoENV12633: Class 2; ResistenciaAoDeslizamentoBS7976: >36; ResistenciaAsManchas: Class 5; ResistenciaABaixasConcentracoesDeAcidosEAlcalis: Classe LA; ResistenciaAAltasConcentracoesDeAcidosEAlcalis: Classe HA; LibertacaoDeCadmio: 0; LibertacaoDeChumbo: 0
Type - IFC.REVIGRÉS-Dados de especificação-Wall Covering - VariacaoTonalidade: 3; NivelDeTrafego: 5; EPavimento: Sim; ERevestimento: Sim; EExterno: Sim
Type - IFC.REVIGRÉS-Dados geométricos-Wall Covering - AlturaNominal: 9.8 mm; ComprimentoNominal: 29.5 mm; LarguraNominal: 59.2 mm
Type - IFC.REVIGRÉS-Dados de sustentabilidade-Wall Covering - ItemEParcialmenteReciclado: 0; PotencialPrivacaoDeAguaConsumoDeAguaPonderado: 4.5; EnergiaTermicaExportada: 0; ItemENovo: Sim; ItemEReciclado: Não; VidaÚtilEsperada: 50; SubstanciasPerigosas: Não; PotencialDeEsgotamentoAbioticoDosRecursosNaoFosseisMineraisEMetais: 0.000701; PotencialDeAquecimentoGlobalBiogenico: -0.48; CombustiveisFosseisComPotencialDeAquecimentoGlobal: 13.9; PotencialDeAquecimentoGlobalUsoDoSoloEMudancaDeUsoDoSolo: 0.0246; PotencialDeEutrofizacaoFraccaoDeNutrientesQueAtingemOCompartimentoFinalDeAguaDoce: 0.000189; PotencialDeEutrofizacaoFraccaoDeNutrientesQueAtingemOCompartimentoFinalMarinho: 0.0122; EnergiaRecuperada: 0.00739; ConsumoDeAguaDoce: 0.113; UtilizacaoLiquidaDeAguaDoce: 0.113; ResiduosPerigososEliminados: 0.00221; ResiduosNaoPerigososEliminados: 1.83; MassaTotalDeResiduosRadioactivosEliminados: 0.000394; EnergiaElectricaExportada: 1.55; MateriaisParaRecuperacaoDeEnergia: 0.00739; MateriaisParaReciclagem: 0.0253; UnidadeEPD: 1 m²
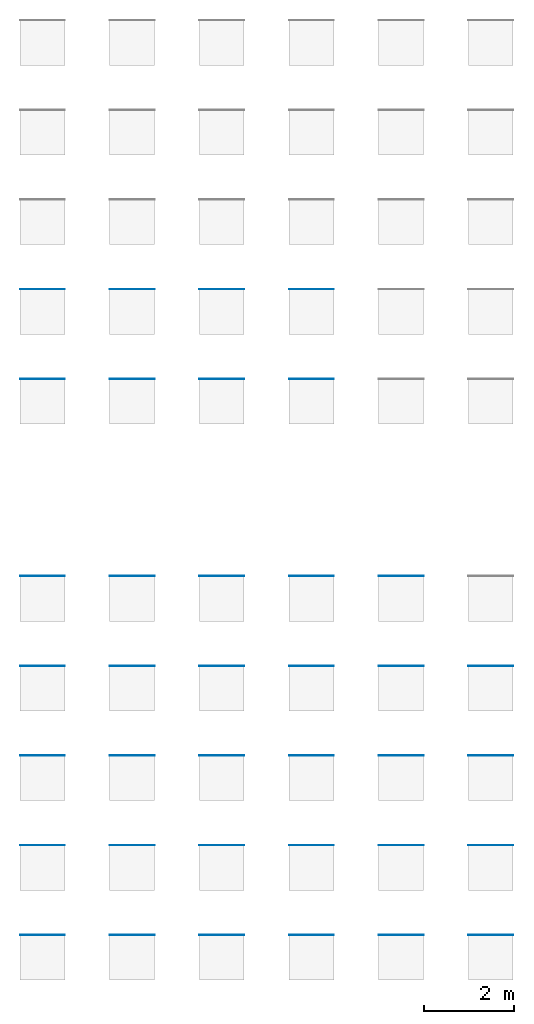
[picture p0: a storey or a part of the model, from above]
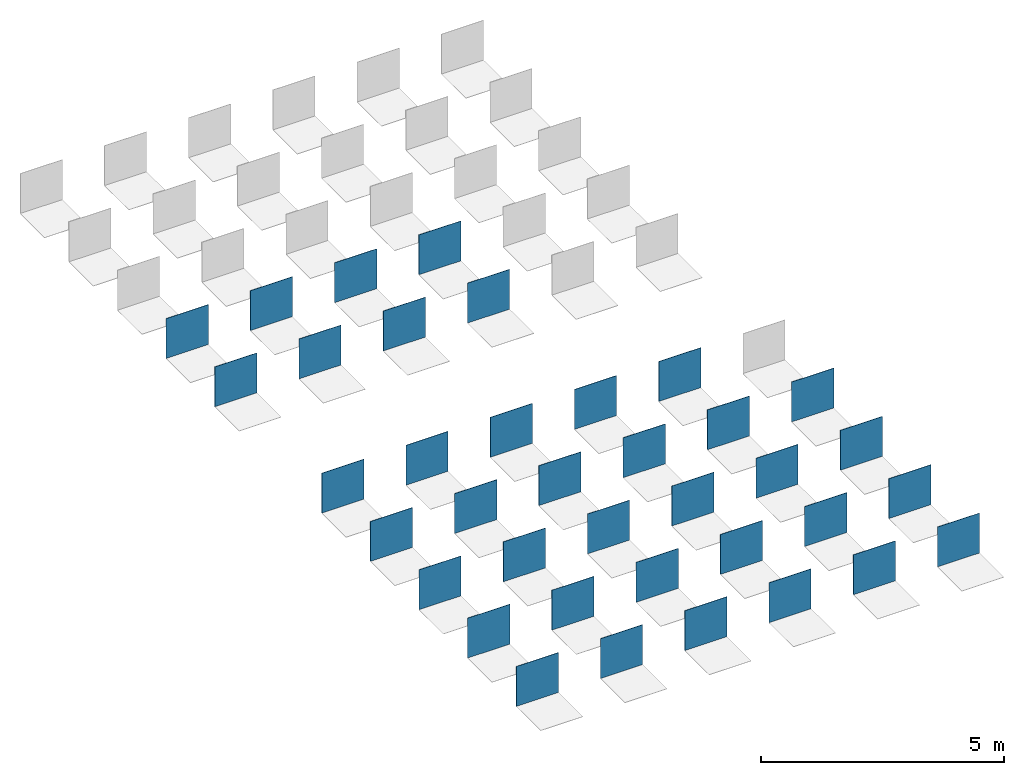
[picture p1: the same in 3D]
Properties of the parts of a building model (IFC2X3), part 6 of 8

# IfcWallStandardCase: Basic Wall:REVIGRÉS-OMNISTONE-BASE-45X90-MATTRECT-PLATINA, Basic Wall:REVIGRÉS-OMNISTONE-BASE-45X90-MATTRECT-PLATINA:150604
Type - IFC.REVIGRÉS-Dados de sustentabilidade-Wall Covering - ItemEParcialmenteReciclado: 0; PotencialPrivacaoDeAguaConsumoDeAguaPonderado: 4.5; EnergiaTermicaExportada: 0; ItemENovo: Sim; ItemEReciclado: Não; VidaÚtilEsperada: 50; SubstanciasPerigosas: Não; PotencialDeEsgotamentoAbioticoDosRecursosNaoFosseisMineraisEMetais: 0.000701; PotencialDeAquecimentoGlobalBiogenico: -0.48; CombustiveisFosseisComPotencialDeAquecimentoGlobal: 13.9; PotencialDeAquecimentoGlobalUsoDoSoloEMudancaDeUsoDoSolo: 0.0246; PotencialDeEutrofizacaoFraccaoDeNutrientesQueAtingemOCompartimentoFinalDeAguaDoce: 0.000189; PotencialDeEutrofizacaoFraccaoDeNutrientesQueAtingemOCompartimentoFinalMarinho: 0.0122; EnergiaRecuperada: 0.00739; ConsumoDeAguaDoce: 0.113; UtilizacaoLiquidaDeAguaDoce: 0.113; ResiduosPerigososEliminados: 0.00221; ResiduosNaoPerigososEliminados: 1.83; MassaTotalDeResiduosRadioactivosEliminados: 0.000394; EnergiaElectricaExportada: 1.55; MateriaisParaRecuperacaoDeEnergia: 0.00739; MateriaisParaReciclagem: 0.0253; UnidadeEPD: 1 m²
Type - IFC.REVIGRÉS-Dados gerais-Wall Covering - Nome: REVIGRÉS-OMNISTONE-BASE-45X90-MATT RECT-PLATINA; TipoProduto: Prensado a seco: grupo BIa UGL | Grés porcelânico técnico; NumeroDeRegistoDAP: EPD-REV-20240006-CCC1-EN; ReferenciaDAP: -; UrlDOP: -
Pset_WallCommon - ExtendToStructure: no; LoadBearing: no
IFC.REVIGRÉS-Dados do fabricante-Wall Covering - Type: Basic Wall: REVIGRÉS-OMNISTONE-BASE-45X90-MATTRECT-PLATINA
IFC.REVIGRÉS-Dados de desempenho-Wall Covering - Type: Basic Wall: REVIGRÉS-OMNISTONE-BASE-45X90-MATTRECT-PLATINA
IFC.REVIGRÉS-Dados de especificação-Wall Covering - Type: Basic Wall: REVIGRÉS-OMNISTONE-BASE-45X90-MATTRECT-PLATINA
IFC.REVIGRÉS-Dados geométricos-Wall Covering - Type: Basic Wall: REVIGRÉS-OMNISTONE-BASE-45X90-MATTRECT-PLATINA
IFC.REVIGRÉS-Dados de sustentabilidade-Wall Covering - Type: Basic Wall: REVIGRÉS-OMNISTONE-BASE-45X90-MATTRECT-PLATINA

# IfcWallStandardCase: Basic Wall:REVIGRÉS-OMNISTONE-BASE-45X90-MATTRECT-ROPE, Basic Wall:REVIGRÉS-OMNISTONE-BASE-45X90-MATTRECT-ROPE:151309
In: Level 1
Type - PredefinedType: STANDARD; Material: REVIGRÉS-OMNISTONE-BASE-45x90-MATTRECT-ROPE 10.5 mm
Type - Pset_ElementShading - Roughness: 304.8 mm
Type - Pset_ManufacturerTypeInformation - Manufacturer: REVIGRÉS
Type - Pset_ProductRequirements - Category: Walls
Type - Pset_QuantityTakeOff - Reference: 312BH893U1
Type - Pset_ReinforcementBarPitchOfWall - Description: Stone effect in wall and floor porcelain tile; Reference: 312BH893U1
Type - Pset_WallCommon - IsExternal: no; Reference: 312BH893U1
Type - IFC.REVIGRÉS-Dados do fabricante-Wall Covering - FabricanteURL: https://www.revigres.pt/; ReferenciaModelo: Omnistone; NumeroGlobalDeItemComercial: 312BH893U1; Acabamento: MATT RECT; Material: Grés porcelânico; IdentificadorDoOperadorEconomico: 501840856; UrlFabricanteArtigo: https://www.revigres.pt/colecoes/omnistone; PaisOrigem: Portugal
Type - IFC.REVIGRÉS-Dados de desempenho-Wall Covering - Rectilinearidade: ± 0.2% máx.± 0.8 mm; Ortogonalidade: ± 0.2% máx.± 1.5 mm; PlanaridadeDaSuperficie: ± 0.3% máx. ± 1.8 mm; QualidadeDaSuperficie: Cumpre; AbsorcaoDeAgua: < 0.05%; ModuloDeRuptura: > 45 N/mm130; ResistenciaAFlexao: ≥ 3500 N; ResistenciaAAbrasaoProfunda: < 120 mm131; DilatacaoTermicaLinear: ≤ 8,0x10-6 °C-1; ResistenciaAoChoqueTermico: Resiste; DurabilidadeResistenciaAoGeloDegelo: Resiste; ResistenciaAoEscorregamentoDIN51130: R10; ResistenciaAoEscorregamentoDIN51097: B; ResistenciaAoEscorregamentoENV51097: B; ResistenciaAoEscorregamentoENV12633: Class 2; ResistenciaAoEscorregamentoBS7976: >36; ResistenciaAoEscorregamentoANSIA1371: ≥0,42; ResistenciaAoDeslizamentoENV12633: Class 2; ResistenciaAoDeslizamentoBS7976: >36; ResistenciaAsManchas: Class 5; ResistenciaABaixasConcentracoesDeAcidosEAlcalis: Classe LA; ResistenciaAAltasConcentracoesDeAcidosEAlcalis: Classe HA; LibertacaoDeCadmio: 0; LibertacaoDeChumbo: 0
Type - IFC.REVIGRÉS-Dados de especificação-Wall Covering - VariacaoTonalidade: 3; NivelDeTrafego: 5; EPavimento: Sim; ERevestimento: Sim; EExterno: Sim
Type - IFC.REVIGRÉS-Dados geométricos-Wall Covering - AlturaNominal: 10.5 mm; ComprimentoNominal: 44.35 mm; LarguraNominal: 88.9 mm
Type - IFC.REVIGRÉS-Dados de sustentabilidade-Wall Covering - ItemEParcialmenteReciclado: 0; PotencialPrivacaoDeAguaConsumoDeAguaPonderado: 4.5; EnergiaTermicaExportada: 0; ItemENovo: Sim; ItemEReciclado: Não; VidaÚtilEsperada: 50; SubstanciasPerigosas: Não; PotencialDeEsgotamentoAbioticoDosRecursosNaoFosseisMineraisEMetais: 0.000701; PotencialDeAquecimentoGlobalBiogenico: -0.48; CombustiveisFosseisComPotencialDeAquecimentoGlobal: 13.9; PotencialDeAquecimentoGlobalUsoDoSoloEMudancaDeUsoDoSolo: 0.0246; PotencialDeEutrofizacaoFraccaoDeNutrientesQueAtingemOCompartimentoFinalDeAguaDoce: 0.000189; PotencialDeEutrofizacaoFraccaoDeNutrientesQueAtingemOCompartimentoFinalMarinho: 0.0122; EnergiaRecuperada: 0.00739; ConsumoDeAguaDoce: 0.113; UtilizacaoLiquidaDeAguaDoce: 0.113; ResiduosPerigososEliminados: 0.00221; ResiduosNaoPerigososEliminados: 1.83; MassaTotalDeResiduosRadioactivosEliminados: 0.000394; EnergiaElectricaExportada: 1.55; MateriaisParaRecuperacaoDeEnergia: 0.00739; MateriaisParaReciclagem: 0.0253; UnidadeEPD: 1 m²
Type - IFC.REVIGRÉS-Dados gerais-Wall Covering - Nome: REVIGRÉS-OMNISTONE-BASE-45X90-MATT RECT-ROPE; TipoProduto: Prensado a seco: grupo BIa UGL | Grés porcelânico técnico; NumeroDeRegistoDAP: EPD-REV-20240006-CCC1-EN; ReferenciaDAP: -; UrlDOP: -
Pset_WallCommon - ExtendToStructure: no; LoadBearing: no
IFC.REVIGRÉS-Dados do fabricante-Wall Covering - Type: Basic Wall: REVIGRÉS-OMNISTONE-BASE-45X90-MATTRECT-ROPE
IFC.REVIGRÉS-Dados de desempenho-Wall Covering - Type: Basic Wall: REVIGRÉS-OMNISTONE-BASE-45X90-MATTRECT-ROPE
IFC.REVIGRÉS-Dados de especificação-Wall Covering - Type: Basic Wall: REVIGRÉS-OMNISTONE-BASE-45X90-MATTRECT-ROPE
IFC.REVIGRÉS-Dados geométricos-Wall Covering - Type: Basic Wall: REVIGRÉS-OMNISTONE-BASE-45X90-MATTRECT-ROPE
IFC.REVIGRÉS-Dados de sustentabilidade-Wall Covering - Type: Basic Wall: REVIGRÉS-OMNISTONE-BASE-45X90-MATTRECT-ROPE

# IfcWallStandardCase: Basic Wall:REVIGRÉS-OMNISTONE-BASE-45X90-SOFT-BONE, Basic Wall:REVIGRÉS-OMNISTONE-BASE-45X90-SOFT-BONE:146527
In: Level 1
Type - PredefinedType: STANDARD; Material: REVIGRÉS-OMNISTONE-BASE-45x90-SOFT-BONE 10.5 mm
Type - Pset_ElementShading - Roughness: 304.8 mm
Type - Pset_ManufacturerTypeInformation - Manufacturer: REVIGRÉS
Type - Pset_ProductRequirements - Category: Walls
Type - Pset_QuantityTakeOff - Reference: 3126H888U1
Type - Pset_ReinforcementBarPitchOfWall - Description: Stone effect in wall and floor porcelain tile; Reference: 3126H888U1
Type - Pset_WallCommon - IsExternal: no; Reference: 3126H888U1
Type - IFC.REVIGRÉS-Dados do fabricante-Wall Covering - FabricanteURL: https://www.revigres.pt/; ReferenciaModelo: Omnistone; NumeroGlobalDeItemComercial: 3126H888U1; Acabamento: SOFT; Material: Grés porcelânico; IdentificadorDoOperadorEconomico: 501840856; UrlFabricanteArtigo: https://www.revigres.pt/colecoes/omnistone; PaisOrigem: Portugal
Type - IFC.REVIGRÉS-Dados de desempenho-Wall Covering - Rectilinearidade: ± 0.2% máx.± 0.8 mm; Ortogonalidade: ± 0.2% máx.± 1.5 mm; PlanaridadeDaSuperficie: ± 0.3% máx. ± 1.8 mm; QualidadeDaSuperficie: Cumpre; AbsorcaoDeAgua: < 0.05%; ModuloDeRuptura: > 45 N/mm130; ResistenciaAFlexao: ≥ 3500 N; ResistenciaAAbrasaoProfunda: < 120 mm131; DilatacaoTermicaLinear: ≤ 8,0x10-6 °C-1; ResistenciaAoChoqueTermico: Resiste; DurabilidadeResistenciaAoGeloDegelo: Resiste; ResistenciaAsManchas: Class 5; ResistenciaABaixasConcentracoesDeAcidosEAlcalis: Classe LA; ResistenciaAAltasConcentracoesDeAcidosEAlcalis: Classe HA; LibertacaoDeCadmio: 0; LibertacaoDeChumbo: 0
Type - IFC.REVIGRÉS-Dados de especificação-Wall Covering - VariacaoTonalidade: 3; NivelDeTrafego: 5; EPavimento: Sim; ERevestimento: Sim; EExterno: Sim
Type - IFC.REVIGRÉS-Dados geométricos-Wall Covering - AlturaNominal: 10.5 mm; ComprimentoNominal: 44.35 mm; LarguraNominal: 88.9 mm
Type - IFC.REVIGRÉS-Dados de sustentabilidade-Wall Covering - ItemEParcialmenteReciclado: 0; PotencialPrivacaoDeAguaConsumoDeAguaPonderado: 4.5; EnergiaTermicaExportada: 0; ItemENovo: Sim; ItemEReciclado: Não; VidaÚtilEsperada: 50; SubstanciasPerigosas: Não; PotencialDeEsgotamentoAbioticoDosRecursosNaoFosseisMineraisEMetais: 0.000701; PotencialDeAquecimentoGlobalBiogenico: -0.48; CombustiveisFosseisComPotencialDeAquecimentoGlobal: 13.9; PotencialDeAquecimentoGlobalUsoDoSoloEMudancaDeUsoDoSolo: 0.0246; PotencialDeEutrofizacaoFraccaoDeNutrientesQueAtingemOCompartimentoFinalDeAguaDoce: 0.000189; PotencialDeEutrofizacaoFraccaoDeNutrientesQueAtingemOCompartimentoFinalMarinho: 0.0122; EnergiaRecuperada: 0.00739; ConsumoDeAguaDoce: 0.113; UtilizacaoLiquidaDeAguaDoce: 0.113; ResiduosPerigososEliminados: 0.00221; ResiduosNaoPerigososEliminados: 1.83; MassaTotalDeResiduosRadioactivosEliminados: 0.000394; EnergiaElectricaExportada: 1.55; MateriaisParaRecuperacaoDeEnergia: 0.00739; MateriaisParaReciclagem: 0.0253; UnidadeEPD: 1 m²
Type - IFC.REVIGRÉS-Dados gerais-Wall Covering - Nome: REVIGRÉS-OMNISTONE-BASE-45X90-SOFT-BONE; TipoProduto: Prensado a seco: grupo BIa UGL | Grés porcelânico técnico; NumeroDeRegistoDAP: EPD-REV-20240006-CCC1-EN; ReferenciaDAP: -; UrlDOP: -
Pset_WallCommon - ExtendToStructure: no; LoadBearing: no
IFC.REVIGRÉS-Dados do fabricante-Wall Covering - Type: Basic Wall: REVIGRÉS-OMNISTONE-BASE-45X90-SOFT-BONE
IFC.REVIGRÉS-Dados de desempenho-Wall Covering - Type: Basic Wall: REVIGRÉS-OMNISTONE-BASE-45X90-SOFT-BONE
IFC.REVIGRÉS-Dados de especificação-Wall Covering - Type: Basic Wall: REVIGRÉS-OMNISTONE-BASE-45X90-SOFT-BONE
IFC.REVIGRÉS-Dados geométricos-Wall Covering - Type: Basic Wall: REVIGRÉS-OMNISTONE-BASE-45X90-SOFT-BONE
IFC.REVIGRÉS-Dados de sustentabilidade-Wall Covering - Type: Basic Wall: REVIGRÉS-OMNISTONE-BASE-45X90-SOFT-BONE

# IfcWallStandardCase: Basic Wall:REVIGRÉS-OMNISTONE-BASE-45X90-SOFT-ICE, Basic Wall:REVIGRÉS-OMNISTONE-BASE-45X90-SOFT-ICE:148536
In: Level 1
Type - PredefinedType: STANDARD; Material: REVIGRÉS-OMNISTONE-BASE-45x90-SOFT-ICE 10.5 mm
Type - Pset_ElementShading - Roughness: 304.8 mm
Type - Pset_ManufacturerTypeInformation - Manufacturer: REVIGRÉS
Type - Pset_ProductRequirements - Category: Walls
Type - Pset_QuantityTakeOff - Reference: 3126H889U1
Type - Pset_ReinforcementBarPitchOfWall - Description: Stone effect in wall and floor porcelain tile; Reference: 3126H889U1
Type - Pset_WallCommon - IsExternal: no; Reference: 3126H889U1
Type - IFC.REVIGRÉS-Dados do fabricante-Wall Covering - FabricanteURL: https://www.revigres.pt/; ReferenciaModelo: Omnistone; NumeroGlobalDeItemComercial: 3126H889U1; Acabamento: SOFT; Material: Grés porcelânico; IdentificadorDoOperadorEconomico: 501840856; UrlFabricanteArtigo: https://www.revigres.pt/colecoes/omnistone; PaisOrigem: Portugal
Type - IFC.REVIGRÉS-Dados de desempenho-Wall Covering - Rectilinearidade: ± 0.2% máx.± 0.8 mm; Ortogonalidade: ± 0.2% máx.± 1.5 mm; PlanaridadeDaSuperficie: ± 0.3% máx. ± 1.8 mm; QualidadeDaSuperficie: Cumpre; AbsorcaoDeAgua: < 0.05%; ModuloDeRuptura: > 45 N/mm130; ResistenciaAFlexao: ≥ 3500 N; ResistenciaAAbrasaoProfunda: < 120 mm131; DilatacaoTermicaLinear: ≤ 8,0x10-6 °C-1; ResistenciaAoChoqueTermico: Resiste; DurabilidadeResistenciaAoGeloDegelo: Resiste; ResistenciaAsManchas: Class 5; ResistenciaABaixasConcentracoesDeAcidosEAlcalis: Classe LA; ResistenciaAAltasConcentracoesDeAcidosEAlcalis: Classe HA; LibertacaoDeCadmio: 0; LibertacaoDeChumbo: 0
Type - IFC.REVIGRÉS-Dados de especificação-Wall Covering - VariacaoTonalidade: 3; NivelDeTrafego: 5; EPavimento: Sim; ERevestimento: Sim; EExterno: Sim
Type - IFC.REVIGRÉS-Dados geométricos-Wall Covering - AlturaNominal: 10.5 mm; ComprimentoNominal: 44.35 mm; LarguraNominal: 88.9 mm
Type - IFC.REVIGRÉS-Dados de sustentabilidade-Wall Covering - ItemEParcialmenteReciclado: 0; PotencialPrivacaoDeAguaConsumoDeAguaPonderado: 4.5; EnergiaTermicaExportada: 0; ItemENovo: Sim; ItemEReciclado: Não; VidaÚtilEsperada: 50; SubstanciasPerigosas: Não; PotencialDeEsgotamentoAbioticoDosRecursosNaoFosseisMineraisEMetais: 0.000701; PotencialDeAquecimentoGlobalBiogenico: -0.48; CombustiveisFosseisComPotencialDeAquecimentoGlobal: 13.9; PotencialDeAquecimentoGlobalUsoDoSoloEMudancaDeUsoDoSolo: 0.0246; PotencialDeEutrofizacaoFraccaoDeNutrientesQueAtingemOCompartimentoFinalDeAguaDoce: 0.000189; PotencialDeEutrofizacaoFraccaoDeNutrientesQueAtingemOCompartimentoFinalMarinho: 0.0122; EnergiaRecuperada: 0.00739; ConsumoDeAguaDoce: 0.113; UtilizacaoLiquidaDeAguaDoce: 0.113; ResiduosPerigososEliminados: 0.00221; ResiduosNaoPerigososEliminados: 1.83; MassaTotalDeResiduosRadioactivosEliminados: 0.000394; EnergiaElectricaExportada: 1.55; MateriaisParaRecuperacaoDeEnergia: 0.00739; MateriaisParaReciclagem: 0.0253; UnidadeEPD: 1 m²
Type - IFC.REVIGRÉS-Dados gerais-Wall Covering - Nome: REVIGRÉS-OMNISTONE-BASE-45X90-SOFT-ICE; TipoProduto: Prensado a seco: grupo BIa UGL | Grés porcelânico técnico; NumeroDeRegistoDAP: EPD-REV-20240006-CCC1-EN; ReferenciaDAP: -; UrlDOP: -
Pset_WallCommon - ExtendToStructure: no; LoadBearing: no
IFC.REVIGRÉS-Dados do fabricante-Wall Covering - Type: Basic Wall: REVIGRÉS-OMNISTONE-BASE-45X90-SOFT-ICE
IFC.REVIGRÉS-Dados de desempenho-Wall Covering - Type: Basic Wall: REVIGRÉS-OMNISTONE-BASE-45X90-SOFT-ICE
IFC.REVIGRÉS-Dados de especificação-Wall Covering - Type: Basic Wall: REVIGRÉS-OMNISTONE-BASE-45X90-SOFT-ICE
IFC.REVIGRÉS-Dados geométricos-Wall Covering - Type: Basic Wall: REVIGRÉS-OMNISTONE-BASE-45X90-SOFT-ICE
IFC.REVIGRÉS-Dados de sustentabilidade-Wall Covering - Type: Basic Wall: REVIGRÉS-OMNISTONE-BASE-45X90-SOFT-ICE

# IfcWallStandardCase: Basic Wall:REVIGRÉS-OMNISTONE-BASE-45X90-SOFT-IRON, Basic Wall:REVIGRÉS-OMNISTONE-BASE-45X90-SOFT-IRON:149221
In: Level 1
Type - PredefinedType: STANDARD; Material: REVIGRÉS-OMNISTONE-BASE-45x90-SOFT-IRON 10.5 mm
Type - Pset_ElementShading - Roughness: 304.8 mm
Type - Pset_ManufacturerTypeInformation - Manufacturer: REVIGRÉS
Type - Pset_ProductRequirements - Category: Walls
Type - Pset_QuantityTakeOff - Reference: 3126H890U1
Type - Pset_ReinforcementBarPitchOfWall - Description: Stone effect in wall and floor porcelain tile; Reference: 3126H890U1
Type - Pset_WallCommon - IsExternal: no; Reference: 3126H890U1
Type - IFC.REVIGRÉS-Dados do fabricante-Wall Covering - FabricanteURL: https://www.revigres.pt/; ReferenciaModelo: Omnistone; NumeroGlobalDeItemComercial: 3126H890U1; Acabamento: SOFT; Material: Grés porcelânico; IdentificadorDoOperadorEconomico: 501840856; UrlFabricanteArtigo: https://www.revigres.pt/colecoes/omnistone; PaisOrigem: Portugal
Type - IFC.REVIGRÉS-Dados de desempenho-Wall Covering - Rectilinearidade: ± 0.2% máx.± 0.8 mm; Ortogonalidade: ± 0.2% máx.± 1.5 mm; PlanaridadeDaSuperficie: ± 0.3% máx. ± 1.8 mm; QualidadeDaSuperficie: Cumpre; AbsorcaoDeAgua: < 0.05%; ModuloDeRuptura: > 45 N/mm130; ResistenciaAFlexao: ≥ 3500 N; ResistenciaAAbrasaoProfunda: < 120 mm131; DilatacaoTermicaLinear: ≤ 8,0x10-6 °C-1; ResistenciaAoChoqueTermico: Resiste; DurabilidadeResistenciaAoGeloDegelo: Resiste; ResistenciaAsManchas: Class 5; ResistenciaABaixasConcentracoesDeAcidosEAlcalis: Classe LA; ResistenciaAAltasConcentracoesDeAcidosEAlcalis: Classe HA; LibertacaoDeCadmio: 0; LibertacaoDeChumbo: 0
Type - IFC.REVIGRÉS-Dados de especificação-Wall Covering - VariacaoTonalidade: 3; NivelDeTrafego: 5; EPavimento: Sim; ERevestimento: Sim; EExterno: Sim
Type - IFC.REVIGRÉS-Dados geométricos-Wall Covering - AlturaNominal: 10.5 mm; ComprimentoNominal: 44.35 mm; LarguraNominal: 88.9 mm
Type - IFC.REVIGRÉS-Dados de sustentabilidade-Wall Covering - PotencialPrivacaoDeAguaConsumoDeAguaPonderado: 4.5; EnergiaTermicaExportada: 0; ItemENovo: Sim; ItemEParcialmenteReciclado: 0.14; ItemEReciclado: Sim; VidaÚtilEsperada: 50; SubstanciasPerigosas: Não; PotencialDeEsgotamentoAbioticoDosRecursosNaoFosseisMineraisEMetais: 0.000701; PotencialDeAquecimentoGlobalBiogenico: -0.48; CombustiveisFosseisComPotencialDeAquecimentoGlobal: 13.9; PotencialDeAquecimentoGlobalUsoDoSoloEMudancaDeUsoDoSolo: 0.0246; PotencialDeEutrofizacaoFraccaoDeNutrientesQueAtingemOCompartimentoFinalDeAguaDoce: 0.000189; PotencialDeEutrofizacaoFraccaoDeNutrientesQueAtingemOCompartimentoFinalMarinho: 0.0122; EnergiaRecuperada: 0.00739; ConsumoDeAguaDoce: 0.113; UtilizacaoLiquidaDeAguaDoce: 0.113; ResiduosPerigososEliminados: 0.00221; ResiduosNaoPerigososEliminados: 1.83; MassaTotalDeResiduosRadioactivosEliminados: 0.000394; EnergiaElectricaExportada: 1.55; MateriaisParaRecuperacaoDeEnergia: 0.00739; MateriaisParaReciclagem: 0.0253; UnidadeEPD: 1 m²
Type - IFC.REVIGRÉS-Dados gerais-Wall Covering - Nome: REVIGRÉS-OMNISTONE-BASE-45X90-SOFT-IRON; TipoProduto: Prensado a seco: grupo BIa UGL | Grés porcelânico técnico; NumeroDeRegistoDAP: EPD-REV-20240006-CCC1-EN; ReferenciaDAP: -; UrlDOP: -
Pset_WallCommon - ExtendToStructure: no; LoadBearing: no
IFC.REVIGRÉS-Dados do fabricante-Wall Covering - Type: Basic Wall: REVIGRÉS-OMNISTONE-BASE-45X90-SOFT-IRON
IFC.REVIGRÉS-Dados de desempenho-Wall Covering - Type: Basic Wall: REVIGRÉS-OMNISTONE-BASE-45X90-SOFT-IRON
IFC.REVIGRÉS-Dados de especificação-Wall Covering - Type: Basic Wall: REVIGRÉS-OMNISTONE-BASE-45X90-SOFT-IRON
IFC.REVIGRÉS-Dados geométricos-Wall Covering - Type: Basic Wall: REVIGRÉS-OMNISTONE-BASE-45X90-SOFT-IRON
IFC.REVIGRÉS-Dados de sustentabilidade-Wall Covering - Type: Basic Wall: REVIGRÉS-OMNISTONE-BASE-45X90-SOFT-IRON

# IfcWallStandardCase: Basic Wall:REVIGRÉS-OMNISTONE-BASE-45X90-SOFT-JET, Basic Wall:REVIGRÉS-OMNISTONE-BASE-45X90-SOFT-JET:149963
In: Level 1
Type - PredefinedType: STANDARD; Material: REVIGRÉS-OMNISTONE-BASE-45x90-SOFT-JET 10.5 mm
Type - Pset_ElementShading - Roughness: 304.8 mm
Type - Pset_ManufacturerTypeInformation - Manufacturer: REVIGRÉS
Type - Pset_ProductRequirements - Category: Walls
Type - Pset_QuantityTakeOff - Reference: 3126H891U1
Type - Pset_ReinforcementBarPitchOfWall - Description: Stone effect in wall and floor porcelain tile; Reference: 3126H891U1
Type - Pset_WallCommon - IsExternal: no; Reference: 3126H891U1
Type - IFC.REVIGRÉS-Dados do fabricante-Wall Covering - FabricanteURL: https://www.revigres.pt/; ReferenciaModelo: Omnistone; NumeroGlobalDeItemComercial: 3126H891U1; Acabamento: SOFT; Material: Grés porcelânico; IdentificadorDoOperadorEconomico: 501840856; UrlFabricanteArtigo: https://www.revigres.pt/colecoes/omnistone; PaisOrigem: Portugal
Type - IFC.REVIGRÉS-Dados de desempenho-Wall Covering - Rectilinearidade: ± 0.2% máx.± 0.8 mm; Ortogonalidade: ± 0.2% máx.± 1.5 mm; PlanaridadeDaSuperficie: ± 0.3% máx. ± 1.8 mm; QualidadeDaSuperficie: Cumpre; AbsorcaoDeAgua: < 0.05%; ModuloDeRuptura: > 45 N/mm130; ResistenciaAFlexao: ≥ 3500 N; ResistenciaAAbrasaoProfunda: < 120 mm131; DilatacaoTermicaLinear: ≤ 8,0x10-6 °C-1; ResistenciaAoChoqueTermico: Resiste; DurabilidadeResistenciaAoGeloDegelo: Resiste; ResistenciaAsManchas: Class 5; ResistenciaABaixasConcentracoesDeAcidosEAlcalis: Classe LA; ResistenciaAAltasConcentracoesDeAcidosEAlcalis: Classe HA; LibertacaoDeCadmio: 0; LibertacaoDeChumbo: 0
Type - IFC.REVIGRÉS-Dados de especificação-Wall Covering - VariacaoTonalidade: 3; NivelDeTrafego: 5; EPavimento: Sim; ERevestimento: Sim; EExterno: Sim
Type - IFC.REVIGRÉS-Dados geométricos-Wall Covering - AlturaNominal: 10.5 mm; ComprimentoNominal: 44.35 mm; LarguraNominal: 88.9 mm
Type - IFC.REVIGRÉS-Dados de sustentabilidade-Wall Covering - ItemEParcialmenteReciclado: 0; PotencialPrivacaoDeAguaConsumoDeAguaPonderado: 4.5; EnergiaTermicaExportada: 0; ItemENovo: Sim; ItemEReciclado: Não; VidaÚtilEsperada: 50; SubstanciasPerigosas: Não; PotencialDeEsgotamentoAbioticoDosRecursosNaoFosseisMineraisEMetais: 0.000701; PotencialDeAquecimentoGlobalBiogenico: -0.48; CombustiveisFosseisComPotencialDeAquecimentoGlobal: 13.9; PotencialDeAquecimentoGlobalUsoDoSoloEMudancaDeUsoDoSolo: 0.0246; PotencialDeEutrofizacaoFraccaoDeNutrientesQueAtingemOCompartimentoFinalDeAguaDoce: 0.000189; PotencialDeEutrofizacaoFraccaoDeNutrientesQueAtingemOCompartimentoFinalMarinho: 0.0122; EnergiaRecuperada: 0.00739; ConsumoDeAguaDoce: 0.113; UtilizacaoLiquidaDeAguaDoce: 0.113; ResiduosPerigososEliminados: 0.00221; ResiduosNaoPerigososEliminados: 1.83; MassaTotalDeResiduosRadioactivosEliminados: 0.000394; EnergiaElectricaExportada: 1.55; MateriaisParaRecuperacaoDeEnergia: 0.00739; MateriaisParaReciclagem: 0.0253; UnidadeEPD: 1 m²
Type - IFC.REVIGRÉS-Dados gerais-Wall Covering - Nome: REVIGRÉS-OMNISTONE-BASE-45X90-SOFT-JET; TipoProduto: Prensado a seco: grupo BIa UGL | Grés porcelânico técnico; NumeroDeRegistoDAP: EPD-REV-20240006-CCC1-EN; ReferenciaDAP: -; UrlDOP: -
Pset_WallCommon - ExtendToStructure: no; LoadBearing: no
IFC.REVIGRÉS-Dados do fabricante-Wall Covering - Type: Basic Wall: REVIGRÉS-OMNISTONE-BASE-45X90-SOFT-JET
IFC.REVIGRÉS-Dados de desempenho-Wall Covering - Type: Basic Wall: REVIGRÉS-OMNISTONE-BASE-45X90-SOFT-JET
IFC.REVIGRÉS-Dados de especificação-Wall Covering - Type: Basic Wall: REVIGRÉS-OMNISTONE-BASE-45X90-SOFT-JET
IFC.REVIGRÉS-Dados geométricos-Wall Covering - Type: Basic Wall: REVIGRÉS-OMNISTONE-BASE-45X90-SOFT-JET
IFC.REVIGRÉS-Dados de sustentabilidade-Wall Covering - Type: Basic Wall: REVIGRÉS-OMNISTONE-BASE-45X90-SOFT-JET

# IfcWallStandardCase: Basic Wall:REVIGRÉS-OMNISTONE-BASE-45X90-SOFT-PLATINA, Basic Wall:REVIGRÉS-OMNISTONE-BASE-45X90-SOFT-PLATINA:150684
In: Level 1
Type - PredefinedType: STANDARD; Material: REVIGRÉS-OMNISTONE-BASE-45x90-SOFT-PLATINA 10.5 mm
Type - Pset_ElementShading - Roughness: 304.8 mm
Type - Pset_ManufacturerTypeInformation - Manufacturer: REVIGRÉS
Type - Pset_ProductRequirements - Category: Walls
Type - Pset_QuantityTakeOff - Reference: 3126H892U1
Type - Pset_ReinforcementBarPitchOfWall - Description: Stone effect in wall and floor porcelain tile; Reference: 3126H892U1
Type - Pset_WallCommon - IsExternal: no; Reference: 3126H892U1
Type - IFC.REVIGRÉS-Dados do fabricante-Wall Covering - FabricanteURL: https://www.revigres.pt/; ReferenciaModelo: Omnistone; NumeroGlobalDeItemComercial: 3126H892U1; Acabamento: SOFT; Material: Grés porcelânico; IdentificadorDoOperadorEconomico: 501840856; UrlFabricanteArtigo: https://www.revigres.pt/colecoes/omnistone; PaisOrigem: Portugal
Type - IFC.REVIGRÉS-Dados de desempenho-Wall Covering - Rectilinearidade: ± 0.2% máx.± 0.8 mm; Ortogonalidade: ± 0.2% máx.± 1.5 mm; PlanaridadeDaSuperficie: ± 0.3% máx. ± 1.8 mm; QualidadeDaSuperficie: Cumpre; AbsorcaoDeAgua: < 0.05%; ModuloDeRuptura: > 45 N/mm130; ResistenciaAFlexao: ≥ 3500 N; ResistenciaAAbrasaoProfunda: < 120 mm131; DilatacaoTermicaLinear: ≤ 8,0x10-6 °C-1; ResistenciaAoChoqueTermico: Resiste; DurabilidadeResistenciaAoGeloDegelo: Resiste; ResistenciaAsManchas: Class 5; ResistenciaABaixasConcentracoesDeAcidosEAlcalis: Classe LA; ResistenciaAAltasConcentracoesDeAcidosEAlcalis: Classe HA; LibertacaoDeCadmio: 0; LibertacaoDeChumbo: 0
Type - IFC.REVIGRÉS-Dados de especificação-Wall Covering - VariacaoTonalidade: 3; NivelDeTrafego: 5; EPavimento: Sim; ERevestimento: Sim; EExterno: Sim
Type - IFC.REVIGRÉS-Dados geométricos-Wall Covering - AlturaNominal: 10.5 mm; ComprimentoNominal: 44.35 mm; LarguraNominal: 88.9 mm
Type - IFC.REVIGRÉS-Dados de sustentabilidade-Wall Covering - ItemEParcialmenteReciclado: 0; PotencialPrivacaoDeAguaConsumoDeAguaPonderado: 4.5; EnergiaTermicaExportada: 0; ItemENovo: Sim; ItemEReciclado: Não; VidaÚtilEsperada: 50; SubstanciasPerigosas: Não; PotencialDeEsgotamentoAbioticoDosRecursosNaoFosseisMineraisEMetais: 0.000701; PotencialDeAquecimentoGlobalBiogenico: -0.48; CombustiveisFosseisComPotencialDeAquecimentoGlobal: 13.9; PotencialDeAquecimentoGlobalUsoDoSoloEMudancaDeUsoDoSolo: 0.0246; PotencialDeEutrofizacaoFraccaoDeNutrientesQueAtingemOCompartimentoFinalDeAguaDoce: 0.000189; PotencialDeEutrofizacaoFraccaoDeNutrientesQueAtingemOCompartimentoFinalMarinho: 0.0122; EnergiaRecuperada: 0.00739; ConsumoDeAguaDoce: 0.113; UtilizacaoLiquidaDeAguaDoce: 0.113; ResiduosPerigososEliminados: 0.00221; ResiduosNaoPerigososEliminados: 1.83; MassaTotalDeResiduosRadioactivosEliminados: 0.000394; EnergiaElectricaExportada: 1.55; MateriaisParaRecuperacaoDeEnergia: 0.00739; MateriaisParaReciclagem: 0.0253; UnidadeEPD: 1 m²
Type - IFC.REVIGRÉS-Dados gerais-Wall Covering - Nome: REVIGRÉS-OMNISTONE-BASE-45X90-SOFT-PLATINA; TipoProduto: Prensado a seco: grupo BIa UGL | Grés porcelânico técnico; NumeroDeRegistoDAP: EPD-REV-20240006-CCC1-EN; ReferenciaDAP: -; UrlDOP: -
Pset_WallCommon - ExtendToStructure: no; LoadBearing: no
IFC.REVIGRÉS-Dados do fabricante-Wall Covering - Type: Basic Wall: REVIGRÉS-OMNISTONE-BASE-45X90-SOFT-PLATINA
IFC.REVIGRÉS-Dados de desempenho-Wall Covering - Type: Basic Wall: REVIGRÉS-OMNISTONE-BASE-45X90-SOFT-PLATINA
IFC.REVIGRÉS-Dados de especificação-Wall Covering - Type: Basic Wall: REVIGRÉS-OMNISTONE-BASE-45X90-SOFT-PLATINA
IFC.REVIGRÉS-Dados geométricos-Wall Covering - Type: Basic Wall: REVIGRÉS-OMNISTONE-BASE-45X90-SOFT-PLATINA
IFC.REVIGRÉS-Dados de sustentabilidade-Wall Covering - Type: Basic Wall: REVIGRÉS-OMNISTONE-BASE-45X90-SOFT-PLATINA

# IfcWallStandardCase: Basic Wall:REVIGRÉS-OMNISTONE-BASE-45X90-SOFT-ROPE, Basic Wall:REVIGRÉS-OMNISTONE-BASE-45X90-SOFT-ROPE:151389
In: Level 1
Type - PredefinedType: STANDARD; Material: REVIGRÉS-OMNISTONE-BASE-45x90-SOFT-ROPE 10.5 mm
Type - Pset_ElementShading - Roughness: 304.8 mm
Type - Pset_ManufacturerTypeInformation - Manufacturer: REVIGRÉS
Type - Pset_ProductRequirements - Category: Walls
Type - Pset_QuantityTakeOff - Reference: 3126H893U1
Type - Pset_ReinforcementBarPitchOfWall - Description: Stone effect in wall and floor porcelain tile; Reference: 3126H893U1
Type - Pset_WallCommon - IsExternal: no; Reference: 3126H893U1
Type - IFC.REVIGRÉS-Dados do fabricante-Wall Covering - FabricanteURL: https://www.revigres.pt/; ReferenciaModelo: Omnistone; NumeroGlobalDeItemComercial: 3126H893U1; Acabamento: SOFT; Material: Grés porcelânico; IdentificadorDoOperadorEconomico: 501840856; UrlFabricanteArtigo: https://www.revigres.pt/colecoes/omnistone; PaisOrigem: Portugal
Type - IFC.REVIGRÉS-Dados de desempenho-Wall Covering - Rectilinearidade: ± 0.2% máx.± 0.8 mm; Ortogonalidade: ± 0.2% máx.± 1.5 mm; PlanaridadeDaSuperficie: ± 0.3% máx. ± 1.8 mm; QualidadeDaSuperficie: Cumpre; AbsorcaoDeAgua: < 0.05%; ModuloDeRuptura: > 45 N/mm130; ResistenciaAFlexao: ≥ 3500 N; ResistenciaAAbrasaoProfunda: < 120 mm131; DilatacaoTermicaLinear: ≤ 8,0x10-6 °C-1; ResistenciaAoChoqueTermico: Resiste; DurabilidadeResistenciaAoGeloDegelo: Resiste; ResistenciaAsManchas: Class 5; ResistenciaABaixasConcentracoesDeAcidosEAlcalis: Classe LA; ResistenciaAAltasConcentracoesDeAcidosEAlcalis: Classe HA; LibertacaoDeCadmio: 0; LibertacaoDeChumbo: 0
Type - IFC.REVIGRÉS-Dados de especificação-Wall Covering - VariacaoTonalidade: 3; NivelDeTrafego: 5; EPavimento: Sim; ERevestimento: Sim; EExterno: Sim
Type - IFC.REVIGRÉS-Dados geométricos-Wall Covering - AlturaNominal: 10.5 mm; ComprimentoNominal: 44.35 mm; LarguraNominal: 88.9 mm
Type - IFC.REVIGRÉS-Dados de sustentabilidade-Wall Covering - ItemEParcialmenteReciclado: 0; PotencialPrivacaoDeAguaConsumoDeAguaPonderado: 4.5; EnergiaTermicaExportada: 0; ItemENovo: Sim; ItemEReciclado: Não; VidaÚtilEsperada: 50; SubstanciasPerigosas: Não; PotencialDeEsgotamentoAbioticoDosRecursosNaoFosseisMineraisEMetais: 0.000701; PotencialDeAquecimentoGlobalBiogenico: -0.48; CombustiveisFosseisComPotencialDeAquecimentoGlobal: 13.9; PotencialDeAquecimentoGlobalUsoDoSoloEMudancaDeUsoDoSolo: 0.0246; PotencialDeEutrofizacaoFraccaoDeNutrientesQueAtingemOCompartimentoFinalDeAguaDoce: 0.000189; PotencialDeEutrofizacaoFraccaoDeNutrientesQueAtingemOCompartimentoFinalMarinho: 0.0122; EnergiaRecuperada: 0.00739; ConsumoDeAguaDoce: 0.113; UtilizacaoLiquidaDeAguaDoce: 0.113; ResiduosPerigososEliminados: 0.00221; ResiduosNaoPerigososEliminados: 1.83; MassaTotalDeResiduosRadioactivosEliminados: 0.000394; EnergiaElectricaExportada: 1.55; MateriaisParaRecuperacaoDeEnergia: 0.00739; MateriaisParaReciclagem: 0.0253; UnidadeEPD: 1 m²
Type - IFC.REVIGRÉS-Dados gerais-Wall Covering - Nome: REVIGRÉS-OMNISTONE-BASE-45X90-SOFT-ROPE; TipoProduto: Prensado a seco: grupo BIa UGL | Grés porcelânico técnico; NumeroDeRegistoDAP: EPD-REV-20240006-CCC1-EN; ReferenciaDAP: -; UrlDOP: -
Pset_WallCommon - ExtendToStructure: no; LoadBearing: no
IFC.REVIGRÉS-Dados do fabricante-Wall Covering - Type: Basic Wall: REVIGRÉS-OMNISTONE-BASE-45X90-SOFT-ROPE
IFC.REVIGRÉS-Dados de desempenho-Wall Covering - Type: Basic Wall: REVIGRÉS-OMNISTONE-BASE-45X90-SOFT-ROPE
IFC.REVIGRÉS-Dados de especificação-Wall Covering - Type: Basic Wall: REVIGRÉS-OMNISTONE-BASE-45X90-SOFT-ROPE
IFC.REVIGRÉS-Dados geométricos-Wall Covering - Type: Basic Wall: REVIGRÉS-OMNISTONE-BASE-45X90-SOFT-ROPE
IFC.REVIGRÉS-Dados de sustentabilidade-Wall Covering - Type: Basic Wall: REVIGRÉS-OMNISTONE-BASE-45X90-SOFT-ROPE

# IfcWallStandardCase: Basic Wall:REVIGRÉS-OMNISTONE-BASE-60X120-MATTRECT-BONE, Basic Wall:REVIGRÉS-OMNISTONE-BASE-60X120-MATTRECT-BONE:146361
In: Level 1
Type - PredefinedType: STANDARD; Material: REVIGRÉS-OMNISTONE-BASE-60x120-MATTRECT-BONE 9.8 mm
Type - Pset_ElementShading - Roughness: 304.8 mm
Type - Pset_ManufacturerTypeInformation - Manufacturer: REVIGRÉS
Type - Pset_ProductRequirements - Category: Walls
Type - Pset_QuantityTakeOff - Reference: 312B1388U1
Type - Pset_ReinforcementBarPitchOfWall - Description: Stone effect in wall and floor porcelain tile; Reference: 312B1388U1
Type - Pset_WallCommon - IsExternal: no; Reference: 312B1388U1
Type - IFC.REVIGRÉS-Dados do fabricante-Wall Covering - FabricanteURL: https://www.revigres.pt/; ReferenciaModelo: Omnistone; NumeroGlobalDeItemComercial: 312BD388U1; Acabamento: MATT RECT; Material: Grés porcelânico; IdentificadorDoOperadorEconomico: 501840856; UrlFabricanteArtigo: https://www.revigres.pt/colecoes/omnistone; PaisOrigem: Portugal
Type - IFC.REVIGRÉS-Dados de desempenho-Wall Covering - Rectilinearidade: ± 0.2% máx.± 0.8 mm; Ortogonalidade: ± 0.2% máx.± 1.5 mm; PlanaridadeDaSuperficie: ± 0.3% máx. ± 1.8 mm; QualidadeDaSuperficie: Cumpre; AbsorcaoDeAgua: < 0.05%; ModuloDeRuptura: > 45 N/mm130; ResistenciaAFlexao: ≥ 3500 N; ResistenciaAAbrasaoProfunda: < 120 mm131; DilatacaoTermicaLinear: ≤ 8,0x10-6 °C-1; ResistenciaAoChoqueTermico: Resiste; DurabilidadeResistenciaAoGeloDegelo: Resiste; ResistenciaAoEscorregamentoDIN51130: R10; ResistenciaAoEscorregamentoDIN51097: B; ResistenciaAoEscorregamentoENV51097: B; ResistenciaAoEscorregamentoENV12633: Class 2; ResistenciaAoEscorregamentoBS7976: >36; ResistenciaAoEscorregamentoANSIA1371: ≥0,42; ResistenciaAoDeslizamentoENV12633: Class 2; ResistenciaAoDeslizamentoBS7976: >36; ResistenciaAsManchas: Class 5; ResistenciaABaixasConcentracoesDeAcidosEAlcalis: Classe LA; ResistenciaAAltasConcentracoesDeAcidosEAlcalis: Classe HA; LibertacaoDeCadmio: 0; LibertacaoDeChumbo: 0
Type - IFC.REVIGRÉS-Dados de especificação-Wall Covering - VariacaoTonalidade: 3; NivelDeTrafego: 5; EPavimento: Sim; ERevestimento: Sim; EExterno: Sim
Type - IFC.REVIGRÉS-Dados geométricos-Wall Covering - AlturaNominal: 9.8 mm; ComprimentoNominal: 59.2 mm; LarguraNominal: 118.6 mm
Type - IFC.REVIGRÉS-Dados de sustentabilidade-Wall Covering - ItemEParcialmenteReciclado: 0; PotencialPrivacaoDeAguaConsumoDeAguaPonderado: 4.5; EnergiaTermicaExportada: 0; ItemENovo: Sim; ItemEReciclado: Não; VidaÚtilEsperada: 50; SubstanciasPerigosas: Não; PotencialDeEsgotamentoAbioticoDosRecursosNaoFosseisMineraisEMetais: 0.000701; PotencialDeAquecimentoGlobalBiogenico: -0.48; CombustiveisFosseisComPotencialDeAquecimentoGlobal: 13.9; PotencialDeAquecimentoGlobalUsoDoSoloEMudancaDeUsoDoSolo: 0.0246; PotencialDeEutrofizacaoFraccaoDeNutrientesQueAtingemOCompartimentoFinalDeAguaDoce: 0.000189; PotencialDeEutrofizacaoFraccaoDeNutrientesQueAtingemOCompartimentoFinalMarinho: 0.0122; EnergiaRecuperada: 0.00739; ConsumoDeAguaDoce: 0.113; UtilizacaoLiquidaDeAguaDoce: 0.113; ResiduosPerigososEliminados: 0.00221; ResiduosNaoPerigososEliminados: 1.83; MassaTotalDeResiduosRadioactivosEliminados: 0.000394; EnergiaElectricaExportada: 1.55; MateriaisParaRecuperacaoDeEnergia: 0.00739; MateriaisParaReciclagem: 0.0253; UnidadeEPD: 1 m²
Type - IFC.REVIGRÉS-Dados gerais-Wall Covering - Nome: REVIGRÉS-OMNISTONE-BASE-60X120-MATT RECT-BONE; TipoProduto: Prensado a seco: grupo BIa UGL | Grés porcelânico técnico; NumeroDeRegistoDAP: EPD-REV-20240006-CCC1-EN; ReferenciaDAP: -; UrlDOP: -
Pset_WallCommon - ExtendToStructure: no; LoadBearing: no
IFC.REVIGRÉS-Dados do fabricante-Wall Covering - Type: Basic Wall: REVIGRÉS-OMNISTONE-BASE-60X120-MATTRECT-BONE
IFC.REVIGRÉS-Dados de desempenho-Wall Covering - Type: Basic Wall: REVIGRÉS-OMNISTONE-BASE-60X120-MATTRECT-BONE
IFC.REVIGRÉS-Dados de especificação-Wall Covering - Type: Basic Wall: REVIGRÉS-OMNISTONE-BASE-60X120-MATTRECT-BONE
IFC.REVIGRÉS-Dados geométricos-Wall Covering - Type: Basic Wall: REVIGRÉS-OMNISTONE-BASE-60X120-MATTRECT-BONE
IFC.REVIGRÉS-Dados de sustentabilidade-Wall Covering - Type: Basic Wall: REVIGRÉS-OMNISTONE-BASE-60X120-MATTRECT-BONE

# IfcWallStandardCase: Basic Wall:REVIGRÉS-OMNISTONE-BASE-60X120-MATTRECT-ICE, Basic Wall:REVIGRÉS-OMNISTONE-BASE-60X120-MATTRECT-ICE:148440
In: Level 1
Type - PredefinedType: STANDARD; Material: REVIGRÉS-OMNISTONE-BASE-60x120-MATTRECT-ICE 9.8 mm
Type - Pset_ElementShading - Roughness: 304.8 mm
Type - Pset_ManufacturerTypeInformation - Manufacturer: REVIGRÉS
Type - Pset_ProductRequirements - Category: Walls
Type - Pset_QuantityTakeOff - Reference: 312B1389U1
Type - Pset_ReinforcementBarPitchOfWall - Description: Stone effect in wall and floor porcelain tile; Reference: 312B1389U1
Type - Pset_WallCommon - IsExternal: no; Reference: 312B1389U1
Type - IFC.REVIGRÉS-Dados do fabricante-Wall Covering - FabricanteURL: https://www.revigres.pt/; ReferenciaModelo: Omnistone; NumeroGlobalDeItemComercial: 312BD389U1; Acabamento: MATT RECT; Material: Grés porcelânico; IdentificadorDoOperadorEconomico: 501840856; UrlFabricanteArtigo: https://www.revigres.pt/colecoes/omnistone; PaisOrigem: Portugal
Type - IFC.REVIGRÉS-Dados de desempenho-Wall Covering - Rectilinearidade: ± 0.2% máx.± 0.8 mm; Ortogonalidade: ± 0.2% máx.± 1.5 mm; PlanaridadeDaSuperficie: ± 0.3% máx. ± 1.8 mm; QualidadeDaSuperficie: Cumpre; AbsorcaoDeAgua: < 0.05%; ModuloDeRuptura: > 45 N/mm130; ResistenciaAFlexao: ≥ 3500 N; ResistenciaAAbrasaoProfunda: < 120 mm131; DilatacaoTermicaLinear: ≤ 8,0x10-6 °C-1; ResistenciaAoChoqueTermico: Resiste; DurabilidadeResistenciaAoGeloDegelo: Resiste; ResistenciaAoEscorregamentoDIN51130: R10; ResistenciaAoEscorregamentoDIN51097: B; ResistenciaAoEscorregamentoENV51097: B; ResistenciaAoEscorregamentoENV12633: Class 2; ResistenciaAoEscorregamentoBS7976: >36; ResistenciaAoEscorregamentoANSIA1371: ≥0,42; ResistenciaAoDeslizamentoENV12633: Class 2; ResistenciaAoDeslizamentoBS7976: >36; ResistenciaAsManchas: Class 5; ResistenciaABaixasConcentracoesDeAcidosEAlcalis: Classe LA; ResistenciaAAltasConcentracoesDeAcidosEAlcalis: Classe HA; LibertacaoDeCadmio: 0; LibertacaoDeChumbo: 0
Type - IFC.REVIGRÉS-Dados de especificação-Wall Covering - VariacaoTonalidade: 3; NivelDeTrafego: 5; EPavimento: Sim; ERevestimento: Sim; EExterno: Sim
Type - IFC.REVIGRÉS-Dados geométricos-Wall Covering - AlturaNominal: 9.8 mm; ComprimentoNominal: 59.2 mm; LarguraNominal: 118.6 mm
Type - IFC.REVIGRÉS-Dados de sustentabilidade-Wall Covering - ItemEParcialmenteReciclado: 0; PotencialPrivacaoDeAguaConsumoDeAguaPonderado: 4.5; EnergiaTermicaExportada: 0; ItemENovo: Sim; ItemEReciclado: Não; VidaÚtilEsperada: 50; SubstanciasPerigosas: Não; PotencialDeEsgotamentoAbioticoDosRecursosNaoFosseisMineraisEMetais: 0.000701; PotencialDeAquecimentoGlobalBiogenico: -0.48; CombustiveisFosseisComPotencialDeAquecimentoGlobal: 13.9; PotencialDeAquecimentoGlobalUsoDoSoloEMudancaDeUsoDoSolo: 0.0246; PotencialDeEutrofizacaoFraccaoDeNutrientesQueAtingemOCompartimentoFinalDeAguaDoce: 0.000189; PotencialDeEutrofizacaoFraccaoDeNutrientesQueAtingemOCompartimentoFinalMarinho: 0.0122; EnergiaRecuperada: 0.00739; ConsumoDeAguaDoce: 0.113; UtilizacaoLiquidaDeAguaDoce: 0.113; ResiduosPerigososEliminados: 0.00221; ResiduosNaoPerigososEliminados: 1.83; MassaTotalDeResiduosRadioactivosEliminados: 0.000394; EnergiaElectricaExportada: 1.55; MateriaisParaRecuperacaoDeEnergia: 0.00739; MateriaisParaReciclagem: 0.0253; UnidadeEPD: 1 m²
Type - IFC.REVIGRÉS-Dados gerais-Wall Covering - Nome: REVIGRÉS-OMNISTONE-BASE-60X120-MATT RECT-ICE; TipoProduto: Prensado a seco: grupo BIa UGL | Grés porcelânico técnico; NumeroDeRegistoDAP: EPD-REV-20240006-CCC1-EN; ReferenciaDAP: -; UrlDOP: -
Pset_WallCommon - ExtendToStructure: no; LoadBearing: no
IFC.REVIGRÉS-Dados do fabricante-Wall Covering - Type: Basic Wall: REVIGRÉS-OMNISTONE-BASE-60X120-MATTRECT-ICE
IFC.REVIGRÉS-Dados de desempenho-Wall Covering - Type: Basic Wall: REVIGRÉS-OMNISTONE-BASE-60X120-MATTRECT-ICE
IFC.REVIGRÉS-Dados de especificação-Wall Covering - Type: Basic Wall: REVIGRÉS-OMNISTONE-BASE-60X120-MATTRECT-ICE
IFC.REVIGRÉS-Dados geométricos-Wall Covering - Type: Basic Wall: REVIGRÉS-OMNISTONE-BASE-60X120-MATTRECT-ICE
IFC.REVIGRÉS-Dados de sustentabilidade-Wall Covering - Type: Basic Wall: REVIGRÉS-OMNISTONE-BASE-60X120-MATTRECT-ICE

# IfcWallStandardCase: Basic Wall:REVIGRÉS-OMNISTONE-BASE-60X120-MATTRECT-IRON, Basic Wall:REVIGRÉS-OMNISTONE-BASE-60X120-MATTRECT-IRON:149133
In: Level 1
Type - PredefinedType: STANDARD; Material: REVIGRÉS-OMNISTONE-BASE-60x120-MATTRECT-IRON 9.8 mm
Type - Pset_ElementShading - Roughness: 304.8 mm
Type - Pset_ManufacturerTypeInformation - Manufacturer: REVIGRÉS
Type - Pset_ProductRequirements - Category: Walls
Type - Pset_QuantityTakeOff - Reference: 312B1390U1
Type - Pset_ReinforcementBarPitchOfWall - Description: Stone effect in wall and floor porcelain tile; Reference: 312B1390U1
Type - Pset_WallCommon - IsExternal: no; Reference: 312B1390U1
Type - IFC.REVIGRÉS-Dados do fabricante-Wall Covering - FabricanteURL: https://www.revigres.pt/; ReferenciaModelo: Omnistone; NumeroGlobalDeItemComercial: 312BD390U1; Acabamento: MATT RECT; Material: Grés porcelânico; IdentificadorDoOperadorEconomico: 501840856; UrlFabricanteArtigo: https://www.revigres.pt/colecoes/omnistone; PaisOrigem: Portugal
Type - IFC.REVIGRÉS-Dados de desempenho-Wall Covering - Rectilinearidade: ± 0.2% máx.± 0.8 mm; Ortogonalidade: ± 0.2% máx.± 1.5 mm; PlanaridadeDaSuperficie: ± 0.3% máx. ± 1.8 mm; QualidadeDaSuperficie: Cumpre; AbsorcaoDeAgua: < 0.05%; ModuloDeRuptura: > 45 N/mm130; ResistenciaAFlexao: ≥ 3500 N; ResistenciaAAbrasaoProfunda: < 120 mm131; DilatacaoTermicaLinear: ≤ 8,0x10-6 °C-1; ResistenciaAoChoqueTermico: Resiste; DurabilidadeResistenciaAoGeloDegelo: Resiste; ResistenciaAoEscorregamentoDIN51130: R10; ResistenciaAoEscorregamentoDIN51097: B; ResistenciaAoEscorregamentoENV51097: B; ResistenciaAoEscorregamentoENV12633: Class 2; ResistenciaAoEscorregamentoBS7976: >36; ResistenciaAoEscorregamentoANSIA1371: ≥0,42; ResistenciaAoDeslizamentoENV12633: Class 2; ResistenciaAoDeslizamentoBS7976: >36; ResistenciaAsManchas: Class 5; ResistenciaABaixasConcentracoesDeAcidosEAlcalis: Classe LA; ResistenciaAAltasConcentracoesDeAcidosEAlcalis: Classe HA; LibertacaoDeCadmio: 0; LibertacaoDeChumbo: 0
Type - IFC.REVIGRÉS-Dados de especificação-Wall Covering - VariacaoTonalidade: 3; NivelDeTrafego: 5; EPavimento: Sim; ERevestimento: Sim; EExterno: Sim
Type - IFC.REVIGRÉS-Dados geométricos-Wall Covering - AlturaNominal: 9.8 mm; ComprimentoNominal: 59.2 mm; LarguraNominal: 118.6 mm
Type - IFC.REVIGRÉS-Dados de sustentabilidade-Wall Covering - PotencialPrivacaoDeAguaConsumoDeAguaPonderado: 4.5; EnergiaTermicaExportada: 0; ItemENovo: Sim; ItemEParcialmenteReciclado: 0.14; ItemEReciclado: Sim; VidaÚtilEsperada: 50; SubstanciasPerigosas: Não; PotencialDeEsgotamentoAbioticoDosRecursosNaoFosseisMineraisEMetais: 0.000701; PotencialDeAquecimentoGlobalBiogenico: -0.48; CombustiveisFosseisComPotencialDeAquecimentoGlobal: 13.9; PotencialDeAquecimentoGlobalUsoDoSoloEMudancaDeUsoDoSolo: 0.0246; PotencialDeEutrofizacaoFraccaoDeNutrientesQueAtingemOCompartimentoFinalDeAguaDoce: 0.000189; PotencialDeEutrofizacaoFraccaoDeNutrientesQueAtingemOCompartimentoFinalMarinho: 0.0122; EnergiaRecuperada: 0.00739; ConsumoDeAguaDoce: 0.113; UtilizacaoLiquidaDeAguaDoce: 0.113; ResiduosPerigososEliminados: 0.00221; ResiduosNaoPerigososEliminados: 1.83; MassaTotalDeResiduosRadioactivosEliminados: 0.000394; EnergiaElectricaExportada: 1.55; MateriaisParaRecuperacaoDeEnergia: 0.00739; MateriaisParaReciclagem: 0.0253; UnidadeEPD: 1 m²
Type - IFC.REVIGRÉS-Dados gerais-Wall Covering - Nome: REVIGRÉS-OMNISTONE-BASE-60X120-MATT RECT-IRON; TipoProduto: Prensado a seco: grupo BIa UGL | Grés porcelânico técnico; NumeroDeRegistoDAP: EPD-REV-20240006-CCC1-EN; ReferenciaDAP: -; UrlDOP: -
Pset_WallCommon - ExtendToStructure: no; LoadBearing: no
IFC.REVIGRÉS-Dados do fabricante-Wall Covering - Type: Basic Wall: REVIGRÉS-OMNISTONE-BASE-60X120-MATTRECT-IRON
IFC.REVIGRÉS-Dados de desempenho-Wall Covering - Type: Basic Wall: REVIGRÉS-OMNISTONE-BASE-60X120-MATTRECT-IRON
IFC.REVIGRÉS-Dados de especificação-Wall Covering - Type: Basic Wall: REVIGRÉS-OMNISTONE-BASE-60X120-MATTRECT-IRON
IFC.REVIGRÉS-Dados geométricos-Wall Covering - Type: Basic Wall: REVIGRÉS-OMNISTONE-BASE-60X120-MATTRECT-IRON
IFC.REVIGRÉS-Dados de sustentabilidade-Wall Covering - Type: Basic Wall: REVIGRÉS-OMNISTONE-BASE-60X120-MATTRECT-IRON

# IfcWallStandardCase: Basic Wall:REVIGRÉS-OMNISTONE-BASE-60X120-MATTRECT-JET, Basic Wall:REVIGRÉS-OMNISTONE-BASE-60X120-MATTRECT-JET:149875
In: Level 1
Type - PredefinedType: STANDARD; Material: REVIGRÉS-OMNISTONE-BASE-60x120-MATTRECT-JET 9.8 mm
Type - Pset_ElementShading - Roughness: 304.8 mm
Type - Pset_ManufacturerTypeInformation - Manufacturer: REVIGRÉS
Type - Pset_ProductRequirements - Category: Walls
Type - Pset_QuantityTakeOff - Reference: 312B1391U1
Type - Pset_ReinforcementBarPitchOfWall - Description: Stone effect in wall and floor porcelain tile; Reference: 312B1391U1
Type - Pset_WallCommon - IsExternal: no; Reference: 312B1391U1
Type - IFC.REVIGRÉS-Dados do fabricante-Wall Covering - FabricanteURL: https://www.revigres.pt/; ReferenciaModelo: Omnistone; NumeroGlobalDeItemComercial: 312BD391U1; Acabamento: MATT RECT; Material: Grés porcelânico; IdentificadorDoOperadorEconomico: 501840856; UrlFabricanteArtigo: https://www.revigres.pt/colecoes/omnistone; PaisOrigem: Portugal
Type - IFC.REVIGRÉS-Dados de desempenho-Wall Covering - Rectilinearidade: ± 0.2% máx.± 0.8 mm; Ortogonalidade: ± 0.2% máx.± 1.5 mm; PlanaridadeDaSuperficie: ± 0.3% máx. ± 1.8 mm; QualidadeDaSuperficie: Cumpre; AbsorcaoDeAgua: < 0.05%; ModuloDeRuptura: > 45 N/mm130; ResistenciaAFlexao: ≥ 3500 N; ResistenciaAAbrasaoProfunda: < 120 mm131; DilatacaoTermicaLinear: ≤ 8,0x10-6 °C-1; ResistenciaAoChoqueTermico: Resiste; DurabilidadeResistenciaAoGeloDegelo: Resiste; ResistenciaAoEscorregamentoDIN51130: R10; ResistenciaAoEscorregamentoDIN51097: B; ResistenciaAoEscorregamentoENV51097: B; ResistenciaAoEscorregamentoENV12633: Class 2; ResistenciaAoEscorregamentoBS7976: >36; ResistenciaAoEscorregamentoANSIA1371: ≥0,42; ResistenciaAoDeslizamentoENV12633: Class 2; ResistenciaAoDeslizamentoBS7976: >36; ResistenciaAsManchas: Class 5; ResistenciaABaixasConcentracoesDeAcidosEAlcalis: Classe LA; ResistenciaAAltasConcentracoesDeAcidosEAlcalis: Classe HA; LibertacaoDeCadmio: 0; LibertacaoDeChumbo: 0
Type - IFC.REVIGRÉS-Dados de especificação-Wall Covering - VariacaoTonalidade: 3; NivelDeTrafego: 5; EPavimento: Sim; ERevestimento: Sim; EExterno: Sim
Type - IFC.REVIGRÉS-Dados geométricos-Wall Covering - AlturaNominal: 9.8 mm; ComprimentoNominal: 59.2 mm; LarguraNominal: 118.6 mm
Type - IFC.REVIGRÉS-Dados de sustentabilidade-Wall Covering - ItemEParcialmenteReciclado: 0; PotencialPrivacaoDeAguaConsumoDeAguaPonderado: 4.5; EnergiaTermicaExportada: 0; ItemENovo: Sim; ItemEReciclado: Não; VidaÚtilEsperada: 50; SubstanciasPerigosas: Não; PotencialDeEsgotamentoAbioticoDosRecursosNaoFosseisMineraisEMetais: 0.000701; PotencialDeAquecimentoGlobalBiogenico: -0.48; CombustiveisFosseisComPotencialDeAquecimentoGlobal: 13.9; PotencialDeAquecimentoGlobalUsoDoSoloEMudancaDeUsoDoSolo: 0.0246; PotencialDeEutrofizacaoFraccaoDeNutrientesQueAtingemOCompartimentoFinalDeAguaDoce: 0.000189; PotencialDeEutrofizacaoFraccaoDeNutrientesQueAtingemOCompartimentoFinalMarinho: 0.0122; EnergiaRecuperada: 0.00739; ConsumoDeAguaDoce: 0.113; UtilizacaoLiquidaDeAguaDoce: 0.113; ResiduosPerigososEliminados: 0.00221; ResiduosNaoPerigososEliminados: 1.83; MassaTotalDeResiduosRadioactivosEliminados: 0.000394; EnergiaElectricaExportada: 1.55; MateriaisParaRecuperacaoDeEnergia: 0.00739; MateriaisParaReciclagem: 0.0253; UnidadeEPD: 1 m²
Type - IFC.REVIGRÉS-Dados gerais-Wall Covering - Nome: REVIGRÉS-OMNISTONE-BASE-60X120-MATT RECT-JET; TipoProduto: Prensado a seco: grupo BIa UGL | Grés porcelânico técnico; NumeroDeRegistoDAP: EPD-REV-20240006-CCC1-EN; ReferenciaDAP: -; UrlDOP: -
Pset_WallCommon - ExtendToStructure: no; LoadBearing: no
IFC.REVIGRÉS-Dados do fabricante-Wall Covering - Type: Basic Wall: REVIGRÉS-OMNISTONE-BASE-60X120-MATTRECT-JET
IFC.REVIGRÉS-Dados de desempenho-Wall Covering - Type: Basic Wall: REVIGRÉS-OMNISTONE-BASE-60X120-MATTRECT-JET
IFC.REVIGRÉS-Dados de especificação-Wall Covering - Type: Basic Wall: REVIGRÉS-OMNISTONE-BASE-60X120-MATTRECT-JET
IFC.REVIGRÉS-Dados geométricos-Wall Covering - Type: Basic Wall: REVIGRÉS-OMNISTONE-BASE-60X120-MATTRECT-JET
IFC.REVIGRÉS-Dados de sustentabilidade-Wall Covering - Type: Basic Wall: REVIGRÉS-OMNISTONE-BASE-60X120-MATTRECT-JET

# IfcWallStandardCase: Basic Wall:REVIGRÉS-OMNISTONE-BASE-60X120-MATTRECT-PLATINA, Basic Wall:REVIGRÉS-OMNISTONE-BASE-60X120-MATTRECT-PLATINA:150596
In: Level 1
Type - PredefinedType: STANDARD; Material: REVIGRÉS-OMNISTONE-BASE-60x120-MATTRECT-PLATINA 9.8 mm
Type - Pset_ElementShading - Roughness: 304.8 mm
Type - Pset_ManufacturerTypeInformation - Manufacturer: REVIGRÉS
Type - Pset_ProductRequirements - Category: Walls
Type - Pset_QuantityTakeOff - Reference: 312B1392U1
Type - Pset_ReinforcementBarPitchOfWall - Description: Stone effect in wall and floor porcelain tile; Reference: 312B1392U1
Type - Pset_WallCommon - IsExternal: no; Reference: 312B1392U1
Type - IFC.REVIGRÉS-Dados do fabricante-Wall Covering - FabricanteURL: https://www.revigres.pt/; ReferenciaModelo: Omnistone; NumeroGlobalDeItemComercial: 312BD392U1; Acabamento: MATT RECT; Material: Grés porcelânico; IdentificadorDoOperadorEconomico: 501840856; UrlFabricanteArtigo: https://www.revigres.pt/colecoes/omnistone; PaisOrigem: Portugal
Type - IFC.REVIGRÉS-Dados de desempenho-Wall Covering - Rectilinearidade: ± 0.2% máx.± 0.8 mm; Ortogonalidade: ± 0.2% máx.± 1.5 mm; PlanaridadeDaSuperficie: ± 0.3% máx. ± 1.8 mm; QualidadeDaSuperficie: Cumpre; AbsorcaoDeAgua: < 0.05%; ModuloDeRuptura: > 45 N/mm130; ResistenciaAFlexao: ≥ 3500 N; ResistenciaAAbrasaoProfunda: < 120 mm131; DilatacaoTermicaLinear: ≤ 8,0x10-6 °C-1; ResistenciaAoChoqueTermico: Resiste; DurabilidadeResistenciaAoGeloDegelo: Resiste; ResistenciaAoEscorregamentoDIN51130: R10; ResistenciaAoEscorregamentoDIN51097: B; ResistenciaAoEscorregamentoENV51097: B; ResistenciaAoEscorregamentoENV12633: Class 2; ResistenciaAoEscorregamentoBS7976: >36; ResistenciaAoEscorregamentoANSIA1371: ≥0,42; ResistenciaAoDeslizamentoENV12633: Class 2; ResistenciaAoDeslizamentoBS7976: >36; ResistenciaAsManchas: Class 5; ResistenciaABaixasConcentracoesDeAcidosEAlcalis: Classe LA; ResistenciaAAltasConcentracoesDeAcidosEAlcalis: Classe HA; LibertacaoDeCadmio: 0; LibertacaoDeChumbo: 0
Type - IFC.REVIGRÉS-Dados de especificação-Wall Covering - VariacaoTonalidade: 3; NivelDeTrafego: 5; EPavimento: Sim; ERevestimento: Sim; EExterno: Sim
Type - IFC.REVIGRÉS-Dados geométricos-Wall Covering - AlturaNominal: 9.8 mm; ComprimentoNominal: 59.2 mm; LarguraNominal: 118.6 mm
Type - IFC.REVIGRÉS-Dados de sustentabilidade-Wall Covering - ItemEParcialmenteReciclado: 0; PotencialPrivacaoDeAguaConsumoDeAguaPonderado: 4.5; EnergiaTermicaExportada: 0; ItemENovo: Sim; ItemEReciclado: Não; VidaÚtilEsperada: 50; SubstanciasPerigosas: Não; PotencialDeEsgotamentoAbioticoDosRecursosNaoFosseisMineraisEMetais: 0.000701; PotencialDeAquecimentoGlobalBiogenico: -0.48; CombustiveisFosseisComPotencialDeAquecimentoGlobal: 13.9; PotencialDeAquecimentoGlobalUsoDoSoloEMudancaDeUsoDoSolo: 0.0246; PotencialDeEutrofizacaoFraccaoDeNutrientesQueAtingemOCompartimentoFinalDeAguaDoce: 0.000189; PotencialDeEutrofizacaoFraccaoDeNutrientesQueAtingemOCompartimentoFinalMarinho: 0.0122; EnergiaRecuperada: 0.00739; ConsumoDeAguaDoce: 0.113; UtilizacaoLiquidaDeAguaDoce: 0.113; ResiduosPerigososEliminados: 0.00221; ResiduosNaoPerigososEliminados: 1.83; MassaTotalDeResiduosRadioactivosEliminados: 0.000394; EnergiaElectricaExportada: 1.55; MateriaisParaRecuperacaoDeEnergia: 0.00739; MateriaisParaReciclagem: 0.0253; UnidadeEPD: 1 m²
Type - IFC.REVIGRÉS-Dados gerais-Wall Covering - Nome: REVIGRÉS-OMNISTONE-BASE-60X120-MATT RECT-PLATINA; TipoProduto: Prensado a seco: grupo BIa UGL | Grés porcelânico técnico; NumeroDeRegistoDAP: EPD-REV-20240006-CCC1-EN; ReferenciaDAP: -; UrlDOP: -
Pset_WallCommon - ExtendToStructure: no; LoadBearing: no
IFC.REVIGRÉS-Dados do fabricante-Wall Covering - Type: Basic Wall: REVIGRÉS-OMNISTONE-BASE-60X120-MATTRECT-PLATINA
IFC.REVIGRÉS-Dados de desempenho-Wall Covering - Type: Basic Wall: REVIGRÉS-OMNISTONE-BASE-60X120-MATTRECT-PLATINA
IFC.REVIGRÉS-Dados de especificação-Wall Covering - Type: Basic Wall: REVIGRÉS-OMNISTONE-BASE-60X120-MATTRECT-PLATINA
IFC.REVIGRÉS-Dados geométricos-Wall Covering - Type: Basic Wall: REVIGRÉS-OMNISTONE-BASE-60X120-MATTRECT-PLATINA
IFC.REVIGRÉS-Dados de sustentabilidade-Wall Covering - Type: Basic Wall: REVIGRÉS-OMNISTONE-BASE-60X120-MATTRECT-PLATINA

# IfcWallStandardCase: Basic Wall:REVIGRÉS-OMNISTONE-BASE-60X120-MATTRECT-ROPE, Basic Wall:REVIGRÉS-OMNISTONE-BASE-60X120-MATTRECT-ROPE:151301
In: Level 1
Type - PredefinedType: STANDARD; Material: REVIGRÉS-OMNISTONE-BASE-60x120-MATTRECT-ROPE 9.8 mm
Type - Pset_ElementShading - Roughness: 304.8 mm
Type - Pset_ManufacturerTypeInformation - Manufacturer: REVIGRÉS
Type - Pset_ProductRequirements - Category: Walls
Type - Pset_QuantityTakeOff - Reference: 312B1393U1
Type - Pset_ReinforcementBarPitchOfWall - Description: Stone effect in wall and floor porcelain tile; Reference: 312B1393U1
Type - Pset_WallCommon - IsExternal: no; Reference: 312B1393U1
Type - IFC.REVIGRÉS-Dados do fabricante-Wall Covering - FabricanteURL: https://www.revigres.pt/; ReferenciaModelo: Omnistone; NumeroGlobalDeItemComercial: 312BD393U1; Acabamento: MATT RECT; Material: Grés porcelânico; IdentificadorDoOperadorEconomico: 501840856; UrlFabricanteArtigo: https://www.revigres.pt/colecoes/omnistone; PaisOrigem: Portugal
Type - IFC.REVIGRÉS-Dados de desempenho-Wall Covering - Rectilinearidade: ± 0.2% máx.± 0.8 mm; Ortogonalidade: ± 0.2% máx.± 1.5 mm; PlanaridadeDaSuperficie: ± 0.3% máx. ± 1.8 mm; QualidadeDaSuperficie: Cumpre; AbsorcaoDeAgua: < 0.05%; ModuloDeRuptura: > 45 N/mm130; ResistenciaAFlexao: ≥ 3500 N; ResistenciaAAbrasaoProfunda: < 120 mm131; DilatacaoTermicaLinear: ≤ 8,0x10-6 °C-1; ResistenciaAoChoqueTermico: Resiste; DurabilidadeResistenciaAoGeloDegelo: Resiste; ResistenciaAoEscorregamentoDIN51130: R10; ResistenciaAoEscorregamentoDIN51097: B; ResistenciaAoEscorregamentoENV51097: B; ResistenciaAoEscorregamentoENV12633: Class 2; ResistenciaAoEscorregamentoBS7976: >36; ResistenciaAoEscorregamentoANSIA1371: ≥0,42; ResistenciaAoDeslizamentoENV12633: Class 2; ResistenciaAoDeslizamentoBS7976: >36; ResistenciaAsManchas: Class 5; ResistenciaABaixasConcentracoesDeAcidosEAlcalis: Classe LA; ResistenciaAAltasConcentracoesDeAcidosEAlcalis: Classe HA; LibertacaoDeCadmio: 0; LibertacaoDeChumbo: 0
Type - IFC.REVIGRÉS-Dados de especificação-Wall Covering - VariacaoTonalidade: 3; NivelDeTrafego: 5; EPavimento: Sim; ERevestimento: Sim; EExterno: Sim
Type - IFC.REVIGRÉS-Dados geométricos-Wall Covering - AlturaNominal: 9.8 mm; ComprimentoNominal: 59.2 mm; LarguraNominal: 118.6 mm
Type - IFC.REVIGRÉS-Dados de sustentabilidade-Wall Covering - ItemEParcialmenteReciclado: 0; PotencialPrivacaoDeAguaConsumoDeAguaPonderado: 4.5; EnergiaTermicaExportada: 0; ItemENovo: Sim; ItemEReciclado: Não; VidaÚtilEsperada: 50; SubstanciasPerigosas: Não; PotencialDeEsgotamentoAbioticoDosRecursosNaoFosseisMineraisEMetais: 0.000701; PotencialDeAquecimentoGlobalBiogenico: -0.48; CombustiveisFosseisComPotencialDeAquecimentoGlobal: 13.9; PotencialDeAquecimentoGlobalUsoDoSoloEMudancaDeUsoDoSolo: 0.0246; PotencialDeEutrofizacaoFraccaoDeNutrientesQueAtingemOCompartimentoFinalDeAguaDoce: 0.000189; PotencialDeEutrofizacaoFraccaoDeNutrientesQueAtingemOCompartimentoFinalMarinho: 0.0122; EnergiaRecuperada: 0.00739; ConsumoDeAguaDoce: 0.113; UtilizacaoLiquidaDeAguaDoce: 0.113; ResiduosPerigososEliminados: 0.00221; ResiduosNaoPerigososEliminados: 1.83; MassaTotalDeResiduosRadioactivosEliminados: 0.000394; EnergiaElectricaExportada: 1.55; MateriaisParaRecuperacaoDeEnergia: 0.00739; MateriaisParaReciclagem: 0.0253; UnidadeEPD: 1 m²
Type - IFC.REVIGRÉS-Dados gerais-Wall Covering - Nome: REVIGRÉS-OMNISTONE-BASE-60X120-MATT RECT-ROPE; TipoProduto: Prensado a seco: grupo BIa UGL | Grés porcelânico técnico; NumeroDeRegistoDAP: EPD-REV-20240006-CCC1-EN; ReferenciaDAP: -; UrlDOP: -
Pset_WallCommon - ExtendToStructure: no; LoadBearing: no
IFC.REVIGRÉS-Dados do fabricante-Wall Covering - Type: Basic Wall: REVIGRÉS-OMNISTONE-BASE-60X120-MATTRECT-ROPE
IFC.REVIGRÉS-Dados de desempenho-Wall Covering - Type: Basic Wall: REVIGRÉS-OMNISTONE-BASE-60X120-MATTRECT-ROPE
IFC.REVIGRÉS-Dados de especificação-Wall Covering - Type: Basic Wall: REVIGRÉS-OMNISTONE-BASE-60X120-MATTRECT-ROPE
IFC.REVIGRÉS-Dados geométricos-Wall Covering - Type: Basic Wall: REVIGRÉS-OMNISTONE-BASE-60X120-MATTRECT-ROPE
IFC.REVIGRÉS-Dados de sustentabilidade-Wall Covering - Type: Basic Wall: REVIGRÉS-OMNISTONE-BASE-60X120-MATTRECT-ROPE

# IfcWallStandardCase: Basic Wall:REVIGRÉS-OMNISTONE-BASE-60X120-SOFT-BONE, Basic Wall:REVIGRÉS-OMNISTONE-BASE-60X120-SOFT-BONE:146519
In: Level 1
Type - PredefinedType: STANDARD; Material: REVIGRÉS-OMNISTONE-BASE-60x120-SOFT-BONE 9.8 mm
Type - Pset_ElementShading - Roughness: 304.8 mm
Type - Pset_ManufacturerTypeInformation - Manufacturer: REVIGRÉS
Type - Pset_ProductRequirements - Category: Walls
Type - Pset_QuantityTakeOff - Reference: 31261388U1
Type - Pset_ReinforcementBarPitchOfWall - Description: Stone effect in wall and floor porcelain tile; Reference: 31261388U1
Type - Pset_WallCommon - IsExternal: no; Reference: 31261388U1
Type - IFC.REVIGRÉS-Dados do fabricante-Wall Covering - FabricanteURL: https://www.revigres.pt/; ReferenciaModelo: Omnistone; NumeroGlobalDeItemComercial: 3126D388U1; Acabamento: SOFT; Material: Grés porcelânico; IdentificadorDoOperadorEconomico: 501840856; UrlFabricanteArtigo: https://www.revigres.pt/colecoes/omnistone; PaisOrigem: Portugal
Type - IFC.REVIGRÉS-Dados de desempenho-Wall Covering - Rectilinearidade: ± 0.2% máx.± 0.8 mm; Ortogonalidade: ± 0.2% máx.± 1.5 mm; PlanaridadeDaSuperficie: ± 0.3% máx. ± 1.8 mm; QualidadeDaSuperficie: Cumpre; AbsorcaoDeAgua: < 0.05%; ModuloDeRuptura: > 45 N/mm130; ResistenciaAFlexao: ≥ 3500 N; ResistenciaAAbrasaoProfunda: < 120 mm131; DilatacaoTermicaLinear: ≤ 8,0x10-6 °C-1; ResistenciaAoChoqueTermico: Resiste; DurabilidadeResistenciaAoGeloDegelo: Resiste; ResistenciaAsManchas: Class 5; ResistenciaABaixasConcentracoesDeAcidosEAlcalis: Classe LA; ResistenciaAAltasConcentracoesDeAcidosEAlcalis: Classe HA; LibertacaoDeCadmio: 0; LibertacaoDeChumbo: 0
Type - IFC.REVIGRÉS-Dados de especificação-Wall Covering - VariacaoTonalidade: 3; NivelDeTrafego: 5; EPavimento: Sim; ERevestimento: Sim; EExterno: Sim
Type - IFC.REVIGRÉS-Dados geométricos-Wall Covering - AlturaNominal: 9.8 mm; ComprimentoNominal: 59.2 mm; LarguraNominal: 118.6 mm
Type - IFC.REVIGRÉS-Dados de sustentabilidade-Wall Covering - ItemEParcialmenteReciclado: 0; PotencialPrivacaoDeAguaConsumoDeAguaPonderado: 4.5; EnergiaTermicaExportada: 0; ItemENovo: Sim; ItemEReciclado: Não; VidaÚtilEsperada: 50; SubstanciasPerigosas: Não; PotencialDeEsgotamentoAbioticoDosRecursosNaoFosseisMineraisEMetais: 0.000701; PotencialDeAquecimentoGlobalBiogenico: -0.48; CombustiveisFosseisComPotencialDeAquecimentoGlobal: 13.9; PotencialDeAquecimentoGlobalUsoDoSoloEMudancaDeUsoDoSolo: 0.0246; PotencialDeEutrofizacaoFraccaoDeNutrientesQueAtingemOCompartimentoFinalDeAguaDoce: 0.000189; PotencialDeEutrofizacaoFraccaoDeNutrientesQueAtingemOCompartimentoFinalMarinho: 0.0122; EnergiaRecuperada: 0.00739; ConsumoDeAguaDoce: 0.113; UtilizacaoLiquidaDeAguaDoce: 0.113; ResiduosPerigososEliminados: 0.00221; ResiduosNaoPerigososEliminados: 1.83; MassaTotalDeResiduosRadioactivosEliminados: 0.000394; EnergiaElectricaExportada: 1.55; MateriaisParaRecuperacaoDeEnergia: 0.00739; MateriaisParaReciclagem: 0.0253; UnidadeEPD: 1 m²
Type - IFC.REVIGRÉS-Dados gerais-Wall Covering - Nome: REVIGRÉS-OMNISTONE-BASE-60X120-SOFT-BONE; TipoProduto: Prensado a seco: grupo BIa UGL | Grés porcelânico técnico; NumeroDeRegistoDAP: EPD-REV-20240006-CCC1-EN; ReferenciaDAP: -; UrlDOP: -
Pset_WallCommon - ExtendToStructure: no; LoadBearing: no
IFC.REVIGRÉS-Dados do fabricante-Wall Covering - Type: Basic Wall: REVIGRÉS-OMNISTONE-BASE-60X120-SOFT-BONE
IFC.REVIGRÉS-Dados de desempenho-Wall Covering - Type: Basic Wall: REVIGRÉS-OMNISTONE-BASE-60X120-SOFT-BONE
IFC.REVIGRÉS-Dados de especificação-Wall Covering - Type: Basic Wall: REVIGRÉS-OMNISTONE-BASE-60X120-SOFT-BONE
IFC.REVIGRÉS-Dados geométricos-Wall Covering - Type: Basic Wall: REVIGRÉS-OMNISTONE-BASE-60X120-SOFT-BONE
IFC.REVIGRÉS-Dados de sustentabilidade-Wall Covering - Type: Basic Wall: REVIGRÉS-OMNISTONE-BASE-60X120-SOFT-BONE

# IfcWallStandardCase: Basic Wall:REVIGRÉS-OMNISTONE-BASE-60X120-SOFT-ICE, Basic Wall:REVIGRÉS-OMNISTONE-BASE-60X120-SOFT-ICE:148528
In: Level 1
Type - PredefinedType: STANDARD; Material: REVIGRÉS-OMNISTONE-BASE-60x120-SOFT-ICE 9.8 mm
Type - Pset_ElementShading - Roughness: 304.8 mm
Type - Pset_ManufacturerTypeInformation - Manufacturer: REVIGRÉS
Type - Pset_ProductRequirements - Category: Walls
Type - Pset_QuantityTakeOff - Reference: 31261389U1
Type - Pset_ReinforcementBarPitchOfWall - Description: Stone effect in wall and floor porcelain tile; Reference: 31261389U1
Type - Pset_WallCommon - IsExternal: no; Reference: 31261389U1
Type - IFC.REVIGRÉS-Dados do fabricante-Wall Covering - FabricanteURL: https://www.revigres.pt/; ReferenciaModelo: Omnistone; NumeroGlobalDeItemComercial: 3126D389U1; Acabamento: SOFT; Material: Grés porcelânico; IdentificadorDoOperadorEconomico: 501840856; UrlFabricanteArtigo: https://www.revigres.pt/colecoes/omnistone; PaisOrigem: Portugal
Type - IFC.REVIGRÉS-Dados de desempenho-Wall Covering - Rectilinearidade: ± 0.2% máx.± 0.8 mm; Ortogonalidade: ± 0.2% máx.± 1.5 mm; PlanaridadeDaSuperficie: ± 0.3% máx. ± 1.8 mm; QualidadeDaSuperficie: Cumpre; AbsorcaoDeAgua: < 0.05%; ModuloDeRuptura: > 45 N/mm130; ResistenciaAFlexao: ≥ 3500 N; ResistenciaAAbrasaoProfunda: < 120 mm131; DilatacaoTermicaLinear: ≤ 8,0x10-6 °C-1; ResistenciaAoChoqueTermico: Resiste; DurabilidadeResistenciaAoGeloDegelo: Resiste; ResistenciaAsManchas: Class 5; ResistenciaABaixasConcentracoesDeAcidosEAlcalis: Classe LA; ResistenciaAAltasConcentracoesDeAcidosEAlcalis: Classe HA; LibertacaoDeCadmio: 0; LibertacaoDeChumbo: 0
Type - IFC.REVIGRÉS-Dados de especificação-Wall Covering - VariacaoTonalidade: 3; NivelDeTrafego: 5; EPavimento: Sim; ERevestimento: Sim; EExterno: Sim
Type - IFC.REVIGRÉS-Dados geométricos-Wall Covering - AlturaNominal: 9.8 mm; ComprimentoNominal: 59.2 mm; LarguraNominal: 118.6 mm
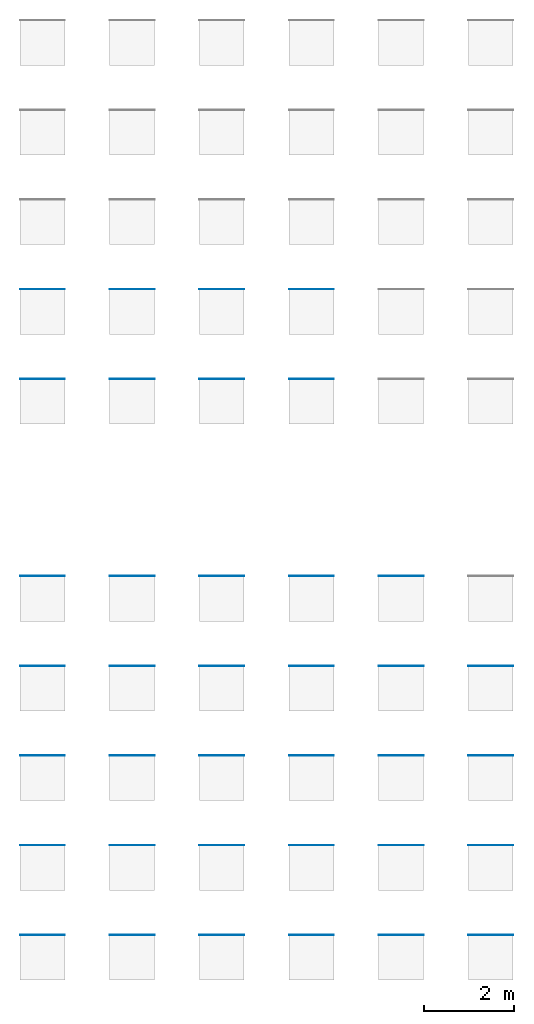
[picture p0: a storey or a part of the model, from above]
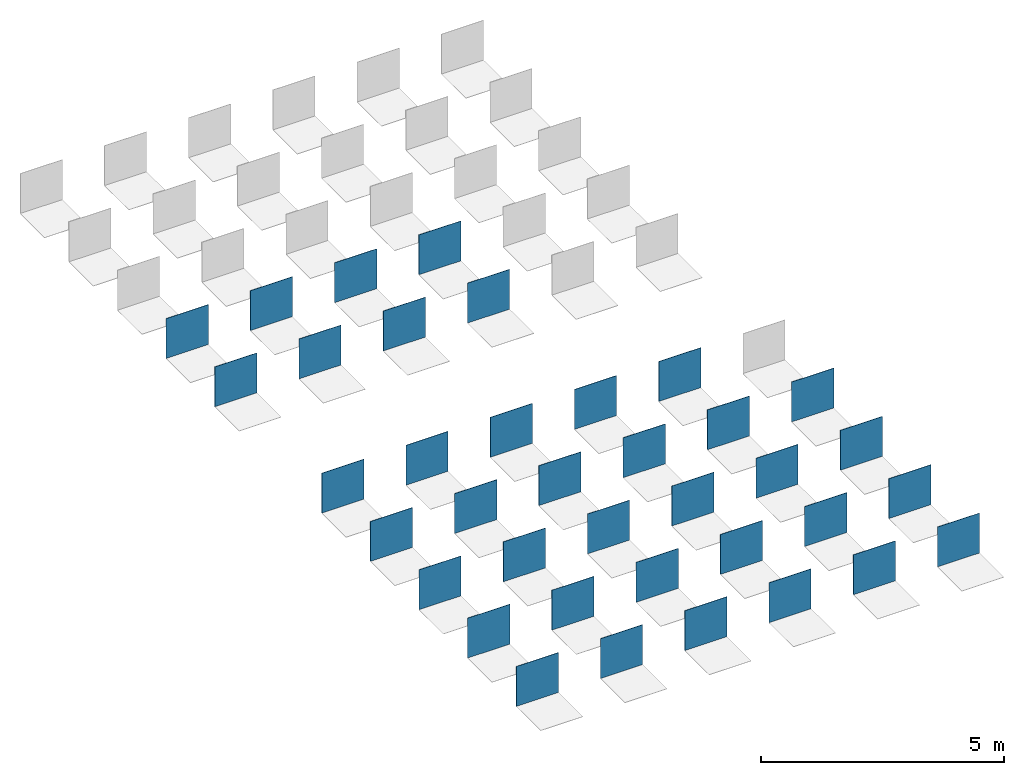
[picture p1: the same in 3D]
Properties of the parts of a building model (IFC2X3), part 7 of 8

# IfcWallStandardCase: Basic Wall:REVIGRÉS-OMNISTONE-BASE-60X120-SOFT-ICE, Basic Wall:REVIGRÉS-OMNISTONE-BASE-60X120-SOFT-ICE:148528
Type - IFC.REVIGRÉS-Dados de sustentabilidade-Wall Covering - ItemEParcialmenteReciclado: 0; PotencialPrivacaoDeAguaConsumoDeAguaPonderado: 4.5; EnergiaTermicaExportada: 0; ItemENovo: Sim; ItemEReciclado: Não; VidaÚtilEsperada: 50; SubstanciasPerigosas: Não; PotencialDeEsgotamentoAbioticoDosRecursosNaoFosseisMineraisEMetais: 0.000701; PotencialDeAquecimentoGlobalBiogenico: -0.48; CombustiveisFosseisComPotencialDeAquecimentoGlobal: 13.9; PotencialDeAquecimentoGlobalUsoDoSoloEMudancaDeUsoDoSolo: 0.0246; PotencialDeEutrofizacaoFraccaoDeNutrientesQueAtingemOCompartimentoFinalDeAguaDoce: 0.000189; PotencialDeEutrofizacaoFraccaoDeNutrientesQueAtingemOCompartimentoFinalMarinho: 0.0122; EnergiaRecuperada: 0.00739; ConsumoDeAguaDoce: 0.113; UtilizacaoLiquidaDeAguaDoce: 0.113; ResiduosPerigososEliminados: 0.00221; ResiduosNaoPerigososEliminados: 1.83; MassaTotalDeResiduosRadioactivosEliminados: 0.000394; EnergiaElectricaExportada: 1.55; MateriaisParaRecuperacaoDeEnergia: 0.00739; MateriaisParaReciclagem: 0.0253; UnidadeEPD: 1 m²
Type - IFC.REVIGRÉS-Dados gerais-Wall Covering - Nome: REVIGRÉS-OMNISTONE-BASE-60X120-SOFT-ICE; TipoProduto: Prensado a seco: grupo BIa UGL | Grés porcelânico técnico; NumeroDeRegistoDAP: EPD-REV-20240006-CCC1-EN; ReferenciaDAP: -; UrlDOP: -
Pset_WallCommon - ExtendToStructure: no; LoadBearing: no
IFC.REVIGRÉS-Dados do fabricante-Wall Covering - Type: Basic Wall: REVIGRÉS-OMNISTONE-BASE-60X120-SOFT-ICE
IFC.REVIGRÉS-Dados de desempenho-Wall Covering - Type: Basic Wall: REVIGRÉS-OMNISTONE-BASE-60X120-SOFT-ICE
IFC.REVIGRÉS-Dados de especificação-Wall Covering - Type: Basic Wall: REVIGRÉS-OMNISTONE-BASE-60X120-SOFT-ICE
IFC.REVIGRÉS-Dados geométricos-Wall Covering - Type: Basic Wall: REVIGRÉS-OMNISTONE-BASE-60X120-SOFT-ICE
IFC.REVIGRÉS-Dados de sustentabilidade-Wall Covering - Type: Basic Wall: REVIGRÉS-OMNISTONE-BASE-60X120-SOFT-ICE

# IfcWallStandardCase: Basic Wall:REVIGRÉS-OMNISTONE-BASE-60X120-SOFT-IRON, Basic Wall:REVIGRÉS-OMNISTONE-BASE-60X120-SOFT-IRON:149213
In: Level 1
Type - PredefinedType: STANDARD; Material: REVIGRÉS-OMNISTONE-BASE-60x120-SOFT-IRON 9.8 mm
Type - Pset_ElementShading - Roughness: 304.8 mm
Type - Pset_ManufacturerTypeInformation - Manufacturer: REVIGRÉS
Type - Pset_ProductRequirements - Category: Walls
Type - Pset_QuantityTakeOff - Reference: 31261390U1
Type - Pset_ReinforcementBarPitchOfWall - Description: Stone effect in wall and floor porcelain tile; Reference: 31261390U1
Type - Pset_WallCommon - IsExternal: no; Reference: 31261390U1
Type - IFC.REVIGRÉS-Dados do fabricante-Wall Covering - FabricanteURL: https://www.revigres.pt/; ReferenciaModelo: Omnistone; NumeroGlobalDeItemComercial: 3126D390U1; Acabamento: SOFT; Material: Grés porcelânico; IdentificadorDoOperadorEconomico: 501840856; UrlFabricanteArtigo: https://www.revigres.pt/colecoes/omnistone; PaisOrigem: Portugal
Type - IFC.REVIGRÉS-Dados de desempenho-Wall Covering - Rectilinearidade: ± 0.2% máx.± 0.8 mm; Ortogonalidade: ± 0.2% máx.± 1.5 mm; PlanaridadeDaSuperficie: ± 0.3% máx. ± 1.8 mm; QualidadeDaSuperficie: Cumpre; AbsorcaoDeAgua: < 0.05%; ModuloDeRuptura: > 45 N/mm130; ResistenciaAFlexao: ≥ 3500 N; ResistenciaAAbrasaoProfunda: < 120 mm131; DilatacaoTermicaLinear: ≤ 8,0x10-6 °C-1; ResistenciaAoChoqueTermico: Resiste; DurabilidadeResistenciaAoGeloDegelo: Resiste; ResistenciaAsManchas: Class 5; ResistenciaABaixasConcentracoesDeAcidosEAlcalis: Classe LA; ResistenciaAAltasConcentracoesDeAcidosEAlcalis: Classe HA; LibertacaoDeCadmio: 0; LibertacaoDeChumbo: 0
Type - IFC.REVIGRÉS-Dados de especificação-Wall Covering - VariacaoTonalidade: 3; NivelDeTrafego: 5; EPavimento: Sim; ERevestimento: Sim; EExterno: Sim
Type - IFC.REVIGRÉS-Dados geométricos-Wall Covering - AlturaNominal: 9.8 mm; ComprimentoNominal: 59.2 mm; LarguraNominal: 118.6 mm
Type - IFC.REVIGRÉS-Dados de sustentabilidade-Wall Covering - PotencialPrivacaoDeAguaConsumoDeAguaPonderado: 4.5; EnergiaTermicaExportada: 0; ItemENovo: Sim; ItemEParcialmenteReciclado: 0.14; ItemEReciclado: Sim; VidaÚtilEsperada: 50; SubstanciasPerigosas: Não; PotencialDeEsgotamentoAbioticoDosRecursosNaoFosseisMineraisEMetais: 0.000701; PotencialDeAquecimentoGlobalBiogenico: -0.48; CombustiveisFosseisComPotencialDeAquecimentoGlobal: 13.9; PotencialDeAquecimentoGlobalUsoDoSoloEMudancaDeUsoDoSolo: 0.0246; PotencialDeEutrofizacaoFraccaoDeNutrientesQueAtingemOCompartimentoFinalDeAguaDoce: 0.000189; PotencialDeEutrofizacaoFraccaoDeNutrientesQueAtingemOCompartimentoFinalMarinho: 0.0122; EnergiaRecuperada: 0.00739; ConsumoDeAguaDoce: 0.113; UtilizacaoLiquidaDeAguaDoce: 0.113; ResiduosPerigososEliminados: 0.00221; ResiduosNaoPerigososEliminados: 1.83; MassaTotalDeResiduosRadioactivosEliminados: 0.000394; EnergiaElectricaExportada: 1.55; MateriaisParaRecuperacaoDeEnergia: 0.00739; MateriaisParaReciclagem: 0.0253; UnidadeEPD: 1 m²
Type - IFC.REVIGRÉS-Dados gerais-Wall Covering - Nome: REVIGRÉS-OMNISTONE-BASE-60X120-SOFT-IRON; TipoProduto: Prensado a seco: grupo BIa UGL | Grés porcelânico técnico; NumeroDeRegistoDAP: EPD-REV-20240006-CCC1-EN; ReferenciaDAP: -; UrlDOP: -
Pset_WallCommon - ExtendToStructure: no; LoadBearing: no
IFC.REVIGRÉS-Dados do fabricante-Wall Covering - Type: Basic Wall: REVIGRÉS-OMNISTONE-BASE-60X120-SOFT-IRON
IFC.REVIGRÉS-Dados de desempenho-Wall Covering - Type: Basic Wall: REVIGRÉS-OMNISTONE-BASE-60X120-SOFT-IRON
IFC.REVIGRÉS-Dados de especificação-Wall Covering - Type: Basic Wall: REVIGRÉS-OMNISTONE-BASE-60X120-SOFT-IRON
IFC.REVIGRÉS-Dados geométricos-Wall Covering - Type: Basic Wall: REVIGRÉS-OMNISTONE-BASE-60X120-SOFT-IRON
IFC.REVIGRÉS-Dados de sustentabilidade-Wall Covering - Type: Basic Wall: REVIGRÉS-OMNISTONE-BASE-60X120-SOFT-IRON

# IfcWallStandardCase: Basic Wall:REVIGRÉS-OMNISTONE-BASE-60X120-SOFT-JET, Basic Wall:REVIGRÉS-OMNISTONE-BASE-60X120-SOFT-JET:149955
In: Level 1
Type - PredefinedType: STANDARD; Material: REVIGRÉS-OMNISTONE-BASE-60x120-SOFT-JET 9.8 mm
Type - Pset_ElementShading - Roughness: 304.8 mm
Type - Pset_ManufacturerTypeInformation - Manufacturer: REVIGRÉS
Type - Pset_ProductRequirements - Category: Walls
Type - Pset_QuantityTakeOff - Reference: 31261391U1
Type - Pset_ReinforcementBarPitchOfWall - Description: Stone effect in wall and floor porcelain tile; Reference: 31261391U1
Type - Pset_WallCommon - IsExternal: no; Reference: 31261391U1
Type - IFC.REVIGRÉS-Dados do fabricante-Wall Covering - FabricanteURL: https://www.revigres.pt/; ReferenciaModelo: Omnistone; NumeroGlobalDeItemComercial: 3126D391U1; Acabamento: SOFT; Material: Grés porcelânico; IdentificadorDoOperadorEconomico: 501840856; UrlFabricanteArtigo: https://www.revigres.pt/colecoes/omnistone; PaisOrigem: Portugal
Type - IFC.REVIGRÉS-Dados de desempenho-Wall Covering - Rectilinearidade: ± 0.2% máx.± 0.8 mm; Ortogonalidade: ± 0.2% máx.± 1.5 mm; PlanaridadeDaSuperficie: ± 0.3% máx. ± 1.8 mm; QualidadeDaSuperficie: Cumpre; AbsorcaoDeAgua: < 0.05%; ModuloDeRuptura: > 45 N/mm130; ResistenciaAFlexao: ≥ 3500 N; ResistenciaAAbrasaoProfunda: < 120 mm131; DilatacaoTermicaLinear: ≤ 8,0x10-6 °C-1; ResistenciaAoChoqueTermico: Resiste; DurabilidadeResistenciaAoGeloDegelo: Resiste; ResistenciaAsManchas: Class 5; ResistenciaABaixasConcentracoesDeAcidosEAlcalis: Classe LA; ResistenciaAAltasConcentracoesDeAcidosEAlcalis: Classe HA; LibertacaoDeCadmio: 0; LibertacaoDeChumbo: 0
Type - IFC.REVIGRÉS-Dados de especificação-Wall Covering - VariacaoTonalidade: 3; NivelDeTrafego: 5; EPavimento: Sim; ERevestimento: Sim; EExterno: Sim
Type - IFC.REVIGRÉS-Dados geométricos-Wall Covering - AlturaNominal: 9.8 mm; ComprimentoNominal: 59.2 mm; LarguraNominal: 118.6 mm
Type - IFC.REVIGRÉS-Dados de sustentabilidade-Wall Covering - ItemEParcialmenteReciclado: 0; PotencialPrivacaoDeAguaConsumoDeAguaPonderado: 4.5; EnergiaTermicaExportada: 0; ItemENovo: Sim; ItemEReciclado: Não; VidaÚtilEsperada: 50; SubstanciasPerigosas: Não; PotencialDeEsgotamentoAbioticoDosRecursosNaoFosseisMineraisEMetais: 0.000701; PotencialDeAquecimentoGlobalBiogenico: -0.48; CombustiveisFosseisComPotencialDeAquecimentoGlobal: 13.9; PotencialDeAquecimentoGlobalUsoDoSoloEMudancaDeUsoDoSolo: 0.0246; PotencialDeEutrofizacaoFraccaoDeNutrientesQueAtingemOCompartimentoFinalDeAguaDoce: 0.000189; PotencialDeEutrofizacaoFraccaoDeNutrientesQueAtingemOCompartimentoFinalMarinho: 0.0122; EnergiaRecuperada: 0.00739; ConsumoDeAguaDoce: 0.113; UtilizacaoLiquidaDeAguaDoce: 0.113; ResiduosPerigososEliminados: 0.00221; ResiduosNaoPerigososEliminados: 1.83; MassaTotalDeResiduosRadioactivosEliminados: 0.000394; EnergiaElectricaExportada: 1.55; MateriaisParaRecuperacaoDeEnergia: 0.00739; MateriaisParaReciclagem: 0.0253; UnidadeEPD: 1 m²
Type - IFC.REVIGRÉS-Dados gerais-Wall Covering - Nome: REVIGRÉS-OMNISTONE-BASE-60X120-SOFT-JET; TipoProduto: Prensado a seco: grupo BIa UGL | Grés porcelânico técnico; NumeroDeRegistoDAP: EPD-REV-20240006-CCC1-EN; ReferenciaDAP: -; UrlDOP: -
Pset_WallCommon - ExtendToStructure: no; LoadBearing: no
IFC.REVIGRÉS-Dados do fabricante-Wall Covering - Type: Basic Wall: REVIGRÉS-OMNISTONE-BASE-60X120-SOFT-JET
IFC.REVIGRÉS-Dados de desempenho-Wall Covering - Type: Basic Wall: REVIGRÉS-OMNISTONE-BASE-60X120-SOFT-JET
IFC.REVIGRÉS-Dados de especificação-Wall Covering - Type: Basic Wall: REVIGRÉS-OMNISTONE-BASE-60X120-SOFT-JET
IFC.REVIGRÉS-Dados geométricos-Wall Covering - Type: Basic Wall: REVIGRÉS-OMNISTONE-BASE-60X120-SOFT-JET
IFC.REVIGRÉS-Dados de sustentabilidade-Wall Covering - Type: Basic Wall: REVIGRÉS-OMNISTONE-BASE-60X120-SOFT-JET

# IfcWallStandardCase: Basic Wall:REVIGRÉS-OMNISTONE-BASE-60X120-SOFT-PLATINA, Basic Wall:REVIGRÉS-OMNISTONE-BASE-60X120-SOFT-PLATINA:150676
In: Level 1
Type - PredefinedType: STANDARD; Material: REVIGRÉS-OMNISTONE-BASE-60x120-SOFT-PLATINA 9.8 mm
Type - Pset_ElementShading - Roughness: 304.8 mm
Type - Pset_ManufacturerTypeInformation - Manufacturer: REVIGRÉS
Type - Pset_ProductRequirements - Category: Walls
Type - Pset_QuantityTakeOff - Reference: 31261392U1
Type - Pset_ReinforcementBarPitchOfWall - Description: Stone effect in wall and floor porcelain tile; Reference: 31261392U1
Type - Pset_WallCommon - IsExternal: no; Reference: 31261392U1
Type - IFC.REVIGRÉS-Dados do fabricante-Wall Covering - FabricanteURL: https://www.revigres.pt/; ReferenciaModelo: Omnistone; NumeroGlobalDeItemComercial: 3126D392U1; Acabamento: SOFT; Material: Grés porcelânico; IdentificadorDoOperadorEconomico: 501840856; UrlFabricanteArtigo: https://www.revigres.pt/colecoes/omnistone; PaisOrigem: Portugal
Type - IFC.REVIGRÉS-Dados de desempenho-Wall Covering - Rectilinearidade: ± 0.2% máx.± 0.8 mm; Ortogonalidade: ± 0.2% máx.± 1.5 mm; PlanaridadeDaSuperficie: ± 0.3% máx. ± 1.8 mm; QualidadeDaSuperficie: Cumpre; AbsorcaoDeAgua: < 0.05%; ModuloDeRuptura: > 45 N/mm130; ResistenciaAFlexao: ≥ 3500 N; ResistenciaAAbrasaoProfunda: < 120 mm131; DilatacaoTermicaLinear: ≤ 8,0x10-6 °C-1; ResistenciaAoChoqueTermico: Resiste; DurabilidadeResistenciaAoGeloDegelo: Resiste; ResistenciaAsManchas: Class 5; ResistenciaABaixasConcentracoesDeAcidosEAlcalis: Classe LA; ResistenciaAAltasConcentracoesDeAcidosEAlcalis: Classe HA; LibertacaoDeCadmio: 0; LibertacaoDeChumbo: 0
Type - IFC.REVIGRÉS-Dados de especificação-Wall Covering - VariacaoTonalidade: 3; NivelDeTrafego: 5; EPavimento: Sim; ERevestimento: Sim; EExterno: Sim
Type - IFC.REVIGRÉS-Dados geométricos-Wall Covering - AlturaNominal: 9.8 mm; ComprimentoNominal: 59.2 mm; LarguraNominal: 118.6 mm
Type - IFC.REVIGRÉS-Dados de sustentabilidade-Wall Covering - ItemEParcialmenteReciclado: 0; PotencialPrivacaoDeAguaConsumoDeAguaPonderado: 4.5; EnergiaTermicaExportada: 0; ItemENovo: Sim; ItemEReciclado: Não; VidaÚtilEsperada: 50; SubstanciasPerigosas: Não; PotencialDeEsgotamentoAbioticoDosRecursosNaoFosseisMineraisEMetais: 0.000701; PotencialDeAquecimentoGlobalBiogenico: -0.48; CombustiveisFosseisComPotencialDeAquecimentoGlobal: 13.9; PotencialDeAquecimentoGlobalUsoDoSoloEMudancaDeUsoDoSolo: 0.0246; PotencialDeEutrofizacaoFraccaoDeNutrientesQueAtingemOCompartimentoFinalDeAguaDoce: 0.000189; PotencialDeEutrofizacaoFraccaoDeNutrientesQueAtingemOCompartimentoFinalMarinho: 0.0122; EnergiaRecuperada: 0.00739; ConsumoDeAguaDoce: 0.113; UtilizacaoLiquidaDeAguaDoce: 0.113; ResiduosPerigososEliminados: 0.00221; ResiduosNaoPerigososEliminados: 1.83; MassaTotalDeResiduosRadioactivosEliminados: 0.000394; EnergiaElectricaExportada: 1.55; MateriaisParaRecuperacaoDeEnergia: 0.00739; MateriaisParaReciclagem: 0.0253; UnidadeEPD: 1 m²
Type - IFC.REVIGRÉS-Dados gerais-Wall Covering - Nome: REVIGRÉS-OMNISTONE-BASE-60X120-SOFT-PLATINA; TipoProduto: Prensado a seco: grupo BIa UGL | Grés porcelânico técnico; NumeroDeRegistoDAP: EPD-REV-20240006-CCC1-EN; ReferenciaDAP: -; UrlDOP: -
Pset_WallCommon - ExtendToStructure: no; LoadBearing: no
IFC.REVIGRÉS-Dados do fabricante-Wall Covering - Type: Basic Wall: REVIGRÉS-OMNISTONE-BASE-60X120-SOFT-PLATINA
IFC.REVIGRÉS-Dados de desempenho-Wall Covering - Type: Basic Wall: REVIGRÉS-OMNISTONE-BASE-60X120-SOFT-PLATINA
IFC.REVIGRÉS-Dados de especificação-Wall Covering - Type: Basic Wall: REVIGRÉS-OMNISTONE-BASE-60X120-SOFT-PLATINA
IFC.REVIGRÉS-Dados geométricos-Wall Covering - Type: Basic Wall: REVIGRÉS-OMNISTONE-BASE-60X120-SOFT-PLATINA
IFC.REVIGRÉS-Dados de sustentabilidade-Wall Covering - Type: Basic Wall: REVIGRÉS-OMNISTONE-BASE-60X120-SOFT-PLATINA

# IfcWallStandardCase: Basic Wall:REVIGRÉS-OMNISTONE-BASE-60X120-SOFT-ROPE, Basic Wall:REVIGRÉS-OMNISTONE-BASE-60X120-SOFT-ROPE:151381
In: Level 1
Type - PredefinedType: STANDARD; Material: REVIGRÉS-OMNISTONE-BASE-60x120-SOFT-ROPE 9.8 mm
Type - Pset_ElementShading - Roughness: 304.8 mm
Type - Pset_ManufacturerTypeInformation - Manufacturer: REVIGRÉS
Type - Pset_ProductRequirements - Category: Walls
Type - Pset_QuantityTakeOff - Reference: 31261393U1
Type - Pset_ReinforcementBarPitchOfWall - Description: Stone effect in wall and floor porcelain tile; Reference: 31261393U1
Type - Pset_WallCommon - IsExternal: no; Reference: 31261393U1
Type - IFC.REVIGRÉS-Dados do fabricante-Wall Covering - FabricanteURL: https://www.revigres.pt/; ReferenciaModelo: Omnistone; NumeroGlobalDeItemComercial: 3126D393U1; Acabamento: SOFT; Material: Grés porcelânico; IdentificadorDoOperadorEconomico: 501840856; UrlFabricanteArtigo: https://www.revigres.pt/colecoes/omnistone; PaisOrigem: Portugal
Type - IFC.REVIGRÉS-Dados de desempenho-Wall Covering - Rectilinearidade: ± 0.2% máx.± 0.8 mm; Ortogonalidade: ± 0.2% máx.± 1.5 mm; PlanaridadeDaSuperficie: ± 0.3% máx. ± 1.8 mm; QualidadeDaSuperficie: Cumpre; AbsorcaoDeAgua: < 0.05%; ModuloDeRuptura: > 45 N/mm130; ResistenciaAFlexao: ≥ 3500 N; ResistenciaAAbrasaoProfunda: < 120 mm131; DilatacaoTermicaLinear: ≤ 8,0x10-6 °C-1; ResistenciaAoChoqueTermico: Resiste; DurabilidadeResistenciaAoGeloDegelo: Resiste; ResistenciaAsManchas: Class 5; ResistenciaABaixasConcentracoesDeAcidosEAlcalis: Classe LA; ResistenciaAAltasConcentracoesDeAcidosEAlcalis: Classe HA; LibertacaoDeCadmio: 0; LibertacaoDeChumbo: 0
Type - IFC.REVIGRÉS-Dados de especificação-Wall Covering - VariacaoTonalidade: 3; NivelDeTrafego: 5; EPavimento: Sim; ERevestimento: Sim; EExterno: Sim
Type - IFC.REVIGRÉS-Dados geométricos-Wall Covering - AlturaNominal: 9.8 mm; ComprimentoNominal: 59.2 mm; LarguraNominal: 118.6 mm
Type - IFC.REVIGRÉS-Dados de sustentabilidade-Wall Covering - ItemEParcialmenteReciclado: 0; PotencialPrivacaoDeAguaConsumoDeAguaPonderado: 4.5; EnergiaTermicaExportada: 0; ItemENovo: Sim; ItemEReciclado: Não; VidaÚtilEsperada: 50; SubstanciasPerigosas: Não; PotencialDeEsgotamentoAbioticoDosRecursosNaoFosseisMineraisEMetais: 0.000701; PotencialDeAquecimentoGlobalBiogenico: -0.48; CombustiveisFosseisComPotencialDeAquecimentoGlobal: 13.9; PotencialDeAquecimentoGlobalUsoDoSoloEMudancaDeUsoDoSolo: 0.0246; PotencialDeEutrofizacaoFraccaoDeNutrientesQueAtingemOCompartimentoFinalDeAguaDoce: 0.000189; PotencialDeEutrofizacaoFraccaoDeNutrientesQueAtingemOCompartimentoFinalMarinho: 0.0122; EnergiaRecuperada: 0.00739; ConsumoDeAguaDoce: 0.113; UtilizacaoLiquidaDeAguaDoce: 0.113; ResiduosPerigososEliminados: 0.00221; ResiduosNaoPerigososEliminados: 1.83; MassaTotalDeResiduosRadioactivosEliminados: 0.000394; EnergiaElectricaExportada: 1.55; MateriaisParaRecuperacaoDeEnergia: 0.00739; MateriaisParaReciclagem: 0.0253; UnidadeEPD: 1 m²
Type - IFC.REVIGRÉS-Dados gerais-Wall Covering - Nome: REVIGRÉS-OMNISTONE-BASE-60X120-SOFT-ROPE; TipoProduto: Prensado a seco: grupo BIa UGL | Grés porcelânico técnico; NumeroDeRegistoDAP: EPD-REV-20240006-CCC1-EN; ReferenciaDAP: -; UrlDOP: -
Pset_WallCommon - ExtendToStructure: no; LoadBearing: no
IFC.REVIGRÉS-Dados do fabricante-Wall Covering - Type: Basic Wall: REVIGRÉS-OMNISTONE-BASE-60X120-SOFT-ROPE
IFC.REVIGRÉS-Dados de desempenho-Wall Covering - Type: Basic Wall: REVIGRÉS-OMNISTONE-BASE-60X120-SOFT-ROPE
IFC.REVIGRÉS-Dados de especificação-Wall Covering - Type: Basic Wall: REVIGRÉS-OMNISTONE-BASE-60X120-SOFT-ROPE
IFC.REVIGRÉS-Dados geométricos-Wall Covering - Type: Basic Wall: REVIGRÉS-OMNISTONE-BASE-60X120-SOFT-ROPE
IFC.REVIGRÉS-Dados de sustentabilidade-Wall Covering - Type: Basic Wall: REVIGRÉS-OMNISTONE-BASE-60X120-SOFT-ROPE

# IfcWallStandardCase: Basic Wall:REVIGRÉS-OMNISTONE-BASE-60X60-MATTRECT-BONE, Basic Wall:REVIGRÉS-OMNISTONE-BASE-60X60-MATTRECT-BONE:146345
In: Level 1
Type - PredefinedType: STANDARD; Material: REVIGRÉS-OMNISTONE-BASE-60x60-MATTRECT-BONE 9.8 mm
Type - Pset_ElementShading - Roughness: 304.8 mm
Type - Pset_ManufacturerTypeInformation - Manufacturer: REVIGRÉS
Type - Pset_ProductRequirements - Category: Walls
Type - Pset_QuantityTakeOff - Reference: 312BD388U1
Type - Pset_ReinforcementBarPitchOfWall - Description: Stone effect in wall and floor porcelain tile; Reference: 312BD388U1
Type - Pset_WallCommon - IsExternal: no; Reference: 312BD388U1
Type - IFC.REVIGRÉS-Dados do fabricante-Wall Covering - FabricanteURL: https://www.revigres.pt/; ReferenciaModelo: Omnistone; NumeroGlobalDeItemComercial: 312B1388U1; Acabamento: MATT RECT; Material: Grés porcelânico; IdentificadorDoOperadorEconomico: 501840856; UrlFabricanteArtigo: https://www.revigres.pt/colecoes/omnistone; PaisOrigem: Portugal
Type - IFC.REVIGRÉS-Dados de desempenho-Wall Covering - Rectilinearidade: ± 0.2% máx.± 0.8 mm; Ortogonalidade: ± 0.2% máx.± 1.5 mm; PlanaridadeDaSuperficie: ± 0.3% máx. ± 1.8 mm; QualidadeDaSuperficie: Cumpre; AbsorcaoDeAgua: < 0.05%; ModuloDeRuptura: > 45 N/mm130; ResistenciaAFlexao: ≥ 3500 N; ResistenciaAAbrasaoProfunda: < 120 mm131; DilatacaoTermicaLinear: ≤ 8,0x10-6 °C-1; ResistenciaAoChoqueTermico: Resiste; DurabilidadeResistenciaAoGeloDegelo: Resiste; ResistenciaAoEscorregamentoDIN51130: R10; ResistenciaAoEscorregamentoDIN51097: B; ResistenciaAoEscorregamentoENV51097: B; ResistenciaAoEscorregamentoENV12633: Class 2; ResistenciaAoEscorregamentoBS7976: >36; ResistenciaAoEscorregamentoANSIA1371: ≥0,42; ResistenciaAoDeslizamentoENV12633: Class 2; ResistenciaAoDeslizamentoBS7976: >36; ResistenciaAsManchas: Class 5; ResistenciaABaixasConcentracoesDeAcidosEAlcalis: Classe LA; ResistenciaAAltasConcentracoesDeAcidosEAlcalis: Classe HA; LibertacaoDeCadmio: 0; LibertacaoDeChumbo: 0
Type - IFC.REVIGRÉS-Dados de especificação-Wall Covering - VariacaoTonalidade: 3; NivelDeTrafego: 5; EPavimento: Sim; ERevestimento: Sim; EExterno: Sim
Type - IFC.REVIGRÉS-Dados geométricos-Wall Covering - AlturaNominal: 9.8 mm; ComprimentoNominal: 59.2 mm; LarguraNominal: 59.2 mm
Type - IFC.REVIGRÉS-Dados de sustentabilidade-Wall Covering - ItemEParcialmenteReciclado: 0; PotencialPrivacaoDeAguaConsumoDeAguaPonderado: 4.5; EnergiaTermicaExportada: 0; ItemENovo: Sim; ItemEReciclado: Não; VidaÚtilEsperada: 50; SubstanciasPerigosas: Não; PotencialDeEsgotamentoAbioticoDosRecursosNaoFosseisMineraisEMetais: 0.000701; PotencialDeAquecimentoGlobalBiogenico: -0.48; CombustiveisFosseisComPotencialDeAquecimentoGlobal: 13.9; PotencialDeAquecimentoGlobalUsoDoSoloEMudancaDeUsoDoSolo: 0.0246; PotencialDeEutrofizacaoFraccaoDeNutrientesQueAtingemOCompartimentoFinalDeAguaDoce: 0.000189; PotencialDeEutrofizacaoFraccaoDeNutrientesQueAtingemOCompartimentoFinalMarinho: 0.0122; EnergiaRecuperada: 0.00739; ConsumoDeAguaDoce: 0.113; UtilizacaoLiquidaDeAguaDoce: 0.113; ResiduosPerigososEliminados: 0.00221; ResiduosNaoPerigososEliminados: 1.83; MassaTotalDeResiduosRadioactivosEliminados: 0.000394; EnergiaElectricaExportada: 1.55; MateriaisParaRecuperacaoDeEnergia: 0.00739; MateriaisParaReciclagem: 0.0253; UnidadeEPD: 1 m²
Type - IFC.REVIGRÉS-Dados gerais-Wall Covering - Nome: REVIGRÉS-OMNISTONE-BASE-60X60-MATT RECT-BONE; TipoProduto: Prensado a seco: grupo BIa UGL | Grés porcelânico técnico; NumeroDeRegistoDAP: EPD-REV-20240006-CCC1-EN; ReferenciaDAP: -; UrlDOP: -
Pset_WallCommon - ExtendToStructure: no; LoadBearing: no
IFC.REVIGRÉS-Dados do fabricante-Wall Covering - Type: Basic Wall: REVIGRÉS-OMNISTONE-BASE-60X60-MATTRECT-BONE
IFC.REVIGRÉS-Dados de desempenho-Wall Covering - Type: Basic Wall: REVIGRÉS-OMNISTONE-BASE-60X60-MATTRECT-BONE
IFC.REVIGRÉS-Dados de especificação-Wall Covering - Type: Basic Wall: REVIGRÉS-OMNISTONE-BASE-60X60-MATTRECT-BONE
IFC.REVIGRÉS-Dados geométricos-Wall Covering - Type: Basic Wall: REVIGRÉS-OMNISTONE-BASE-60X60-MATTRECT-BONE
IFC.REVIGRÉS-Dados de sustentabilidade-Wall Covering - Type: Basic Wall: REVIGRÉS-OMNISTONE-BASE-60X60-MATTRECT-BONE

# IfcWallStandardCase: Basic Wall:REVIGRÉS-OMNISTONE-BASE-60X60-MATTRECT-ICE, Basic Wall:REVIGRÉS-OMNISTONE-BASE-60X60-MATTRECT-ICE:148431
In: Level 1
Type - PredefinedType: STANDARD; Material: REVIGRÉS-OMNISTONE-BASE-60x60-MATTRECT-ICE 9.8 mm
Type - Pset_ElementShading - Roughness: 304.8 mm
Type - Pset_ManufacturerTypeInformation - Manufacturer: REVIGRÉS
Type - Pset_ProductRequirements - Category: Walls
Type - Pset_QuantityTakeOff - Reference: 312BD389U1
Type - Pset_ReinforcementBarPitchOfWall - Description: Stone effect in wall and floor porcelain tile; Reference: 312BD389U1
Type - Pset_WallCommon - IsExternal: no; Reference: 312BD389U1
Type - IFC.REVIGRÉS-Dados do fabricante-Wall Covering - FabricanteURL: https://www.revigres.pt/; ReferenciaModelo: Omnistone; NumeroGlobalDeItemComercial: 312B1389U1; Acabamento: MATT RECT; Material: Grés porcelânico; IdentificadorDoOperadorEconomico: 501840856; UrlFabricanteArtigo: https://www.revigres.pt/colecoes/omnistone; PaisOrigem: Portugal
Type - IFC.REVIGRÉS-Dados de desempenho-Wall Covering - Rectilinearidade: ± 0.2% máx.± 0.8 mm; Ortogonalidade: ± 0.2% máx.± 1.5 mm; PlanaridadeDaSuperficie: ± 0.3% máx. ± 1.8 mm; QualidadeDaSuperficie: Cumpre; AbsorcaoDeAgua: < 0.05%; ModuloDeRuptura: > 45 N/mm130; ResistenciaAFlexao: ≥ 3500 N; ResistenciaAAbrasaoProfunda: < 120 mm131; DilatacaoTermicaLinear: ≤ 8,0x10-6 °C-1; ResistenciaAoChoqueTermico: Resiste; DurabilidadeResistenciaAoGeloDegelo: Resiste; ResistenciaAoEscorregamentoDIN51130: R10; ResistenciaAoEscorregamentoDIN51097: B; ResistenciaAoEscorregamentoENV51097: B; ResistenciaAoEscorregamentoENV12633: Class 2; ResistenciaAoEscorregamentoBS7976: >36; ResistenciaAoEscorregamentoANSIA1371: ≥0,42; ResistenciaAoDeslizamentoENV12633: Class 2; ResistenciaAoDeslizamentoBS7976: >36; ResistenciaAsManchas: Class 5; ResistenciaABaixasConcentracoesDeAcidosEAlcalis: Classe LA; ResistenciaAAltasConcentracoesDeAcidosEAlcalis: Classe HA; LibertacaoDeCadmio: 0; LibertacaoDeChumbo: 0
Type - IFC.REVIGRÉS-Dados de especificação-Wall Covering - VariacaoTonalidade: 3; NivelDeTrafego: 5; EPavimento: Sim; ERevestimento: Sim; EExterno: Sim
Type - IFC.REVIGRÉS-Dados geométricos-Wall Covering - AlturaNominal: 9.8 mm; ComprimentoNominal: 59.2 mm; LarguraNominal: 59.2 mm
Type - IFC.REVIGRÉS-Dados de sustentabilidade-Wall Covering - ItemEParcialmenteReciclado: 0; PotencialPrivacaoDeAguaConsumoDeAguaPonderado: 4.5; EnergiaTermicaExportada: 0; ItemENovo: Sim; ItemEReciclado: Não; VidaÚtilEsperada: 50; SubstanciasPerigosas: Não; PotencialDeEsgotamentoAbioticoDosRecursosNaoFosseisMineraisEMetais: 0.000701; PotencialDeAquecimentoGlobalBiogenico: -0.48; CombustiveisFosseisComPotencialDeAquecimentoGlobal: 13.9; PotencialDeAquecimentoGlobalUsoDoSoloEMudancaDeUsoDoSolo: 0.0246; PotencialDeEutrofizacaoFraccaoDeNutrientesQueAtingemOCompartimentoFinalDeAguaDoce: 0.000189; PotencialDeEutrofizacaoFraccaoDeNutrientesQueAtingemOCompartimentoFinalMarinho: 0.0122; EnergiaRecuperada: 0.00739; ConsumoDeAguaDoce: 0.113; UtilizacaoLiquidaDeAguaDoce: 0.113; ResiduosPerigososEliminados: 0.00221; ResiduosNaoPerigososEliminados: 1.83; MassaTotalDeResiduosRadioactivosEliminados: 0.000394; EnergiaElectricaExportada: 1.55; MateriaisParaRecuperacaoDeEnergia: 0.00739; MateriaisParaReciclagem: 0.0253; UnidadeEPD: 1 m²
Type - IFC.REVIGRÉS-Dados gerais-Wall Covering - Nome: REVIGRÉS-OMNISTONE-BASE-60X60-MATT RECT-ICE; TipoProduto: Prensado a seco: grupo BIa UGL | Grés porcelânico técnico; NumeroDeRegistoDAP: EPD-REV-20240006-CCC1-EN; ReferenciaDAP: -; UrlDOP: -
Pset_WallCommon - ExtendToStructure: no; LoadBearing: no
IFC.REVIGRÉS-Dados do fabricante-Wall Covering - Type: Basic Wall: REVIGRÉS-OMNISTONE-BASE-60X60-MATTRECT-ICE
IFC.REVIGRÉS-Dados de desempenho-Wall Covering - Type: Basic Wall: REVIGRÉS-OMNISTONE-BASE-60X60-MATTRECT-ICE
IFC.REVIGRÉS-Dados de especificação-Wall Covering - Type: Basic Wall: REVIGRÉS-OMNISTONE-BASE-60X60-MATTRECT-ICE
IFC.REVIGRÉS-Dados geométricos-Wall Covering - Type: Basic Wall: REVIGRÉS-OMNISTONE-BASE-60X60-MATTRECT-ICE
IFC.REVIGRÉS-Dados de sustentabilidade-Wall Covering - Type: Basic Wall: REVIGRÉS-OMNISTONE-BASE-60X60-MATTRECT-ICE

# IfcWallStandardCase: Basic Wall:REVIGRÉS-OMNISTONE-BASE-60X60-MATTRECT-IRON, Basic Wall:REVIGRÉS-OMNISTONE-BASE-60X60-MATTRECT-IRON:149125
In: Level 1
Type - PredefinedType: STANDARD; Material: REVIGRÉS-OMNISTONE-BASE-60x60-MATTRECT-IRON 9.8 mm
Type - Pset_ElementShading - Roughness: 304.8 mm
Type - Pset_ManufacturerTypeInformation - Manufacturer: REVIGRÉS
Type - Pset_ProductRequirements - Category: Walls
Type - Pset_QuantityTakeOff - Reference: 312BD390U1
Type - Pset_ReinforcementBarPitchOfWall - Description: Stone effect in wall and floor porcelain tile; Reference: 312BD390U1
Type - Pset_WallCommon - IsExternal: no; Reference: 312BD390U1
Type - IFC.REVIGRÉS-Dados do fabricante-Wall Covering - FabricanteURL: https://www.revigres.pt/; ReferenciaModelo: Omnistone; NumeroGlobalDeItemComercial: 312B1390U1; Acabamento: MATT RECT; Material: Grés porcelânico; IdentificadorDoOperadorEconomico: 501840856; UrlFabricanteArtigo: https://www.revigres.pt/colecoes/omnistone; PaisOrigem: Portugal
Type - IFC.REVIGRÉS-Dados de desempenho-Wall Covering - Rectilinearidade: ± 0.2% máx.± 0.8 mm; Ortogonalidade: ± 0.2% máx.± 1.5 mm; PlanaridadeDaSuperficie: ± 0.3% máx. ± 1.8 mm; QualidadeDaSuperficie: Cumpre; AbsorcaoDeAgua: < 0.05%; ModuloDeRuptura: > 45 N/mm130; ResistenciaAFlexao: ≥ 3500 N; ResistenciaAAbrasaoProfunda: < 120 mm131; DilatacaoTermicaLinear: ≤ 8,0x10-6 °C-1; ResistenciaAoChoqueTermico: Resiste; DurabilidadeResistenciaAoGeloDegelo: Resiste; ResistenciaAoEscorregamentoDIN51130: R10; ResistenciaAoEscorregamentoDIN51097: B; ResistenciaAoEscorregamentoENV51097: B; ResistenciaAoEscorregamentoENV12633: Class 2; ResistenciaAoEscorregamentoBS7976: >36; ResistenciaAoEscorregamentoANSIA1371: ≥0,42; ResistenciaAoDeslizamentoENV12633: Class 2; ResistenciaAoDeslizamentoBS7976: >36; ResistenciaAsManchas: Class 5; ResistenciaABaixasConcentracoesDeAcidosEAlcalis: Classe LA; ResistenciaAAltasConcentracoesDeAcidosEAlcalis: Classe HA; LibertacaoDeCadmio: 0; LibertacaoDeChumbo: 0
Type - IFC.REVIGRÉS-Dados de especificação-Wall Covering - VariacaoTonalidade: 3; NivelDeTrafego: 5; EPavimento: Sim; ERevestimento: Sim; EExterno: Sim
Type - IFC.REVIGRÉS-Dados geométricos-Wall Covering - AlturaNominal: 9.8 mm; ComprimentoNominal: 59.2 mm; LarguraNominal: 59.2 mm
Type - IFC.REVIGRÉS-Dados de sustentabilidade-Wall Covering - PotencialPrivacaoDeAguaConsumoDeAguaPonderado: 4.5; EnergiaTermicaExportada: 0; ItemENovo: Sim; ItemEParcialmenteReciclado: 0.14; ItemEReciclado: Sim; VidaÚtilEsperada: 50; SubstanciasPerigosas: Não; PotencialDeEsgotamentoAbioticoDosRecursosNaoFosseisMineraisEMetais: 0.000701; PotencialDeAquecimentoGlobalBiogenico: -0.48; CombustiveisFosseisComPotencialDeAquecimentoGlobal: 13.9; PotencialDeAquecimentoGlobalUsoDoSoloEMudancaDeUsoDoSolo: 0.0246; PotencialDeEutrofizacaoFraccaoDeNutrientesQueAtingemOCompartimentoFinalDeAguaDoce: 0.000189; PotencialDeEutrofizacaoFraccaoDeNutrientesQueAtingemOCompartimentoFinalMarinho: 0.0122; EnergiaRecuperada: 0.00739; ConsumoDeAguaDoce: 0.113; UtilizacaoLiquidaDeAguaDoce: 0.113; ResiduosPerigososEliminados: 0.00221; ResiduosNaoPerigososEliminados: 1.83; MassaTotalDeResiduosRadioactivosEliminados: 0.000394; EnergiaElectricaExportada: 1.55; MateriaisParaRecuperacaoDeEnergia: 0.00739; MateriaisParaReciclagem: 0.0253; UnidadeEPD: 1 m²
Type - IFC.REVIGRÉS-Dados gerais-Wall Covering - Nome: REVIGRÉS-OMNISTONE-BASE-60X60-MATT RECT-IRON; TipoProduto: Prensado a seco: grupo BIa UGL | Grés porcelânico técnico; NumeroDeRegistoDAP: EPD-REV-20240006-CCC1-EN; ReferenciaDAP: -; UrlDOP: -
Pset_WallCommon - ExtendToStructure: no; LoadBearing: no
IFC.REVIGRÉS-Dados do fabricante-Wall Covering - Type: Basic Wall: REVIGRÉS-OMNISTONE-BASE-60X60-MATTRECT-IRON
IFC.REVIGRÉS-Dados de desempenho-Wall Covering - Type: Basic Wall: REVIGRÉS-OMNISTONE-BASE-60X60-MATTRECT-IRON
IFC.REVIGRÉS-Dados de especificação-Wall Covering - Type: Basic Wall: REVIGRÉS-OMNISTONE-BASE-60X60-MATTRECT-IRON
IFC.REVIGRÉS-Dados geométricos-Wall Covering - Type: Basic Wall: REVIGRÉS-OMNISTONE-BASE-60X60-MATTRECT-IRON
IFC.REVIGRÉS-Dados de sustentabilidade-Wall Covering - Type: Basic Wall: REVIGRÉS-OMNISTONE-BASE-60X60-MATTRECT-IRON

# IfcWallStandardCase: Basic Wall:REVIGRÉS-OMNISTONE-BASE-60X60-MATTRECT-JET, Basic Wall:REVIGRÉS-OMNISTONE-BASE-60X60-MATTRECT-JET:149867
In: Level 1
Type - PredefinedType: STANDARD; Material: REVIGRÉS-OMNISTONE-BASE-60x60-MATTRECT-JET 9.8 mm
Type - Pset_ElementShading - Roughness: 304.8 mm
Type - Pset_ManufacturerTypeInformation - Manufacturer: REVIGRÉS
Type - Pset_ProductRequirements - Category: Walls
Type - Pset_QuantityTakeOff - Reference: 312BD391U1
Type - Pset_ReinforcementBarPitchOfWall - Description: Stone effect in wall and floor porcelain tile; Reference: 312BD391U1
Type - Pset_WallCommon - IsExternal: no; Reference: 312BD391U1
Type - IFC.REVIGRÉS-Dados do fabricante-Wall Covering - FabricanteURL: https://www.revigres.pt/; ReferenciaModelo: Omnistone; NumeroGlobalDeItemComercial: 312B1391U1; Acabamento: MATT RECT; Material: Grés porcelânico; IdentificadorDoOperadorEconomico: 501840856; UrlFabricanteArtigo: https://www.revigres.pt/colecoes/omnistone; PaisOrigem: Portugal
Type - IFC.REVIGRÉS-Dados de desempenho-Wall Covering - Rectilinearidade: ± 0.2% máx.± 0.8 mm; Ortogonalidade: ± 0.2% máx.± 1.5 mm; PlanaridadeDaSuperficie: ± 0.3% máx. ± 1.8 mm; QualidadeDaSuperficie: Cumpre; AbsorcaoDeAgua: < 0.05%; ModuloDeRuptura: > 45 N/mm130; ResistenciaAFlexao: ≥ 3500 N; ResistenciaAAbrasaoProfunda: < 120 mm131; DilatacaoTermicaLinear: ≤ 8,0x10-6 °C-1; ResistenciaAoChoqueTermico: Resiste; DurabilidadeResistenciaAoGeloDegelo: Resiste; ResistenciaAoEscorregamentoDIN51130: R10; ResistenciaAoEscorregamentoDIN51097: B; ResistenciaAoEscorregamentoENV51097: B; ResistenciaAoEscorregamentoENV12633: Class 2; ResistenciaAoEscorregamentoBS7976: >36; ResistenciaAoEscorregamentoANSIA1371: ≥0,42; ResistenciaAoDeslizamentoENV12633: Class 2; ResistenciaAoDeslizamentoBS7976: >36; ResistenciaAsManchas: Class 5; ResistenciaABaixasConcentracoesDeAcidosEAlcalis: Classe LA; ResistenciaAAltasConcentracoesDeAcidosEAlcalis: Classe HA; LibertacaoDeCadmio: 0; LibertacaoDeChumbo: 0
Type - IFC.REVIGRÉS-Dados de especificação-Wall Covering - VariacaoTonalidade: 3; NivelDeTrafego: 5; EPavimento: Sim; ERevestimento: Sim; EExterno: Sim
Type - IFC.REVIGRÉS-Dados geométricos-Wall Covering - AlturaNominal: 9.8 mm; ComprimentoNominal: 59.2 mm; LarguraNominal: 59.2 mm
Type - IFC.REVIGRÉS-Dados de sustentabilidade-Wall Covering - ItemEParcialmenteReciclado: 0; PotencialPrivacaoDeAguaConsumoDeAguaPonderado: 4.5; EnergiaTermicaExportada: 0; ItemENovo: Sim; ItemEReciclado: Não; VidaÚtilEsperada: 50; SubstanciasPerigosas: Não; PotencialDeEsgotamentoAbioticoDosRecursosNaoFosseisMineraisEMetais: 0.000701; PotencialDeAquecimentoGlobalBiogenico: -0.48; CombustiveisFosseisComPotencialDeAquecimentoGlobal: 13.9; PotencialDeAquecimentoGlobalUsoDoSoloEMudancaDeUsoDoSolo: 0.0246; PotencialDeEutrofizacaoFraccaoDeNutrientesQueAtingemOCompartimentoFinalDeAguaDoce: 0.000189; PotencialDeEutrofizacaoFraccaoDeNutrientesQueAtingemOCompartimentoFinalMarinho: 0.0122; EnergiaRecuperada: 0.00739; ConsumoDeAguaDoce: 0.113; UtilizacaoLiquidaDeAguaDoce: 0.113; ResiduosPerigososEliminados: 0.00221; ResiduosNaoPerigososEliminados: 1.83; MassaTotalDeResiduosRadioactivosEliminados: 0.000394; EnergiaElectricaExportada: 1.55; MateriaisParaRecuperacaoDeEnergia: 0.00739; MateriaisParaReciclagem: 0.0253; UnidadeEPD: 1 m²
Type - IFC.REVIGRÉS-Dados gerais-Wall Covering - Nome: REVIGRÉS-OMNISTONE-BASE-60X60-MATT RECT-JET; TipoProduto: Prensado a seco: grupo BIa UGL | Grés porcelânico técnico; NumeroDeRegistoDAP: EPD-REV-20240006-CCC1-EN; ReferenciaDAP: -; UrlDOP: -
Pset_WallCommon - ExtendToStructure: no; LoadBearing: no
IFC.REVIGRÉS-Dados do fabricante-Wall Covering - Type: Basic Wall: REVIGRÉS-OMNISTONE-BASE-60X60-MATTRECT-JET
IFC.REVIGRÉS-Dados de desempenho-Wall Covering - Type: Basic Wall: REVIGRÉS-OMNISTONE-BASE-60X60-MATTRECT-JET
IFC.REVIGRÉS-Dados de especificação-Wall Covering - Type: Basic Wall: REVIGRÉS-OMNISTONE-BASE-60X60-MATTRECT-JET
IFC.REVIGRÉS-Dados geométricos-Wall Covering - Type: Basic Wall: REVIGRÉS-OMNISTONE-BASE-60X60-MATTRECT-JET
IFC.REVIGRÉS-Dados de sustentabilidade-Wall Covering - Type: Basic Wall: REVIGRÉS-OMNISTONE-BASE-60X60-MATTRECT-JET

# IfcWallStandardCase: Basic Wall:REVIGRÉS-OMNISTONE-BASE-60X60-MATTRECT-PLATINA, Basic Wall:REVIGRÉS-OMNISTONE-BASE-60X60-MATTRECT-PLATINA:150588
In: Level 1
Type - PredefinedType: STANDARD; Material: REVIGRÉS-OMNISTONE-BASE-60x60-MATTRECT-PLATINA 9.8 mm
Type - Pset_ElementShading - Roughness: 304.8 mm
Type - Pset_ManufacturerTypeInformation - Manufacturer: REVIGRÉS
Type - Pset_ProductRequirements - Category: Walls
Type - Pset_QuantityTakeOff - Reference: 312BD392U1
Type - Pset_ReinforcementBarPitchOfWall - Description: Stone effect in wall and floor porcelain tile; Reference: 312BD392U1
Type - Pset_WallCommon - IsExternal: no; Reference: 312BD392U1
Type - IFC.REVIGRÉS-Dados do fabricante-Wall Covering - FabricanteURL: https://www.revigres.pt/; ReferenciaModelo: Omnistone; NumeroGlobalDeItemComercial: 312B1392U1; Acabamento: MATT RECT; Material: Grés porcelânico; IdentificadorDoOperadorEconomico: 501840856; UrlFabricanteArtigo: https://www.revigres.pt/colecoes/omnistone; PaisOrigem: Portugal
Type - IFC.REVIGRÉS-Dados de desempenho-Wall Covering - Rectilinearidade: ± 0.2% máx.± 0.8 mm; Ortogonalidade: ± 0.2% máx.± 1.5 mm; PlanaridadeDaSuperficie: ± 0.3% máx. ± 1.8 mm; QualidadeDaSuperficie: Cumpre; AbsorcaoDeAgua: < 0.05%; ModuloDeRuptura: > 45 N/mm130; ResistenciaAFlexao: ≥ 3500 N; ResistenciaAAbrasaoProfunda: < 120 mm131; DilatacaoTermicaLinear: ≤ 8,0x10-6 °C-1; ResistenciaAoChoqueTermico: Resiste; DurabilidadeResistenciaAoGeloDegelo: Resiste; ResistenciaAoEscorregamentoDIN51130: R10; ResistenciaAoEscorregamentoDIN51097: B; ResistenciaAoEscorregamentoENV51097: B; ResistenciaAoEscorregamentoENV12633: Class 2; ResistenciaAoEscorregamentoBS7976: >36; ResistenciaAoEscorregamentoANSIA1371: ≥0,42; ResistenciaAoDeslizamentoENV12633: Class 2; ResistenciaAoDeslizamentoBS7976: >36; ResistenciaAsManchas: Class 5; ResistenciaABaixasConcentracoesDeAcidosEAlcalis: Classe LA; ResistenciaAAltasConcentracoesDeAcidosEAlcalis: Classe HA; LibertacaoDeCadmio: 0; LibertacaoDeChumbo: 0
Type - IFC.REVIGRÉS-Dados de especificação-Wall Covering - VariacaoTonalidade: 3; NivelDeTrafego: 5; EPavimento: Sim; ERevestimento: Sim; EExterno: Sim
Type - IFC.REVIGRÉS-Dados geométricos-Wall Covering - AlturaNominal: 9.8 mm; ComprimentoNominal: 59.2 mm; LarguraNominal: 59.2 mm
Type - IFC.REVIGRÉS-Dados de sustentabilidade-Wall Covering - ItemEParcialmenteReciclado: 0; PotencialPrivacaoDeAguaConsumoDeAguaPonderado: 4.5; EnergiaTermicaExportada: 0; ItemENovo: Sim; ItemEReciclado: Não; VidaÚtilEsperada: 50; SubstanciasPerigosas: Não; PotencialDeEsgotamentoAbioticoDosRecursosNaoFosseisMineraisEMetais: 0.000701; PotencialDeAquecimentoGlobalBiogenico: -0.48; CombustiveisFosseisComPotencialDeAquecimentoGlobal: 13.9; PotencialDeAquecimentoGlobalUsoDoSoloEMudancaDeUsoDoSolo: 0.0246; PotencialDeEutrofizacaoFraccaoDeNutrientesQueAtingemOCompartimentoFinalDeAguaDoce: 0.000189; PotencialDeEutrofizacaoFraccaoDeNutrientesQueAtingemOCompartimentoFinalMarinho: 0.0122; EnergiaRecuperada: 0.00739; ConsumoDeAguaDoce: 0.113; UtilizacaoLiquidaDeAguaDoce: 0.113; ResiduosPerigososEliminados: 0.00221; ResiduosNaoPerigososEliminados: 1.83; MassaTotalDeResiduosRadioactivosEliminados: 0.000394; EnergiaElectricaExportada: 1.55; MateriaisParaRecuperacaoDeEnergia: 0.00739; MateriaisParaReciclagem: 0.0253; UnidadeEPD: 1 m²
Type - IFC.REVIGRÉS-Dados gerais-Wall Covering - Nome: REVIGRÉS-OMNISTONE-BASE-60X60-MATT RECT-PLATINA; TipoProduto: Prensado a seco: grupo BIa UGL | Grés porcelânico técnico; NumeroDeRegistoDAP: EPD-REV-20240006-CCC1-EN; ReferenciaDAP: -; UrlDOP: -
Pset_WallCommon - ExtendToStructure: no; LoadBearing: no
IFC.REVIGRÉS-Dados do fabricante-Wall Covering - Type: Basic Wall: REVIGRÉS-OMNISTONE-BASE-60X60-MATTRECT-PLATINA
IFC.REVIGRÉS-Dados de desempenho-Wall Covering - Type: Basic Wall: REVIGRÉS-OMNISTONE-BASE-60X60-MATTRECT-PLATINA
IFC.REVIGRÉS-Dados de especificação-Wall Covering - Type: Basic Wall: REVIGRÉS-OMNISTONE-BASE-60X60-MATTRECT-PLATINA
IFC.REVIGRÉS-Dados geométricos-Wall Covering - Type: Basic Wall: REVIGRÉS-OMNISTONE-BASE-60X60-MATTRECT-PLATINA
IFC.REVIGRÉS-Dados de sustentabilidade-Wall Covering - Type: Basic Wall: REVIGRÉS-OMNISTONE-BASE-60X60-MATTRECT-PLATINA

# IfcWallStandardCase: Basic Wall:REVIGRÉS-OMNISTONE-BASE-60X60-MATTRECT-ROPE, Basic Wall:REVIGRÉS-OMNISTONE-BASE-60X60-MATTRECT-ROPE:151293
In: Level 1
Type - PredefinedType: STANDARD; Material: REVIGRÉS-OMNISTONE-BASE-60x60-MATTRECT-ROPE 9.8 mm
Type - Pset_ElementShading - Roughness: 304.8 mm
Type - Pset_ManufacturerTypeInformation - Manufacturer: REVIGRÉS
Type - Pset_ProductRequirements - Category: Walls
Type - Pset_QuantityTakeOff - Reference: 312BD393U1
Type - Pset_ReinforcementBarPitchOfWall - Description: Stone effect in wall and floor porcelain tile; Reference: 312BD393U1
Type - Pset_WallCommon - IsExternal: no; Reference: 312BD393U1
Type - IFC.REVIGRÉS-Dados do fabricante-Wall Covering - FabricanteURL: https://www.revigres.pt/; ReferenciaModelo: Omnistone; NumeroGlobalDeItemComercial: 312B1393U1; Acabamento: MATT RECT; Material: Grés porcelânico; IdentificadorDoOperadorEconomico: 501840856; UrlFabricanteArtigo: https://www.revigres.pt/colecoes/omnistone; PaisOrigem: Portugal
Type - IFC.REVIGRÉS-Dados de desempenho-Wall Covering - Rectilinearidade: ± 0.2% máx.± 0.8 mm; Ortogonalidade: ± 0.2% máx.± 1.5 mm; PlanaridadeDaSuperficie: ± 0.3% máx. ± 1.8 mm; QualidadeDaSuperficie: Cumpre; AbsorcaoDeAgua: < 0.05%; ModuloDeRuptura: > 45 N/mm130; ResistenciaAFlexao: ≥ 3500 N; ResistenciaAAbrasaoProfunda: < 120 mm131; DilatacaoTermicaLinear: ≤ 8,0x10-6 °C-1; ResistenciaAoChoqueTermico: Resiste; DurabilidadeResistenciaAoGeloDegelo: Resiste; ResistenciaAoEscorregamentoDIN51130: R10; ResistenciaAoEscorregamentoDIN51097: B; ResistenciaAoEscorregamentoENV51097: B; ResistenciaAoEscorregamentoENV12633: Class 2; ResistenciaAoEscorregamentoBS7976: >36; ResistenciaAoEscorregamentoANSIA1371: ≥0,42; ResistenciaAoDeslizamentoENV12633: Class 2; ResistenciaAoDeslizamentoBS7976: >36; ResistenciaAsManchas: Class 5; ResistenciaABaixasConcentracoesDeAcidosEAlcalis: Classe LA; ResistenciaAAltasConcentracoesDeAcidosEAlcalis: Classe HA; LibertacaoDeCadmio: 0; LibertacaoDeChumbo: 0
Type - IFC.REVIGRÉS-Dados de especificação-Wall Covering - VariacaoTonalidade: 3; NivelDeTrafego: 5; EPavimento: Sim; ERevestimento: Sim; EExterno: Sim
Type - IFC.REVIGRÉS-Dados geométricos-Wall Covering - AlturaNominal: 9.8 mm; ComprimentoNominal: 59.2 mm; LarguraNominal: 59.2 mm
Type - IFC.REVIGRÉS-Dados de sustentabilidade-Wall Covering - ItemEParcialmenteReciclado: 0; PotencialPrivacaoDeAguaConsumoDeAguaPonderado: 4.5; EnergiaTermicaExportada: 0; ItemENovo: Sim; ItemEReciclado: Não; VidaÚtilEsperada: 50; SubstanciasPerigosas: Não; PotencialDeEsgotamentoAbioticoDosRecursosNaoFosseisMineraisEMetais: 0.000701; PotencialDeAquecimentoGlobalBiogenico: -0.48; CombustiveisFosseisComPotencialDeAquecimentoGlobal: 13.9; PotencialDeAquecimentoGlobalUsoDoSoloEMudancaDeUsoDoSolo: 0.0246; PotencialDeEutrofizacaoFraccaoDeNutrientesQueAtingemOCompartimentoFinalDeAguaDoce: 0.000189; PotencialDeEutrofizacaoFraccaoDeNutrientesQueAtingemOCompartimentoFinalMarinho: 0.0122; EnergiaRecuperada: 0.00739; ConsumoDeAguaDoce: 0.113; UtilizacaoLiquidaDeAguaDoce: 0.113; ResiduosPerigososEliminados: 0.00221; ResiduosNaoPerigososEliminados: 1.83; MassaTotalDeResiduosRadioactivosEliminados: 0.000394; EnergiaElectricaExportada: 1.55; MateriaisParaRecuperacaoDeEnergia: 0.00739; MateriaisParaReciclagem: 0.0253; UnidadeEPD: 1 m²
Type - IFC.REVIGRÉS-Dados gerais-Wall Covering - Nome: REVIGRÉS-OMNISTONE-BASE-60X60-MATT RECT-ROPE; TipoProduto: Prensado a seco: grupo BIa UGL | Grés porcelânico técnico; NumeroDeRegistoDAP: EPD-REV-20240006-CCC1-EN; ReferenciaDAP: -; UrlDOP: -
Pset_WallCommon - ExtendToStructure: no; LoadBearing: no
IFC.REVIGRÉS-Dados do fabricante-Wall Covering - Type: Basic Wall: REVIGRÉS-OMNISTONE-BASE-60X60-MATTRECT-ROPE
IFC.REVIGRÉS-Dados de desempenho-Wall Covering - Type: Basic Wall: REVIGRÉS-OMNISTONE-BASE-60X60-MATTRECT-ROPE
IFC.REVIGRÉS-Dados de especificação-Wall Covering - Type: Basic Wall: REVIGRÉS-OMNISTONE-BASE-60X60-MATTRECT-ROPE
IFC.REVIGRÉS-Dados geométricos-Wall Covering - Type: Basic Wall: REVIGRÉS-OMNISTONE-BASE-60X60-MATTRECT-ROPE
IFC.REVIGRÉS-Dados de sustentabilidade-Wall Covering - Type: Basic Wall: REVIGRÉS-OMNISTONE-BASE-60X60-MATTRECT-ROPE

# IfcWallStandardCase: Basic Wall:REVIGRÉS-OMNISTONE-BASE-60X60-SOFT-BONE, Basic Wall:REVIGRÉS-OMNISTONE-BASE-60X60-SOFT-BONE:146511
In: Level 1
Type - PredefinedType: STANDARD; Material: REVIGRÉS-OMNISTONE-BASE-60x60-SOFT-BONE 9.8 mm
Type - Pset_ElementShading - Roughness: 304.8 mm
Type - Pset_ManufacturerTypeInformation - Manufacturer: REVIGRÉS
Type - Pset_ProductRequirements - Category: Walls
Type - Pset_QuantityTakeOff - Reference: 3126D388U1
Type - Pset_ReinforcementBarPitchOfWall - Description: Stone effect in wall and floor porcelain tile; Reference: 3126D388U1
Type - Pset_WallCommon - IsExternal: no; Reference: 3126D388U1
Type - IFC.REVIGRÉS-Dados do fabricante-Wall Covering - FabricanteURL: https://www.revigres.pt/; ReferenciaModelo: Omnistone; NumeroGlobalDeItemComercial: 31261388U1; Acabamento: SOFT; Material: Grés porcelânico; IdentificadorDoOperadorEconomico: 501840856; UrlFabricanteArtigo: https://www.revigres.pt/colecoes/omnistone; PaisOrigem: Portugal
Type - IFC.REVIGRÉS-Dados de desempenho-Wall Covering - Rectilinearidade: ± 0.2% máx.± 0.8 mm; Ortogonalidade: ± 0.2% máx.± 1.5 mm; PlanaridadeDaSuperficie: ± 0.3% máx. ± 1.8 mm; QualidadeDaSuperficie: Cumpre; AbsorcaoDeAgua: < 0.05%; ModuloDeRuptura: > 45 N/mm130; ResistenciaAFlexao: ≥ 3500 N; ResistenciaAAbrasaoProfunda: < 120 mm131; DilatacaoTermicaLinear: ≤ 8,0x10-6 °C-1; ResistenciaAoChoqueTermico: Resiste; DurabilidadeResistenciaAoGeloDegelo: Resiste; ResistenciaAsManchas: Class 5; ResistenciaABaixasConcentracoesDeAcidosEAlcalis: Classe LA; ResistenciaAAltasConcentracoesDeAcidosEAlcalis: Classe HA; LibertacaoDeCadmio: 0; LibertacaoDeChumbo: 0
Type - IFC.REVIGRÉS-Dados de especificação-Wall Covering - VariacaoTonalidade: 3; NivelDeTrafego: 5; EPavimento: Sim; ERevestimento: Sim; EExterno: Sim
Type - IFC.REVIGRÉS-Dados geométricos-Wall Covering - AlturaNominal: 9.8 mm; ComprimentoNominal: 59.2 mm; LarguraNominal: 59.2 mm
Type - IFC.REVIGRÉS-Dados de sustentabilidade-Wall Covering - ItemEParcialmenteReciclado: 0; PotencialPrivacaoDeAguaConsumoDeAguaPonderado: 4.5; EnergiaTermicaExportada: 0; ItemENovo: Sim; ItemEReciclado: Não; VidaÚtilEsperada: 50; SubstanciasPerigosas: Não; PotencialDeEsgotamentoAbioticoDosRecursosNaoFosseisMineraisEMetais: 0.000701; PotencialDeAquecimentoGlobalBiogenico: -0.48; CombustiveisFosseisComPotencialDeAquecimentoGlobal: 13.9; PotencialDeAquecimentoGlobalUsoDoSoloEMudancaDeUsoDoSolo: 0.0246; PotencialDeEutrofizacaoFraccaoDeNutrientesQueAtingemOCompartimentoFinalDeAguaDoce: 0.000189; PotencialDeEutrofizacaoFraccaoDeNutrientesQueAtingemOCompartimentoFinalMarinho: 0.0122; EnergiaRecuperada: 0.00739; ConsumoDeAguaDoce: 0.113; UtilizacaoLiquidaDeAguaDoce: 0.113; ResiduosPerigososEliminados: 0.00221; ResiduosNaoPerigososEliminados: 1.83; MassaTotalDeResiduosRadioactivosEliminados: 0.000394; EnergiaElectricaExportada: 1.55; MateriaisParaRecuperacaoDeEnergia: 0.00739; MateriaisParaReciclagem: 0.0253; UnidadeEPD: 1 m²
Type - IFC.REVIGRÉS-Dados gerais-Wall Covering - Nome: REVIGRÉS-OMNISTONE-BASE-60X60-SOFT-BONE; TipoProduto: Prensado a seco: grupo BIa UGL | Grés porcelânico técnico; NumeroDeRegistoDAP: EPD-REV-20240006-CCC1-EN; ReferenciaDAP: -; UrlDOP: -
Pset_WallCommon - ExtendToStructure: no; LoadBearing: no
IFC.REVIGRÉS-Dados do fabricante-Wall Covering - Type: Basic Wall: REVIGRÉS-OMNISTONE-BASE-60X60-SOFT-BONE
IFC.REVIGRÉS-Dados de desempenho-Wall Covering - Type: Basic Wall: REVIGRÉS-OMNISTONE-BASE-60X60-SOFT-BONE
IFC.REVIGRÉS-Dados de especificação-Wall Covering - Type: Basic Wall: REVIGRÉS-OMNISTONE-BASE-60X60-SOFT-BONE
IFC.REVIGRÉS-Dados geométricos-Wall Covering - Type: Basic Wall: REVIGRÉS-OMNISTONE-BASE-60X60-SOFT-BONE
IFC.REVIGRÉS-Dados de sustentabilidade-Wall Covering - Type: Basic Wall: REVIGRÉS-OMNISTONE-BASE-60X60-SOFT-BONE

# IfcWallStandardCase: Basic Wall:REVIGRÉS-OMNISTONE-BASE-60X60-SOFT-ICE, Basic Wall:REVIGRÉS-OMNISTONE-BASE-60X60-SOFT-ICE:148520
In: Level 1
Type - PredefinedType: STANDARD; Material: REVIGRÉS-OMNISTONE-BASE-60x60-SOFT-ICE 9.8 mm
Type - Pset_ElementShading - Roughness: 304.8 mm
Type - Pset_ManufacturerTypeInformation - Manufacturer: REVIGRÉS
Type - Pset_ProductRequirements - Category: Walls
Type - Pset_QuantityTakeOff - Reference: 3126D389U1
Type - Pset_ReinforcementBarPitchOfWall - Description: Stone effect in wall and floor porcelain tile; Reference: 3126D389U1
Type - Pset_WallCommon - IsExternal: no; Reference: 3126D389U1
Type - IFC.REVIGRÉS-Dados do fabricante-Wall Covering - FabricanteURL: https://www.revigres.pt/; ReferenciaModelo: Omnistone; NumeroGlobalDeItemComercial: 31261389U1; Acabamento: SOFT; Material: Grés porcelânico; IdentificadorDoOperadorEconomico: 501840856; UrlFabricanteArtigo: https://www.revigres.pt/colecoes/omnistone; PaisOrigem: Portugal
Type - IFC.REVIGRÉS-Dados de desempenho-Wall Covering - Rectilinearidade: ± 0.2% máx.± 0.8 mm; Ortogonalidade: ± 0.2% máx.± 1.5 mm; PlanaridadeDaSuperficie: ± 0.3% máx. ± 1.8 mm; QualidadeDaSuperficie: Cumpre; AbsorcaoDeAgua: < 0.05%; ModuloDeRuptura: > 45 N/mm130; ResistenciaAFlexao: ≥ 3500 N; ResistenciaAAbrasaoProfunda: < 120 mm131; DilatacaoTermicaLinear: ≤ 8,0x10-6 °C-1; ResistenciaAoChoqueTermico: Resiste; DurabilidadeResistenciaAoGeloDegelo: Resiste; ResistenciaAsManchas: Class 5; ResistenciaABaixasConcentracoesDeAcidosEAlcalis: Classe LA; ResistenciaAAltasConcentracoesDeAcidosEAlcalis: Classe HA; LibertacaoDeCadmio: 0; LibertacaoDeChumbo: 0
Type - IFC.REVIGRÉS-Dados de especificação-Wall Covering - VariacaoTonalidade: 3; NivelDeTrafego: 5; EPavimento: Sim; ERevestimento: Sim; EExterno: Sim
Type - IFC.REVIGRÉS-Dados geométricos-Wall Covering - AlturaNominal: 9.8 mm; ComprimentoNominal: 59.2 mm; LarguraNominal: 59.2 mm
Type - IFC.REVIGRÉS-Dados de sustentabilidade-Wall Covering - ItemEParcialmenteReciclado: 0; PotencialPrivacaoDeAguaConsumoDeAguaPonderado: 4.5; EnergiaTermicaExportada: 0; ItemENovo: Sim; ItemEReciclado: Não; VidaÚtilEsperada: 50; SubstanciasPerigosas: Não; PotencialDeEsgotamentoAbioticoDosRecursosNaoFosseisMineraisEMetais: 0.000701; PotencialDeAquecimentoGlobalBiogenico: -0.48; CombustiveisFosseisComPotencialDeAquecimentoGlobal: 13.9; PotencialDeAquecimentoGlobalUsoDoSoloEMudancaDeUsoDoSolo: 0.0246; PotencialDeEutrofizacaoFraccaoDeNutrientesQueAtingemOCompartimentoFinalDeAguaDoce: 0.000189; PotencialDeEutrofizacaoFraccaoDeNutrientesQueAtingemOCompartimentoFinalMarinho: 0.0122; EnergiaRecuperada: 0.00739; ConsumoDeAguaDoce: 0.113; UtilizacaoLiquidaDeAguaDoce: 0.113; ResiduosPerigososEliminados: 0.00221; ResiduosNaoPerigososEliminados: 1.83; MassaTotalDeResiduosRadioactivosEliminados: 0.000394; EnergiaElectricaExportada: 1.55; MateriaisParaRecuperacaoDeEnergia: 0.00739; MateriaisParaReciclagem: 0.0253; UnidadeEPD: 1 m²
Type - IFC.REVIGRÉS-Dados gerais-Wall Covering - Nome: REVIGRÉS-OMNISTONE-BASE-60X60-SOFT-ICE; TipoProduto: Prensado a seco: grupo BIa UGL | Grés porcelânico técnico; NumeroDeRegistoDAP: EPD-REV-20240006-CCC1-EN; ReferenciaDAP: -; UrlDOP: -
Pset_WallCommon - ExtendToStructure: no; LoadBearing: no
IFC.REVIGRÉS-Dados do fabricante-Wall Covering - Type: Basic Wall: REVIGRÉS-OMNISTONE-BASE-60X60-SOFT-ICE
IFC.REVIGRÉS-Dados de desempenho-Wall Covering - Type: Basic Wall: REVIGRÉS-OMNISTONE-BASE-60X60-SOFT-ICE
IFC.REVIGRÉS-Dados de especificação-Wall Covering - Type: Basic Wall: REVIGRÉS-OMNISTONE-BASE-60X60-SOFT-ICE
IFC.REVIGRÉS-Dados geométricos-Wall Covering - Type: Basic Wall: REVIGRÉS-OMNISTONE-BASE-60X60-SOFT-ICE
IFC.REVIGRÉS-Dados de sustentabilidade-Wall Covering - Type: Basic Wall: REVIGRÉS-OMNISTONE-BASE-60X60-SOFT-ICE

# IfcWallStandardCase: Basic Wall:REVIGRÉS-OMNISTONE-BASE-60X60-SOFT-IRON, Basic Wall:REVIGRÉS-OMNISTONE-BASE-60X60-SOFT-IRON:149205
In: Level 1
Type - PredefinedType: STANDARD; Material: REVIGRÉS-OMNISTONE-BASE-60x60-SOFT-IRON 9.8 mm
Type - Pset_ElementShading - Roughness: 304.8 mm
Type - Pset_ManufacturerTypeInformation - Manufacturer: REVIGRÉS
Type - Pset_ProductRequirements - Category: Walls
Type - Pset_QuantityTakeOff - Reference: 3126D390U1
Type - Pset_ReinforcementBarPitchOfWall - Description: Stone effect in wall and floor porcelain tile; Reference: 3126D390U1
Type - Pset_WallCommon - IsExternal: no; Reference: 3126D390U1
Type - IFC.REVIGRÉS-Dados do fabricante-Wall Covering - FabricanteURL: https://www.revigres.pt/; ReferenciaModelo: Omnistone; NumeroGlobalDeItemComercial: 31261390U1; Acabamento: SOFT; Material: Grés porcelânico; IdentificadorDoOperadorEconomico: 501840856; UrlFabricanteArtigo: https://www.revigres.pt/colecoes/omnistone; PaisOrigem: Portugal
Type - IFC.REVIGRÉS-Dados de desempenho-Wall Covering - Rectilinearidade: ± 0.2% máx.± 0.8 mm; Ortogonalidade: ± 0.2% máx.± 1.5 mm; PlanaridadeDaSuperficie: ± 0.3% máx. ± 1.8 mm; QualidadeDaSuperficie: Cumpre; AbsorcaoDeAgua: < 0.05%; ModuloDeRuptura: > 45 N/mm130; ResistenciaAFlexao: ≥ 3500 N; ResistenciaAAbrasaoProfunda: < 120 mm131; DilatacaoTermicaLinear: ≤ 8,0x10-6 °C-1; ResistenciaAoChoqueTermico: Resiste; DurabilidadeResistenciaAoGeloDegelo: Resiste; ResistenciaAsManchas: Class 5; ResistenciaABaixasConcentracoesDeAcidosEAlcalis: Classe LA; ResistenciaAAltasConcentracoesDeAcidosEAlcalis: Classe HA; LibertacaoDeCadmio: 0; LibertacaoDeChumbo: 0
Type - IFC.REVIGRÉS-Dados de especificação-Wall Covering - VariacaoTonalidade: 3; NivelDeTrafego: 5; EPavimento: Sim; ERevestimento: Sim; EExterno: Sim
Type - IFC.REVIGRÉS-Dados geométricos-Wall Covering - AlturaNominal: 9.8 mm; ComprimentoNominal: 59.2 mm; LarguraNominal: 59.2 mm
Type - IFC.REVIGRÉS-Dados de sustentabilidade-Wall Covering - PotencialPrivacaoDeAguaConsumoDeAguaPonderado: 4.5; EnergiaTermicaExportada: 0; ItemENovo: Sim; ItemEParcialmenteReciclado: 0.14; ItemEReciclado: Sim; VidaÚtilEsperada: 50; SubstanciasPerigosas: Não; PotencialDeEsgotamentoAbioticoDosRecursosNaoFosseisMineraisEMetais: 0.000701; PotencialDeAquecimentoGlobalBiogenico: -0.48; CombustiveisFosseisComPotencialDeAquecimentoGlobal: 13.9; PotencialDeAquecimentoGlobalUsoDoSoloEMudancaDeUsoDoSolo: 0.0246; PotencialDeEutrofizacaoFraccaoDeNutrientesQueAtingemOCompartimentoFinalDeAguaDoce: 0.000189; PotencialDeEutrofizacaoFraccaoDeNutrientesQueAtingemOCompartimentoFinalMarinho: 0.0122; EnergiaRecuperada: 0.00739; ConsumoDeAguaDoce: 0.113; UtilizacaoLiquidaDeAguaDoce: 0.113; ResiduosPerigososEliminados: 0.00221; ResiduosNaoPerigososEliminados: 1.83; MassaTotalDeResiduosRadioactivosEliminados: 0.000394; EnergiaElectricaExportada: 1.55; MateriaisParaRecuperacaoDeEnergia: 0.00739; MateriaisParaReciclagem: 0.0253; UnidadeEPD: 1 m²
Type - IFC.REVIGRÉS-Dados gerais-Wall Covering - Nome: REVIGRÉS-OMNISTONE-BASE-60X60-SOFT-IRON; TipoProduto: Prensado a seco: grupo BIa UGL | Grés porcelânico técnico; NumeroDeRegistoDAP: EPD-REV-20240006-CCC1-EN; ReferenciaDAP: -; UrlDOP: -
Pset_WallCommon - ExtendToStructure: no; LoadBearing: no
IFC.REVIGRÉS-Dados do fabricante-Wall Covering - Type: Basic Wall: REVIGRÉS-OMNISTONE-BASE-60X60-SOFT-IRON
IFC.REVIGRÉS-Dados de desempenho-Wall Covering - Type: Basic Wall: REVIGRÉS-OMNISTONE-BASE-60X60-SOFT-IRON
IFC.REVIGRÉS-Dados de especificação-Wall Covering - Type: Basic Wall: REVIGRÉS-OMNISTONE-BASE-60X60-SOFT-IRON
IFC.REVIGRÉS-Dados geométricos-Wall Covering - Type: Basic Wall: REVIGRÉS-OMNISTONE-BASE-60X60-SOFT-IRON
IFC.REVIGRÉS-Dados de sustentabilidade-Wall Covering - Type: Basic Wall: REVIGRÉS-OMNISTONE-BASE-60X60-SOFT-IRON

# IfcWallStandardCase: Basic Wall:REVIGRÉS-OMNISTONE-BASE-60X60-SOFT-JET, Basic Wall:REVIGRÉS-OMNISTONE-BASE-60X60-SOFT-JET:149947
In: Level 1
Type - PredefinedType: STANDARD; Material: REVIGRÉS-OMNISTONE-BASE-60x60-SOFT-JET 9.8 mm
Type - Pset_ElementShading - Roughness: 304.8 mm
Type - Pset_ManufacturerTypeInformation - Manufacturer: REVIGRÉS
Type - Pset_ProductRequirements - Category: Walls
Type - Pset_QuantityTakeOff - Reference: 3126D391U1
Type - Pset_ReinforcementBarPitchOfWall - Description: Stone effect in wall and floor porcelain tile; Reference: 3126D391U1
Type - Pset_WallCommon - IsExternal: no; Reference: 3126D391U1
Type - IFC.REVIGRÉS-Dados do fabricante-Wall Covering - FabricanteURL: https://www.revigres.pt/; ReferenciaModelo: Omnistone; NumeroGlobalDeItemComercial: 31261391U1; Acabamento: SOFT; Material: Grés porcelânico; IdentificadorDoOperadorEconomico: 501840856; UrlFabricanteArtigo: https://www.revigres.pt/colecoes/omnistone; PaisOrigem: Portugal
Type - IFC.REVIGRÉS-Dados de desempenho-Wall Covering - Rectilinearidade: ± 0.2% máx.± 0.8 mm; Ortogonalidade: ± 0.2% máx.± 1.5 mm; PlanaridadeDaSuperficie: ± 0.3% máx. ± 1.8 mm; QualidadeDaSuperficie: Cumpre; AbsorcaoDeAgua: < 0.05%; ModuloDeRuptura: > 45 N/mm130; ResistenciaAFlexao: ≥ 3500 N; ResistenciaAAbrasaoProfunda: < 120 mm131; DilatacaoTermicaLinear: ≤ 8,0x10-6 °C-1; ResistenciaAoChoqueTermico: Resiste; DurabilidadeResistenciaAoGeloDegelo: Resiste; ResistenciaAsManchas: Class 5; ResistenciaABaixasConcentracoesDeAcidosEAlcalis: Classe LA; ResistenciaAAltasConcentracoesDeAcidosEAlcalis: Classe HA; LibertacaoDeCadmio: 0; LibertacaoDeChumbo: 0
Type - IFC.REVIGRÉS-Dados de especificação-Wall Covering - VariacaoTonalidade: 3; NivelDeTrafego: 5; EPavimento: Sim; ERevestimento: Sim; EExterno: Sim
Type - IFC.REVIGRÉS-Dados geométricos-Wall Covering - AlturaNominal: 9.8 mm; ComprimentoNominal: 59.2 mm; LarguraNominal: 59.2 mm
Type - IFC.REVIGRÉS-Dados de sustentabilidade-Wall Covering - ItemEParcialmenteReciclado: 0; PotencialPrivacaoDeAguaConsumoDeAguaPonderado: 4.5; EnergiaTermicaExportada: 0; ItemENovo: Sim; ItemEReciclado: Não; VidaÚtilEsperada: 50; SubstanciasPerigosas: Não; PotencialDeEsgotamentoAbioticoDosRecursosNaoFosseisMineraisEMetais: 0.000701; PotencialDeAquecimentoGlobalBiogenico: -0.48; CombustiveisFosseisComPotencialDeAquecimentoGlobal: 13.9; PotencialDeAquecimentoGlobalUsoDoSoloEMudancaDeUsoDoSolo: 0.0246; PotencialDeEutrofizacaoFraccaoDeNutrientesQueAtingemOCompartimentoFinalDeAguaDoce: 0.000189; PotencialDeEutrofizacaoFraccaoDeNutrientesQueAtingemOCompartimentoFinalMarinho: 0.0122; EnergiaRecuperada: 0.00739; ConsumoDeAguaDoce: 0.113; UtilizacaoLiquidaDeAguaDoce: 0.113; ResiduosPerigososEliminados: 0.00221; ResiduosNaoPerigososEliminados: 1.83; MassaTotalDeResiduosRadioactivosEliminados: 0.000394; EnergiaElectricaExportada: 1.55; MateriaisParaRecuperacaoDeEnergia: 0.00739; MateriaisParaReciclagem: 0.0253; UnidadeEPD: 1 m²
Type - IFC.REVIGRÉS-Dados gerais-Wall Covering - Nome: REVIGRÉS-OMNISTONE-BASE-60X60-SOFT-JET; TipoProduto: Prensado a seco: grupo BIa UGL | Grés porcelânico técnico; NumeroDeRegistoDAP: EPD-REV-20240006-CCC1-EN; ReferenciaDAP: -; UrlDOP: -
Pset_WallCommon - ExtendToStructure: no; LoadBearing: no
IFC.REVIGRÉS-Dados do fabricante-Wall Covering - Type: Basic Wall: REVIGRÉS-OMNISTONE-BASE-60X60-SOFT-JET
IFC.REVIGRÉS-Dados de desempenho-Wall Covering - Type: Basic Wall: REVIGRÉS-OMNISTONE-BASE-60X60-SOFT-JET
IFC.REVIGRÉS-Dados de especificação-Wall Covering - Type: Basic Wall: REVIGRÉS-OMNISTONE-BASE-60X60-SOFT-JET
IFC.REVIGRÉS-Dados geométricos-Wall Covering - Type: Basic Wall: REVIGRÉS-OMNISTONE-BASE-60X60-SOFT-JET
IFC.REVIGRÉS-Dados de sustentabilidade-Wall Covering - Type: Basic Wall: REVIGRÉS-OMNISTONE-BASE-60X60-SOFT-JET

# IfcWallStandardCase: Basic Wall:REVIGRÉS-OMNISTONE-BASE-60X60-SOFT-PLATINA, Basic Wall:REVIGRÉS-OMNISTONE-BASE-60X60-SOFT-PLATINA:150668
In: Level 1
Type - PredefinedType: STANDARD; Material: REVIGRÉS-OMNISTONE-BASE-60x60-SOFT-PLATINA 9.8 mm
Type - Pset_ElementShading - Roughness: 304.8 mm
Type - Pset_ManufacturerTypeInformation - Manufacturer: REVIGRÉS
Type - Pset_ProductRequirements - Category: Walls
Type - Pset_QuantityTakeOff - Reference: 3126D392U1
Type - Pset_ReinforcementBarPitchOfWall - Description: Stone effect in wall and floor porcelain tile; Reference: 3126D392U1
Type - Pset_WallCommon - IsExternal: no; Reference: 3126D392U1
Type - IFC.REVIGRÉS-Dados do fabricante-Wall Covering - FabricanteURL: https://www.revigres.pt/; ReferenciaModelo: Omnistone; NumeroGlobalDeItemComercial: 31261392U1; Acabamento: SOFT; Material: Grés porcelânico; IdentificadorDoOperadorEconomico: 501840856; UrlFabricanteArtigo: https://www.revigres.pt/colecoes/omnistone; PaisOrigem: Portugal
Type - IFC.REVIGRÉS-Dados de desempenho-Wall Covering - Rectilinearidade: ± 0.2% máx.± 0.8 mm; Ortogonalidade: ± 0.2% máx.± 1.5 mm; PlanaridadeDaSuperficie: ± 0.3% máx. ± 1.8 mm; QualidadeDaSuperficie: Cumpre; AbsorcaoDeAgua: < 0.05%; ModuloDeRuptura: > 45 N/mm130; ResistenciaAFlexao: ≥ 3500 N; ResistenciaAAbrasaoProfunda: < 120 mm131; DilatacaoTermicaLinear: ≤ 8,0x10-6 °C-1; ResistenciaAoChoqueTermico: Resiste; DurabilidadeResistenciaAoGeloDegelo: Resiste; ResistenciaAsManchas: Class 5; ResistenciaABaixasConcentracoesDeAcidosEAlcalis: Classe LA; ResistenciaAAltasConcentracoesDeAcidosEAlcalis: Classe HA; LibertacaoDeCadmio: 0; LibertacaoDeChumbo: 0
Type - IFC.REVIGRÉS-Dados de especificação-Wall Covering - VariacaoTonalidade: 3; NivelDeTrafego: 5; EPavimento: Sim; ERevestimento: Sim; EExterno: Sim
Type - IFC.REVIGRÉS-Dados geométricos-Wall Covering - AlturaNominal: 9.8 mm; ComprimentoNominal: 59.2 mm; LarguraNominal: 59.2 mm
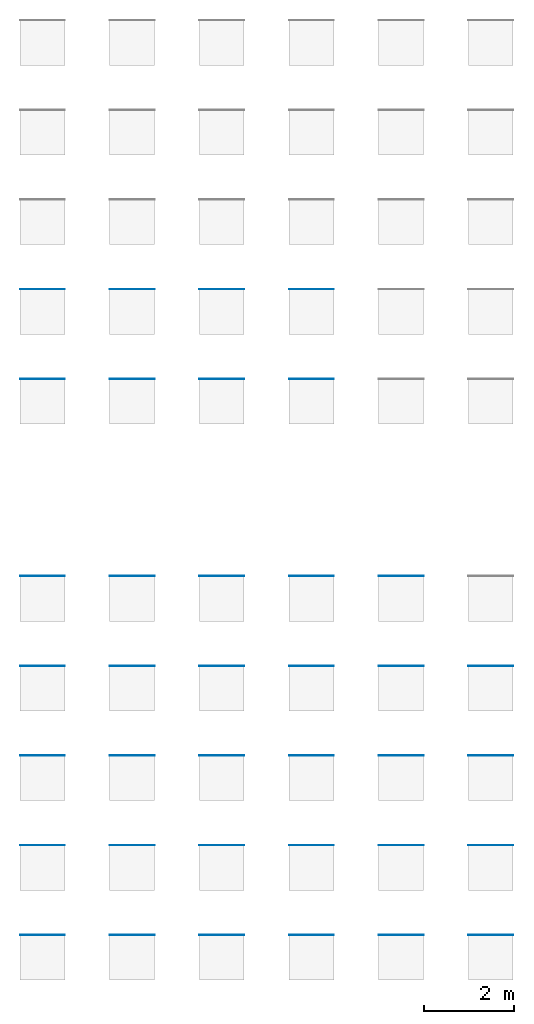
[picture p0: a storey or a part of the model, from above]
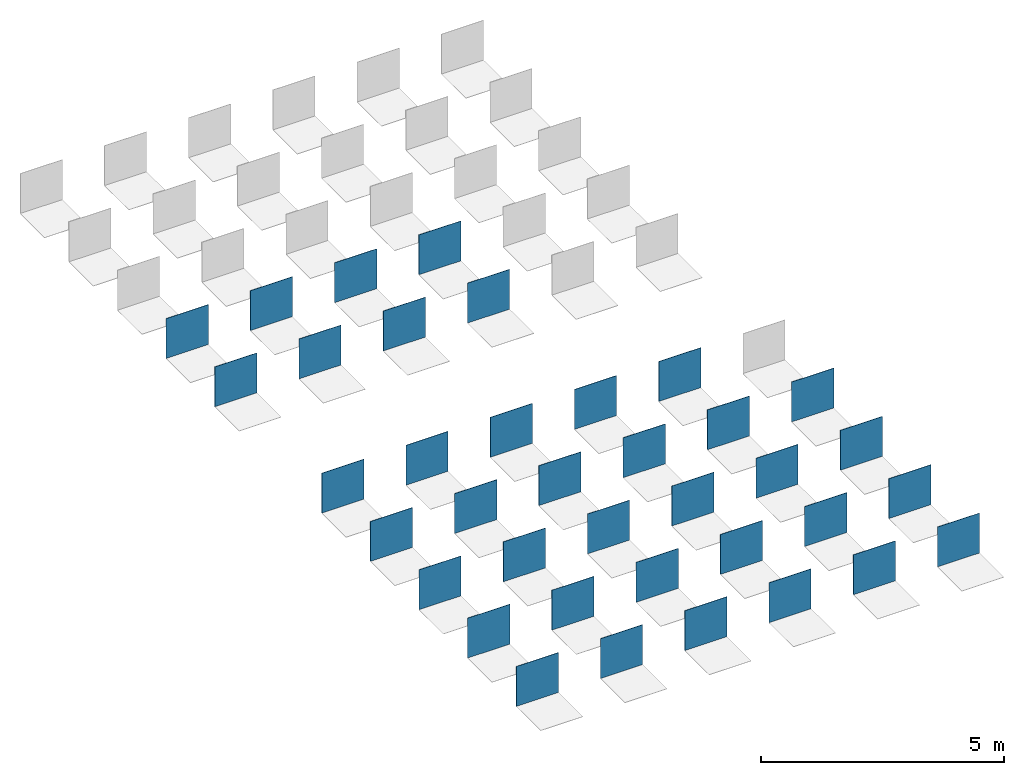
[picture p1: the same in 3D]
Properties of the parts of a building model (IFC2X3), part 8 of 8

# IfcWallStandardCase: Basic Wall:REVIGRÉS-OMNISTONE-BASE-60X60-SOFT-PLATINA, Basic Wall:REVIGRÉS-OMNISTONE-BASE-60X60-SOFT-PLATINA:150668
Type - IFC.REVIGRÉS-Dados de sustentabilidade-Wall Covering - ItemEParcialmenteReciclado: 0; PotencialPrivacaoDeAguaConsumoDeAguaPonderado: 4.5; EnergiaTermicaExportada: 0; ItemENovo: Sim; ItemEReciclado: Não; VidaÚtilEsperada: 50; SubstanciasPerigosas: Não; PotencialDeEsgotamentoAbioticoDosRecursosNaoFosseisMineraisEMetais: 0.000701; PotencialDeAquecimentoGlobalBiogenico: -0.48; CombustiveisFosseisComPotencialDeAquecimentoGlobal: 13.9; PotencialDeAquecimentoGlobalUsoDoSoloEMudancaDeUsoDoSolo: 0.0246; PotencialDeEutrofizacaoFraccaoDeNutrientesQueAtingemOCompartimentoFinalDeAguaDoce: 0.000189; PotencialDeEutrofizacaoFraccaoDeNutrientesQueAtingemOCompartimentoFinalMarinho: 0.0122; EnergiaRecuperada: 0.00739; ConsumoDeAguaDoce: 0.113; UtilizacaoLiquidaDeAguaDoce: 0.113; ResiduosPerigososEliminados: 0.00221; ResiduosNaoPerigososEliminados: 1.83; MassaTotalDeResiduosRadioactivosEliminados: 0.000394; EnergiaElectricaExportada: 1.55; MateriaisParaRecuperacaoDeEnergia: 0.00739; MateriaisParaReciclagem: 0.0253; UnidadeEPD: 1 m²
Type - IFC.REVIGRÉS-Dados gerais-Wall Covering - Nome: REVIGRÉS-OMNISTONE-BASE-60X60-SOFT-PLATINA; TipoProduto: Prensado a seco: grupo BIa UGL | Grés porcelânico técnico; NumeroDeRegistoDAP: EPD-REV-20240006-CCC1-EN; ReferenciaDAP: -; UrlDOP: -
Pset_WallCommon - ExtendToStructure: no; LoadBearing: no
IFC.REVIGRÉS-Dados do fabricante-Wall Covering - Type: Basic Wall: REVIGRÉS-OMNISTONE-BASE-60X60-SOFT-PLATINA
IFC.REVIGRÉS-Dados de desempenho-Wall Covering - Type: Basic Wall: REVIGRÉS-OMNISTONE-BASE-60X60-SOFT-PLATINA
IFC.REVIGRÉS-Dados de especificação-Wall Covering - Type: Basic Wall: REVIGRÉS-OMNISTONE-BASE-60X60-SOFT-PLATINA
IFC.REVIGRÉS-Dados geométricos-Wall Covering - Type: Basic Wall: REVIGRÉS-OMNISTONE-BASE-60X60-SOFT-PLATINA
IFC.REVIGRÉS-Dados de sustentabilidade-Wall Covering - Type: Basic Wall: REVIGRÉS-OMNISTONE-BASE-60X60-SOFT-PLATINA

# IfcWallStandardCase: Basic Wall:REVIGRÉS-OMNISTONE-BASE-60X60-SOFT-ROPE, Basic Wall:REVIGRÉS-OMNISTONE-BASE-60X60-SOFT-ROPE:151373
In: Level 1
Type - PredefinedType: STANDARD; Material: REVIGRÉS-OMNISTONE-BASE-60x60-SOFT-ROPE 9.8 mm
Type - Pset_ElementShading - Roughness: 304.8 mm
Type - Pset_ManufacturerTypeInformation - Manufacturer: REVIGRÉS
Type - Pset_ProductRequirements - Category: Walls
Type - Pset_QuantityTakeOff - Reference: 3126D393U1
Type - Pset_ReinforcementBarPitchOfWall - Description: Stone effect in wall and floor porcelain tile; Reference: 3126D393U1
Type - Pset_WallCommon - IsExternal: no; Reference: 3126D393U1
Type - IFC.REVIGRÉS-Dados do fabricante-Wall Covering - FabricanteURL: https://www.revigres.pt/; ReferenciaModelo: Omnistone; NumeroGlobalDeItemComercial: 31261393U1; Acabamento: SOFT; Material: Grés porcelânico; IdentificadorDoOperadorEconomico: 501840856; UrlFabricanteArtigo: https://www.revigres.pt/colecoes/omnistone; PaisOrigem: Portugal
Type - IFC.REVIGRÉS-Dados de desempenho-Wall Covering - Rectilinearidade: ± 0.2% máx.± 0.8 mm; Ortogonalidade: ± 0.2% máx.± 1.5 mm; PlanaridadeDaSuperficie: ± 0.3% máx. ± 1.8 mm; QualidadeDaSuperficie: Cumpre; AbsorcaoDeAgua: < 0.05%; ModuloDeRuptura: > 45 N/mm130; ResistenciaAFlexao: ≥ 3500 N; ResistenciaAAbrasaoProfunda: < 120 mm131; DilatacaoTermicaLinear: ≤ 8,0x10-6 °C-1; ResistenciaAoChoqueTermico: Resiste; DurabilidadeResistenciaAoGeloDegelo: Resiste; ResistenciaAsManchas: Class 5; ResistenciaABaixasConcentracoesDeAcidosEAlcalis: Classe LA; ResistenciaAAltasConcentracoesDeAcidosEAlcalis: Classe HA; LibertacaoDeCadmio: 0; LibertacaoDeChumbo: 0
Type - IFC.REVIGRÉS-Dados de especificação-Wall Covering - VariacaoTonalidade: 3; NivelDeTrafego: 5; EPavimento: Sim; ERevestimento: Sim; EExterno: Sim
Type - IFC.REVIGRÉS-Dados geométricos-Wall Covering - AlturaNominal: 9.8 mm; ComprimentoNominal: 59.2 mm; LarguraNominal: 59.2 mm
Type - IFC.REVIGRÉS-Dados de sustentabilidade-Wall Covering - ItemEParcialmenteReciclado: 0; PotencialPrivacaoDeAguaConsumoDeAguaPonderado: 4.5; EnergiaTermicaExportada: 0; ItemENovo: Sim; ItemEReciclado: Não; VidaÚtilEsperada: 50; SubstanciasPerigosas: Não; PotencialDeEsgotamentoAbioticoDosRecursosNaoFosseisMineraisEMetais: 0.000701; PotencialDeAquecimentoGlobalBiogenico: -0.48; CombustiveisFosseisComPotencialDeAquecimentoGlobal: 13.9; PotencialDeAquecimentoGlobalUsoDoSoloEMudancaDeUsoDoSolo: 0.0246; PotencialDeEutrofizacaoFraccaoDeNutrientesQueAtingemOCompartimentoFinalDeAguaDoce: 0.000189; PotencialDeEutrofizacaoFraccaoDeNutrientesQueAtingemOCompartimentoFinalMarinho: 0.0122; EnergiaRecuperada: 0.00739; ConsumoDeAguaDoce: 0.113; UtilizacaoLiquidaDeAguaDoce: 0.113; ResiduosPerigososEliminados: 0.00221; ResiduosNaoPerigososEliminados: 1.83; MassaTotalDeResiduosRadioactivosEliminados: 0.000394; EnergiaElectricaExportada: 1.55; MateriaisParaRecuperacaoDeEnergia: 0.00739; MateriaisParaReciclagem: 0.0253; UnidadeEPD: 1 m²
Type - IFC.REVIGRÉS-Dados gerais-Wall Covering - Nome: REVIGRÉS-OMNISTONE-BASE-60X60-SOFT-ROPE; TipoProduto: Prensado a seco: grupo BIa UGL | Grés porcelânico técnico; NumeroDeRegistoDAP: EPD-REV-20240006-CCC1-EN; ReferenciaDAP: -; UrlDOP: -
Pset_WallCommon - ExtendToStructure: no; LoadBearing: no
IFC.REVIGRÉS-Dados do fabricante-Wall Covering - Type: Basic Wall: REVIGRÉS-OMNISTONE-BASE-60X60-SOFT-ROPE
IFC.REVIGRÉS-Dados de desempenho-Wall Covering - Type: Basic Wall: REVIGRÉS-OMNISTONE-BASE-60X60-SOFT-ROPE
IFC.REVIGRÉS-Dados de especificação-Wall Covering - Type: Basic Wall: REVIGRÉS-OMNISTONE-BASE-60X60-SOFT-ROPE
IFC.REVIGRÉS-Dados geométricos-Wall Covering - Type: Basic Wall: REVIGRÉS-OMNISTONE-BASE-60X60-SOFT-ROPE
IFC.REVIGRÉS-Dados de sustentabilidade-Wall Covering - Type: Basic Wall: REVIGRÉS-OMNISTONE-BASE-60X60-SOFT-ROPE

# IfcWallStandardCase: Basic Wall:REVIGRÉS-OMNISTONE-BASE-90X90-MATTRECT-BONE, Basic Wall:REVIGRÉS-OMNISTONE-BASE-90X90-MATTRECT-BONE:146395
In: Level 1
Type - PredefinedType: STANDARD; Material: REVIGRÉS-OMNISTONE-BASE-90x90-MATTRECT-BONE 10.5 mm
Type - Pset_ElementShading - Roughness: 304.8 mm
Type - Pset_ManufacturerTypeInformation - Manufacturer: REVIGRÉS
Type - Pset_ProductRequirements - Category: Walls
Type - Pset_QuantityTakeOff - Reference: 312BK788U1
Type - Pset_ReinforcementBarPitchOfWall - Description: Stone effect in wall and floor porcelain tile; Reference: 312BK788U1
Type - Pset_WallCommon - IsExternal: no; Reference: 312BK788U1
Type - IFC.REVIGRÉS-Dados do fabricante-Wall Covering - FabricanteURL: https://www.revigres.pt/; ReferenciaModelo: Omnistone; NumeroGlobalDeItemComercial: 312BK788U1; Acabamento: MATT RECT; Material: Grés porcelânico; IdentificadorDoOperadorEconomico: 501840856; UrlFabricanteArtigo: https://www.revigres.pt/colecoes/omnistone; PaisOrigem: Portugal
Type - IFC.REVIGRÉS-Dados de desempenho-Wall Covering - Rectilinearidade: ± 0.2% máx.± 0.8 mm; Ortogonalidade: ± 0.2% máx.± 1.5 mm; PlanaridadeDaSuperficie: ± 0.3% máx. ± 1.8 mm; QualidadeDaSuperficie: Cumpre; AbsorcaoDeAgua: < 0.05%; ModuloDeRuptura: > 45 N/mm130; ResistenciaAFlexao: ≥ 3500 N; ResistenciaAAbrasaoProfunda: < 120 mm131; DilatacaoTermicaLinear: ≤ 8,0x10-6 °C-1; ResistenciaAoChoqueTermico: Resiste; DurabilidadeResistenciaAoGeloDegelo: Resiste; ResistenciaAoEscorregamentoDIN51130: R10; ResistenciaAoEscorregamentoDIN51097: B; ResistenciaAoEscorregamentoENV51097: B; ResistenciaAoEscorregamentoENV12633: Class 2; ResistenciaAoEscorregamentoBS7976: >36; ResistenciaAoEscorregamentoANSIA1371: ≥0,42; ResistenciaAoDeslizamentoENV12633: Class 2; ResistenciaAoDeslizamentoBS7976: >36; ResistenciaAsManchas: Class 5; ResistenciaABaixasConcentracoesDeAcidosEAlcalis: Classe LA; ResistenciaAAltasConcentracoesDeAcidosEAlcalis: Classe HA; LibertacaoDeCadmio: 0; LibertacaoDeChumbo: 0
Type - IFC.REVIGRÉS-Dados de especificação-Wall Covering - VariacaoTonalidade: 3; NivelDeTrafego: 5; EPavimento: Sim; ERevestimento: Sim; EExterno: Sim
Type - IFC.REVIGRÉS-Dados geométricos-Wall Covering - AlturaNominal: 10.5 mm; ComprimentoNominal: 88.9 mm; LarguraNominal: 88.9 mm
Type - IFC.REVIGRÉS-Dados de sustentabilidade-Wall Covering - ItemEParcialmenteReciclado: 0; PotencialPrivacaoDeAguaConsumoDeAguaPonderado: 4.5; EnergiaTermicaExportada: 0; ItemENovo: Sim; ItemEReciclado: Não; VidaÚtilEsperada: 50; SubstanciasPerigosas: Não; PotencialDeEsgotamentoAbioticoDosRecursosNaoFosseisMineraisEMetais: 0.000701; PotencialDeAquecimentoGlobalBiogenico: -0.48; CombustiveisFosseisComPotencialDeAquecimentoGlobal: 13.9; PotencialDeAquecimentoGlobalUsoDoSoloEMudancaDeUsoDoSolo: 0.0246; PotencialDeEutrofizacaoFraccaoDeNutrientesQueAtingemOCompartimentoFinalDeAguaDoce: 0.000189; PotencialDeEutrofizacaoFraccaoDeNutrientesQueAtingemOCompartimentoFinalMarinho: 0.0122; EnergiaRecuperada: 0.00739; ConsumoDeAguaDoce: 0.113; UtilizacaoLiquidaDeAguaDoce: 0.113; ResiduosPerigososEliminados: 0.00221; ResiduosNaoPerigososEliminados: 1.83; MassaTotalDeResiduosRadioactivosEliminados: 0.000394; EnergiaElectricaExportada: 1.55; MateriaisParaRecuperacaoDeEnergia: 0.00739; MateriaisParaReciclagem: 0.0253; UnidadeEPD: 1 m²
Type - IFC.REVIGRÉS-Dados gerais-Wall Covering - Nome: REVIGRÉS-OMNISTONE-BASE-90X90-MATT RECT-BONE; TipoProduto: Prensado a seco: grupo BIa UGL | Grés porcelânico técnico; NumeroDeRegistoDAP: EPD-REV-20240006-CCC1-EN; ReferenciaDAP: -; UrlDOP: -
Pset_WallCommon - ExtendToStructure: no; LoadBearing: no
IFC.REVIGRÉS-Dados do fabricante-Wall Covering - Type: Basic Wall: REVIGRÉS-OMNISTONE-BASE-90X90-MATTRECT-BONE
IFC.REVIGRÉS-Dados de desempenho-Wall Covering - Type: Basic Wall: REVIGRÉS-OMNISTONE-BASE-90X90-MATTRECT-BONE
IFC.REVIGRÉS-Dados de especificação-Wall Covering - Type: Basic Wall: REVIGRÉS-OMNISTONE-BASE-90X90-MATTRECT-BONE
IFC.REVIGRÉS-Dados geométricos-Wall Covering - Type: Basic Wall: REVIGRÉS-OMNISTONE-BASE-90X90-MATTRECT-BONE
IFC.REVIGRÉS-Dados de sustentabilidade-Wall Covering - Type: Basic Wall: REVIGRÉS-OMNISTONE-BASE-90X90-MATTRECT-BONE

# IfcWallStandardCase: Basic Wall:REVIGRÉS-OMNISTONE-BASE-90X90-MATTRECT-ICE, Basic Wall:REVIGRÉS-OMNISTONE-BASE-90X90-MATTRECT-ICE:148458
In: Level 1
Type - PredefinedType: STANDARD; Material: REVIGRÉS-OMNISTONE-BASE-90x90-MATTRECT-ICE 10.5 mm
Type - Pset_ElementShading - Roughness: 304.8 mm
Type - Pset_ManufacturerTypeInformation - Manufacturer: REVIGRÉS
Type - Pset_ProductRequirements - Category: Walls
Type - Pset_QuantityTakeOff - Reference: 312BK789U1
Type - Pset_ReinforcementBarPitchOfWall - Description: Stone effect in wall and floor porcelain tile; Reference: 312BK789U1
Type - Pset_WallCommon - IsExternal: no; Reference: 312BK789U1
Type - IFC.REVIGRÉS-Dados do fabricante-Wall Covering - FabricanteURL: https://www.revigres.pt/; ReferenciaModelo: Omnistone; NumeroGlobalDeItemComercial: 312BK789U1; Acabamento: MATT RECT; Material: Grés porcelânico; IdentificadorDoOperadorEconomico: 501840856; UrlFabricanteArtigo: https://www.revigres.pt/colecoes/omnistone; PaisOrigem: Portugal
Type - IFC.REVIGRÉS-Dados de desempenho-Wall Covering - Rectilinearidade: ± 0.2% máx.± 0.8 mm; Ortogonalidade: ± 0.2% máx.± 1.5 mm; PlanaridadeDaSuperficie: ± 0.3% máx. ± 1.8 mm; QualidadeDaSuperficie: Cumpre; AbsorcaoDeAgua: < 0.05%; ModuloDeRuptura: > 45 N/mm130; ResistenciaAFlexao: ≥ 3500 N; ResistenciaAAbrasaoProfunda: < 120 mm131; DilatacaoTermicaLinear: ≤ 8,0x10-6 °C-1; ResistenciaAoChoqueTermico: Resiste; DurabilidadeResistenciaAoGeloDegelo: Resiste; ResistenciaAoEscorregamentoDIN51130: R10; ResistenciaAoEscorregamentoDIN51097: B; ResistenciaAoEscorregamentoENV51097: B; ResistenciaAoEscorregamentoENV12633: Class 2; ResistenciaAoEscorregamentoBS7976: >36; ResistenciaAoEscorregamentoANSIA1371: ≥0,42; ResistenciaAoDeslizamentoENV12633: Class 2; ResistenciaAoDeslizamentoBS7976: >36; ResistenciaAsManchas: Class 5; ResistenciaABaixasConcentracoesDeAcidosEAlcalis: Classe LA; ResistenciaAAltasConcentracoesDeAcidosEAlcalis: Classe HA; LibertacaoDeCadmio: 0; LibertacaoDeChumbo: 0
Type - IFC.REVIGRÉS-Dados de especificação-Wall Covering - VariacaoTonalidade: 3; NivelDeTrafego: 5; EPavimento: Sim; ERevestimento: Sim; EExterno: Sim
Type - IFC.REVIGRÉS-Dados geométricos-Wall Covering - AlturaNominal: 10.5 mm; ComprimentoNominal: 88.9 mm; LarguraNominal: 88.9 mm
Type - IFC.REVIGRÉS-Dados de sustentabilidade-Wall Covering - ItemEParcialmenteReciclado: 0; PotencialPrivacaoDeAguaConsumoDeAguaPonderado: 4.5; EnergiaTermicaExportada: 0; ItemENovo: Sim; ItemEReciclado: Não; VidaÚtilEsperada: 50; SubstanciasPerigosas: Não; PotencialDeEsgotamentoAbioticoDosRecursosNaoFosseisMineraisEMetais: 0.000701; PotencialDeAquecimentoGlobalBiogenico: -0.48; CombustiveisFosseisComPotencialDeAquecimentoGlobal: 13.9; PotencialDeAquecimentoGlobalUsoDoSoloEMudancaDeUsoDoSolo: 0.0246; PotencialDeEutrofizacaoFraccaoDeNutrientesQueAtingemOCompartimentoFinalDeAguaDoce: 0.000189; PotencialDeEutrofizacaoFraccaoDeNutrientesQueAtingemOCompartimentoFinalMarinho: 0.0122; EnergiaRecuperada: 0.00739; ConsumoDeAguaDoce: 0.113; UtilizacaoLiquidaDeAguaDoce: 0.113; ResiduosPerigososEliminados: 0.00221; ResiduosNaoPerigososEliminados: 1.83; MassaTotalDeResiduosRadioactivosEliminados: 0.000394; EnergiaElectricaExportada: 1.55; MateriaisParaRecuperacaoDeEnergia: 0.00739; MateriaisParaReciclagem: 0.0253; UnidadeEPD: 1 m²
Type - IFC.REVIGRÉS-Dados gerais-Wall Covering - Nome: REVIGRÉS-OMNISTONE-BASE-90X90-MATT RECT-ICE; TipoProduto: Prensado a seco: grupo BIa UGL | Grés porcelânico técnico; NumeroDeRegistoDAP: EPD-REV-20240006-CCC1-EN; ReferenciaDAP: -; UrlDOP: -
Pset_WallCommon - ExtendToStructure: no; LoadBearing: no
IFC.REVIGRÉS-Dados do fabricante-Wall Covering - Type: Basic Wall: REVIGRÉS-OMNISTONE-BASE-90X90-MATTRECT-ICE
IFC.REVIGRÉS-Dados de desempenho-Wall Covering - Type: Basic Wall: REVIGRÉS-OMNISTONE-BASE-90X90-MATTRECT-ICE
IFC.REVIGRÉS-Dados de especificação-Wall Covering - Type: Basic Wall: REVIGRÉS-OMNISTONE-BASE-90X90-MATTRECT-ICE
IFC.REVIGRÉS-Dados geométricos-Wall Covering - Type: Basic Wall: REVIGRÉS-OMNISTONE-BASE-90X90-MATTRECT-ICE
IFC.REVIGRÉS-Dados de sustentabilidade-Wall Covering - Type: Basic Wall: REVIGRÉS-OMNISTONE-BASE-90X90-MATTRECT-ICE

# IfcWallStandardCase: Basic Wall:REVIGRÉS-OMNISTONE-BASE-90X90-MATTRECT-IRON, Basic Wall:REVIGRÉS-OMNISTONE-BASE-90X90-MATTRECT-IRON:149149
In: Level 1
Type - PredefinedType: STANDARD; Material: REVIGRÉS-OMNISTONE-BASE-90x90-MATTRECT-IRON 10.5 mm
Type - Pset_ElementShading - Roughness: 304.8 mm
Type - Pset_ManufacturerTypeInformation - Manufacturer: REVIGRÉS
Type - Pset_ProductRequirements - Category: Walls
Type - Pset_QuantityTakeOff - Reference: 312BK790U1
Type - Pset_ReinforcementBarPitchOfWall - Description: Stone effect in wall and floor porcelain tile; Reference: 312BK790U1
Type - Pset_WallCommon - IsExternal: no; Reference: 312BK790U1
Type - IFC.REVIGRÉS-Dados do fabricante-Wall Covering - FabricanteURL: https://www.revigres.pt/; ReferenciaModelo: Omnistone; NumeroGlobalDeItemComercial: 312BK790U1; Acabamento: MATT RECT; Material: Grés porcelânico; IdentificadorDoOperadorEconomico: 501840856; UrlFabricanteArtigo: https://www.revigres.pt/colecoes/omnistone; PaisOrigem: Portugal
Type - IFC.REVIGRÉS-Dados de desempenho-Wall Covering - Rectilinearidade: ± 0.2% máx.± 0.8 mm; Ortogonalidade: ± 0.2% máx.± 1.5 mm; PlanaridadeDaSuperficie: ± 0.3% máx. ± 1.8 mm; QualidadeDaSuperficie: Cumpre; AbsorcaoDeAgua: < 0.05%; ModuloDeRuptura: > 45 N/mm130; ResistenciaAFlexao: ≥ 3500 N; ResistenciaAAbrasaoProfunda: < 120 mm131; DilatacaoTermicaLinear: ≤ 8,0x10-6 °C-1; ResistenciaAoChoqueTermico: Resiste; DurabilidadeResistenciaAoGeloDegelo: Resiste; ResistenciaAoEscorregamentoDIN51130: R10; ResistenciaAoEscorregamentoDIN51097: B; ResistenciaAoEscorregamentoENV51097: B; ResistenciaAoEscorregamentoENV12633: Class 2; ResistenciaAoEscorregamentoBS7976: >36; ResistenciaAoEscorregamentoANSIA1371: ≥0,42; ResistenciaAoDeslizamentoENV12633: Class 2; ResistenciaAoDeslizamentoBS7976: >36; ResistenciaAsManchas: Class 5; ResistenciaABaixasConcentracoesDeAcidosEAlcalis: Classe LA; ResistenciaAAltasConcentracoesDeAcidosEAlcalis: Classe HA; LibertacaoDeCadmio: 0; LibertacaoDeChumbo: 0
Type - IFC.REVIGRÉS-Dados de especificação-Wall Covering - VariacaoTonalidade: 3; NivelDeTrafego: 5; EPavimento: Sim; ERevestimento: Sim; EExterno: Sim
Type - IFC.REVIGRÉS-Dados geométricos-Wall Covering - AlturaNominal: 10.5 mm; ComprimentoNominal: 88.9 mm; LarguraNominal: 88.9 mm
Type - IFC.REVIGRÉS-Dados de sustentabilidade-Wall Covering - PotencialPrivacaoDeAguaConsumoDeAguaPonderado: 4.5; EnergiaTermicaExportada: 0; ItemENovo: Sim; ItemEParcialmenteReciclado: 0.14; ItemEReciclado: Sim; VidaÚtilEsperada: 50; SubstanciasPerigosas: Não; PotencialDeEsgotamentoAbioticoDosRecursosNaoFosseisMineraisEMetais: 0.000701; PotencialDeAquecimentoGlobalBiogenico: -0.48; CombustiveisFosseisComPotencialDeAquecimentoGlobal: 13.9; PotencialDeAquecimentoGlobalUsoDoSoloEMudancaDeUsoDoSolo: 0.0246; PotencialDeEutrofizacaoFraccaoDeNutrientesQueAtingemOCompartimentoFinalDeAguaDoce: 0.000189; PotencialDeEutrofizacaoFraccaoDeNutrientesQueAtingemOCompartimentoFinalMarinho: 0.0122; EnergiaRecuperada: 0.00739; ConsumoDeAguaDoce: 0.113; UtilizacaoLiquidaDeAguaDoce: 0.113; ResiduosPerigososEliminados: 0.00221; ResiduosNaoPerigososEliminados: 1.83; MassaTotalDeResiduosRadioactivosEliminados: 0.000394; EnergiaElectricaExportada: 1.55; MateriaisParaRecuperacaoDeEnergia: 0.00739; MateriaisParaReciclagem: 0.0253; UnidadeEPD: 1 m²
Type - IFC.REVIGRÉS-Dados gerais-Wall Covering - Nome: REVIGRÉS-OMNISTONE-BASE-90X90-MATT RECT-IRON; TipoProduto: Prensado a seco: grupo BIa UGL | Grés porcelânico técnico; NumeroDeRegistoDAP: EPD-REV-20240006-CCC1-EN; ReferenciaDAP: -; UrlDOP: -
Pset_WallCommon - ExtendToStructure: no; LoadBearing: no
IFC.REVIGRÉS-Dados do fabricante-Wall Covering - Type: Basic Wall: REVIGRÉS-OMNISTONE-BASE-90X90-MATTRECT-IRON
IFC.REVIGRÉS-Dados de desempenho-Wall Covering - Type: Basic Wall: REVIGRÉS-OMNISTONE-BASE-90X90-MATTRECT-IRON
IFC.REVIGRÉS-Dados de especificação-Wall Covering - Type: Basic Wall: REVIGRÉS-OMNISTONE-BASE-90X90-MATTRECT-IRON
IFC.REVIGRÉS-Dados geométricos-Wall Covering - Type: Basic Wall: REVIGRÉS-OMNISTONE-BASE-90X90-MATTRECT-IRON
IFC.REVIGRÉS-Dados de sustentabilidade-Wall Covering - Type: Basic Wall: REVIGRÉS-OMNISTONE-BASE-90X90-MATTRECT-IRON

# IfcWallStandardCase: Basic Wall:REVIGRÉS-OMNISTONE-BASE-90X90-MATTRECT-JET, Basic Wall:REVIGRÉS-OMNISTONE-BASE-90X90-MATTRECT-JET:149891
In: Level 1
Type - PredefinedType: STANDARD; Material: REVIGRÉS-OMNISTONE-BASE-90x90-MATTRECT-JET 10.5 mm
Type - Pset_ElementShading - Roughness: 304.8 mm
Type - Pset_ManufacturerTypeInformation - Manufacturer: REVIGRÉS
Type - Pset_ProductRequirements - Category: Walls
Type - Pset_QuantityTakeOff - Reference: 312BK791U1
Type - Pset_ReinforcementBarPitchOfWall - Description: Stone effect in wall and floor porcelain tile; Reference: 312BK791U1
Type - Pset_WallCommon - IsExternal: no; Reference: 312BK791U1
Type - IFC.REVIGRÉS-Dados do fabricante-Wall Covering - FabricanteURL: https://www.revigres.pt/; ReferenciaModelo: Omnistone; NumeroGlobalDeItemComercial: 312BK791U1; Acabamento: MATT RECT; Material: Grés porcelânico; IdentificadorDoOperadorEconomico: 501840856; UrlFabricanteArtigo: https://www.revigres.pt/colecoes/omnistone; PaisOrigem: Portugal
Type - IFC.REVIGRÉS-Dados de desempenho-Wall Covering - Rectilinearidade: ± 0.2% máx.± 0.8 mm; Ortogonalidade: ± 0.2% máx.± 1.5 mm; PlanaridadeDaSuperficie: ± 0.3% máx. ± 1.8 mm; QualidadeDaSuperficie: Cumpre; AbsorcaoDeAgua: < 0.05%; ModuloDeRuptura: > 45 N/mm130; ResistenciaAFlexao: ≥ 3500 N; ResistenciaAAbrasaoProfunda: < 120 mm131; DilatacaoTermicaLinear: ≤ 8,0x10-6 °C-1; ResistenciaAoChoqueTermico: Resiste; DurabilidadeResistenciaAoGeloDegelo: Resiste; ResistenciaAoEscorregamentoDIN51130: R10; ResistenciaAoEscorregamentoDIN51097: B; ResistenciaAoEscorregamentoENV51097: B; ResistenciaAoEscorregamentoENV12633: Class 2; ResistenciaAoEscorregamentoBS7976: >36; ResistenciaAoEscorregamentoANSIA1371: ≥0,42; ResistenciaAoDeslizamentoENV12633: Class 2; ResistenciaAoDeslizamentoBS7976: >36; ResistenciaAsManchas: Class 5; ResistenciaABaixasConcentracoesDeAcidosEAlcalis: Classe LA; ResistenciaAAltasConcentracoesDeAcidosEAlcalis: Classe HA; LibertacaoDeCadmio: 0; LibertacaoDeChumbo: 0
Type - IFC.REVIGRÉS-Dados de especificação-Wall Covering - VariacaoTonalidade: 3; NivelDeTrafego: 5; EPavimento: Sim; ERevestimento: Sim; EExterno: Sim
Type - IFC.REVIGRÉS-Dados geométricos-Wall Covering - AlturaNominal: 10.5 mm; ComprimentoNominal: 88.9 mm; LarguraNominal: 88.9 mm
Type - IFC.REVIGRÉS-Dados de sustentabilidade-Wall Covering - ItemEParcialmenteReciclado: 0; PotencialPrivacaoDeAguaConsumoDeAguaPonderado: 4.5; EnergiaTermicaExportada: 0; ItemENovo: Sim; ItemEReciclado: Não; VidaÚtilEsperada: 50; SubstanciasPerigosas: Não; PotencialDeEsgotamentoAbioticoDosRecursosNaoFosseisMineraisEMetais: 0.000701; PotencialDeAquecimentoGlobalBiogenico: -0.48; CombustiveisFosseisComPotencialDeAquecimentoGlobal: 13.9; PotencialDeAquecimentoGlobalUsoDoSoloEMudancaDeUsoDoSolo: 0.0246; PotencialDeEutrofizacaoFraccaoDeNutrientesQueAtingemOCompartimentoFinalDeAguaDoce: 0.000189; PotencialDeEutrofizacaoFraccaoDeNutrientesQueAtingemOCompartimentoFinalMarinho: 0.0122; EnergiaRecuperada: 0.00739; ConsumoDeAguaDoce: 0.113; UtilizacaoLiquidaDeAguaDoce: 0.113; ResiduosPerigososEliminados: 0.00221; ResiduosNaoPerigososEliminados: 1.83; MassaTotalDeResiduosRadioactivosEliminados: 0.000394; EnergiaElectricaExportada: 1.55; MateriaisParaRecuperacaoDeEnergia: 0.00739; MateriaisParaReciclagem: 0.0253; UnidadeEPD: 1 m²
Type - IFC.REVIGRÉS-Dados gerais-Wall Covering - Nome: REVIGRÉS-OMNISTONE-BASE-90X90-MATT RECT-JET; TipoProduto: Prensado a seco: grupo BIa UGL | Grés porcelânico técnico; NumeroDeRegistoDAP: EPD-REV-20240006-CCC1-EN; ReferenciaDAP: -; UrlDOP: -
Pset_WallCommon - ExtendToStructure: no; LoadBearing: no
IFC.REVIGRÉS-Dados do fabricante-Wall Covering - Type: Basic Wall: REVIGRÉS-OMNISTONE-BASE-90X90-MATTRECT-JET
IFC.REVIGRÉS-Dados de desempenho-Wall Covering - Type: Basic Wall: REVIGRÉS-OMNISTONE-BASE-90X90-MATTRECT-JET
IFC.REVIGRÉS-Dados de especificação-Wall Covering - Type: Basic Wall: REVIGRÉS-OMNISTONE-BASE-90X90-MATTRECT-JET
IFC.REVIGRÉS-Dados geométricos-Wall Covering - Type: Basic Wall: REVIGRÉS-OMNISTONE-BASE-90X90-MATTRECT-JET
IFC.REVIGRÉS-Dados de sustentabilidade-Wall Covering - Type: Basic Wall: REVIGRÉS-OMNISTONE-BASE-90X90-MATTRECT-JET

# IfcWallStandardCase: Basic Wall:REVIGRÉS-OMNISTONE-BASE-90X90-MATTRECT-PLATINA, Basic Wall:REVIGRÉS-OMNISTONE-BASE-90X90-MATTRECT-PLATINA:150612
In: Level 1
Type - PredefinedType: STANDARD; Material: REVIGRÉS-OMNISTONE-BASE-90x90-MATTRECT-PLATINA 10.5 mm
Type - Pset_ElementShading - Roughness: 304.8 mm
Type - Pset_ManufacturerTypeInformation - Manufacturer: REVIGRÉS
Type - Pset_ProductRequirements - Category: Walls
Type - Pset_QuantityTakeOff - Reference: 312BK792U1
Type - Pset_ReinforcementBarPitchOfWall - Description: Stone effect in wall and floor porcelain tile; Reference: 312BK792U1
Type - Pset_WallCommon - IsExternal: no; Reference: 312BK792U1
Type - IFC.REVIGRÉS-Dados do fabricante-Wall Covering - FabricanteURL: https://www.revigres.pt/; ReferenciaModelo: Omnistone; NumeroGlobalDeItemComercial: 312BK792U1; Acabamento: MATT RECT; Material: Grés porcelânico; IdentificadorDoOperadorEconomico: 501840856; UrlFabricanteArtigo: https://www.revigres.pt/colecoes/omnistone; PaisOrigem: Portugal
Type - IFC.REVIGRÉS-Dados de desempenho-Wall Covering - Rectilinearidade: ± 0.2% máx.± 0.8 mm; Ortogonalidade: ± 0.2% máx.± 1.5 mm; PlanaridadeDaSuperficie: ± 0.3% máx. ± 1.8 mm; QualidadeDaSuperficie: Cumpre; AbsorcaoDeAgua: < 0.05%; ModuloDeRuptura: > 45 N/mm130; ResistenciaAFlexao: ≥ 3500 N; ResistenciaAAbrasaoProfunda: < 120 mm131; DilatacaoTermicaLinear: ≤ 8,0x10-6 °C-1; ResistenciaAoChoqueTermico: Resiste; DurabilidadeResistenciaAoGeloDegelo: Resiste; ResistenciaAoEscorregamentoDIN51130: R10; ResistenciaAoEscorregamentoDIN51097: B; ResistenciaAoEscorregamentoENV51097: B; ResistenciaAoEscorregamentoENV12633: Class 2; ResistenciaAoEscorregamentoBS7976: >36; ResistenciaAoEscorregamentoANSIA1371: ≥0,42; ResistenciaAoDeslizamentoENV12633: Class 2; ResistenciaAoDeslizamentoBS7976: >36; ResistenciaAsManchas: Class 5; ResistenciaABaixasConcentracoesDeAcidosEAlcalis: Classe LA; ResistenciaAAltasConcentracoesDeAcidosEAlcalis: Classe HA; LibertacaoDeCadmio: 0; LibertacaoDeChumbo: 0
Type - IFC.REVIGRÉS-Dados de especificação-Wall Covering - VariacaoTonalidade: 3; NivelDeTrafego: 5; EPavimento: Sim; ERevestimento: Sim; EExterno: Sim
Type - IFC.REVIGRÉS-Dados geométricos-Wall Covering - AlturaNominal: 10.5 mm; ComprimentoNominal: 88.9 mm; LarguraNominal: 88.9 mm
Type - IFC.REVIGRÉS-Dados de sustentabilidade-Wall Covering - ItemEParcialmenteReciclado: 0; PotencialPrivacaoDeAguaConsumoDeAguaPonderado: 4.5; EnergiaTermicaExportada: 0; ItemENovo: Sim; ItemEReciclado: Não; VidaÚtilEsperada: 50; SubstanciasPerigosas: Não; PotencialDeEsgotamentoAbioticoDosRecursosNaoFosseisMineraisEMetais: 0.000701; PotencialDeAquecimentoGlobalBiogenico: -0.48; CombustiveisFosseisComPotencialDeAquecimentoGlobal: 13.9; PotencialDeAquecimentoGlobalUsoDoSoloEMudancaDeUsoDoSolo: 0.0246; PotencialDeEutrofizacaoFraccaoDeNutrientesQueAtingemOCompartimentoFinalDeAguaDoce: 0.000189; PotencialDeEutrofizacaoFraccaoDeNutrientesQueAtingemOCompartimentoFinalMarinho: 0.0122; EnergiaRecuperada: 0.00739; ConsumoDeAguaDoce: 0.113; UtilizacaoLiquidaDeAguaDoce: 0.113; ResiduosPerigososEliminados: 0.00221; ResiduosNaoPerigososEliminados: 1.83; MassaTotalDeResiduosRadioactivosEliminados: 0.000394; EnergiaElectricaExportada: 1.55; MateriaisParaRecuperacaoDeEnergia: 0.00739; MateriaisParaReciclagem: 0.0253; UnidadeEPD: 1 m²
Type - IFC.REVIGRÉS-Dados gerais-Wall Covering - Nome: REVIGRÉS-OMNISTONE-BASE-90X90-MATT RECT-PLATINA; TipoProduto: Prensado a seco: grupo BIa UGL | Grés porcelânico técnico; NumeroDeRegistoDAP: EPD-REV-20240006-CCC1-EN; ReferenciaDAP: -; UrlDOP: -
Pset_WallCommon - ExtendToStructure: no; LoadBearing: no
IFC.REVIGRÉS-Dados do fabricante-Wall Covering - Type: Basic Wall: REVIGRÉS-OMNISTONE-BASE-90X90-MATTRECT-PLATINA
IFC.REVIGRÉS-Dados de desempenho-Wall Covering - Type: Basic Wall: REVIGRÉS-OMNISTONE-BASE-90X90-MATTRECT-PLATINA
IFC.REVIGRÉS-Dados de especificação-Wall Covering - Type: Basic Wall: REVIGRÉS-OMNISTONE-BASE-90X90-MATTRECT-PLATINA
IFC.REVIGRÉS-Dados geométricos-Wall Covering - Type: Basic Wall: REVIGRÉS-OMNISTONE-BASE-90X90-MATTRECT-PLATINA
IFC.REVIGRÉS-Dados de sustentabilidade-Wall Covering - Type: Basic Wall: REVIGRÉS-OMNISTONE-BASE-90X90-MATTRECT-PLATINA

# IfcWallStandardCase: Basic Wall:REVIGRÉS-OMNISTONE-BASE-90X90-MATTRECT-ROPE, Basic Wall:REVIGRÉS-OMNISTONE-BASE-90X90-MATTRECT-ROPE:151317
In: Level 1
Type - PredefinedType: STANDARD; Material: REVIGRÉS-OMNISTONE-BASE-90x90-MATTRECT-ROPE 10.5 mm
Type - Pset_ElementShading - Roughness: 304.8 mm
Type - Pset_ManufacturerTypeInformation - Manufacturer: REVIGRÉS
Type - Pset_ProductRequirements - Category: Walls
Type - Pset_QuantityTakeOff - Reference: 312BK793U1
Type - Pset_ReinforcementBarPitchOfWall - Description: Stone effect in wall and floor porcelain tile; Reference: 312BK793U1
Type - Pset_WallCommon - IsExternal: no; Reference: 312BK793U1
Type - IFC.REVIGRÉS-Dados do fabricante-Wall Covering - FabricanteURL: https://www.revigres.pt/; ReferenciaModelo: Omnistone; NumeroGlobalDeItemComercial: 312BK793U1; Acabamento: MATT RECT; Material: Grés porcelânico; IdentificadorDoOperadorEconomico: 501840856; UrlFabricanteArtigo: https://www.revigres.pt/colecoes/omnistone; PaisOrigem: Portugal
Type - IFC.REVIGRÉS-Dados de desempenho-Wall Covering - Rectilinearidade: ± 0.2% máx.± 0.8 mm; Ortogonalidade: ± 0.2% máx.± 1.5 mm; PlanaridadeDaSuperficie: ± 0.3% máx. ± 1.8 mm; QualidadeDaSuperficie: Cumpre; AbsorcaoDeAgua: < 0.05%; ModuloDeRuptura: > 45 N/mm130; ResistenciaAFlexao: ≥ 3500 N; ResistenciaAAbrasaoProfunda: < 120 mm131; DilatacaoTermicaLinear: ≤ 8,0x10-6 °C-1; ResistenciaAoChoqueTermico: Resiste; DurabilidadeResistenciaAoGeloDegelo: Resiste; ResistenciaAoEscorregamentoDIN51130: R10; ResistenciaAoEscorregamentoDIN51097: B; ResistenciaAoEscorregamentoENV51097: B; ResistenciaAoEscorregamentoENV12633: Class 2; ResistenciaAoEscorregamentoBS7976: >36; ResistenciaAoEscorregamentoANSIA1371: ≥0,42; ResistenciaAoDeslizamentoENV12633: Class 2; ResistenciaAoDeslizamentoBS7976: >36; ResistenciaAsManchas: Class 5; ResistenciaABaixasConcentracoesDeAcidosEAlcalis: Classe LA; ResistenciaAAltasConcentracoesDeAcidosEAlcalis: Classe HA; LibertacaoDeCadmio: 0; LibertacaoDeChumbo: 0
Type - IFC.REVIGRÉS-Dados de especificação-Wall Covering - VariacaoTonalidade: 3; NivelDeTrafego: 5; EPavimento: Sim; ERevestimento: Sim; EExterno: Sim
Type - IFC.REVIGRÉS-Dados geométricos-Wall Covering - AlturaNominal: 10.5 mm; ComprimentoNominal: 88.9 mm; LarguraNominal: 88.9 mm
Type - IFC.REVIGRÉS-Dados de sustentabilidade-Wall Covering - ItemEParcialmenteReciclado: 0; PotencialPrivacaoDeAguaConsumoDeAguaPonderado: 4.5; EnergiaTermicaExportada: 0; ItemENovo: Sim; ItemEReciclado: Não; VidaÚtilEsperada: 50; SubstanciasPerigosas: Não; PotencialDeEsgotamentoAbioticoDosRecursosNaoFosseisMineraisEMetais: 0.000701; PotencialDeAquecimentoGlobalBiogenico: -0.48; CombustiveisFosseisComPotencialDeAquecimentoGlobal: 13.9; PotencialDeAquecimentoGlobalUsoDoSoloEMudancaDeUsoDoSolo: 0.0246; PotencialDeEutrofizacaoFraccaoDeNutrientesQueAtingemOCompartimentoFinalDeAguaDoce: 0.000189; PotencialDeEutrofizacaoFraccaoDeNutrientesQueAtingemOCompartimentoFinalMarinho: 0.0122; EnergiaRecuperada: 0.00739; ConsumoDeAguaDoce: 0.113; UtilizacaoLiquidaDeAguaDoce: 0.113; ResiduosPerigososEliminados: 0.00221; ResiduosNaoPerigososEliminados: 1.83; MassaTotalDeResiduosRadioactivosEliminados: 0.000394; EnergiaElectricaExportada: 1.55; MateriaisParaRecuperacaoDeEnergia: 0.00739; MateriaisParaReciclagem: 0.0253; UnidadeEPD: 1 m²
Type - IFC.REVIGRÉS-Dados gerais-Wall Covering - Nome: REVIGRÉS-OMNISTONE-BASE-90X90-MATT RECT-ROPE; TipoProduto: Prensado a seco: grupo BIa UGL | Grés porcelânico técnico; NumeroDeRegistoDAP: EPD-REV-20240006-CCC1-EN; ReferenciaDAP: -; UrlDOP: -
Pset_WallCommon - ExtendToStructure: no; LoadBearing: no
IFC.REVIGRÉS-Dados do fabricante-Wall Covering - Type: Basic Wall: REVIGRÉS-OMNISTONE-BASE-90X90-MATTRECT-ROPE
IFC.REVIGRÉS-Dados de desempenho-Wall Covering - Type: Basic Wall: REVIGRÉS-OMNISTONE-BASE-90X90-MATTRECT-ROPE
IFC.REVIGRÉS-Dados de especificação-Wall Covering - Type: Basic Wall: REVIGRÉS-OMNISTONE-BASE-90X90-MATTRECT-ROPE
IFC.REVIGRÉS-Dados geométricos-Wall Covering - Type: Basic Wall: REVIGRÉS-OMNISTONE-BASE-90X90-MATTRECT-ROPE
IFC.REVIGRÉS-Dados de sustentabilidade-Wall Covering - Type: Basic Wall: REVIGRÉS-OMNISTONE-BASE-90X90-MATTRECT-ROPE

# IfcWallStandardCase: Basic Wall:REVIGRÉS-OMNISTONE-BASE-90X90-SOFT-BONE, Basic Wall:REVIGRÉS-OMNISTONE-BASE-90X90-SOFT-BONE:146535
In: Level 1
Type - PredefinedType: STANDARD; Material: REVIGRÉS-OMNISTONE-BASE-90x90-SOFT-BONE 10.5 mm
Type - Pset_ElementShading - Roughness: 304.8 mm
Type - Pset_ManufacturerTypeInformation - Manufacturer: REVIGRÉS
Type - Pset_ProductRequirements - Category: Walls
Type - Pset_QuantityTakeOff - Reference: 3126K788U1
Type - Pset_ReinforcementBarPitchOfWall - Description: Stone effect in wall and floor porcelain tile; Reference: 3126K788U1
Type - Pset_WallCommon - IsExternal: no; Reference: 3126K788U1
Type - IFC.REVIGRÉS-Dados do fabricante-Wall Covering - FabricanteURL: https://www.revigres.pt/; ReferenciaModelo: Omnistone; NumeroGlobalDeItemComercial: 3126K788U1; Acabamento: SOFT; Material: Grés porcelânico; IdentificadorDoOperadorEconomico: 501840856; UrlFabricanteArtigo: https://www.revigres.pt/colecoes/omnistone; PaisOrigem: Portugal
Type - IFC.REVIGRÉS-Dados de desempenho-Wall Covering - Rectilinearidade: ± 0.2% máx.± 0.8 mm; Ortogonalidade: ± 0.2% máx.± 1.5 mm; PlanaridadeDaSuperficie: ± 0.3% máx. ± 1.8 mm; QualidadeDaSuperficie: Cumpre; AbsorcaoDeAgua: < 0.05%; ModuloDeRuptura: > 45 N/mm130; ResistenciaAFlexao: ≥ 3500 N; ResistenciaAAbrasaoProfunda: < 120 mm131; DilatacaoTermicaLinear: ≤ 8,0x10-6 °C-1; ResistenciaAoChoqueTermico: Resiste; DurabilidadeResistenciaAoGeloDegelo: Resiste; ResistenciaAsManchas: Class 5; ResistenciaABaixasConcentracoesDeAcidosEAlcalis: Classe LA; ResistenciaAAltasConcentracoesDeAcidosEAlcalis: Classe HA; LibertacaoDeCadmio: 0; LibertacaoDeChumbo: 0
Type - IFC.REVIGRÉS-Dados de especificação-Wall Covering - VariacaoTonalidade: 3; NivelDeTrafego: 5; EPavimento: Sim; ERevestimento: Sim; EExterno: Sim
Type - IFC.REVIGRÉS-Dados geométricos-Wall Covering - AlturaNominal: 10.5 mm; ComprimentoNominal: 88.9 mm; LarguraNominal: 88.9 mm
Type - IFC.REVIGRÉS-Dados de sustentabilidade-Wall Covering - ItemEParcialmenteReciclado: 0; PotencialPrivacaoDeAguaConsumoDeAguaPonderado: 4.5; EnergiaTermicaExportada: 0; ItemENovo: Sim; ItemEReciclado: Não; VidaÚtilEsperada: 50; SubstanciasPerigosas: Não; PotencialDeEsgotamentoAbioticoDosRecursosNaoFosseisMineraisEMetais: 0.000701; PotencialDeAquecimentoGlobalBiogenico: -0.48; CombustiveisFosseisComPotencialDeAquecimentoGlobal: 13.9; PotencialDeAquecimentoGlobalUsoDoSoloEMudancaDeUsoDoSolo: 0.0246; PotencialDeEutrofizacaoFraccaoDeNutrientesQueAtingemOCompartimentoFinalDeAguaDoce: 0.000189; PotencialDeEutrofizacaoFraccaoDeNutrientesQueAtingemOCompartimentoFinalMarinho: 0.0122; EnergiaRecuperada: 0.00739; ConsumoDeAguaDoce: 0.113; UtilizacaoLiquidaDeAguaDoce: 0.113; ResiduosPerigososEliminados: 0.00221; ResiduosNaoPerigososEliminados: 1.83; MassaTotalDeResiduosRadioactivosEliminados: 0.000394; EnergiaElectricaExportada: 1.55; MateriaisParaRecuperacaoDeEnergia: 0.00739; MateriaisParaReciclagem: 0.0253; UnidadeEPD: 1 m²
Type - IFC.REVIGRÉS-Dados gerais-Wall Covering - Nome: REVIGRÉS-OMNISTONE-BASE-90X90-SOFT-BONE; TipoProduto: Prensado a seco: grupo BIa UGL | Grés porcelânico técnico; NumeroDeRegistoDAP: EPD-REV-20240006-CCC1-EN; ReferenciaDAP: -; UrlDOP: -
Pset_WallCommon - ExtendToStructure: no; LoadBearing: no
IFC.REVIGRÉS-Dados do fabricante-Wall Covering - Type: Basic Wall: REVIGRÉS-OMNISTONE-BASE-90X90-SOFT-BONE
IFC.REVIGRÉS-Dados de desempenho-Wall Covering - Type: Basic Wall: REVIGRÉS-OMNISTONE-BASE-90X90-SOFT-BONE
IFC.REVIGRÉS-Dados de especificação-Wall Covering - Type: Basic Wall: REVIGRÉS-OMNISTONE-BASE-90X90-SOFT-BONE
IFC.REVIGRÉS-Dados geométricos-Wall Covering - Type: Basic Wall: REVIGRÉS-OMNISTONE-BASE-90X90-SOFT-BONE
IFC.REVIGRÉS-Dados de sustentabilidade-Wall Covering - Type: Basic Wall: REVIGRÉS-OMNISTONE-BASE-90X90-SOFT-BONE

# IfcWallStandardCase: Basic Wall:REVIGRÉS-OMNISTONE-BASE-90X90-SOFT-ICE, Basic Wall:REVIGRÉS-OMNISTONE-BASE-90X90-SOFT-ICE:148544
In: Level 1
Type - PredefinedType: STANDARD; Material: REVIGRÉS-OMNISTONE-BASE-90x90-SOFT-ICE 10.5 mm
Type - Pset_ElementShading - Roughness: 304.8 mm
Type - Pset_ManufacturerTypeInformation - Manufacturer: REVIGRÉS
Type - Pset_ProductRequirements - Category: Walls
Type - Pset_QuantityTakeOff - Reference: 3126K789U1
Type - Pset_ReinforcementBarPitchOfWall - Description: Stone effect in wall and floor porcelain tile; Reference: 3126K789U1
Type - Pset_WallCommon - IsExternal: no; Reference: 3126K789U1
Type - IFC.REVIGRÉS-Dados do fabricante-Wall Covering - FabricanteURL: https://www.revigres.pt/; ReferenciaModelo: Omnistone; NumeroGlobalDeItemComercial: 3126K789U1; Acabamento: SOFT; Material: Grés porcelânico; IdentificadorDoOperadorEconomico: 501840856; UrlFabricanteArtigo: https://www.revigres.pt/colecoes/omnistone; PaisOrigem: Portugal
Type - IFC.REVIGRÉS-Dados de desempenho-Wall Covering - Rectilinearidade: ± 0.2% máx.± 0.8 mm; Ortogonalidade: ± 0.2% máx.± 1.5 mm; PlanaridadeDaSuperficie: ± 0.3% máx. ± 1.8 mm; QualidadeDaSuperficie: Cumpre; AbsorcaoDeAgua: < 0.05%; ModuloDeRuptura: > 45 N/mm130; ResistenciaAFlexao: ≥ 3500 N; ResistenciaAAbrasaoProfunda: < 120 mm131; DilatacaoTermicaLinear: ≤ 8,0x10-6 °C-1; ResistenciaAoChoqueTermico: Resiste; DurabilidadeResistenciaAoGeloDegelo: Resiste; ResistenciaAsManchas: Class 5; ResistenciaABaixasConcentracoesDeAcidosEAlcalis: Classe LA; ResistenciaAAltasConcentracoesDeAcidosEAlcalis: Classe HA; LibertacaoDeCadmio: 0; LibertacaoDeChumbo: 0
Type - IFC.REVIGRÉS-Dados de especificação-Wall Covering - VariacaoTonalidade: 3; NivelDeTrafego: 5; EPavimento: Sim; ERevestimento: Sim; EExterno: Sim
Type - IFC.REVIGRÉS-Dados geométricos-Wall Covering - AlturaNominal: 10.5 mm; ComprimentoNominal: 88.9 mm; LarguraNominal: 88.9 mm
Type - IFC.REVIGRÉS-Dados de sustentabilidade-Wall Covering - ItemEParcialmenteReciclado: 0; PotencialPrivacaoDeAguaConsumoDeAguaPonderado: 4.5; EnergiaTermicaExportada: 0; ItemENovo: Sim; ItemEReciclado: Não; VidaÚtilEsperada: 50; SubstanciasPerigosas: Não; PotencialDeEsgotamentoAbioticoDosRecursosNaoFosseisMineraisEMetais: 0.000701; PotencialDeAquecimentoGlobalBiogenico: -0.48; CombustiveisFosseisComPotencialDeAquecimentoGlobal: 13.9; PotencialDeAquecimentoGlobalUsoDoSoloEMudancaDeUsoDoSolo: 0.0246; PotencialDeEutrofizacaoFraccaoDeNutrientesQueAtingemOCompartimentoFinalDeAguaDoce: 0.000189; PotencialDeEutrofizacaoFraccaoDeNutrientesQueAtingemOCompartimentoFinalMarinho: 0.0122; EnergiaRecuperada: 0.00739; ConsumoDeAguaDoce: 0.113; UtilizacaoLiquidaDeAguaDoce: 0.113; ResiduosPerigososEliminados: 0.00221; ResiduosNaoPerigososEliminados: 1.83; MassaTotalDeResiduosRadioactivosEliminados: 0.000394; EnergiaElectricaExportada: 1.55; MateriaisParaRecuperacaoDeEnergia: 0.00739; MateriaisParaReciclagem: 0.0253; UnidadeEPD: 1 m²
Type - IFC.REVIGRÉS-Dados gerais-Wall Covering - Nome: REVIGRÉS-OMNISTONE-BASE-90X90-SOFT-ICE; TipoProduto: Prensado a seco: grupo BIa UGL | Grés porcelânico técnico; NumeroDeRegistoDAP: EPD-REV-20240006-CCC1-EN; ReferenciaDAP: -; UrlDOP: -
Pset_WallCommon - ExtendToStructure: no; LoadBearing: no
IFC.REVIGRÉS-Dados do fabricante-Wall Covering - Type: Basic Wall: REVIGRÉS-OMNISTONE-BASE-90X90-SOFT-ICE
IFC.REVIGRÉS-Dados de desempenho-Wall Covering - Type: Basic Wall: REVIGRÉS-OMNISTONE-BASE-90X90-SOFT-ICE
IFC.REVIGRÉS-Dados de especificação-Wall Covering - Type: Basic Wall: REVIGRÉS-OMNISTONE-BASE-90X90-SOFT-ICE
IFC.REVIGRÉS-Dados geométricos-Wall Covering - Type: Basic Wall: REVIGRÉS-OMNISTONE-BASE-90X90-SOFT-ICE
IFC.REVIGRÉS-Dados de sustentabilidade-Wall Covering - Type: Basic Wall: REVIGRÉS-OMNISTONE-BASE-90X90-SOFT-ICE

# IfcWallStandardCase: Basic Wall:REVIGRÉS-OMNISTONE-BASE-90X90-SOFT-IRON, Basic Wall:REVIGRÉS-OMNISTONE-BASE-90X90-SOFT-IRON:149229
In: Level 1
Type - PredefinedType: STANDARD; Material: REVIGRÉS-OMNISTONE-BASE-90x90-SOFT-IRON 10.5 mm
Type - Pset_ElementShading - Roughness: 304.8 mm
Type - Pset_ManufacturerTypeInformation - Manufacturer: REVIGRÉS
Type - Pset_ProductRequirements - Category: Walls
Type - Pset_QuantityTakeOff - Reference: 3126K790U1
Type - Pset_ReinforcementBarPitchOfWall - Description: Stone effect in wall and floor porcelain tile; Reference: 3126K790U1
Type - Pset_WallCommon - IsExternal: no; Reference: 3126K790U1
Type - IFC.REVIGRÉS-Dados do fabricante-Wall Covering - FabricanteURL: https://www.revigres.pt/; ReferenciaModelo: Omnistone; NumeroGlobalDeItemComercial: 3126K790U1; Acabamento: SOFT; Material: Grés porcelânico; IdentificadorDoOperadorEconomico: 501840856; UrlFabricanteArtigo: https://www.revigres.pt/colecoes/omnistone; PaisOrigem: Portugal
Type - IFC.REVIGRÉS-Dados de desempenho-Wall Covering - Rectilinearidade: ± 0.2% máx.± 0.8 mm; Ortogonalidade: ± 0.2% máx.± 1.5 mm; PlanaridadeDaSuperficie: ± 0.3% máx. ± 1.8 mm; QualidadeDaSuperficie: Cumpre; AbsorcaoDeAgua: < 0.05%; ModuloDeRuptura: > 45 N/mm130; ResistenciaAFlexao: ≥ 3500 N; ResistenciaAAbrasaoProfunda: < 120 mm131; DilatacaoTermicaLinear: ≤ 8,0x10-6 °C-1; ResistenciaAoChoqueTermico: Resiste; DurabilidadeResistenciaAoGeloDegelo: Resiste; ResistenciaAsManchas: Class 5; ResistenciaABaixasConcentracoesDeAcidosEAlcalis: Classe LA; ResistenciaAAltasConcentracoesDeAcidosEAlcalis: Classe HA; LibertacaoDeCadmio: 0; LibertacaoDeChumbo: 0
Type - IFC.REVIGRÉS-Dados de especificação-Wall Covering - VariacaoTonalidade: 3; NivelDeTrafego: 5; EPavimento: Sim; ERevestimento: Sim; EExterno: Sim
Type - IFC.REVIGRÉS-Dados geométricos-Wall Covering - AlturaNominal: 10.5 mm; ComprimentoNominal: 88.9 mm; LarguraNominal: 88.9 mm
Type - IFC.REVIGRÉS-Dados de sustentabilidade-Wall Covering - PotencialPrivacaoDeAguaConsumoDeAguaPonderado: 4.5; EnergiaTermicaExportada: 0; ItemENovo: Sim; ItemEParcialmenteReciclado: 0.14; ItemEReciclado: Sim; VidaÚtilEsperada: 50; SubstanciasPerigosas: Não; PotencialDeEsgotamentoAbioticoDosRecursosNaoFosseisMineraisEMetais: 0.000701; PotencialDeAquecimentoGlobalBiogenico: -0.48; CombustiveisFosseisComPotencialDeAquecimentoGlobal: 13.9; PotencialDeAquecimentoGlobalUsoDoSoloEMudancaDeUsoDoSolo: 0.0246; PotencialDeEutrofizacaoFraccaoDeNutrientesQueAtingemOCompartimentoFinalDeAguaDoce: 0.000189; PotencialDeEutrofizacaoFraccaoDeNutrientesQueAtingemOCompartimentoFinalMarinho: 0.0122; EnergiaRecuperada: 0.00739; ConsumoDeAguaDoce: 0.113; UtilizacaoLiquidaDeAguaDoce: 0.113; ResiduosPerigososEliminados: 0.00221; ResiduosNaoPerigososEliminados: 1.83; MassaTotalDeResiduosRadioactivosEliminados: 0.000394; EnergiaElectricaExportada: 1.55; MateriaisParaRecuperacaoDeEnergia: 0.00739; MateriaisParaReciclagem: 0.0253; UnidadeEPD: 1 m²
Type - IFC.REVIGRÉS-Dados gerais-Wall Covering - Nome: REVIGRÉS-OMNISTONE-BASE-90X90-SOFT-IRON; TipoProduto: Prensado a seco: grupo BIa UGL | Grés porcelânico técnico; NumeroDeRegistoDAP: EPD-REV-20240006-CCC1-EN; ReferenciaDAP: -; UrlDOP: -
Pset_WallCommon - ExtendToStructure: no; LoadBearing: no
IFC.REVIGRÉS-Dados do fabricante-Wall Covering - Type: Basic Wall: REVIGRÉS-OMNISTONE-BASE-90X90-SOFT-IRON
IFC.REVIGRÉS-Dados de desempenho-Wall Covering - Type: Basic Wall: REVIGRÉS-OMNISTONE-BASE-90X90-SOFT-IRON
IFC.REVIGRÉS-Dados de especificação-Wall Covering - Type: Basic Wall: REVIGRÉS-OMNISTONE-BASE-90X90-SOFT-IRON
IFC.REVIGRÉS-Dados geométricos-Wall Covering - Type: Basic Wall: REVIGRÉS-OMNISTONE-BASE-90X90-SOFT-IRON
IFC.REVIGRÉS-Dados de sustentabilidade-Wall Covering - Type: Basic Wall: REVIGRÉS-OMNISTONE-BASE-90X90-SOFT-IRON

# IfcWallStandardCase: Basic Wall:REVIGRÉS-OMNISTONE-BASE-90X90-SOFT-JET, Basic Wall:REVIGRÉS-OMNISTONE-BASE-90X90-SOFT-JET:149971
In: Level 1
Type - PredefinedType: STANDARD; Material: REVIGRÉS-OMNISTONE-BASE-90x90-SOFT-JET 10.5 mm
Type - Pset_ElementShading - Roughness: 304.8 mm
Type - Pset_ManufacturerTypeInformation - Manufacturer: REVIGRÉS
Type - Pset_ProductRequirements - Category: Walls
Type - Pset_QuantityTakeOff - Reference: 3126K791U1
Type - Pset_ReinforcementBarPitchOfWall - Description: Stone effect in wall and floor porcelain tile; Reference: 3126K791U1
Type - Pset_WallCommon - IsExternal: no; Reference: 3126K791U1
Type - IFC.REVIGRÉS-Dados do fabricante-Wall Covering - FabricanteURL: https://www.revigres.pt/; ReferenciaModelo: Omnistone; NumeroGlobalDeItemComercial: 3126K791U1; Acabamento: SOFT; Material: Grés porcelânico; IdentificadorDoOperadorEconomico: 501840856; UrlFabricanteArtigo: https://www.revigres.pt/colecoes/omnistone; PaisOrigem: Portugal
Type - IFC.REVIGRÉS-Dados de desempenho-Wall Covering - Rectilinearidade: ± 0.2% máx.± 0.8 mm; Ortogonalidade: ± 0.2% máx.± 1.5 mm; PlanaridadeDaSuperficie: ± 0.3% máx. ± 1.8 mm; QualidadeDaSuperficie: Cumpre; AbsorcaoDeAgua: < 0.05%; ModuloDeRuptura: > 45 N/mm130; ResistenciaAFlexao: ≥ 3500 N; ResistenciaAAbrasaoProfunda: < 120 mm131; DilatacaoTermicaLinear: ≤ 8,0x10-6 °C-1; ResistenciaAoChoqueTermico: Resiste; DurabilidadeResistenciaAoGeloDegelo: Resiste; ResistenciaAsManchas: Class 5; ResistenciaABaixasConcentracoesDeAcidosEAlcalis: Classe LA; ResistenciaAAltasConcentracoesDeAcidosEAlcalis: Classe HA; LibertacaoDeCadmio: 0; LibertacaoDeChumbo: 0
Type - IFC.REVIGRÉS-Dados de especificação-Wall Covering - VariacaoTonalidade: 3; NivelDeTrafego: 5; EPavimento: Sim; ERevestimento: Sim; EExterno: Sim
Type - IFC.REVIGRÉS-Dados geométricos-Wall Covering - AlturaNominal: 10.5 mm; ComprimentoNominal: 88.9 mm; LarguraNominal: 88.9 mm
Type - IFC.REVIGRÉS-Dados de sustentabilidade-Wall Covering - ItemEParcialmenteReciclado: 0; PotencialPrivacaoDeAguaConsumoDeAguaPonderado: 4.5; EnergiaTermicaExportada: 0; ItemENovo: Sim; ItemEReciclado: Não; VidaÚtilEsperada: 50; SubstanciasPerigosas: Não; PotencialDeEsgotamentoAbioticoDosRecursosNaoFosseisMineraisEMetais: 0.000701; PotencialDeAquecimentoGlobalBiogenico: -0.48; CombustiveisFosseisComPotencialDeAquecimentoGlobal: 13.9; PotencialDeAquecimentoGlobalUsoDoSoloEMudancaDeUsoDoSolo: 0.0246; PotencialDeEutrofizacaoFraccaoDeNutrientesQueAtingemOCompartimentoFinalDeAguaDoce: 0.000189; PotencialDeEutrofizacaoFraccaoDeNutrientesQueAtingemOCompartimentoFinalMarinho: 0.0122; EnergiaRecuperada: 0.00739; ConsumoDeAguaDoce: 0.113; UtilizacaoLiquidaDeAguaDoce: 0.113; ResiduosPerigososEliminados: 0.00221; ResiduosNaoPerigososEliminados: 1.83; MassaTotalDeResiduosRadioactivosEliminados: 0.000394; EnergiaElectricaExportada: 1.55; MateriaisParaRecuperacaoDeEnergia: 0.00739; MateriaisParaReciclagem: 0.0253; UnidadeEPD: 1 m²
Type - IFC.REVIGRÉS-Dados gerais-Wall Covering - Nome: REVIGRÉS-OMNISTONE-BASE-90X90-SOFT-JET; TipoProduto: Prensado a seco: grupo BIa UGL | Grés porcelânico técnico; NumeroDeRegistoDAP: EPD-REV-20240006-CCC1-EN; ReferenciaDAP: -; UrlDOP: -
Pset_WallCommon - ExtendToStructure: no; LoadBearing: no
IFC.REVIGRÉS-Dados do fabricante-Wall Covering - Type: Basic Wall: REVIGRÉS-OMNISTONE-BASE-90X90-SOFT-JET
IFC.REVIGRÉS-Dados de desempenho-Wall Covering - Type: Basic Wall: REVIGRÉS-OMNISTONE-BASE-90X90-SOFT-JET
IFC.REVIGRÉS-Dados de especificação-Wall Covering - Type: Basic Wall: REVIGRÉS-OMNISTONE-BASE-90X90-SOFT-JET
IFC.REVIGRÉS-Dados geométricos-Wall Covering - Type: Basic Wall: REVIGRÉS-OMNISTONE-BASE-90X90-SOFT-JET
IFC.REVIGRÉS-Dados de sustentabilidade-Wall Covering - Type: Basic Wall: REVIGRÉS-OMNISTONE-BASE-90X90-SOFT-JET

# IfcWallStandardCase: Basic Wall:REVIGRÉS-OMNISTONE-BASE-90X90-SOFT-PLATINA, Basic Wall:REVIGRÉS-OMNISTONE-BASE-90X90-SOFT-PLATINA:150692
In: Level 1
Type - PredefinedType: STANDARD; Material: REVIGRÉS-OMNISTONE-BASE-90x90-SOFT-PLATINA 10.5 mm
Type - Pset_ElementShading - Roughness: 304.8 mm
Type - Pset_ManufacturerTypeInformation - Manufacturer: REVIGRÉS
Type - Pset_ProductRequirements - Category: Walls
Type - Pset_QuantityTakeOff - Reference: 3126K792U1
Type - Pset_ReinforcementBarPitchOfWall - Description: Stone effect in wall and floor porcelain tile; Reference: 3126K792U1
Type - Pset_WallCommon - IsExternal: no; Reference: 3126K792U1
Type - IFC.REVIGRÉS-Dados do fabricante-Wall Covering - FabricanteURL: https://www.revigres.pt/; ReferenciaModelo: Omnistone; NumeroGlobalDeItemComercial: 3126K792U1; Acabamento: SOFT; Material: Grés porcelânico; IdentificadorDoOperadorEconomico: 501840856; UrlFabricanteArtigo: https://www.revigres.pt/colecoes/omnistone; PaisOrigem: Portugal
Type - IFC.REVIGRÉS-Dados de desempenho-Wall Covering - Rectilinearidade: ± 0.2% máx.± 0.8 mm; Ortogonalidade: ± 0.2% máx.± 1.5 mm; PlanaridadeDaSuperficie: ± 0.3% máx. ± 1.8 mm; QualidadeDaSuperficie: Cumpre; AbsorcaoDeAgua: < 0.05%; ModuloDeRuptura: > 45 N/mm130; ResistenciaAFlexao: ≥ 3500 N; ResistenciaAAbrasaoProfunda: < 120 mm131; DilatacaoTermicaLinear: ≤ 8,0x10-6 °C-1; ResistenciaAoChoqueTermico: Resiste; DurabilidadeResistenciaAoGeloDegelo: Resiste; ResistenciaAsManchas: Class 5; ResistenciaABaixasConcentracoesDeAcidosEAlcalis: Classe LA; ResistenciaAAltasConcentracoesDeAcidosEAlcalis: Classe HA; LibertacaoDeCadmio: 0; LibertacaoDeChumbo: 0
Type - IFC.REVIGRÉS-Dados de especificação-Wall Covering - VariacaoTonalidade: 3; NivelDeTrafego: 5; EPavimento: Sim; ERevestimento: Sim; EExterno: Sim
Type - IFC.REVIGRÉS-Dados geométricos-Wall Covering - AlturaNominal: 10.5 mm; ComprimentoNominal: 88.9 mm; LarguraNominal: 88.9 mm
Type - IFC.REVIGRÉS-Dados de sustentabilidade-Wall Covering - ItemEParcialmenteReciclado: 0; PotencialPrivacaoDeAguaConsumoDeAguaPonderado: 4.5; EnergiaTermicaExportada: 0; ItemENovo: Sim; ItemEReciclado: Não; VidaÚtilEsperada: 50; SubstanciasPerigosas: Não; PotencialDeEsgotamentoAbioticoDosRecursosNaoFosseisMineraisEMetais: 0.000701; PotencialDeAquecimentoGlobalBiogenico: -0.48; CombustiveisFosseisComPotencialDeAquecimentoGlobal: 13.9; PotencialDeAquecimentoGlobalUsoDoSoloEMudancaDeUsoDoSolo: 0.0246; PotencialDeEutrofizacaoFraccaoDeNutrientesQueAtingemOCompartimentoFinalDeAguaDoce: 0.000189; PotencialDeEutrofizacaoFraccaoDeNutrientesQueAtingemOCompartimentoFinalMarinho: 0.0122; EnergiaRecuperada: 0.00739; ConsumoDeAguaDoce: 0.113; UtilizacaoLiquidaDeAguaDoce: 0.113; ResiduosPerigososEliminados: 0.00221; ResiduosNaoPerigososEliminados: 1.83; MassaTotalDeResiduosRadioactivosEliminados: 0.000394; EnergiaElectricaExportada: 1.55; MateriaisParaRecuperacaoDeEnergia: 0.00739; MateriaisParaReciclagem: 0.0253; UnidadeEPD: 1 m²
Type - IFC.REVIGRÉS-Dados gerais-Wall Covering - Nome: REVIGRÉS-OMNISTONE-BASE-90X90-SOFT-PLATINA; TipoProduto: Prensado a seco: grupo BIa UGL | Grés porcelânico técnico; NumeroDeRegistoDAP: EPD-REV-20240006-CCC1-EN; ReferenciaDAP: -; UrlDOP: -
Pset_WallCommon - ExtendToStructure: no; LoadBearing: no
IFC.REVIGRÉS-Dados do fabricante-Wall Covering - Type: Basic Wall: REVIGRÉS-OMNISTONE-BASE-90X90-SOFT-PLATINA
IFC.REVIGRÉS-Dados de desempenho-Wall Covering - Type: Basic Wall: REVIGRÉS-OMNISTONE-BASE-90X90-SOFT-PLATINA
IFC.REVIGRÉS-Dados de especificação-Wall Covering - Type: Basic Wall: REVIGRÉS-OMNISTONE-BASE-90X90-SOFT-PLATINA
IFC.REVIGRÉS-Dados geométricos-Wall Covering - Type: Basic Wall: REVIGRÉS-OMNISTONE-BASE-90X90-SOFT-PLATINA
IFC.REVIGRÉS-Dados de sustentabilidade-Wall Covering - Type: Basic Wall: REVIGRÉS-OMNISTONE-BASE-90X90-SOFT-PLATINA

# IfcWallStandardCase: Basic Wall:REVIGRÉS-OMNISTONE-BASE-90X90-SOFT-ROPE, Basic Wall:REVIGRÉS-OMNISTONE-BASE-90X90-SOFT-ROPE:151397
In: Level 1
Type - PredefinedType: STANDARD; Material: REVIGRÉS-OMNISTONE-BASE-90x90-SOFT-ROPE 10.5 mm
Type - Pset_ElementShading - Roughness: 304.8 mm
Type - Pset_ManufacturerTypeInformation - Manufacturer: REVIGRÉS
Type - Pset_ProductRequirements - Category: Walls
Type - Pset_QuantityTakeOff - Reference: 3126K793U1
Type - Pset_ReinforcementBarPitchOfWall - Description: Stone effect in wall and floor porcelain tile; Reference: 3126K793U1
Type - Pset_WallCommon - IsExternal: no; Reference: 3126K793U1
Type - IFC.REVIGRÉS-Dados do fabricante-Wall Covering - FabricanteURL: https://www.revigres.pt/; ReferenciaModelo: Omnistone; NumeroGlobalDeItemComercial: 3126K793U1; Acabamento: SOFT; Material: Grés porcelânico; IdentificadorDoOperadorEconomico: 501840856; UrlFabricanteArtigo: https://www.revigres.pt/colecoes/omnistone; PaisOrigem: Portugal
Type - IFC.REVIGRÉS-Dados de desempenho-Wall Covering - Rectilinearidade: ± 0.2% máx.± 0.8 mm; Ortogonalidade: ± 0.2% máx.± 1.5 mm; PlanaridadeDaSuperficie: ± 0.3% máx. ± 1.8 mm; QualidadeDaSuperficie: Cumpre; AbsorcaoDeAgua: < 0.05%; ModuloDeRuptura: > 45 N/mm130; ResistenciaAFlexao: ≥ 3500 N; ResistenciaAAbrasaoProfunda: < 120 mm131; DilatacaoTermicaLinear: ≤ 8,0x10-6 °C-1; ResistenciaAoChoqueTermico: Resiste; DurabilidadeResistenciaAoGeloDegelo: Resiste; ResistenciaAsManchas: Class 5; ResistenciaABaixasConcentracoesDeAcidosEAlcalis: Classe LA; ResistenciaAAltasConcentracoesDeAcidosEAlcalis: Classe HA; LibertacaoDeCadmio: 0; LibertacaoDeChumbo: 0
Type - IFC.REVIGRÉS-Dados de especificação-Wall Covering - VariacaoTonalidade: 3; NivelDeTrafego: 5; EPavimento: Sim; ERevestimento: Sim; EExterno: Sim
Type - IFC.REVIGRÉS-Dados geométricos-Wall Covering - AlturaNominal: 10.5 mm; ComprimentoNominal: 88.9 mm; LarguraNominal: 88.9 mm
Type - IFC.REVIGRÉS-Dados de sustentabilidade-Wall Covering - ItemEParcialmenteReciclado: 0; PotencialPrivacaoDeAguaConsumoDeAguaPonderado: 4.5; EnergiaTermicaExportada: 0; ItemENovo: Sim; ItemEReciclado: Não; VidaÚtilEsperada: 50; SubstanciasPerigosas: Não; PotencialDeEsgotamentoAbioticoDosRecursosNaoFosseisMineraisEMetais: 0.000701; PotencialDeAquecimentoGlobalBiogenico: -0.48; CombustiveisFosseisComPotencialDeAquecimentoGlobal: 13.9; PotencialDeAquecimentoGlobalUsoDoSoloEMudancaDeUsoDoSolo: 0.0246; PotencialDeEutrofizacaoFraccaoDeNutrientesQueAtingemOCompartimentoFinalDeAguaDoce: 0.000189; PotencialDeEutrofizacaoFraccaoDeNutrientesQueAtingemOCompartimentoFinalMarinho: 0.0122; EnergiaRecuperada: 0.00739; ConsumoDeAguaDoce: 0.113; UtilizacaoLiquidaDeAguaDoce: 0.113; ResiduosPerigososEliminados: 0.00221; ResiduosNaoPerigososEliminados: 1.83; MassaTotalDeResiduosRadioactivosEliminados: 0.000394; EnergiaElectricaExportada: 1.55; MateriaisParaRecuperacaoDeEnergia: 0.00739; MateriaisParaReciclagem: 0.0253; UnidadeEPD: 1 m²
Type - IFC.REVIGRÉS-Dados gerais-Wall Covering - Nome: REVIGRÉS-OMNISTONE-BASE-90X90-SOFT-ROPE; TipoProduto: Prensado a seco: grupo BIa UGL | Grés porcelânico técnico; NumeroDeRegistoDAP: EPD-REV-20240006-CCC1-EN; ReferenciaDAP: -; UrlDOP: -
Pset_WallCommon - ExtendToStructure: no; LoadBearing: no
IFC.REVIGRÉS-Dados do fabricante-Wall Covering - Type: Basic Wall: REVIGRÉS-OMNISTONE-BASE-90X90-SOFT-ROPE
IFC.REVIGRÉS-Dados de desempenho-Wall Covering - Type: Basic Wall: REVIGRÉS-OMNISTONE-BASE-90X90-SOFT-ROPE
IFC.REVIGRÉS-Dados de especificação-Wall Covering - Type: Basic Wall: REVIGRÉS-OMNISTONE-BASE-90X90-SOFT-ROPE
IFC.REVIGRÉS-Dados geométricos-Wall Covering - Type: Basic Wall: REVIGRÉS-OMNISTONE-BASE-90X90-SOFT-ROPE
IFC.REVIGRÉS-Dados de sustentabilidade-Wall Covering - Type: Basic Wall: REVIGRÉS-OMNISTONE-BASE-90X90-SOFT-ROPE
